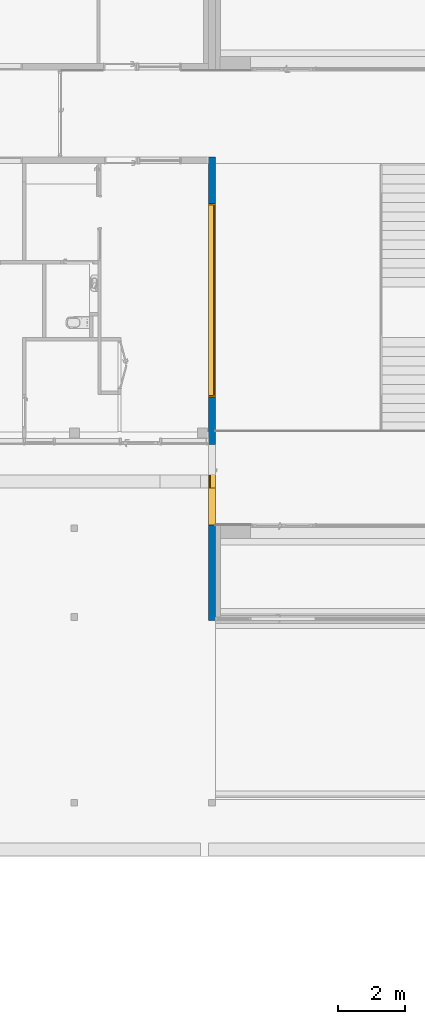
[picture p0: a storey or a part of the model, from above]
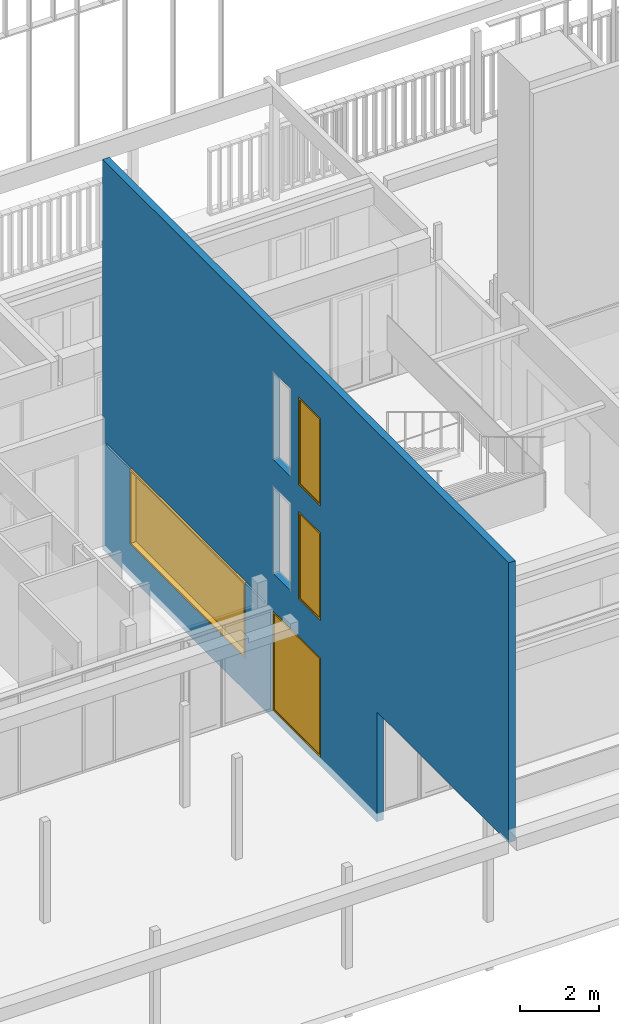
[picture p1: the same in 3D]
Properties of the parts of a building model (IFC2X3), part 1 of 7

# File
Description: ViewDefinition [CoordinationView_V2.0]
File name: Numéro du projet
Time: 2020-12-01T20:37:11
Written by: The EXPRESS Data Manager Version 5.02.0100.07 : 28 Aug 2013
Made in: 20200826_1250(x64) - Exporter 20.2.30.42 - Interface utilisateur alternative 20.2.30.42
Comment: STEP Physical File produced by: The EXPRESS Data Manager Version 5.02.0100.07 : 28 Aug 2013 * Module: EDMstepFileFactory/EDMstandAlone * Creation date: Tue Dec 01 20:37:11 2020 * Host: maison * Database: C:\Users\brice\AppData\Local\Temp\8cd85e15-69f3-489f-a026-4a7cd0e4a3fb\f1d647b6-ae90-4e52-87e3-ca53c4ba78e8\ifc * Database version: 5507 * Database creation date: Tue Dec 01 20:32:03 2020 * Schema: IFC2X3 * Model: DataRepository.ifc * Model creation date: Tue Dec 01 20:32:05 2020 * Header model: DataRepository.ifc_HeaderModel * Header model creation date: Tue Dec 01 20:32:05 2020 * EDMuser: sdai-user * EDMgroup: sdai-group * License ID and type: 5605 : Permanent license. Expiry date: * EDMstepFileFactory options: 020000

# IfcProject, Numéro du projet
LongName: Nom du projet; Phase: Etat du projet

# IfcSite, Default
RefLatitude: 48, 26, 3, 478088; RefLongitude: -4, -37, -16, -967468; RefElevation: 9400 cm

# IfcBuilding
Pset_BuildingCommon - NumberOfStoreys: 13

# IfcBuildingStorey: Niveau:Ligne du Niveau (10)
Name | LongName | Elevation (cm)
Vide Sanitaire | Vide Sanitaire | -234.674
Toiture - Infirmerie | Toiture - Infirmerie | 317.5
TR - TECHNIQUE RDC | TR - TECHNIQUE RDC | 349
TR - Cuisine/préau | TR - Cuisine/préau | 375
Toiture - Cuisine | Toiture - Cuisine | 422
Toiture - Maintenance | Toiture - Maintenance | 490
TR - TECHNIQUE R+1 | TR - TECHNIQUE R+1 | 618.22
SAM - Toiture | SAM - Toiture | 740
TR - N02 - ARCH | TR - N02 - ARCH | 774
TR - N03 - ARCH | TR - N03 - ARCH | 1230

# IfcBuildingStorey: Niveau:Ligne du Niveau 2, TR - N03
LongName: TR - N03; Elevation: 1177 cm

# IfcBuildingStorey: Niveau:Niveau 1, N00 - COO
LongName: N00 - COO; Elevation: 0 cm

# IfcSpace (202)
InteriorOrExteriorSpace: INTERNAL
Name | In | LongName | Reference | FloorCovering | WallCovering | CeilingCovering
E-10 | N00 - COO | Chaufferie | Chaufferie E-10 | Béton | Peinture lessivable
A-11 | TR - N02 - ARCH | Salle de musique | Salle de musique A-11 | Sol textile | Paroi béton lasuré+Peinture+bois acoustique | Dalle acoustique en laine de bois + retombée placo
A-14 | TR - N02 - ARCH | Dépôt Arts paratagé | Dépôt Arts paratagé A-14 | Sol linoleum | Peinture | Dalle acoustique en laine de bois
A-12 | TR - N02 - ARCH | Dépôt de musique | Dépôt de musique A-12 | Sol linoleum | Peinture | Dalle acoustique en laine de bois + retombée placo
A-13 | TR - N02 - ARCH | Salle d'arts partagés | Salle d'arts partagés A-13 | Sol linoleum | Paroi béton lasuré+Peinture+bois | Dalle acoustique en laine de bois + retombée placo
A-10 | TR - N02 - ARCH | Dépôt salle d'arts plastiques | Dépôt salle d'arts plastiques A-10 | Sol linoleum | Peinture | Dalle acoustique en laine de bois + retombée placo
A-9 | TR - N02 - ARCH | Salle d'arts plastique | Salle d'arts plastique A-9 | Sol linoleum | Paroi béton lasuré+Peinture+bois | Dalle acoustique en laine de bois + retombée placo
A-2 | TR - N02 - ARCH | Salle banalisée 1/2 groupe | Salle banalisée 1/2 groupe A-2 | Sol linoleum | Paroi béton lasuré+Peinture+bois | Dalle acoustique en laine de bois + retombée placo
E-10 | TR - N02 - ARCH | CTA 03 | CTA 03 E-10 | Béton surfacé | Peinture
A-1 | TR - N02 - ARCH | Salle banalisée 19 | Salle banalisée 19 A-1 | Sol linoleum | Paroi béton lasuré+Peinture+bois | Dalle acoustique en laine de bois + retombée placo
A-1 | TR - N02 - ARCH | Salle banalisée 18 | Salle banalisée 18 A-1 | Sol linoleum | Paroi béton lasuré+Peinture+bois | Dalle acoustique en laine de bois + retombée placo
E-10 | TR - N02 - ARCH | CTA 04 | CTA 04 E-10 | Béton surfacé | Peinture
E-10 | TR - N02 - ARCH | LT sous répartiteur 02 | LT sous répartiteur 02 E-10 | Béton | Peinture | Plafond Hygiène 60x120
E-8.6 | TR - N02 - ARCH | Local ménage 06 | Local ménage 06 E-8.6 | Carrelage | Peinture + crédence | Plafond Hygiène 60x120
B-21 | TR - N02 - ARCH | Sanitaire d'appoint 02 | Sanitaire d'appoint 02 B-21 | Carrelage | Faience toute hauteur | Plafond Hygiène 60x120
A-4 | TR - N02 - ARCH | Salle de sciences 01 | Salle de sciences 01 A-4 | Sol linoleum | Paroi béton lasuré+Peinture+bois | Dalle acoustique en laine de bois + retombée placo
A-5 | TR - N02 - ARCH | Salle de collection 01 | Salle de collection 01 A-5 | Sol linoleum | Peinture | Dalle acoustique en laine de bois + retombée placo
A-4 | TR - N02 - ARCH | Salle de sciences 02 | Salle de sciences 02 A-4 | Sol linoleum | Paroi béton lasuré+Peinture+bois | Dalle acoustique en laine de bois + retombée placo
A-4 | TR - N02 - ARCH | Salle de sciences 03 | Salle de sciences 03 A-4 | Sol linoleum | Paroi béton lasuré+Peinture+bois | Dalle acoustique en laine de bois + retombée placo
A-5 | TR - N02 - ARCH | Salle de collection 02 | Salle de collection 02 A-5 | Sol linoleum | Peinture | Dalle acoustique en laine de bois + retombée placo
A-4 | TR - N02 - ARCH | Salle de sciences 04 | Salle de sciences 04 A-4 | Sol linoleum | Paroi béton lasuré+Peinture+bois | Dalle acoustique en laine de bois + retombée placo
A-6 | TR - N02 - ARCH | Salle de technologie 02 | Salle de technologie 02 A-6 | Sol linoleum | Paroi béton lasuré+Peinture+bois | Dalle acoustique en laine de bois + retombée placo
A-6 | TR - N02 - ARCH | Salle de technologie 01 | Salle de technologie 01 A-6 | Sol linoleum | Paroi béton lasuré+Peinture+bois | Dalle acoustique en laine de bois + retombée placo
A-8 | TR - N02 - ARCH | Stockage | Stockage A-8 | Sol linoleum | Peinture | Plafond Hygiène 60x120
E-8.7 | TR - N02 - ARCH | Local ménage 07 | Local ménage 07 E-8.7 | Carrelage | Peinture + crédence | Plafond Hygiène 60x120
A-1 | Toiture - Cuisine | Salle banalisée 01 | Salle banalisée 01 A-1 | Sol linoleum | Paroi béton lasuré+Peinture+bois | Dalle acoustique en laine de bois + retombée placo
A-1 | Toiture - Cuisine | Salle banalisée 02 | Salle banalisée 02 A-1 | Sol linoleum | Paroi béton lasuré+Peinture+bois | Dalle acoustique en laine de bois + retombée placo
A-1 | Toiture - Cuisine | Salle banalisée 03 | Salle banalisée 03 A-1 | Sol linoleum | Paroi béton lasuré+Peinture+bois | Dalle acoustique en laine de bois + retombée placo
A-1 | Toiture - Cuisine | Salle banalisée 04 | Salle banalisée 04 A-1 | Sol linoleum | Paroi béton lasuré+Peinture+bois | Dalle acoustique en laine de bois + retombée placo
A-1 | Toiture - Cuisine | Salle banalisée 05 | Salle banalisée 05 A-1 | Sol linoleum | Paroi béton lasuré+Peinture+bois | Dalle acoustique en laine de bois + retombée placo
E-8.4 | Toiture - Cuisine | Local ménage 04 | Local ménage 04 E-8.4 | Carrelage | Peinture + crédence | Plafond Hygiène 60x120
B-21 | Toiture - Cuisine | Sanit. d'appoint 01 | Sanit. d'appoint 01 B-21 | Carrelage | Peinture | Plafond Hygiène 60x120
E-10 | Toiture - Cuisine | CTA 02 | CTA 02 E-10 | Béton surfacé | Peinture
A-1 | Toiture - Cuisine | Salle banalisée 07 | Salle banalisée 07 A-1 | Sol linoleum | Paroi béton lasuré+Peinture+bois | Dalle acoustique en laine de bois + retombée placo
A-1 | Toiture - Cuisine | Salle banalisée 06 | Salle banalisée 06 A-1 | Sol linoleum | Paroi béton lasuré+Peinture+bois | Dalle acoustique en laine de bois + retombée placo
E-6 | Toiture - Cuisine | Stockage général | Stockage général E-6 | Béton surfacé | Peinture
A-3 | Toiture - Cuisine | Dépôt 01 | Dépôt 01 A-3 | Sol linoleum | Peinture | Plafond Hygiène 60x120
A-1 | Toiture - Cuisine | Salle banalisée 08 | Salle banalisée 08 A-1 | Sol linoleum | Paroi béton lasuré+Peinture+bois | Dalle acoustique en laine de bois + retombée placo
A-1 | Toiture - Cuisine | Salle banalisée 09 | Salle banalisée 09 A-1 | Sol linoleum | Paroi béton lasuré+Peinture+bois | Dalle acoustique en laine de bois + retombée placo
A-1 | Toiture - Cuisine | Salle banalisée 10 | Salle banalisée 10 A-1 | Sol linoleum | Paroi béton lasuré+Peinture+bois | Dalle acoustique en laine de bois + retombée placo
A-1 | Toiture - Cuisine | Salle banalisée 11 | Salle banalisée 11 A-1 | Linoleum | Paroi béton lasuré+Peinture+bois | Dalle acoustique en laine de bois + retombée placo
A-1 | Toiture - Cuisine | Salle banalisée 12 | Salle banalisée 12 A-1 | Sol linoleum | Paroi béton lasuré+Peinture+bois | Dalle acoustique en laine de bois + retombée placo
A-1 | Toiture - Cuisine | Salle banalisée 13 | Salle banalisée 13 A-1 | Sol linoleum | Paroi béton lasuré+Peinture+bois | Dalle acoustique en laine de bois + retombée placo
A-1 | Toiture - Cuisine | Salle banalisée 17 | Salle banalisée 17 A-1 | Sol linoleum | Paroi béton lasuré+Peinture+bois | Dalle acoustique en laine de bois + retombée placo
A-1 | Toiture - Cuisine | Salle banalisée 16 | Salle banalisée 16 A-1 | Sol linoleum | Paroi béton lasuré+Peinture+bois | Dalle acoustique en laine de bois + retombée placo
A-1 | Toiture - Cuisine | Salle banalisée 15 | Salle banalisée 15 A-1 | Sol linoleum | Paroi béton lasuré+Peinture+bois | Dalle acoustique en laine de bois + retombée placo
A-1 | Toiture - Cuisine | Salle banalisée 14 | Salle banalisée 14 A-1 | Sol linoleum | Paroi béton lasuré+Peinture+bois | Dalle acoustique en laine de bois + retombée placo
A-3 | Toiture - Cuisine | Dépôt 02 | Dépôt 02 A-3 | Sol linoleum | Peinture | Plafond Hygiène 60x120
A-3 | Toiture - Cuisine | Dépôt 03 | Dépôt 03 A-3 | Sol linoleum | Peinture | Plafond Hygiène 60x120
E-8.5 | Toiture - Cuisine | Local ménage 05 | Local ménage 05 E-8.5 | Carrelage | Peinture + crédence | Plafond Hygiène 60x120
B-1 | N00 - COO | Salle de documentation | Salle de documentation B-1 | Sol textile | Paroi béton lasuré+peinture+bois | Rigitone
B-18 | N00 - COO | Foyer - Zone bruyante | Foyer - Zone bruyante B-18 | Sol béton quartz | Paroi béton lasuré+peinture+bois | Rigitone
B-3 | N00 - COO | Dépôt | Dépôt B-3 | Sol linoleum | Peinture | Dalle acoustique en laine de bois + BA13
C-4 | N00 - COO | Petite salle de réunion | Petite salle de réunion C-4 | Sol textile | Paroi béton lasuré+peinture+bois | Rigitone
C-14 | N00 - COO | Archives 01 | Archives 01 C-14 | Béton | Peinture blanche
B-6 | N00 - COO | Grande salle de permanence | Grande salle de permanence B-6 | Sol béton quartz | Paroi béton lasuré + Peinture | Dalle acoustique en laine de bois + BA13
B-7 | N00 - COO | Petite salle de permanence | Petite salle de permanence B-7 | Sol béton quartz | Paroi béton lasuré + Peinture | Dalle acoustique en laine de bois + BA13
2 x B-10 | N00 - COO | Accueil enfants malades | Accueil enfants malades B-10 | Sol textile | Peinture lessivable | Dalle acoustique en laine de bois + BA13
B-5 | N00 - COO | Bureau CPE | Bureau CPE B-5 | Sol textile | Peinture + bois pour affichage | Dalle acoustique en laine de bois + BA13
B-10 | N00 - COO | Sanitaires | Sanitaires B-10 | Carrelage | Faïence toute hauteur | Dalle acoustique en laine de bois + BA13
C-9 | N00 - COO | Secrétaire administrative | Secrétaire administrative C-9 | Sol textile | Peinture + bois pour affichage | Dalle acoustique en laine de bois + BA13
C-7 | N00 - COO | Principal adjoint | Principal adjoint C-7 | Sol textile | Peinture + bois pour affichage | Dalle acoustique en laine de bois + BA13
C-6 | N00 - COO | Principal | Principal C-6 | Sol textile | Peinture + bois pour affichage | Dalle acoustique en laine de bois + BA13
C-10 | N00 - COO | Secrétaire gestion & stagiaire | Secrétaire gestion & stagiaire C-10 | Sol textile | Peinture + bois pour affichage | Dalle acoustique en laine de bois + BA13
C-14 | N00 - COO | Archives 02 | Archives 02 C-14 | Sol linoleum | Paroi béton lasuré + Peinture | Dalle acoustique en laine de bois + BA13
E-11 | N00 - COO | Local serveur | Local serveur E-11 | Sol linoleum | Peinture | Dalle acoustique en laine de bois + BA13
C-11 | N00 - COO | Petite salle de réunion | Petite salle de réunion C-11 | Sol textile | Peinture + bois pour affichage | Dalle acoustique en laine de bois + BA13
C-12 | N00 - COO | Grande salle de réunion | Grande salle de réunion C-12 | Sol textile | Peinture + bois pour affichage | Rigitone
C-16 | N00 - COO | Local APE | Local APE C-16 | Sol textile | Peinture + bois pour affichage | Dalle acoustique en laine de bois + BA13
C-15 | N00 - COO | Rencontre parents / professeurs | Rencontre parents / professeurs C-15 | Sol textile | Peinture + bois pour affichage | Dalle acoustique en laine de bois + BA13
C-8 | N00 - COO | Gestionnaire | Gestionnaire C-8 | Sol textile | Peinture + bois pour affichage | Dalle acoustique en laine de bois + BA13
C-17 | N00 - COO | Sanit. 02 | Sanit. 02 C-17 | Carrelage | Faîence toute hauteur | Dalle acoustique en laine de bois + BA13
C-17 | N00 - COO | Sanit. 01 | Sanit. 01 C-17 | Carrelage | Faïence toute hauteur | Dalle acoustique en laine de bois + BA13
B-16 | N00 - COO | Attente | Attente B-16 | Sol textile | Peinture + bois pour affichage | Dalle acoustique en laine de bois + BA13
B-17 | N00 - COO | Sanitaires | Sanitaires B-17 | Carrelage | Faïence toute hauteur | Dalle acoustique en laine de bois + BA13
B-13 | N00 - COO | Salle de repos | Salle de repos B-13 | Sol linoleum | Peinture lessivable | Dalle acoustique en laine de bois + BA13
B-12 | N00 - COO | Bureau infirmier & espace de consultation | Bureau infirmier & espace de consultation B-12 | Sol linoleum | Peinture lessivable + crédence | Dalle acoustique en laine de bois + BA13
B-11 | N00 - COO | Bureau médecin | Bureau médecin B-11 | Sol linoleum | Peinture lessivable + crédence | Dalle acoustique en laine de bois + BA13
B-14 | N00 - COO | Bureau AS | Bureau AS B-14 | Sol textile | Peinture lessivable | Dalle acoustique en laine de bois + BA13
B-9 | N00 - COO | Dépôt grande salle de permanence | Dépôt grande salle de permanence B-9 | Béton quartz | Peinture | Dalle acoustique en laine de bois + BA13
E-10 | N00 - COO | LT / CTA 01 | LT / CTA 01 E-10 | Sol béton quartz | Peinture
F-1 | N00 - COO | SAS 05 | SAS 05 F-1 | Sol béton quartz | Paroie béton + Paroie BA 13 | Dalle en métal perforé
E-4 | N00 - COO | Stockage matériaux | Stockage matériaux E-4 | Béton quartz | Peinture lessivable | Dalle acoustique en laine de bois + BA13
E-10 | N00 - COO | TGBT | TGBT E-10 | Béton quartz | Peinture lessivable
E-1 | N00 - COO | Atelier agent de maintenance | Atelier agent de maintenance E-1 | Béton quartz | Peinture lessivable + crédence | Dalle acoustique en laine de bois + BA13
E-3 | N00 - COO | Vestiaire/Douche agent de maintenance | Vestiaire/Douche agent de maintenance E-3 | Carrelage | Faïence toute hauteur | Dalles Hygène 60x120
E-5 + E7 | N00 - COO | Garage / Stockage matériel espace verts | Garage / Stockage matériel espace verts E-5 + E7 | Béton quartz | Peinture lessivable
F-1 | N00 - COO | Circ. 04 - vestiaires élèves | Circ. 04 - vestiaires élèves F-1 | Sol béton quartz | Peinture lessivable
F-1 | N00 - COO | Circ. 05 - vestaires personnel | Circ. 05 - vestaires personnel F-1 | Béton quartz | Peinture lessivable | Dalles Couloir acoustiques
D-11 | N00 - COO | Salle de détente du personnel | Salle de détente du personnel D-11 | Béton quartz + sol textile | Peinture + crédence + bois
D-10 | N00 - COO | Local lingerie | Local lingerie D-10 | Carrelage | Faïence toute hauteur | Plafond Hygiène 60x120
A-17 | N00 - COO | Dépôt petit matériel | Dépôt petit matériel A-17 | Béton Quartz | Peinture lessivable | Plafond Hygiène 60x120
E-8.2 | N00 - COO | Local ménage / vidoire 02 | Local ménage / vidoire 02 E-8.2 | Carrelage | Peinture lessivable + crédence | Plafond Hygiène 60x120
E-9 | N00 - COO | Local produits d'entretien | Local produits d'entretien E-9 | Résine | Faïence toute hauteur
D-17 | N00 - COO | Réserve alimentaire sèche | Réserve alimentaire sèche D-17 | Résine | Faïence toute hauteur | Plafond Hygiène 60x120
D-13 | N00 - COO | Bureau magasinier | Bureau magasinier D-13 | Résine | Faïence toute hauteur | Plafond Hygiène 60x120
D-14 | N00 - COO | Local déchets | Local déchets D-14 | Résine | Faïence toute hauteur | Plafond Hygiène 60x120
D-16 | N00 - COO | Réserve petit matériel | Réserve petit matériel D-16 | Résine | Faïence toute hauteur | Plafond Hygiène 60x120
D-18 | N00 - COO | Réserve murisserie tubercules | Réserve murisserie tubercules D-18 | Résine | Faïence toute hauteur | Plafond Hygiène 60x120
D-23 / D-23 | N00 - COO | Déconditionnement / Légumerie | Déconditionnement / Légumerie D-23 / D-23 | Résine | Faïence toute hauteur | Plafond Hygiène 60x120
D-31 | N00 - COO | Stockage vaisselle propre | Stockage vaisselle propre D-31 | Résine | Faïence toute hauteur | Plafond Hygiène 60x120
D-6 | N00 - COO | Local ménage / entretien | Local ménage / entretien D-6 | Résine | Peinture lessivable | Plafond Hygiène 60x120
D-7 | N00 - COO | Salle à manger commensaux | Salle à manger commensaux D-7 | Sol textile | Peinture lessivable + bois | Rigitone
F-1 | N00 - COO | SAS 06 | SAS 06 F-1 | Tapis de sol | Peinture lessivable | Dalle béton brut
C-1 | N00 - COO | Salle des professeurs | Salle des professeurs C-1 | Sol textile + parquet | Paroi béton lasuré+peinture+bois | Rigitone
C-2 | N00 - COO | Box de travail individuel 04 | Box de travail individuel 04 C-2 | Sol textile | Peinture | Rigitone
F-1 | N00 - COO | SAS 01 | SAS 01 F-1 | Sol textile | Peinture + bois affichage | Rigitone
C-3 | N00 - COO | Reprographie | Reprographie C-3 | Sol textile | Paroi béton + Peinture+bois | Rigitone
F-1 | N00 - COO | Circ. 02 - salle des profs | Circ. 02 - salle des profs F-1 | Sol textile | Paroie BA 13 | Rigitone
C-2 | N00 - COO | Box de travail individuel 03 | Box de travail individuel 03 C-2 | Sol textile | Peinture | Rigitone
C-2 | N00 - COO | Box de travail individuel 02 | Box de travail individuel 02 C-2 | Sol textile | Peinture | Rigitone
C-2 | N00 - COO | Box de travail individuel 01 | Box de travail individuel 01 C-2 | Sol textile | Peinture | Rigitone
F-1 | N00 - COO | SAS 02 | SAS 02 F-1 | Sol textile | Peinture + bois affichage | Rigitone
F-1 | N00 - COO | Circ. 03 - administration | Circ. 03 - administration F-1 | Sol textile | Paroie béton + Paroie BA 13 | Dalle couloir acoustiques
C-13 | N00 - COO | Reprographie | Reprographie C-13 | Sol textile | Paroi béton lasuré + Peinture | Dalle acoustique en laine de bois + BA13
D-29 | N00 - COO | Laverie vaisselle | Laverie vaisselle D-29 | Résine | faience toute hauteur | Plafond Hygiène 60x120
D-1 | N00 - COO | Hall d'accueil | Hall d'accueil D-1 | Tapis de sol | Peinture lessivable + bois | Rigitone
D-28 | N00 - COO | Plonge batterie propre | Plonge batterie propre D-28 | Résine | Faïence toute hauteur | Plafond Hygiène 60x120
F-1 | N00 - COO | Circ. 08 - local ménage self | Circ. 08 - local ménage self F-1 | Résine | Peinture lessivable | Plafond Hygiène 60x120
D-3 | N00 - COO | Distribution | Distribution D-3 | Résine | faïence toute hauteur | Plafond Hygiène 60x120
D-4 | N00 - COO | Circulation devant ligne de self | Circulation devant ligne de self D-4 | Résine | Peinture lessivable / faïence | Rigitone
F-1 | N00 - COO | Circ. 06 - self | Circ. 06 - self F-1 | Résine | Faïence toute hauteur | Plafond Hygiène 60x120
D-12 | N00 - COO | Hall de réception | Hall de réception D-12 | Résine | Faïence toute hauteur | Plafond Hygiène 60x120
F-1 | N00 - COO | Circ. 07 - local poubelle self | Circ. 07 - local poubelle self F-1 | Résine | Faïence toute hauteur | Plafond Hygiène 60x120
D-8 | N00 - COO | Vestiaire sanitaires personnel hommes | Vestiaire sanitaires personnel hommes D-8 | Carrelage | Faïence toute hauteur | Plafond Hygiène 60x120
D-9 | N00 - COO | Vestaires sanitaires personnel femmes | Vestaires sanitaires personnel femmes D-9 | Carrelage | Faïence toute hauteur | Plafond Hygiène 60x120
A-15 | N00 - COO | Bureau vestiaire enseignants | Bureau vestiaire enseignants A-15 | Carrelage | Peinture lessivable + crédence | Dalle acoustique en laine de bois + BA13
E-8.3 | N00 - COO | Local ménage / vidoire 03 | Local ménage / vidoire 03 E-8.3 | Carrelage | Faïence toute hauteur | Plafond Hygiène 60x120
D-2 | N00 - COO | Sanitaires 02 | Sanitaires 02 D-2 | Carrelage | Faïence toute hauteur | Plafond Hygiène 60x120
D-2 | N00 - COO | Sanitaires 01 | Sanitaires 01 D-2 | Carrelage | Faïence toute hauteur | Plafond Hygiène 60x120
B-20 | N00 - COO | Bloc sanitaire principal 02 | Bloc sanitaire principal 02 B-20 | Carrelage | Faïence toute hauteur
B-20 | N00 - COO | Bloc sanitaire principal 01 | Bloc sanitaire principal 01 B-20 | Carrelage | Faïence toute hauteur | Plafond Hygiène 60x120
D-19 | N00 - COO | Chambre froide BOF -0/3°C | Chambre froide BOF -0/3°C D-19 | Panneaux isothermes | Panneaux isothermes
D-21 | N00 - COO | Chambre froide viandes -0/3°C | Chambre froide viandes -0/3°C D-21 | Panneaux isothermes | Panneaux isothermes
D-20 | N00 - COO | Chambre froide surgelés -18°C | Chambre froide surgelés -18°C D-20 | Panneaux isothermes | Panneaux isothermes
D-20 | N00 - COO | Chambre froide fruits & légumes 3/6°C | Chambre froide fruits & légumes 3/6°C D-20 | Panneaux isothermes | Panneaux isothermes
F-1 | Toiture - Cuisine | Circ. 09 - Couloir R+1 | Circ. 09 - Couloir R+1 F-1 | Sol linoleum | Parois béton lasuré | Mono acoustique
F-1 | TR - N02 - ARCH | Circ.10 - Couloir R+2 | Circ.10 - Couloir R+2 F-1 | Sol linoleum | Parois béton lasuré | Mono acoustique
A-7 | TR - N02 - ARCH | Espace de préparation 02 | Espace de préparation 02 A-7 | Sol linoleum | Peinture + Panneaux acoustiques | Dalle acoustique en laine de bois + retombée placo
A-7 | TR - N02 - ARCH | Espace de préparation 01 | Espace de préparation 01 A-7 | Sol linoleum | Peinture + Panneaux acoustiques | Dalle acoustique en laine de bois + retombée placo
C-5 | N00 - COO | Sanitaires H.02 | Sanitaires H.02 C-5 | Carrelage | Faïence toute hauteur | Dalle acoustique en laine de bois + BA13
C-5 | N00 - COO | Sanitaires F. 01 | Sanitaires F. 01 C-5 | Carrelage | Faïence toute hauteur | Dalle acoustique en laine de bois + BA13
F-1 | N00 - COO | Circulation RDC aile Ouest | Circulation RDC aile Ouest F-1 | Sol béton quartz | Paroi béton lasuré + bois affichage | Dalle en métal perforé
F-1 | N00 - COO | SAS 04 | SAS 04 F-1 | Tapis de sol | Paroi béton lasuré + bois affichage | Dalle en métal perforé
F-1 | N00 - COO | SAS 03 | SAS 03 F-1 | Tapis de sol | Paroi béton lasuré + bois affichage | Dalle acoustique en laine de bois
F-1 | TR - N02 - ARCH | Palier - R+2 - Centre | Palier - R+2 - Centre F-1 | Sol linoleum | Peinture
F-1 | TR - N02 - ARCH | Palier - R+2- Aile Ouest | Palier - R+2- Aile Ouest F-1 | Sol linoleum | Peinture | Rigitone
F-1 | Toiture - Cuisine | Palier - R+1 - Aile Est | Palier - R+1 - Aile Est F-1 | Sol linoleum | Peinture | Rigitone
F-1 | Toiture - Cuisine | Palier - R+1 - Centre | Palier - R+1 - Centre F-1 | Sol linoleum | Peinture
F-1 | Toiture - Cuisine | Palier - R+1 - Aile Ouest | Palier - R+1 - Aile Ouest F-1 | Sol linoleum | Peinture | Rigitone
F-1 | TR - N02 - ARCH | Palier - R+2 - Aile Est | Palier - R+2 - Aile Est F-1 | Sol linoleum | Peinture | Rigitone
B-18 | N00 - COO | Foyer- Zone calme | Foyer- Zone calme B-18 | Sol textile | Paroi béton lasuré+peinture+bois | Rigitone
F-1 | N00 - COO | Palier RDC -Aile Est | Palier RDC -Aile Est F-1 | Sol béton quartz | Peinture
E-8.1 | N00 - COO | Local ménage 01 | Local ménage 01 E-8.1 | Carrelage | peinture lessivable + crédence
A-16 | N00 - COO | Douche 01 | Douche 01 A-16 | Carrelage | Faïence toute hauteur | Plafond Hygiène 60x120
A-16 | N00 - COO | Vestiaires élèves 01 | Vestiaires élèves 01 A-16 | Carrelage | Peinture lessivable | Dalle acoustique en laine de bois + BA13
A-16 | N00 - COO | Vestiaires élèves 02 | Vestiaires élèves 02 A-16 | Carrelage | Peinture lessivable | Dalle acoustique en laine de bois + BA13
A-16 | N00 - COO | Douche 02 | Douche 02 A-16 | Carrelage | Faïence toute hauteur | Plafond Hygiène 60x120
A-15 | N00 - COO | Sanitaire bureau - vestaire enseignants | Sanitaire bureau - vestaire enseignants A-15 | Carrelage | Faïence toute hauteur | Plafond Hygiène 60x120
B-15 | N00 - COO | SESSAD / COSPY | SESSAD / COSPY B-15 | Sol textile | Peinture lessivable + crédence | Dalle acoustique en laine de bois + BA13
F-1 | N00 - COO | Circulation 11- Infirmerie | Circulation 11- Infirmerie F-1 | Linoleum | Peinture
B-2 | N00 - COO | Espace de travail petit groupe | Espace de travail petit groupe B-2 | sol textile | Peinture | Rigitone
E-2 | N00 - COO | Burau agent de maintenance | Burau agent de maintenance E-2 | Béton Quartz | Peinture lessivable | Dalle acoustique en laine de bois + BA13
D-30 | N00 - COO | Dépose plateaux | Dépose plateaux D-30 | Sol linoleum | Peinture lessivable + bois | Rigitone
G-3 | N00 - COO | Pièce | Pièce G-3
G-4 | N00 - COO | Pièce | Pièce G-4
G-5 | N00 - COO | Pièce | Pièce G-5
G-6 | N00 - COO | Pièce | Pièce G-6
G-7 | N00 - COO | Pièce | Pièce G-7
G-8 | N00 - COO | Pièce | Pièce G-8
Placard TGBT | N00 - COO | D-32 | D-32 Placard TGBT
D-15 | N00 - COO | PL- produits d'entretien | PL- produits d'entretien D-15
F-1 | N00 - COO | Palier - RDC - Aile Ouest | Palier - RDC - Aile Ouest F-1 | Sol béton quartz | Paroi béton lasuré + Peinture | BA 13
G-13 | N00 - COO | Pièce | Pièce G-13
F-1 | N00 - COO | Palier RDC- Centre | Palier RDC- Centre F-1 | Béton Quartz | Paroi béton lasuré + Peinture
G-16 | N00 - COO | Pièce | Pièce G-16
E-10 | N00 - COO | E-10 | E-10 E-10
G-21 | N00 - COO | Pièce | Pièce G-21
G-22 | N00 - COO | Pièce | Pièce G-22
G-26 | N00 - COO | Pièce | Pièce G-26
D-5 | N00 - COO | Salle à manger - 226 à 238 places | Salle à manger - 226 à 238 places D-5 | Sol textile | Parois béton lasuré | Rigitone
G-28 | N00 - COO | Pièce | Pièce G-28
G-35 | N00 - COO | Pièce | Pièce G-35
D-27 | N00 - COO | Stockage batterie propre | Stockage batterie propre D-27 | Résine | Faience toute hauteur
F-1 | TR - N02 - ARCH | Circulation Aile Ouest - Couloir R+2 | Circulation Aile Ouest - Couloir R+2 F-1 | Sol linoleum | Parois béton lasuré | Dalles couloir en métal perforé
F-1 | TR - N02 - ARCH | Circulation Aile Est - Couloir R+2 | Circulation Aile Est - Couloir R+2 F-1 | Sol linoleum | Parois béton lasuré | Dalles couloir en métal perforé
F-1 | Toiture - Cuisine | Circulation Aile Ouest - Couloir R+1 | Circulation Aile Ouest - Couloir R+1 F-1 | Sol linoleum | Parois béton lasuré | Dalles couloir en métal perforé
F-1 | Toiture - Cuisine | Circulation Aile Est - Couloir R+1 | Circulation Aile Est - Couloir R+1 F-1 | Sol linoleum | Parois béton lasuré | Dalles couloir en métal perforé
B-22 | N00 - COO | Hall d'accueil | Hall d'accueil B-22 | Sol béton quartz | Paroi béton + Peinture+bois | Mono acoustique
F-1 | N00 - COO | Circulation RDC - Aile Est | Circulation RDC - Aile Est F-1 | Sol béton quartz | Paroi béton lasuré+Peinture+bois acoustique | Dalle en métal perforé
H-1 | N00 - COO | Préau | Préau H-1 | Béton désactivé | - | Dalle acoustique en laine de bois + dalle béton brut
H-2 / H-4 | N00 - COO | Abri vélo + Parvis couvert | Abri vélo + Parvis couvert H-2 / H-4 | Béton désactivé | - | Béton brut
D-25 | N00 - COO | Cuisson | Cuisson D-25 | Résine | Faience toute hauteur | Plafond Hygiène 60x120
D-24 | N00 - COO | Préparation froides -8/12°C | Préparation froides -8/12°C D-24 | Résine | Faience toute hauteur | Plafond Hygiène 60x120
D-26 | N00 - COO | Armoire froide à chariot | Armoire froide à chariot D-26 | Résine | Panneaux isothermes | Plafond isotherme
E-10 | N00 - COO | Aire de présentation des déchets | Aire de présentation des déchets E-10 | Enrobé | Béton lasuré
F-1 | TR - N02 - ARCH | Palier intermediaire - R+2 - Centre | Palier intermediaire - R+2 - Centre F-1 | Sol linoleum | Peinture
E. 8.1 | N00 - COO | Local ménage 01 | Local ménage 01 E. 8.1 | Carrelage | Peinture lessivable + crédence
B-5.2 | N00 - COO | Salle d'attente CPE & bureau stagiaire | Salle d'attente CPE & bureau stagiaire B-5.2 | Sol béton quartz | Peinture lessivable | Dalle acoustique en laine de bois + BA13
B-4 | N00 - COO | Bureau ASEN | Bureau ASEN B-4 | béton quartz + Sol textile | Peinture + crédence + bois pour affichage | Dalle acoustique en laine de bois + BA13
E-5.2 | N00 - COO | Local produit dangereux (exterieur) | Local produit dangereux (exterieur) E-5.2 | Béton Quartz | Peinture lessivable

# IfcBeam: SR-10x24 (6)
In: N00 - COO
Type - PredefinedType: BEAM
Type - Pset_BeamCommon - IsExternal: no; Reference: SR-10x24
Type - Pset_QuantityTakeOff - Reference: SR-10x24
Type - Pset_ReinforcementBarPitchOfBeam - Reference: SR-10x24
Material: Bois - Bois de construction de dimensions courantes; Group: Groupe de modèles:structure self:1658767
Pset_BeamCommon - Slope: 0 deg
Pset_QuantityTakeOff - sets with these values: 2
Name (Poutre - Bois de construction de dimensions courantes:SR-10x24:...) | Span (cm)
1650626 | 3283.1
1650750 | 3283.1
1650790 | 3296.3
1650803 | 3301.6
1650816 | 2210
1650829 | 2240.5

# IfcBeam: SR-12x92 (7)
In: N00 - COO
Type - PredefinedType: BEAM
Type - Pset_BeamCommon - IsExternal: no; Reference: SR-12x92
Type - Pset_QuantityTakeOff - Reference: SR-12x92
Type - Pset_ReinforcementBarPitchOfBeam - Reference: SR-12x92
Material: Bois - Bois de construction de dimensions courantes; Group: Groupe de modèles:structure self:1658767
Pset_BeamCommon - Span: 1321 cm; Slope: 3 deg
Pset_QuantityTakeOff - sets with these values: 2
Name (Poutre - Bois de construction de dimensions courantes:SR-12x92:...)
1649632
1649638
1649678
1649719
1649764
1649812
1674546

# IfcBuildingElementProxy: Menneau extrémité façade (8)
Type - Material: Aluminium
Type - Pset_BuildingElementProxyCommon - Reference: Menneau extrémité façade
Type - Pset_QuantityTakeOff - Reference: Menneau extrémité façade
Pset_BuildingElementProxyCommon - sets with these values: 2
Name | In
Menneau extrémité façade:Menneau extrémité façade:908934 | N00 - COO
Menneau extrémité façade1:Menneau extrémité façade:909284 | H-2 / H-4
Menneau extrémité façade2:Menneau extrémité façade:909435 | Toiture - Infirmerie
Menneau extrémité façade3:Menneau extrémité façade:909519 | Toiture - Infirmerie
Menneau extrémité façade4:Menneau extrémité façade:910070 | TR - Cuisine/préau
Menneau extrémité façade5:Menneau extrémité façade:910796 | Toiture - Infirmerie
Menneau extrémité façade6:Menneau extrémité façade:910934 | Toiture - Infirmerie
Menneau extrémité façade7:Menneau extrémité façade:1426539 | Toiture - Infirmerie

# IfcBuildingElementProxy: Tube métal épine (4)
Type - Material: Alu
Type - Pset_BuildingElementProxyCommon - Reference: Tube métal épine
Type - Pset_QuantityTakeOff - Reference: Tube métal épine
Pset_BuildingElementProxyCommon - sets with these values: 2
Name (Tube support façade:Tube métal épine:...) | In
670521 | N00 - COO
674484 | Toiture - Cuisine
675312 | Toiture - Cuisine
675313 | Toiture - Cuisine

# IfcBuildingElementProxy: Tube métal épine - Façade Sud (29)
In: Toiture - Cuisine
Type - Material: Alu
Type - Pset_BuildingElementProxyCommon - Reference: Tube métal épine - Façade Sud
Type - Pset_QuantityTakeOff - Reference: Tube métal épine - Façade Sud
Pset_BuildingElementProxyCommon - sets with these values: 2
Name (Tube support façade:Tube métal épine - Façade Sud:...)
689900
689908
689909
924210
924230
924231
924232
924233
924270
924271
924272
924273
924290
924291
924292
924293
924294
924295
924296
924297
924308
924309
924310
924311
924312
924313
924314
924315
924333

# IfcColumn: 200mm x 200mm (94)
Type - PredefinedType: COLUMN
Type - Pset_ColumnCommon - IsExternal: no; LoadBearing: yes; Reference: 200mm x 200mm
Type - Pset_QuantityTakeOff - Reference: 200mm x 200mm
Type - Pset_ReinforcementBarPitchOfColumn - Reference: 200mm x 200mm
Material: Maçonnerie - Béton coulé sur place
Pset_ColumnCommon - Slope: 0 deg
Pset_QuantityTakeOff - sets with these values: 2
Name (Poteau béton - Carré:200mm x 200mm:...) | In
176126 | N00 - COO
176384 | N00 - COO
176525 | N00 - COO
176638 | N00 - COO
176711 | N00 - COO
176848 | N00 - COO
177143 | N00 - COO
177210 | N00 - COO
177317 | N00 - COO
177414 | N00 - COO
177830 | N00 - COO
177989 | N00 - COO
178090 | N00 - COO
178201 | N00 - COO
178330 | N00 - COO
178443 | N00 - COO
178546 | N00 - COO
178669 | N00 - COO
178920 | N00 - COO
179045 | N00 - COO
179152 | N00 - COO
179255 | N00 - COO
179432 | N00 - COO
179669 | N00 - COO
179744 | N00 - COO
179813 | N00 - COO
675511 | TR - N02 - ARCH
675513 | TR - N02 - ARCH
675515 | TR - N02 - ARCH
675517 | TR - N02 - ARCH
675519 | TR - N02 - ARCH
675521 | TR - N02 - ARCH
675523 | TR - N02 - ARCH
675525 | TR - N02 - ARCH
675527 | TR - N02 - ARCH
675529 | TR - N02 - ARCH
675531 | TR - N02 - ARCH
675593 | TR - N02 - ARCH
675599 | TR - N02 - ARCH
675653 | TR - N02 - ARCH
675657 | TR - N02 - ARCH
675661 | TR - N02 - ARCH
675665 | TR - N02 - ARCH
675669 | TR - N02 - ARCH
675673 | TR - N02 - ARCH
675677 | TR - N02 - ARCH
675681 | TR - N02 - ARCH
675685 | TR - N02 - ARCH
675689 | TR - N02 - ARCH
675693 | TR - N02 - ARCH
766957 | Vide Sanitaire
767107 | Vide Sanitaire
767201 | Vide Sanitaire
767310 | Vide Sanitaire
768150 | N00 - COO
768209 | N00 - COO
777375 | N00 - COO
881909 | TR - N02 - ARCH
898878 | N00 - COO
898919 | N00 - COO
917694 | N00 - COO
917696 | N00 - COO
917698 | N00 - COO
917700 | N00 - COO
917702 | N00 - COO
917704 | N00 - COO
917706 | N00 - COO
1071278 | N00 - COO
1085624 | N00 - COO
1099891 | N00 - COO
1620231 | Vide Sanitaire
1620259 | Vide Sanitaire
1620287 | Vide Sanitaire
1620897 | Vide Sanitaire
1620901 | Vide Sanitaire
1620905 | Vide Sanitaire
1620909 | Vide Sanitaire
1621068 | Vide Sanitaire
1621089 | Vide Sanitaire
1621110 | Vide Sanitaire
1621131 | Vide Sanitaire
1621293 | Vide Sanitaire
1621295 | Vide Sanitaire
1621297 | Vide Sanitaire
1621299 | Vide Sanitaire
1621345 | Vide Sanitaire
1621347 | Vide Sanitaire
1621427 | Vide Sanitaire
1621507 | Vide Sanitaire
1621622 | Vide Sanitaire
1621637 | Vide Sanitaire
1621804 | Vide Sanitaire
1621865 | Vide Sanitaire
1621918 | Vide Sanitaire

# IfcColumn: 250mm x 250mm (24)
In: Toiture - Cuisine
Type - PredefinedType: COLUMN
Type - Pset_ColumnCommon - IsExternal: no; LoadBearing: yes; Reference: 250mm x 250mm
Type - Pset_QuantityTakeOff - Reference: 250mm x 250mm
Type - Pset_ReinforcementBarPitchOfColumn - Reference: 250mm x 250mm
Material: Maçonnerie - Béton coulé sur place
Pset_ColumnCommon - Slope: 0 deg
Pset_QuantityTakeOff - sets with these values: 2
Name (Poteau béton - Carré:250mm x 250mm:...)
173751
174188
174449
174649
174771
175137
675463
675465
675467
675469
675471
675473
675475
675477
675479
675481
675581
675587
675611
675617
675623
675629
675635
881572

# IfcColumn: 300mm x 300mm (11)
In: N00 - COO
Type - PredefinedType: COLUMN
Type - Pset_ColumnCommon - IsExternal: no; Reference: 300mm x 300mm; LoadBearing: yes
Type - Pset_QuantityTakeOff - Reference: 300mm x 300mm
Type - Pset_ReinforcementBarPitchOfColumn - Reference: 300mm x 300mm
Material: Maçonnerie - Béton coulé sur place
Pset_ColumnCommon - Slope: 0 deg
Pset_QuantityTakeOff - sets with these values: 2
Name (Poteau béton - Carré:300mm x 300mm:...)
134282
134399
134514
134603
134718
135776
136065
136162
136231
136276
881834

# IfcCovering: Plafond composé:11-Plafond 1BA13 (148)
Type - PredefinedType: CEILING
Type - Pset_CoveringCommon - Reference: 11-Plafond 1BA13; TotalThickness: 7 cm
Type - Pset_QuantityTakeOff - Reference: 11-Plafond 1BA13
Material: 00 - VIDE D'AIR 5.7 cm, 01 - Enduit/Plâtre - faux plafonds 1.3 cm
Pset_CoveringCommon - Finish: 01 - Enduit/Plâtre - faux plafonds;
Name (Plafond composé:11-Plafond 1BA13:...) | In
465386 | N00 - COO
465394 | E-5.2
465402 | E-2
465474 | N00 - COO
465482 | E-4
465490 | N00 - COO
465917 | B-12
465925 | B-13
465941 | B-11
465968 | B-14
465976 | N00 - COO
465995 | C-12
466003 | C-11
466011 | E-11
466020 | C-15
466028 | C-16
466040 | C-8
466048 | C-10
466056 | C-6
466064 | C-9
466072 | C-7
466080 | C-14
466314 | N00 - COO
467387 | C-17
467395 | C-17
467410 | B-9
467418 | B-9
467440 | N00 - COO
467477 | N00 - COO
470079 | B-3
470105 | C-4
470113 | N00 - COO
470123 | N00 - COO
470131 | C-5
470148 | C-5
470156 | C-14
470180 | N00 - COO
470744 | N00 - COO
472986 | N00 - COO
474956 | D-17
474964 | N00 - COO
474980 | N00 - COO
474988 | E-9
474996 | A-17
475004 | E-8.2
475012 | B-20
475020 | B-20
475028 | B-20
475036 | B-20
475044 | B-20
475052 | B-20
475060 | B-20
475068 | E-8.3
475076 | B-20
475084 | B-20
475092 | B-20
475100 | B-20
475108 | B-20
475116 | D-2
475124 | D-2
475132 | D-23 / D-23
475142 | D-18
475150 | D-16
475158 | D-14
475166 | F-1
475174 | D-31
475182 | D-9
475190 | D-8
475198 | D-8
475206 | D-9
475214 | D-9
475222 | D-8
475230 | D-10
475238 | A-15
475248 | A-15
475258 | A-16
475266 | A-16
475454 | N00 - COO
476342 | N00 - COO
477326 | N00 - COO
477366 | D-11
478155 | B-20
478577 | N00 - COO
478647 | N00 - COO
479400 | N00 - COO
480663 | D-7
480675 | N00 - COO
481028 | D-29
481395 | N00 - COO
481964 | F-1
515849 | A-3
521063 | A-1
521071 | A-1
521081 | A-3
521091 | A-1
521101 | A-1
521109 | A-1
521125 | A-1
521133 | A-1
521141 | A-1
521151 | E-8.5
521159 | A-3
521167 | Toiture - Cuisine
521830 | A-1
522230 | A-1
675348 | A-1
675357 | A-1
675364 | A-1
675371 | A-1
675378 | E-6
675389 | A-1
675398 | A-1
675415 | E-8.4
675422 | B-21
675448 | A-1
681431 | A-4
681442 | A-5
681452 | A-4
681460 | A-4
681468 | A-5
681476 | A-6
681486 | A-6
681496 | A-8
681508 | E-8.7
681516 | A-9
681524 | A-10
681532 | A-13
681540 | A-14
681548 | A-12
681556 | A-11
681564 | A-1
681595 | B-21
681604 | TR - N02 - ARCH
681612 | E-10
681634 | TR - N02 - ARCH
681770 | A-1
682272 | TR - N02 - ARCH
682284 | F-1
712202 | N00 - COO
822637 | F-1
914543 | F-1
928737 | D-30
1011490 | B-17
1012844 | B-15
1067323 | H-1
1121867 | N00 - COO
1242480 | F-1
1726296 | H-2 / H-4

# IfcCurtainWall: Mur-rideau:07 - Mur rideau meneaux 180, Mur-rideau:07 - Mur rideau meneaux 180:791435
In: N00 - COO
Type - Pset_CurtainWallCommon - IsExternal: no; Reference: 07 - Mur rideau meneaux 180
Type - Pset_QuantityTakeOff - Reference: 07 - Mur rideau meneaux 180
Pset_CurtainWallCommon - IsExternal: yes

# IfcCurtainWall: Mur-rideau:07 - mur rideau trame 100cm (6)
In: N00 - COO
Type - Pset_CurtainWallCommon - IsExternal: no; Reference: 07 - mur rideau trame 100cm
Type - Pset_QuantityTakeOff - Reference: 07 - mur rideau trame 100cm
Name (Mur-rideau:07 - mur rideau trame 100cm:...)
787514
1159115
1159540
1159609
1159761
1160915

# IfcCurtainWall: Mur-rideau:07 - mur rideau trame 140 cm (6)
Type - Pset_CurtainWallCommon - IsExternal: no; Reference: 07 - mur rideau trame 140 cm
Type - Pset_QuantityTakeOff - Reference: 07 - mur rideau trame 140 cm
Name (Mur-rideau:07 - mur rideau trame 140 cm:...) | In
526611 | Toiture - Cuisine
528087 | Toiture - Cuisine
577784 | Toiture - Cuisine
578650 | N00 - COO
580555 | Toiture - Cuisine
1203322 | N00 - COO

# IfcCurtainWall: Mur-rideau:07 - mur rideau trame 160cm (3)
In: N00 - COO
Type - Pset_CurtainWallCommon - IsExternal: no; Reference: 07 - mur rideau trame 160cm
Type - Pset_QuantityTakeOff - Reference: 07 - mur rideau trame 160cm
Name (Mur-rideau:07 - mur rideau trame 160cm:...)
786513
787160
787264

# IfcCurtainWall: Mur-rideau:07 - mur rideau trame 280 cm (22)
In: N00 - COO
Type - Pset_CurtainWallCommon - IsExternal: no; Reference: 07 - mur rideau trame 280 cm
Type - Pset_QuantityTakeOff - Reference: 07 - mur rideau trame 280 cm
Name (Mur-rideau:07 - mur rideau trame 280 cm:...)
165615
166270
238892
581890
582467
582815
583635
583794
583942
584089
584617
667114
1006478
1037220
1045407
1138408
1145636
1148480
1148957
1150218
1196008
1199346

# IfcCurtainWall: Mur-rideau:07 - mur rideau trame 280 cm RDC maintenance (2)
In: N00 - COO
Type - Pset_CurtainWallCommon - IsExternal: no; Reference: 07 - mur rideau trame 280 cm RDC maintenance
Type - Pset_QuantityTakeOff - Reference: 07 - mur rideau trame 280 cm RDC maintenance
Name (Mur-rideau:07 - mur rideau trame 280 cm RDC maintenance:...)
585311
585505

# IfcCurtainWall: Mur-rideau:07 - mur rideau trame 70cm (4)
In: TR - N02 - ARCH
Type - Pset_CurtainWallCommon - IsExternal: no; Reference: 07 - mur rideau trame 70cm
Type - Pset_QuantityTakeOff - Reference: 07 - mur rideau trame 70cm
Name (Mur-rideau:07 - mur rideau trame 70cm:...)
524296
528762
576238
580070

# IfcCurtainWall: Mur-rideau:07 - mur rideau trame 90 cm (8)
In: N00 - COO
Type - Pset_CurtainWallCommon - IsExternal: no; Reference: 07 - mur rideau trame 90 cm
Type - Pset_QuantityTakeOff - Reference: 07 - mur rideau trame 90 cm
Name (Mur-rideau:07 - mur rideau trame 90 cm:...)
582618
584193
584299
584478
794864
1039314
1161946
1337334

# IfcCurtainWall: Mur-rideau:07 - mur rideau vitrage sans recoupement 10cm (8)
In: N00 - COO
Type - Pset_CurtainWallCommon - IsExternal: no; Reference: 07 - mur rideau vitrage sans recoupement 10cm
Type - Pset_QuantityTakeOff - Reference: 07 - mur rideau vitrage sans recoupement 10cm
Name (Mur-rideau:07 - mur rideau vitrage sans recoupement 10cm:...)
704947
705172
705374
705644
1008928
1010332
1010534
1058129

# IfcCurtainWall: Mur-rideau:08 - mur vitré toute hauteur RDC cloison 10 (5)
In: N00 - COO
Type - Pset_CurtainWallCommon - IsExternal: no; Reference: 08 - mur vitré toute hauteur RDC cloison 10
Type - Pset_QuantityTakeOff - Reference: 08 - mur vitré toute hauteur RDC cloison 10
Name (Mur-rideau:08 - mur vitré toute hauteur RDC cloison 10:...)
839274
919930
1124246
1199436
1220075

# IfcCurtainWall: Mur-rideau:08 - mur vitré toute hauteur RDC mur 20 (3)
In: N00 - COO
Type - Pset_CurtainWallCommon - IsExternal: no; Reference: 08 - mur vitré toute hauteur RDC mur 20
Type - Pset_QuantityTakeOff - Reference: 08 - mur vitré toute hauteur RDC mur 20
Name (Mur-rideau:08 - mur vitré toute hauteur RDC mur 20:...)
894791
942823
1124364

# IfcCurtainWall: Mur-rideau:Epines - 200x30mm, Mur-rideau:Epines - 200x30mm:872307
In: N00 - COO
Type - Pset_CurtainWallCommon - IsExternal: no; Reference: Epines - 200x30mm
Type - Pset_QuantityTakeOff - Reference: Epines - 200x30mm
Pset_CurtainWallCommon - IsExternal: yes

# IfcCurtainWall: Mur-rideau:Epines - 200x50mm (5)
Type - Pset_CurtainWallCommon - IsExternal: no; Reference: Epines - 200x50mm
Type - Pset_QuantityTakeOff - Reference: Epines - 200x50mm
Pset_CurtainWallCommon - IsExternal: yes
Name (Mur-rideau:Epines - 200x50mm:...) | In
596346 | N00 - COO
650337 | Toiture - Cuisine
653086 | N00 - COO
769414 | N00 - COO
1152442 | N00 - COO

# IfcCurtainWall: Mur-rideau:Epines - 400x30mm (2)
In: Toiture - Cuisine
Type - Pset_CurtainWallCommon - IsExternal: no; Reference: Epines - 400x30mm
Type - Pset_QuantityTakeOff - Reference: Epines - 400x30mm
Pset_CurtainWallCommon - IsExternal: yes
Name (Mur-rideau:Epines - 400x30mm:...)
638618
2098392

# IfcCurtainWall: Mur-rideau:SR-Clôture (9)
In: N00 - COO
Type - Pset_CurtainWallCommon - IsExternal: no; Reference: SR-Clôture
Type - Pset_QuantityTakeOff - Reference: SR-Clôture
Pset_CurtainWallCommon - IsExternal: yes
Name (Mur-rideau:SR-Clôture:...)
668033
899485
907061
907806
1058885
1060631
1735584
1735825
2138056

# IfcCurtainWall: Mur-rideau:SR-Portail coulissant (3)
In: N00 - COO
Type - Pset_CurtainWallCommon - IsExternal: no; Reference: SR-Portail coulissant
Type - Pset_QuantityTakeOff - Reference: SR-Portail coulissant
Pset_CurtainWallCommon - IsExternal: yes
Name (Mur-rideau:SR-Portail coulissant:...)
1059826
1064680
1368681

# IfcDistributionPort (20)
Description: Flow
Name | FlowDirection
Port_456217 | SOURCE
Port_456217 | SINK
Port_515108 | SINK
Port_515108 | SOURCE
Port_520340 | SINK
Port_520340 | SOURCE
Port_534282 | SINK
Port_534282 | SOURCE
Port_534341 | SINK
Port_534341 | SOURCE
Port_566323 | SINK
Port_566323 | SOURCE
Port_920768 | SINK
Port_920768 | SOURCE
Port_1546474 | SINK
Port_1546474 | SOURCE
Port_1546550 | SOURCE
Port_1546550 | SINK
Port_1892185 | SINK
Port_1892185 | SOURCE

# IfcDoor: 2.4m x 2.5m, Garage basculante:2.4m x 2.5m:1040135
In: N00 - COO
Type - ParameterTakesPrecedence: no; Sizeable: no; Material: Plastique - Noir, Aluminium bardage, Aluminium
OverallHeight: 243 cm; OverallWidth: 251.5 cm
Pset_DoorCommon - IsExternal: yes; Reference: 2.4m x 2.5m; ThermalTransmittance: 3.7021 kg/K/s3
Pset_QuantityTakeOff - Reference: 2.4m x 2.5m

# IfcDoor: Outward-opening, flush-fitted (9)
In: N00 - COO
Type - ConstructionType: USERDEFINED; ParameterTakesPrecedence: no; Sizeable: no; Material: Verre, Aluminium
Pset_DoorCommon - Reference: Outward-opening, flush-fitted
Pset_ManufacturerTypeInformation - Manufacturer: Schueco International KG
Pset_QuantityTakeOff - Reference: Outward-opening, flush-fitted
Name | OverallHeight (cm) | OverallWidth (cm) | IsExternal
Schueco_ADS-90-SimplySmart_Family-01-out:Outward-opening, flush-fitted:775097 | 275 | 93 | yes
Schueco_ADS-90-SimplySmart_Family-01-out:Outward-opening, flush-fitted:775123 | 275 | 93 | yes
Schueco_ADS-90-SimplySmart_Family-01-out:Outward-opening, flush-fitted:936510 | 328 | 120 | yes
Schueco_ADS-90-SimplySmart_Family-01-out:Outward-opening, flush-fitted:1006061 | 321 | 115 | yes
Schueco_ADS-90-SimplySmart_Family-02-out.0001:Outward-opening, flush-fitted:1040412 | 326 | 180 | yes
Schueco_ADS-90-SimplySmart_Family-01-out:Outward-opening, flush-fitted:1195911 | 321 | 115 | yes
Schueco_ADS-90-SimplySmart_Family-01-out:Outward-opening, flush-fitted:1196043 | 321 | 115 | yes
Schueco_ADS-90-SimplySmart_Family-01-out:Outward-opening, flush-fitted:1214109 | 321 | 136.384 | yes
Schueco_ADS-90-SimplySmart_Family-01-out:Outward-opening, flush-fitted:1995053 | 315.627 | 156.551 | no

# IfcDoor: PM 0.80m x 2.04m 2 (3)
In: N00 - COO
Type - ParameterTakesPrecedence: no; Sizeable: no; Material: Bois - Panneau de porte, Bois - Cadre de porte
OverallHeight: 204 cm; OverallWidth: 100 cm
Pset_DoorCommon - IsExternal: no; Reference: PM 0.80m x 2.04m 2; ThermalTransmittance: 3.7021 kg/K/s3
Pset_QuantityTakeOff - Reference: PM 0.80m x 2.04m 2
Name (Coulissante - Apparente:PM 0.80m x 2.04m 2:...)
1117941
1117960
1117987

# IfcDoor: PP (0.83m x 2.04m) (2)
In: N00 - COO
Type - OperationType: SINGLE_SWING_LEFT; ParameterTakesPrecedence: no; Sizeable: no; Material: Finition Peinture - Blanc satiné, Bois - Panneau de porte, Bois - Cadre de porte
Type - Int. Simple:PP (0.83m x 2.04m):457187 - PanelOperation: SWINGING
OverallHeight: 207.5 cm; OverallWidth: 90 cm
Pset_DoorCommon - IsExternal: no; Reference: PP (0.83m x 2.04m)
Pset_QuantityTakeOff - Reference: PP (0.83m x 2.04m)
Name (Int. Simple:PP (0.83m x 2.04m):...)
457187
457216

# IfcDoor: PP (0.83m x 2.04m), Int. Simple:PP (0.83m x 2.04m):456985
In: N00 - COO
Type - OperationType: SINGLE_SWING_RIGHT; ParameterTakesPrecedence: no; Sizeable: no; Material: Finition Peinture - Blanc satiné, Bois - Panneau de porte, Bois - Cadre de porte
Type - Int. Simple:PP (0.83m x 2.04m):456985 - PanelOperation: SWINGING
OverallHeight: 207.5 cm; OverallWidth: 90 cm
Pset_DoorCommon - IsExternal: no; Reference: PP (0.83m x 2.04m)
Pset_QuantityTakeOff - Reference: PP (0.83m x 2.04m)

# IfcDoor: PP (0.93m x 2.50m) (3)
In: N00 - COO
Type - OperationType: SINGLE_SWING_LEFT; ParameterTakesPrecedence: no; Sizeable: no; Material: Finition Peinture - Blanc satiné, Bois - Panneau de porte, Bois - Cadre de porte
Type - Int. Simple:PP (0.93m x 2.50m):461258 - PanelOperation: SWINGING
OverallHeight: 248.5 cm; OverallWidth: 100 cm
Pset_DoorCommon - IsExternal: no; Reference: PP (0.93m x 2.50m)
Pset_QuantityTakeOff - Reference: PP (0.93m x 2.50m)
Name (Int. Simple:PP (0.93m x 2.50m):...)
461258
461295
463010

# IfcDoor: PP (0.93m x 2.50m), Int. Simple:PP (0.93m x 2.50m):461457
In: N00 - COO
Type - OperationType: SINGLE_SWING_LEFT; ParameterTakesPrecedence: no; Sizeable: no; Material: Finition Peinture - Blanc satiné, Bois - Panneau de porte, Bois - Cadre de porte
Type - Int. Simple:PP (0.93m x 2.50m):461457 - PanelOperation: SWINGING
OverallHeight: 248.5 cm; OverallWidth: 100 cm
Pset_DoorCommon - IsExternal: no; Reference: PP (0.93m x 2.50m)
Pset_QuantityTakeOff - Reference: PP (0.93m x 2.50m)

# IfcDoor: PP (0.93m x 2.50m), Int. Simple:PP (0.93m x 2.50m):463188
In: N00 - COO
Type - OperationType: SINGLE_SWING_LEFT; ParameterTakesPrecedence: no; Sizeable: no; Material: Finition Peinture - Blanc satiné, Bois - Panneau de porte, Bois - Cadre de porte
Type - Int. Simple:PP (0.93m x 2.50m):463188 - PanelOperation: SWINGING
OverallHeight: 248.5 cm; OverallWidth: 100 cm
Pset_DoorCommon - IsExternal: no; Reference: PP (0.93m x 2.50m)
Pset_QuantityTakeOff - Reference: PP (0.93m x 2.50m)

# IfcDoor: PP (0.93m x 2.50m) (2)
In: N00 - COO
Type - OperationType: SINGLE_SWING_RIGHT; ParameterTakesPrecedence: no; Sizeable: no; Material: Finition Peinture - Blanc satiné, Bois - Panneau de porte, Bois - Cadre de porte
Type - Int. Simple:PP (0.93m x 2.50m):461330 - PanelOperation: SWINGING
OverallHeight: 248.5 cm; OverallWidth: 100 cm
Pset_DoorCommon - IsExternal: no; Reference: PP (0.93m x 2.50m)
Pset_QuantityTakeOff - Reference: PP (0.93m x 2.50m)
Name (Int. Simple:PP (0.93m x 2.50m):...)
461330
1339257

# IfcDoor: PP (0.93m x 2.50m), Int. Simple:PP (0.93m x 2.50m):463043
In: N00 - COO
Type - OperationType: SINGLE_SWING_RIGHT; ParameterTakesPrecedence: no; Sizeable: no; Material: Finition Peinture - Blanc satiné, Bois - Panneau de porte, Bois - Cadre de porte
Type - Int. Simple:PP (0.93m x 2.50m):463043 - PanelOperation: SWINGING
OverallHeight: 248.5 cm; OverallWidth: 100 cm
Pset_DoorCommon - IsExternal: no; Reference: PP (0.93m x 2.50m)
Pset_QuantityTakeOff - Reference: PP (0.93m x 2.50m)

# IfcDoor: PP (0.93m x 3.06m) (5)
In: N00 - COO
Type - OperationType: SINGLE_SWING_LEFT; ParameterTakesPrecedence: no; Sizeable: no; Material: Finition Peinture - Blanc satiné, Bois - Panneau de porte, Bois - Cadre de porte
Type - Int. Simple:PP (0.93m x 3.06m):397281 - PanelOperation: SWINGING
OverallHeight: 309.5 cm; OverallWidth: 100 cm
Pset_DoorCommon - IsExternal: no; Reference: PP (0.93m x 3.06m)
Pset_QuantityTakeOff - Reference: PP (0.93m x 3.06m)
Name (Int. Simple:PP (0.93m x 3.06m):...)
397281
397319
397358
485836
485846

# IfcDoor: PP (0.93m x 3.06m), Int. Simple:PP (0.93m x 3.06m):363961
In: N00 - COO
Type - OperationType: SINGLE_SWING_RIGHT; ParameterTakesPrecedence: no; Sizeable: no; Material: Finition Peinture - Blanc satiné, Bois - Panneau de porte, Bois - Cadre de porte
Type - Int. Simple:PP (0.93m x 3.06m):363961 - PanelOperation: SWINGING
OverallHeight: 309.5 cm; OverallWidth: 100 cm
Pset_DoorCommon - IsExternal: no; Reference: PP (0.93m x 3.06m)
Pset_QuantityTakeOff - Reference: PP (0.93m x 3.06m)

# IfcDoor: PP (0.93m x 3.06m) (6)
In: N00 - COO
Type - OperationType: SINGLE_SWING_RIGHT; ParameterTakesPrecedence: no; Sizeable: no; Material: Finition Peinture - Blanc satiné, Bois - Panneau de porte, Bois - Cadre de porte
Type - Int. Simple:PP (0.93m x 3.06m):397297 - PanelOperation: SWINGING
OverallHeight: 309.5 cm; OverallWidth: 100 cm
Pset_DoorCommon - IsExternal: no; Reference: PP (0.93m x 3.06m)
Pset_QuantityTakeOff - Reference: PP (0.93m x 3.06m)
Name (Int. Simple:PP (0.93m x 3.06m):...)
397297
430366
485845
486740
486741
1903935

# IfcDoor: PP (1.40m x 2.04m), Int. Double:PP (1.40m x 2.04m):1880202
In: Toiture - Cuisine
Type - OperationType: DOUBLE_DOOR_SINGLE_SWING; ParameterTakesPrecedence: no; Sizeable: no; Material: Bois - Panneau de porte, Finition Peinture - Blanc satiné, Bois - Cadre de porte
Type - Int. Double:PP (1.40m x 2.04m):1880202 - PanelOperation: SWINGING
OverallHeight: 207.5 cm; OverallWidth: 147 cm
Pset_DoorCommon - IsExternal: no; Reference: PP (1.40m x 2.04m); ThermalTransmittance: 3.6886 kg/K/s3
Pset_QuantityTakeOff - Reference: PP (1.40m x 2.04m)

# IfcDoor: PP (1.40m x 2.04m), Int. Double:PP (1.40m x 2.04m):1887895
In: Toiture - Cuisine
Type - OperationType: DOUBLE_DOOR_SINGLE_SWING; ParameterTakesPrecedence: no; Sizeable: no; Material: Bois - Panneau de porte, Finition Peinture - Blanc satiné, Bois - Cadre de porte
Type - Int. Double:PP (1.40m x 2.04m):1887895 - PanelOperation: SWINGING
OverallHeight: 207.5 cm; OverallWidth: 147 cm
Pset_DoorCommon - IsExternal: no; Reference: PP (1.40m x 2.04m); ThermalTransmittance: 3.6886 kg/K/s3
Pset_QuantityTakeOff - Reference: PP (1.40m x 2.04m)

# IfcDoor: PP (1.40m x 2.04m), Int. Double:PP (1.40m x 2.04m):795685
In: N00 - COO
Type - OperationType: DOUBLE_DOOR_SINGLE_SWING; ParameterTakesPrecedence: no; Sizeable: no; Material: Bois - Panneau de porte, Finition Peinture - Blanc satiné, Bois - Cadre de porte
Type - Int. Double:PP (1.40m x 2.04m):795685 - PanelOperation: SWINGING
OverallHeight: 207.5 cm; OverallWidth: 147 cm
Pset_DoorCommon - IsExternal: no; Reference: PP (1.40m x 2.04m); ThermalTransmittance: 3.6886 kg/K/s3
Pset_QuantityTakeOff - Reference: PP (1.40m x 2.04m)

# IfcDoor: PP (1.40m x 2.04m), Int. Double:PP (1.40m x 2.04m):795850
In: N00 - COO
Type - OperationType: DOUBLE_DOOR_SINGLE_SWING; ParameterTakesPrecedence: no; Sizeable: no; Material: Bois - Panneau de porte, Finition Peinture - Blanc satiné, Bois - Cadre de porte
Type - Int. Double:PP (1.40m x 2.04m):795850 - PanelOperation: SWINGING
OverallHeight: 207.5 cm; OverallWidth: 147 cm
Pset_DoorCommon - IsExternal: no; Reference: PP (1.40m x 2.04m); ThermalTransmittance: 3.6886 kg/K/s3
Pset_QuantityTakeOff - Reference: PP (1.40m x 2.04m)

# IfcDoor: PP (1.44m x 2.04m), Int. Tierce:PP (1.44m x 2.04m):452237
In: N00 - COO
Type - OperationType: DOUBLE_DOOR_SINGLE_SWING; ParameterTakesPrecedence: no; Sizeable: no; Material: Finition Peinture - Blanc satiné, Bois - Panneau de porte, Bois - Cadre de porte
Type - Int. Tierce:PP (1.44m x 2.04m):452237 - PanelOperation: SWINGING
OverallHeight: 207.5 cm; OverallWidth: 151 cm
Pset_DoorCommon - IsExternal: no; Reference: PP (1.44m x 2.04m); ThermalTransmittance: 5.5617 kg/K/s3
Pset_QuantityTakeOff - Reference: PP (1.44m x 2.04m)

# IfcDoor: PP (1.44m x 2.04m), Int. Tierce:PP (1.44m x 2.04m):452891
In: N00 - COO
Type - OperationType: DOUBLE_DOOR_SINGLE_SWING; ParameterTakesPrecedence: no; Sizeable: no; Material: Finition Peinture - Blanc satiné, Bois - Panneau de porte, Bois - Cadre de porte
Type - Int. Tierce:PP (1.44m x 2.04m):452891 - PanelOperation: SWINGING
OverallHeight: 207.5 cm; OverallWidth: 151 cm
Pset_DoorCommon - IsExternal: no; Reference: PP (1.44m x 2.04m); ThermalTransmittance: 5.5617 kg/K/s3
Pset_QuantityTakeOff - Reference: PP (1.44m x 2.04m)

# IfcDoor: PP (1.80m x 3.11m), Int. Tierce:PP (1.80m x 3.11m):1039841
In: N00 - COO
Type - OperationType: DOUBLE_DOOR_SINGLE_SWING; ParameterTakesPrecedence: no; Sizeable: no; Material: Finition Peinture - Blanc satiné, Bois - Panneau de porte, Bois - Cadre de porte
Type - Int. Tierce:PP (1.80m x 3.11m):1039841 - PanelOperation: SWINGING
OverallHeight: 311 cm; OverallWidth: 151 cm
Pset_DoorCommon - IsExternal: no; Reference: PP (1.80m x 3.11m); ThermalTransmittance: 5.5617 kg/K/s3
Pset_QuantityTakeOff - Reference: PP (1.80m x 3.11m)

# IfcDoor: PP (1.80m x 3.11m), Int. Tierce:PP (1.80m x 3.11m):1860215
In: N00 - COO
Type - OperationType: DOUBLE_DOOR_SINGLE_SWING; ParameterTakesPrecedence: no; Sizeable: no; Material: Finition Peinture - Blanc satiné, Bois - Panneau de porte, Bois - Cadre de porte
Type - Int. Tierce:PP (1.80m x 3.11m):1860215 - PanelOperation: SWINGING
OverallHeight: 311 cm; OverallWidth: 151 cm
Pset_DoorCommon - IsExternal: no; Reference: PP (1.80m x 3.11m); ThermalTransmittance: 5.5617 kg/K/s3
Pset_QuantityTakeOff - Reference: PP (1.80m x 3.11m)

# IfcDoor: PP (1.83m x 2.04m), Int. Double:PP (1.83m x 2.04m):1874807
In: TR - N02 - ARCH
Type - OperationType: DOUBLE_DOOR_SINGLE_SWING; ParameterTakesPrecedence: no; Sizeable: no; Material: Bois - Panneau de porte, Finition Peinture - Blanc satiné, Bois - Cadre de porte
Type - Int. Double:PP (1.83m x 2.04m):1874807 - PanelOperation: SWINGING
OverallHeight: 248.5 cm; OverallWidth: 190 cm
Pset_DoorCommon - IsExternal: no; Reference: PP (1.83m x 2.04m); ThermalTransmittance: 3.6886 kg/K/s3
Pset_QuantityTakeOff - Reference: PP (1.83m x 2.04m)

# IfcDoor: PP (1.83m x 2.04m), Int. Double:PP (1.83m x 2.04m):551275
In: TR - N02 - ARCH
Type - OperationType: DOUBLE_DOOR_SINGLE_SWING; ParameterTakesPrecedence: no; Sizeable: no; Material: Bois - Panneau de porte, Finition Peinture - Blanc satiné, Bois - Cadre de porte
Type - Int. Double:PP (1.83m x 2.04m):551275 - PanelOperation: SWINGING
OverallHeight: 248.5 cm; OverallWidth: 190 cm
Pset_DoorCommon - IsExternal: no; Reference: PP (1.83m x 2.04m); ThermalTransmittance: 3.6886 kg/K/s3
Pset_QuantityTakeOff - Reference: PP (1.83m x 2.04m)

# IfcDoor: PP (1.90m x 2.50m), Int. Double:PP (1.90m x 2.50m):551198
In: Toiture - Cuisine
Type - OperationType: DOUBLE_DOOR_SINGLE_SWING; ParameterTakesPrecedence: no; Sizeable: no; Material: Bois - Panneau de porte, Finition Peinture - Blanc satiné, Bois - Cadre de porte
Type - Int. Double:PP (1.90m x 2.50m):551198 - PanelOperation: SWINGING
OverallHeight: 253.5 cm; OverallWidth: 197 cm
Pset_DoorCommon - IsExternal: no; Reference: PP (1.90m x 2.50m); ThermalTransmittance: 3.6886 kg/K/s3
Pset_QuantityTakeOff - Reference: PP (1.90m x 2.50m)

# IfcDoor: PP (1.90m x 2.50m), Int. Double:PP (1.90m x 2.50m):551199
In: Toiture - Cuisine
Type - OperationType: DOUBLE_DOOR_SINGLE_SWING; ParameterTakesPrecedence: no; Sizeable: no; Material: Bois - Panneau de porte, Finition Peinture - Blanc satiné, Bois - Cadre de porte
Type - Int. Double:PP (1.90m x 2.50m):551199 - PanelOperation: SWINGING
OverallHeight: 253.5 cm; OverallWidth: 197 cm
Pset_DoorCommon - IsExternal: no; Reference: PP (1.90m x 2.50m); ThermalTransmittance: 3.6886 kg/K/s3
Pset_QuantityTakeOff - Reference: PP (1.90m x 2.50m)

# IfcDoor: PP (1.90m x 2.50m) (2)
Type - OperationType: DOUBLE_DOOR_SINGLE_SWING; ParameterTakesPrecedence: no; Sizeable: no; Material: Bois - Panneau de porte, Finition Peinture - Blanc satiné, Bois - Cadre de porte
Type - Int. Double:PP (1.90m x 2.50m):551274 - PanelOperation: SWINGING
OverallHeight: 253.5 cm; OverallWidth: 197 cm
Pset_DoorCommon - IsExternal: no; Reference: PP (1.90m x 2.50m); ThermalTransmittance: 3.6886 kg/K/s3
Pset_QuantityTakeOff - Reference: PP (1.90m x 2.50m)
Name (Int. Double:PP (1.90m x 2.50m):...) | In
551274 | TR - N02 - ARCH
2176532 | Toiture - Cuisine

# IfcDoor: PP (1.90m x 2.60m), Int. Tierce:PP (1.90m x 2.60m):2061533
In: N00 - COO
Type - OperationType: DOUBLE_DOOR_SINGLE_SWING; ParameterTakesPrecedence: no; Sizeable: no; Material: Finition Peinture - Blanc satiné, Bois - Panneau de porte, Bois - Cadre de porte
Type - Int. Tierce:PP (1.90m x 2.60m):2061533 - PanelOperation: SWINGING
OverallHeight: 263.5 cm; OverallWidth: 197 cm
Pset_DoorCommon - IsExternal: no; Reference: PP (1.90m x 2.60m); ThermalTransmittance: 5.5617 kg/K/s3
Pset_QuantityTakeOff - Reference: PP (1.90m x 2.60m)

# IfcDoor: PP (1.90m x 3.00m) (2)
In: N00 - COO
Type - OperationType: DOUBLE_DOOR_SINGLE_SWING; ParameterTakesPrecedence: no; Sizeable: no; Material: Bois - Panneau de porte, Finition Peinture - Blanc satiné, Bois - Cadre de porte
Type - Int. Double:PP (1.90m x 3.00m):164671 - PanelOperation: SWINGING
OverallHeight: 304.5 cm; OverallWidth: 197 cm
Pset_DoorCommon - IsExternal: no; Reference: PP (1.90m x 3.00m); ThermalTransmittance: 3.6886 kg/K/s3
Pset_QuantityTakeOff - Reference: PP (1.90m x 3.00m)
Name (Int. Double:PP (1.90m x 3.00m):...)
164671
164788

# IfcDoor: PP EXT - Local poubelle (0.93m x 2.50m), Int. Simple:PP EXT - Local poubelle (0.93m x 2.50m):1012698
In: N00 - COO
Type - OperationType: SINGLE_SWING_LEFT; ParameterTakesPrecedence: no; Sizeable: no; Material: Finition Peinture - Blanc satiné, Aluminium
Type - Int. Simple:PP EXT - Local poubelle (0.93m x 2.50m):1012698 - PanelOperation: SWINGING
OverallHeight: 250 cm; OverallWidth: 100 cm
Pset_DoorCommon - IsExternal: no; Reference: PP EXT - Local poubelle (0.93m x 2.50m)
Pset_QuantityTakeOff - Reference: PP EXT - Local poubelle (0.93m x 2.50m)

# IfcDoor: PP EXT - Local poubelle (0.93m x 2.50m), Int. Simple:PP EXT - Local poubelle (0.93m x 2.50m):850345
In: Toiture - Cuisine
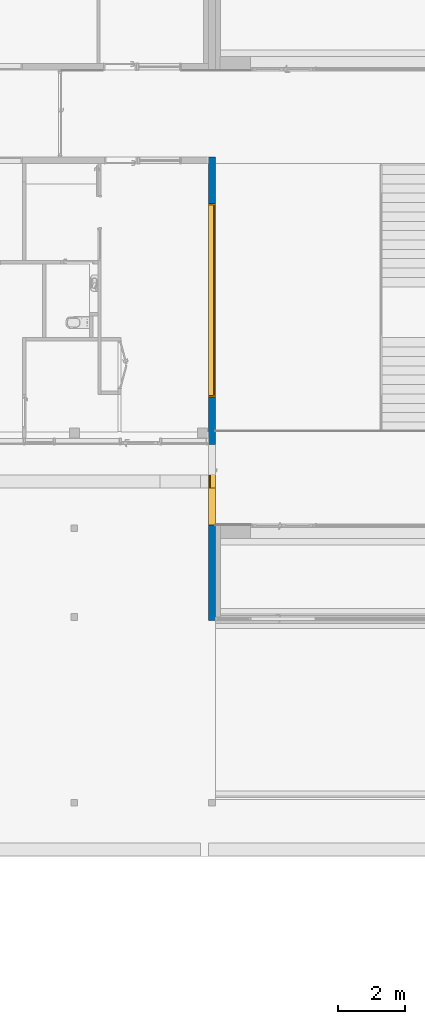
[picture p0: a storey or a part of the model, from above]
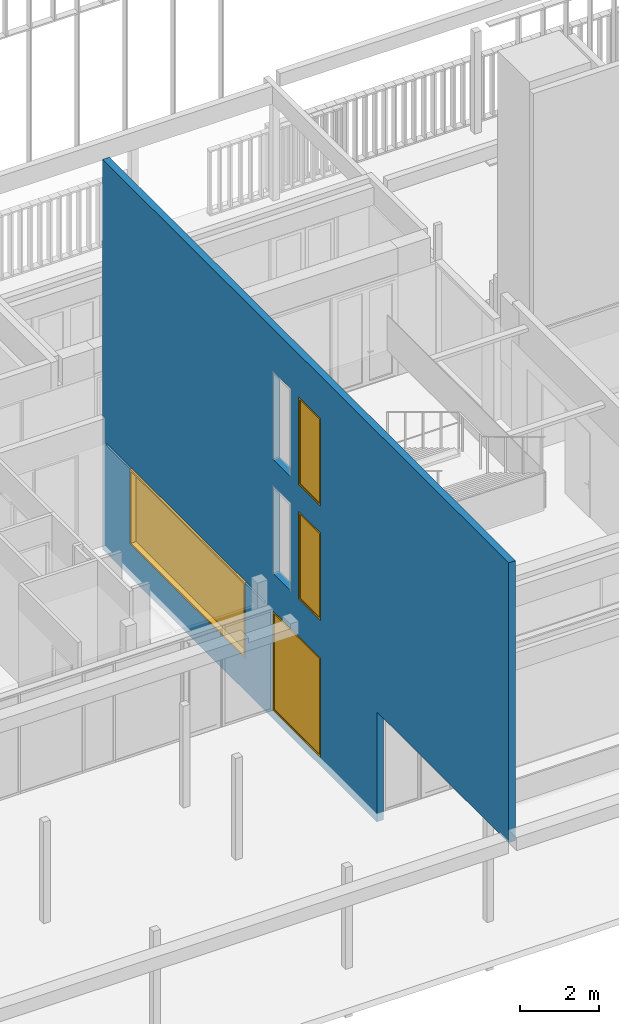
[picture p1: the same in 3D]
Properties of the parts of a building model (IFC2X3), part 2 of 7

# IfcDoor: PP EXT - Local poubelle (0.93m x 2.50m), Int. Simple:PP EXT - Local poubelle (0.93m x 2.50m):850345
Type - OperationType: SINGLE_SWING_LEFT; ParameterTakesPrecedence: no; Sizeable: no; Material: Finition Peinture - Blanc satiné, Aluminium
Type - Int. Simple:PP EXT - Local poubelle (0.93m x 2.50m):850345 - PanelOperation: SWINGING
OverallHeight: 250 cm; OverallWidth: 100 cm
Pset_DoorCommon - IsExternal: no; Reference: PP EXT - Local poubelle (0.93m x 2.50m)
Pset_QuantityTakeOff - Reference: PP EXT - Local poubelle (0.93m x 2.50m)

# IfcDoor: PP EXT - Local poubelle (0.93m x 2.50m), Int. Simple:PP EXT - Local poubelle (0.93m x 2.50m):1012701
In: N00 - COO
Type - OperationType: SINGLE_SWING_RIGHT; ParameterTakesPrecedence: no; Sizeable: no; Material: Finition Peinture - Blanc satiné, Aluminium
Type - Int. Simple:PP EXT - Local poubelle (0.93m x 2.50m):1012701 - PanelOperation: SWINGING
OverallHeight: 250 cm; OverallWidth: 100 cm
Pset_DoorCommon - IsExternal: no; Reference: PP EXT - Local poubelle (0.93m x 2.50m)
Pset_QuantityTakeOff - Reference: PP EXT - Local poubelle (0.93m x 2.50m)

# IfcDoor: PP EXT - Vide sanitaire (0.93m x 1.80m), Int. Simple:PP EXT - Vide sanitaire (0.93m x 1.80m):852628
In: Vide Sanitaire
Type - OperationType: SINGLE_SWING_LEFT; ParameterTakesPrecedence: no; Sizeable: no; Material: Finition Peinture - Blanc satiné, Bois - Panneau de porte, Bois - Cadre de porte
Type - Int. Simple:PP EXT - Vide sanitaire (0.93m x 1.80m):852628 - PanelOperation: SWINGING
OverallHeight: 158.5 cm; OverallWidth: 100 cm
Pset_DoorCommon - IsExternal: no; Reference: PP EXT - Vide sanitaire (0.93m x 1.80m)
Pset_QuantityTakeOff - Reference: PP EXT - Vide sanitaire (0.93m x 1.80m)

# IfcDoor: PP ISOTHERME (0.93m x 2.04m), Int. Simple:PP ISOTHERME (0.93m x 2.04m):1772648
In: N00 - COO
Type - OperationType: SINGLE_SWING_RIGHT; ParameterTakesPrecedence: no; Sizeable: no; Material: Finition Peinture - Blanc satiné, Bois - Panneau de porte, Bois - Cadre de porte
Type - Int. Simple:PP ISOTHERME (0.93m x 2.04m):1772648 - PanelOperation: SWINGING
OverallHeight: 207.5 cm; OverallWidth: 100 cm
Pset_DoorCommon - IsExternal: no; Reference: PP ISOTHERME (0.93m x 2.04m)
Pset_QuantityTakeOff - Reference: PP ISOTHERME (0.93m x 2.04m)

# IfcDoor: PP PORTAIL (1.83m x 2.04m), Int. Double:PP PORTAIL (1.83m x 2.04m):1970831
In: N00 - COO
Type - OperationType: DOUBLE_DOOR_SINGLE_SWING; ParameterTakesPrecedence: no; Sizeable: no; Material: Bois - Panneau de porte, Finition Peinture - Blanc satiné, Bois - Cadre de porte
Type - Int. Double:PP PORTAIL (1.83m x 2.04m):1970831 - PanelOperation: SWINGING
OverallHeight: 201.5 cm; OverallWidth: 193 cm
Pset_DoorCommon - IsExternal: no; Reference: PP PORTAIL (1.83m x 2.04m); ThermalTransmittance: 3.6886 kg/K/s3
Pset_QuantityTakeOff - Reference: PP PORTAIL (1.83m x 2.04m)

# IfcDoor: PP Placard (0.55m x 2.50m), Int. Simple:PP Placard (0.55m x 2.50m):533705
In: TR - N02 - ARCH
Type - OperationType: SINGLE_SWING_LEFT; ParameterTakesPrecedence: no; Sizeable: no; Material: Finition Peinture - Blanc satiné, Bois - Panneau de porte, Bois - Cadre de porte
Type - Int. Simple:PP Placard (0.55m x 2.50m):533705 - PanelOperation: SWINGING
OverallHeight: 248.5 cm; OverallWidth: 62 cm
Pset_DoorCommon - IsExternal: no; Reference: PP Placard (0.55m x 2.50m)
Pset_QuantityTakeOff - Reference: PP Placard (0.55m x 2.50m)

# IfcDoor: PP Placard (0.55m x 2.50m) (2)
Type - OperationType: SINGLE_SWING_RIGHT; ParameterTakesPrecedence: no; Sizeable: no; Material: Finition Peinture - Blanc satiné, Bois - Panneau de porte, Bois - Cadre de porte
Type - Int. Simple:PP Placard (0.55m x 2.50m):517257 - PanelOperation: SWINGING
OverallHeight: 248.5 cm; OverallWidth: 62 cm
Pset_DoorCommon - IsExternal: no; Reference: PP Placard (0.55m x 2.50m)
Pset_QuantityTakeOff - Reference: PP Placard (0.55m x 2.50m)
Name (Int. Simple:PP Placard (0.55m x 2.50m):...) | In
517257 | Toiture - Cuisine
533480 | TR - N02 - ARCH

# IfcDoor: PP Placard (0.55m x 3.00m), Int. Simple:PP Placard (0.55m x 3.00m):404236
In: N00 - COO
Type - OperationType: SINGLE_SWING_RIGHT; ParameterTakesPrecedence: no; Sizeable: no; Material: Finition Peinture - Blanc satiné, Bois - Panneau de porte, Bois - Cadre de porte
Type - Int. Simple:PP Placard (0.55m x 3.00m):404236 - PanelOperation: SWINGING
OverallHeight: 304.5 cm; OverallWidth: 62 cm
Pset_DoorCommon - IsExternal: no; Reference: PP Placard (0.55m x 3.00m)
Pset_QuantityTakeOff - Reference: PP Placard (0.55m x 3.00m)

# IfcDoor: PP Placard (0.80m x 2.50m) (2)
Type - OperationType: SINGLE_SWING_RIGHT; ParameterTakesPrecedence: no; Sizeable: no; Material: Finition Peinture - Blanc satiné, Bois - Panneau de porte, Bois - Cadre de porte
Type - Int. Simple:PP Placard (0.80m x 2.50m):404410 - PanelOperation: SWINGING
OverallHeight: 248.5 cm; OverallWidth: 87 cm
Pset_DoorCommon - IsExternal: no; Reference: PP Placard (0.80m x 2.50m)
Pset_QuantityTakeOff - Reference: PP Placard (0.80m x 2.50m)
Name (Int. Simple:PP Placard (0.80m x 2.50m):...) | In
404410 | N00 - COO
510559 | Toiture - Cuisine

# IfcDoor: PP Placard (1.05m x 2.09m), Int. Double:PP Placard (1.05m x 2.09m):533521
In: TR - N02 - ARCH
Type - OperationType: DOUBLE_DOOR_SINGLE_SWING; ParameterTakesPrecedence: no; Sizeable: no; Material: Bois - Panneau de porte, Finition Peinture - Blanc satiné, Bois - Cadre de porte
Type - Int. Double:PP Placard (1.05m x 2.09m):533521 - PanelOperation: SWINGING
OverallHeight: 248.5 cm; OverallWidth: 112 cm
Pset_DoorCommon - IsExternal: no; Reference: PP Placard (1.05m x 2.09m); ThermalTransmittance: 3.6886 kg/K/s3
Pset_QuantityTakeOff - Reference: PP Placard (1.05m x 2.09m)

# IfcDoor: PP Placard (1.05m x 2.50m), Int. Double:PP Placard (1.05m x 2.50m):517256
In: Toiture - Cuisine
Type - OperationType: DOUBLE_DOOR_SINGLE_SWING; ParameterTakesPrecedence: no; Sizeable: no; Material: Bois - Panneau de porte, Finition Peinture - Blanc satiné, Bois - Cadre de porte
Type - Int. Double:PP Placard (1.05m x 2.50m):517256 - PanelOperation: SWINGING
OverallHeight: 248.5 cm; OverallWidth: 112 cm
Pset_DoorCommon - IsExternal: no; Reference: PP Placard (1.05m x 2.50m); ThermalTransmittance: 3.6886 kg/K/s3
Pset_QuantityTakeOff - Reference: PP Placard (1.05m x 2.50m)

# IfcDoor: PP Placard (1.05m x 2.50m), Int. Double:PP Placard (1.05m x 2.50m):533634
In: TR - N02 - ARCH
Type - OperationType: DOUBLE_DOOR_SINGLE_SWING; ParameterTakesPrecedence: no; Sizeable: no; Material: Bois - Panneau de porte, Finition Peinture - Blanc satiné, Bois - Cadre de porte
Type - Int. Double:PP Placard (1.05m x 2.50m):533634 - PanelOperation: SWINGING
OverallHeight: 248.5 cm; OverallWidth: 112 cm
Pset_DoorCommon - IsExternal: no; Reference: PP Placard (1.05m x 2.50m); ThermalTransmittance: 3.6886 kg/K/s3
Pset_QuantityTakeOff - Reference: PP Placard (1.05m x 2.50m)

# IfcDoor: PP Placard (1.05m x 3.00m), Int. Double:PP Placard (1.05m x 3.00m):404158
In: N00 - COO
Type - OperationType: DOUBLE_DOOR_SINGLE_SWING; ParameterTakesPrecedence: no; Sizeable: no; Material: Bois - Panneau de porte, Finition Peinture - Blanc satiné, Bois - Cadre de porte
Type - Int. Double:PP Placard (1.05m x 3.00m):404158 - PanelOperation: SWINGING
OverallHeight: 304.5 cm; OverallWidth: 112 cm
Pset_DoorCommon - IsExternal: no; Reference: PP Placard (1.05m x 3.00m); ThermalTransmittance: 3.6886 kg/K/s3
Pset_QuantityTakeOff - Reference: PP Placard (1.05m x 3.00m)

# IfcDoor: PP Placard (1.10m x 2.50m) (2)
Type - OperationType: DOUBLE_DOOR_SINGLE_SWING; ParameterTakesPrecedence: no; Sizeable: no; Material: Bois - Panneau de porte, Finition Peinture - Blanc satiné, Bois - Cadre de porte
Type - Int. Double:PP Placard (1.10m x 2.50m):404341 - PanelOperation: SWINGING
OverallHeight: 248.5 cm; OverallWidth: 117 cm
Pset_DoorCommon - IsExternal: no; Reference: PP Placard (1.10m x 2.50m); ThermalTransmittance: 3.6886 kg/K/s3
Pset_QuantityTakeOff - Reference: PP Placard (1.10m x 2.50m)
Name (Int. Double:PP Placard (1.10m x 2.50m):...) | In
404341 | N00 - COO
510558 | Toiture - Cuisine

# IfcDoor: PP Placard (1.10m x 2.50m), Int. Double:PP Placard (1.10m x 2.50m):446941
In: N00 - COO
Type - OperationType: DOUBLE_DOOR_SINGLE_SWING; ParameterTakesPrecedence: no; Sizeable: no; Material: Bois - Panneau de porte, Finition Peinture - Blanc satiné, Bois - Cadre de porte
Type - Int. Double:PP Placard (1.10m x 2.50m):446941 - PanelOperation: SWINGING
OverallHeight: 248.5 cm; OverallWidth: 117 cm
Pset_DoorCommon - IsExternal: no; Reference: PP Placard (1.10m x 2.50m); ThermalTransmittance: 3.6886 kg/K/s3
Pset_QuantityTakeOff - Reference: PP Placard (1.10m x 2.50m)

# IfcDoor: PP Placard (1.10m x 2.50m), Int. Double:PP Placard (1.10m x 2.50m):447251
In: N00 - COO
Type - OperationType: DOUBLE_DOOR_SINGLE_SWING; ParameterTakesPrecedence: no; Sizeable: no; Material: Bois - Panneau de porte, Finition Peinture - Blanc satiné, Bois - Cadre de porte
Type - Int. Double:PP Placard (1.10m x 2.50m):447251 - PanelOperation: SWINGING
OverallHeight: 248.5 cm; OverallWidth: 117 cm
Pset_DoorCommon - IsExternal: no; Reference: PP Placard (1.10m x 2.50m); ThermalTransmittance: 3.6886 kg/K/s3
Pset_QuantityTakeOff - Reference: PP Placard (1.10m x 2.50m)

# IfcDoor: PP Placard (1.10m x 2.50m), Int. Double:PP Placard (1.10m x 2.50m):447274
In: N00 - COO
Type - OperationType: DOUBLE_DOOR_SINGLE_SWING; ParameterTakesPrecedence: no; Sizeable: no; Material: Bois - Panneau de porte, Finition Peinture - Blanc satiné, Bois - Cadre de porte
Type - Int. Double:PP Placard (1.10m x 2.50m):447274 - PanelOperation: SWINGING
OverallHeight: 248.5 cm; OverallWidth: 117 cm
Pset_DoorCommon - IsExternal: no; Reference: PP Placard (1.10m x 2.50m); ThermalTransmittance: 3.6886 kg/K/s3
Pset_QuantityTakeOff - Reference: PP Placard (1.10m x 2.50m)

# IfcDoor: PP Placard (1.26m x 2.04m), Int. Double:PP Placard (1.26m x 2.04m):403946
In: N00 - COO
Type - OperationType: DOUBLE_DOOR_SINGLE_SWING; ParameterTakesPrecedence: no; Sizeable: no; Material: Bois - Panneau de porte, Finition Peinture - Blanc satiné, Bois - Cadre de porte
Type - Int. Double:PP Placard (1.26m x 2.04m):403946 - PanelOperation: SWINGING
OverallHeight: 304.5 cm; OverallWidth: 137 cm
Pset_DoorCommon - IsExternal: no; Reference: PP Placard (1.26m x 2.04m); ThermalTransmittance: 3.6886 kg/K/s3
Pset_QuantityTakeOff - Reference: PP Placard (1.26m x 2.04m)

# IfcDoor: PP Placard (1.26m x 2.04m), Int. Double:PP Placard (1.26m x 2.04m):446544
In: N00 - COO
Type - OperationType: DOUBLE_DOOR_SINGLE_SWING; ParameterTakesPrecedence: no; Sizeable: no; Material: Bois - Panneau de porte, Finition Peinture - Blanc satiné, Bois - Cadre de porte
Type - Int. Double:PP Placard (1.26m x 2.04m):446544 - PanelOperation: SWINGING
OverallHeight: 304.5 cm; OverallWidth: 137 cm
Pset_DoorCommon - IsExternal: no; Reference: PP Placard (1.26m x 2.04m); ThermalTransmittance: 3.6886 kg/K/s3
Pset_QuantityTakeOff - Reference: PP Placard (1.26m x 2.04m)

# IfcDoor: PP Placard (1.35m x 2.04m), Int. Double:PP Placard (1.35m x 2.04m):1905426
In: N00 - COO
Type - OperationType: DOUBLE_DOOR_SINGLE_SWING; ParameterTakesPrecedence: no; Sizeable: no; Material: Bois - Panneau de porte, Finition Peinture - Blanc satiné, Bois - Cadre de porte
Type - Int. Double:PP Placard (1.35m x 2.04m):1905426 - PanelOperation: SWINGING
OverallHeight: 207.5 cm; OverallWidth: 142 cm
Pset_DoorCommon - IsExternal: no; Reference: PP Placard (1.35m x 2.04m); ThermalTransmittance: 3.6886 kg/K/s3
Pset_QuantityTakeOff - Reference: PP Placard (1.35m x 2.04m)

# IfcDoor: PP Placard (1.88m x 2.04m), Int. Double:PP Placard (1.88m x 2.04m):790799
In: N00 - COO
Type - OperationType: DOUBLE_DOOR_SINGLE_SWING; ParameterTakesPrecedence: no; Sizeable: no; Material: Bois - Panneau de porte, Finition Peinture - Blanc satiné, Bois - Cadre de porte
Type - Int. Double:PP Placard (1.88m x 2.04m):790799 - PanelOperation: SWINGING
OverallHeight: 207.5 cm; OverallWidth: 195 cm
Pset_DoorCommon - IsExternal: no; Reference: PP Placard (1.88m x 2.04m); ThermalTransmittance: 3.6886 kg/K/s3
Pset_QuantityTakeOff - Reference: PP Placard (1.88m x 2.04m)

# IfcDoor: PP airel poubelle(1.66m x 2.04m), Int. Double:PP airel poubelle(1.66m x 2.04m):1428170
In: N00 - COO
Type - OperationType: DOUBLE_DOOR_SINGLE_SWING; ParameterTakesPrecedence: no; Sizeable: no; Material: Bois - Panneau de porte, Finition Peinture - Blanc satiné, Bois - Cadre de porte
Type - Int. Double:PP airel poubelle(1.66m x 2.04m):1428170 - PanelOperation: SWINGING
OverallHeight: 200 cm; OverallWidth: 173 cm
Pset_DoorCommon - IsExternal: no; Reference: PP airel poubelle(1.66m x 2.04m); ThermalTransmittance: 3.6886 kg/K/s3
Pset_QuantityTakeOff - Reference: PP airel poubelle(1.66m x 2.04m)

# IfcDoor: PP chaufferie (1.80m x 2.50m), Int. Tierce:PP chaufferie (1.80m x 2.50m):1786058
In: N00 - COO
Type - OperationType: DOUBLE_DOOR_SINGLE_SWING; ParameterTakesPrecedence: no; Sizeable: no; Material: Finition Peinture - Blanc satiné, Aluminium bardage, Aluminium
Type - Int. Tierce:PP chaufferie (1.80m x 2.50m):1786058 - PanelOperation: SWINGING
OverallHeight: 253.5 cm; OverallWidth: 151 cm
Pset_DoorCommon - IsExternal: no; Reference: PP chaufferie (1.80m x 2.50m); ThermalTransmittance: 5.5617 kg/K/s3
Pset_QuantityTakeOff - Reference: PP chaufferie (1.80m x 2.50m)

# IfcDoor: PP simple (0.93m x 2.50m), Int. Simple:PP simple (0.93m x 2.50m):1976105
In: N00 - COO
Type - OperationType: SINGLE_SWING_LEFT; ParameterTakesPrecedence: no; Sizeable: no; Material: Finition Peinture - Blanc satiné, Bois - Panneau de porte, Bois - Cadre de porte
Type - Int. Simple:PP simple (0.93m x 2.50m):1976105 - PanelOperation: SWINGING
OverallHeight: 248.5 cm; OverallWidth: 100 cm
Pset_DoorCommon - IsExternal: no; Reference: PP simple (0.93m x 2.50m)
Pset_QuantityTakeOff - Reference: PP simple (0.93m x 2.50m)

# IfcDoor: PP simple (0.93m x 2.50m) (15)
Type - OperationType: SINGLE_SWING_LEFT; ParameterTakesPrecedence: no; Sizeable: no; Material: Finition Peinture - Blanc satiné, Bois - Panneau de porte, Bois - Cadre de porte
Type - Int. Simple:PP simple (0.93m x 2.50m):397206 - PanelOperation: SWINGING
OverallHeight: 248.5 cm; OverallWidth: 100 cm
Pset_DoorCommon - IsExternal: no; Reference: PP simple (0.93m x 2.50m)
Pset_QuantityTakeOff - Reference: PP simple (0.93m x 2.50m)
Name (Int. Simple:PP simple (0.93m x 2.50m):...) | In
397206 | N00 - COO
433346 | N00 - COO
433381 | N00 - COO
433599 | N00 - COO
442117 | N00 - COO
442141 | N00 - COO
442279 | N00 - COO
442423 | N00 - COO
527187 | TR - N02 - ARCH
531789 | TR - N02 - ARCH
531815 | TR - N02 - ARCH
531836 | TR - N02 - ARCH
919789 | N00 - COO
936931 | N00 - COO
1351422 | TR - N02 - ARCH

# IfcDoor: PP simple (0.93m x 2.50m) (4)
In: N00 - COO
Type - OperationType: SINGLE_SWING_LEFT; ParameterTakesPrecedence: no; Sizeable: no; Material: Finition Peinture - Blanc satiné, Bois - Panneau de porte, Bois - Cadre de porte
Type - Int. Simple:PP simple (0.93m x 2.50m):442329 - PanelOperation: SWINGING
OverallHeight: 248.5 cm; OverallWidth: 100 cm
Pset_DoorCommon - IsExternal: no; Reference: PP simple (0.93m x 2.50m)
Pset_QuantityTakeOff - Reference: PP simple (0.93m x 2.50m)
Name (Int. Simple:PP simple (0.93m x 2.50m):...)
442329
456862
456893
456944

# IfcDoor: PP simple (0.93m x 2.50m) (2)
In: N00 - COO
Type - OperationType: SINGLE_SWING_LEFT; ParameterTakesPrecedence: no; Sizeable: no; Material: Finition Peinture - Blanc satiné, Bois - Panneau de porte, Bois - Cadre de porte
Type - Int. Simple:PP simple (0.93m x 2.50m):446710 - PanelOperation: SWINGING
OverallHeight: 248.5 cm; OverallWidth: 100 cm
Pset_DoorCommon - IsExternal: no; Reference: PP simple (0.93m x 2.50m)
Pset_QuantityTakeOff - Reference: PP simple (0.93m x 2.50m)
Name (Int. Simple:PP simple (0.93m x 2.50m):...)
446710
793670

# IfcDoor: PP simple (0.93m x 2.50m) (15)
Type - OperationType: SINGLE_SWING_LEFT; ParameterTakesPrecedence: no; Sizeable: no; Material: Finition Peinture - Blanc satiné, Bois - Panneau de porte, Bois - Cadre de porte
Type - Int. Simple:PP simple (0.93m x 2.50m):446761 - PanelOperation: SWINGING
OverallHeight: 248.5 cm; OverallWidth: 100 cm
Pset_DoorCommon - IsExternal: no; Reference: PP simple (0.93m x 2.50m)
Pset_QuantityTakeOff - Reference: PP simple (0.93m x 2.50m)
Name (Int. Simple:PP simple (0.93m x 2.50m):...) | In
446761 | N00 - COO
452957 | N00 - COO
461230 | N00 - COO
461384 | N00 - COO
461411 | N00 - COO
461433 | N00 - COO
509531 | Toiture - Cuisine
514002 | Toiture - Cuisine
517500 | Toiture - Cuisine
527142 | TR - N02 - ARCH
531584 | TR - N02 - ARCH
531776 | TR - N02 - ARCH
532800 | TR - N02 - ARCH
1350075 | Toiture - Cuisine
1891646 | N00 - COO

# IfcDoor: PP simple (0.93m x 2.50m) (7)
In: N00 - COO
Type - OperationType: SINGLE_SWING_LEFT; ParameterTakesPrecedence: no; Sizeable: no; Material: Finition Peinture - Blanc satiné, Bois - Panneau de porte, Bois - Cadre de porte
Type - Int. Simple:PP simple (0.93m x 2.50m):457031 - PanelOperation: SWINGING
OverallHeight: 248.5 cm; OverallWidth: 100 cm
Pset_DoorCommon - IsExternal: no; Reference: PP simple (0.93m x 2.50m)
Pset_QuantityTakeOff - Reference: PP simple (0.93m x 2.50m)
Name (Int. Simple:PP simple (0.93m x 2.50m):...)
457031
457072
457102
457120
457144
457164
457278

# IfcDoor: PP simple (0.93m x 2.50m), Int. Simple:PP simple (0.93m x 2.50m):1015872
In: N00 - COO
Type - OperationType: SINGLE_SWING_RIGHT; ParameterTakesPrecedence: no; Sizeable: no; Material: Finition Peinture - Blanc satiné, Bois - Panneau de porte, Bois - Cadre de porte
Type - Int. Simple:PP simple (0.93m x 2.50m):1015872 - PanelOperation: SWINGING
OverallHeight: 248.5 cm; OverallWidth: 100 cm
Pset_DoorCommon - IsExternal: no; Reference: PP simple (0.93m x 2.50m)
Pset_QuantityTakeOff - Reference: PP simple (0.93m x 2.50m)

# IfcDoor: PP simple (0.93m x 2.50m) (14)
Type - OperationType: SINGLE_SWING_RIGHT; ParameterTakesPrecedence: no; Sizeable: no; Material: Finition Peinture - Blanc satiné, Bois - Panneau de porte, Bois - Cadre de porte
Type - Int. Simple:PP simple (0.93m x 2.50m):433863 - PanelOperation: SWINGING
OverallHeight: 248.5 cm; OverallWidth: 100 cm
Pset_DoorCommon - IsExternal: no; Reference: PP simple (0.93m x 2.50m)
Pset_QuantityTakeOff - Reference: PP simple (0.93m x 2.50m)
Name (Int. Simple:PP simple (0.93m x 2.50m):...) | In
433863 | N00 - COO
437793 | N00 - COO
442055 | N00 - COO
442087 | N00 - COO
442154 | N00 - COO
442176 | N00 - COO
442251 | N00 - COO
442395 | N00 - COO
527182 | TR - N02 - ARCH
527183 | TR - N02 - ARCH
527188 | TR - N02 - ARCH
531803 | TR - N02 - ARCH
919761 | N00 - COO
1351445 | TR - N02 - ARCH

# IfcDoor: PP simple (0.93m x 2.50m) (2)
In: N00 - COO
Type - OperationType: SINGLE_SWING_RIGHT; ParameterTakesPrecedence: no; Sizeable: no; Material: Finition Peinture - Blanc satiné, Bois - Panneau de porte, Bois - Cadre de porte
Type - Int. Simple:PP simple (0.93m x 2.50m):438480 - PanelOperation: SWINGING
OverallHeight: 248.5 cm; OverallWidth: 100 cm
Pset_DoorCommon - IsExternal: no; Reference: PP simple (0.93m x 2.50m)
Pset_QuantityTakeOff - Reference: PP simple (0.93m x 2.50m)
Name (Int. Simple:PP simple (0.93m x 2.50m):...)
438480
936949

# IfcDoor: PP simple (0.93m x 2.50m) (3)
In: N00 - COO
Type - OperationType: SINGLE_SWING_RIGHT; ParameterTakesPrecedence: no; Sizeable: no; Material: Finition Peinture - Blanc satiné, Bois - Panneau de porte, Bois - Cadre de porte
Type - Int. Simple:PP simple (0.93m x 2.50m):442315 - PanelOperation: SWINGING
OverallHeight: 248.5 cm; OverallWidth: 100 cm
Pset_DoorCommon - IsExternal: no; Reference: PP simple (0.93m x 2.50m)
Pset_QuantityTakeOff - Reference: PP simple (0.93m x 2.50m)
Name (Int. Simple:PP simple (0.93m x 2.50m):...)
442315
442353
1013929

# IfcDoor: PP simple (0.93m x 2.50m) (5)
In: N00 - COO
Type - OperationType: SINGLE_SWING_RIGHT; ParameterTakesPrecedence: no; Sizeable: no; Material: Finition Peinture - Blanc satiné, Bois - Panneau de porte, Bois - Cadre de porte
Type - Int. Simple:PP simple (0.93m x 2.50m):446624 - PanelOperation: SWINGING
OverallHeight: 248.5 cm; OverallWidth: 100 cm
Pset_DoorCommon - IsExternal: no; Reference: PP simple (0.93m x 2.50m)
Pset_QuantityTakeOff - Reference: PP simple (0.93m x 2.50m)
Name (Int. Simple:PP simple (0.93m x 2.50m):...)
446624
446647
446682
1015142
1338255

# IfcDoor: PP simple (0.93m x 2.50m) (16)
Type - OperationType: SINGLE_SWING_RIGHT; ParameterTakesPrecedence: no; Sizeable: no; Material: Finition Peinture - Blanc satiné, Bois - Panneau de porte, Bois - Cadre de porte
Type - Int. Simple:PP simple (0.93m x 2.50m):452936 - PanelOperation: SWINGING
OverallHeight: 248.5 cm; OverallWidth: 100 cm
Pset_DoorCommon - IsExternal: no; Reference: PP simple (0.93m x 2.50m)
Pset_QuantityTakeOff - Reference: PP simple (0.93m x 2.50m)
Name (Int. Simple:PP simple (0.93m x 2.50m):...) | In
452936 | N00 - COO
452981 | N00 - COO
461367 | N00 - COO
461498 | N00 - COO
509611 | Toiture - Cuisine
509737 | Toiture - Cuisine
519188 | Toiture - Cuisine
519215 | Toiture - Cuisine
527143 | TR - N02 - ARCH
527146 | TR - N02 - ARCH
527149 | TR - N02 - ARCH
527150 | TR - N02 - ARCH
527181 | TR - N02 - ARCH
527186 | TR - N02 - ARCH
532825 | TR - N02 - ARCH
532891 | TR - N02 - ARCH

# IfcDoor: PP simple (0.93m x 2.50m) (2)
In: N00 - COO
Type - OperationType: SINGLE_SWING_RIGHT; ParameterTakesPrecedence: no; Sizeable: no; Material: Finition Peinture - Blanc satiné, Bois - Panneau de porte, Bois - Cadre de porte
Type - Int. Simple:PP simple (0.93m x 2.50m):457051 - PanelOperation: SWINGING
OverallHeight: 248.5 cm; OverallWidth: 100 cm
Pset_DoorCommon - IsExternal: no; Reference: PP simple (0.93m x 2.50m)
Pset_QuantityTakeOff - Reference: PP simple (0.93m x 2.50m)
Name (Int. Simple:PP simple (0.93m x 2.50m):...)
457051
457250

# IfcDoor: PP simple (0.93m x 2.50m), Int. Simple:PP simple (0.93m x 2.50m):461283
In: N00 - COO
Type - OperationType: SINGLE_SWING_RIGHT; ParameterTakesPrecedence: no; Sizeable: no; Material: Finition Peinture - Blanc satiné, Bois - Panneau de porte, Bois - Cadre de porte
Type - Int. Simple:PP simple (0.93m x 2.50m):461283 - PanelOperation: SWINGING
OverallHeight: 248.5 cm; OverallWidth: 100 cm
Pset_DoorCommon - IsExternal: no; Reference: PP simple (0.93m x 2.50m)
Pset_QuantityTakeOff - Reference: PP simple (0.93m x 2.50m)

# IfcDoor: PP simple accès technique coursive ext (0.93m x 2.50m) 2 (2)
Type - OperationType: SINGLE_SWING_LEFT; ParameterTakesPrecedence: no; Sizeable: no; Material: Finition Peinture - Blanc satiné, Bois - Panneau de porte, Bois - Cadre de porte
Type - Int. Simple:PP simple accès technique coursive ext (0.93m x 2.50m) 2:923996 - PanelOperation: SWINGING
OverallHeight: 270 cm; OverallWidth: 90 cm
Pset_DoorCommon - IsExternal: no; Reference: PP simple accès technique coursive ext (0.93m x 2.50m) 2
Pset_QuantityTakeOff - Reference: PP simple accès technique coursive ext (0.93m x 2.50m) 2
Name (Int. Simple:PP simple accès technique coursive ext (0.93m x 2.50m) 2:...) | In
923996 | TR - N02 - ARCH
1726946 | Toiture - Cuisine

# IfcDoor: PV (0.93m x 2.50m), Int. Simple:PV (0.93m x 2.50m):1800699
In: TR - N02 - ARCH
Type - OperationType: SINGLE_SWING_LEFT; ParameterTakesPrecedence: no; Sizeable: no; Material: Finition Peinture - Blanc satiné, Bois - Panneau de porte, Bois - Cadre de porte
Type - Int. Simple:PV (0.93m x 2.50m):1800699 - PanelOperation: SWINGING
OverallHeight: 248.5 cm; OverallWidth: 100 cm
Pset_DoorCommon - IsExternal: no; Reference: PV (0.93m x 2.50m)
Pset_QuantityTakeOff - Reference: PV (0.93m x 2.50m)

# IfcDoor: PV (0.93m x 2.50m) (28)
Type - OperationType: SINGLE_SWING_LEFT; ParameterTakesPrecedence: no; Sizeable: no; Material: Finition Peinture - Blanc satiné, Bois - Panneau de porte, Bois - Cadre de porte
Type - Int. Simple:PV (0.93m x 2.50m):509586 - PanelOperation: SWINGING
OverallHeight: 248.5 cm; OverallWidth: 100 cm
Pset_DoorCommon - IsExternal: no; Reference: PV (0.93m x 2.50m)
Pset_QuantityTakeOff - Reference: PV (0.93m x 2.50m)
Name (Int. Simple:PV (0.93m x 2.50m):...) | In
509586 | Toiture - Cuisine
509708 | Toiture - Cuisine
513782 | Toiture - Cuisine
513844 | Toiture - Cuisine
513885 | Toiture - Cuisine
513934 | Toiture - Cuisine
514052 | Toiture - Cuisine
517298 | Toiture - Cuisine
517404 | Toiture - Cuisine
517522 | Toiture - Cuisine
517577 | Toiture - Cuisine
517643 | Toiture - Cuisine
517725 | Toiture - Cuisine
519157 | Toiture - Cuisine
519270 | Toiture - Cuisine
519648 | Toiture - Cuisine
527145 | TR - N02 - ARCH
527148 | TR - N02 - ARCH
527179 | TR - N02 - ARCH
527184 | TR - N02 - ARCH
527190 | TR - N02 - ARCH
527192 | TR - N02 - ARCH
531527 | TR - N02 - ARCH
531598 | TR - N02 - ARCH
531662 | TR - N02 - ARCH
531713 | TR - N02 - ARCH
532781 | TR - N02 - ARCH
532944 | TR - N02 - ARCH

# IfcDoor: PV (0.93m x 2.50m), Int. Simple:PV (0.93m x 2.50m):519325
In: Toiture - Cuisine
Type - OperationType: SINGLE_SWING_LEFT; ParameterTakesPrecedence: no; Sizeable: no; Material: Finition Peinture - Blanc satiné, Bois - Panneau de porte, Bois - Cadre de porte
Type - Int. Simple:PV (0.93m x 2.50m):519325 - PanelOperation: SWINGING
OverallHeight: 248.5 cm; OverallWidth: 100 cm
Pset_DoorCommon - IsExternal: no; Reference: PV (0.93m x 2.50m)
Pset_QuantityTakeOff - Reference: PV (0.93m x 2.50m)

# IfcDoor: PV (0.93m x 2.50m) (28)
Type - OperationType: SINGLE_SWING_RIGHT; ParameterTakesPrecedence: no; Sizeable: no; Material: Finition Peinture - Blanc satiné, Bois - Panneau de porte, Bois - Cadre de porte
Type - Int. Simple:PV (0.93m x 2.50m):509556 - PanelOperation: SWINGING
OverallHeight: 248.5 cm; OverallWidth: 100 cm
Pset_DoorCommon - IsExternal: no; Reference: PV (0.93m x 2.50m)
Pset_QuantityTakeOff - Reference: PV (0.93m x 2.50m)
Name (Int. Simple:PV (0.93m x 2.50m):...) | In
509556 | Toiture - Cuisine
509660 | Toiture - Cuisine
513814 | Toiture - Cuisine
513867 | Toiture - Cuisine
513905 | Toiture - Cuisine
513962 | Toiture - Cuisine
514069 | Toiture - Cuisine
517360 | Toiture - Cuisine
517450 | Toiture - Cuisine
517555 | Toiture - Cuisine
517614 | Toiture - Cuisine
517669 | Toiture - Cuisine
517770 | Toiture - Cuisine
519131 | Toiture - Cuisine
519236 | Toiture - Cuisine
519299 | Toiture - Cuisine
527144 | TR - N02 - ARCH
527147 | TR - N02 - ARCH
527180 | TR - N02 - ARCH
527185 | TR - N02 - ARCH
527189 | TR - N02 - ARCH
527191 | TR - N02 - ARCH
531559 | TR - N02 - ARCH
531632 | TR - N02 - ARCH
531694 | TR - N02 - ARCH
531748 | TR - N02 - ARCH
532743 | TR - N02 - ARCH
532906 | TR - N02 - ARCH

# IfcDoor: PV (0.93m x 2.50m), Int. Simple:PV (0.93m x 2.50m):519361
In: Toiture - Cuisine
Type - OperationType: SINGLE_SWING_RIGHT; ParameterTakesPrecedence: no; Sizeable: no; Material: Finition Peinture - Blanc satiné, Bois - Panneau de porte, Bois - Cadre de porte
Type - Int. Simple:PV (0.93m x 2.50m):519361 - PanelOperation: SWINGING
OverallHeight: 248.5 cm; OverallWidth: 100 cm
Pset_DoorCommon - IsExternal: no; Reference: PV (0.93m x 2.50m)
Pset_QuantityTakeOff - Reference: PV (0.93m x 2.50m)

# IfcDoor: PV (0.93m x 3.00m) (5)
In: N00 - COO
Type - OperationType: SINGLE_SWING_LEFT; ParameterTakesPrecedence: no; Sizeable: no; Material: Finition Peinture - Blanc satiné, Bois - Panneau de porte, Bois - Cadre de porte
Type - Int. Simple:PV (0.93m x 3.00m):397053 - PanelOperation: SWINGING
OverallHeight: 304.5 cm; OverallWidth: 100 cm
Pset_DoorCommon - IsExternal: no; Reference: PV (0.93m x 3.00m)
Pset_QuantityTakeOff - Reference: PV (0.93m x 3.00m)
Name (Int. Simple:PV (0.93m x 3.00m):...)
397053
397113
397191
407186
1219787

# IfcDoor: PV (0.93m x 3.00m) (7)
In: N00 - COO
Type - OperationType: SINGLE_SWING_LEFT; ParameterTakesPrecedence: no; Sizeable: no; Material: Finition Peinture - Blanc satiné, Bois - Panneau de porte, Bois - Cadre de porte
Type - Int. Simple:PV (0.93m x 3.00m):398060 - PanelOperation: SWINGING
OverallHeight: 304.5 cm; OverallWidth: 100 cm
Pset_DoorCommon - IsExternal: no; Reference: PV (0.93m x 3.00m)
Pset_QuantityTakeOff - Reference: PV (0.93m x 3.00m)
Name (Int. Simple:PV (0.93m x 3.00m):...)
398060
398174
398215
398262
430310
436159
1903567

# IfcDoor: PV (0.93m x 3.00m), Int. Simple:PV (0.93m x 3.00m):484281
In: N00 - COO
Type - OperationType: SINGLE_SWING_LEFT; ParameterTakesPrecedence: no; Sizeable: no; Material: Finition Peinture - Blanc satiné, Bois - Panneau de porte, Bois - Cadre de porte
Type - Int. Simple:PV (0.93m x 3.00m):484281 - PanelOperation: SWINGING
OverallHeight: 304.5 cm; OverallWidth: 100 cm
Pset_DoorCommon - IsExternal: no; Reference: PV (0.93m x 3.00m)
Pset_QuantityTakeOff - Reference: PV (0.93m x 3.00m)

# IfcDoor: PV (0.93m x 3.00m), Int. Simple:PV (0.93m x 3.00m):1904770
In: N00 - COO
Type - OperationType: SINGLE_SWING_RIGHT; ParameterTakesPrecedence: no; Sizeable: no; Material: Finition Peinture - Blanc satiné, Bois - Panneau de porte, Bois - Cadre de porte
Type - Int. Simple:PV (0.93m x 3.00m):1904770 - PanelOperation: SWINGING
OverallHeight: 304.5 cm; OverallWidth: 100 cm
Pset_DoorCommon - IsExternal: no; Reference: PV (0.93m x 3.00m)
Pset_QuantityTakeOff - Reference: PV (0.93m x 3.00m)

# IfcDoor: PV (0.93m x 3.00m) (3)
In: N00 - COO
Type - OperationType: SINGLE_SWING_RIGHT; ParameterTakesPrecedence: no; Sizeable: no; Material: Finition Peinture - Blanc satiné, Bois - Panneau de porte, Bois - Cadre de porte
Type - Int. Simple:PV (0.93m x 3.00m):338585 - PanelOperation: SWINGING
OverallHeight: 304.5 cm; OverallWidth: 100 cm
Pset_DoorCommon - IsExternal: no; Reference: PV (0.93m x 3.00m)
Pset_QuantityTakeOff - Reference: PV (0.93m x 3.00m)
Name (Int. Simple:PV (0.93m x 3.00m):...)
338585
338610
394326

# IfcDoor: PV (0.93m x 3.00m) (10)
In: N00 - COO
Type - OperationType: SINGLE_SWING_RIGHT; ParameterTakesPrecedence: no; Sizeable: no; Material: Finition Peinture - Blanc satiné, Bois - Panneau de porte, Bois - Cadre de porte
Type - Int. Simple:PV (0.93m x 3.00m):361198 - PanelOperation: SWINGING
OverallHeight: 304.5 cm; OverallWidth: 100 cm
Pset_DoorCommon - IsExternal: no; Reference: PV (0.93m x 3.00m)
Pset_QuantityTakeOff - Reference: PV (0.93m x 3.00m)
Name (Int. Simple:PV (0.93m x 3.00m):...)
361198
397008
397154
397228
397371
398046
430402
920153
1219942
1904518

# IfcDoor: PV (0.93m x 3.00m) (2)
In: N00 - COO
Type - OperationType: SINGLE_SWING_RIGHT; ParameterTakesPrecedence: no; Sizeable: no; Material: Finition Peinture - Blanc satiné, Bois - Panneau de porte, Bois - Cadre de porte
Type - Int. Simple:PV (0.93m x 3.00m):407236 - PanelOperation: SWINGING
OverallHeight: 304.5 cm; OverallWidth: 100 cm
Pset_DoorCommon - IsExternal: no; Reference: PV (0.93m x 3.00m)
Pset_QuantityTakeOff - Reference: PV (0.93m x 3.00m)
Name (Int. Simple:PV (0.93m x 3.00m):...)
407236
430236

# IfcDoor: PV (1.90m x 3.00m), Int. Double:PV (1.90m x 3.00m):1996927
In: N00 - COO
Type - OperationType: DOUBLE_DOOR_SINGLE_SWING; ParameterTakesPrecedence: no; Sizeable: no; Material: Bois - Panneau de porte, Finition Peinture - Blanc satiné, Bois - Cadre de porte
Type - Int. Double:PV (1.90m x 3.00m):1996927 - PanelOperation: SWINGING
OverallHeight: 304.5 cm; OverallWidth: 197 cm
Pset_DoorCommon - IsExternal: no; Reference: PV (1.90m x 3.00m); ThermalTransmittance: 3.6886 kg/K/s3
Pset_QuantityTakeOff - Reference: PV (1.90m x 3.00m)

# IfcDoor: PV (1.90m x 3.00m), Int. Double:PV (1.90m x 3.00m):393510
In: N00 - COO
Type - OperationType: DOUBLE_DOOR_SINGLE_SWING; ParameterTakesPrecedence: no; Sizeable: no; Material: Bois - Panneau de porte, Finition Peinture - Blanc satiné, Bois - Cadre de porte
Type - Int. Double:PV (1.90m x 3.00m):393510 - PanelOperation: SWINGING
OverallHeight: 304.5 cm; OverallWidth: 197 cm
Pset_DoorCommon - IsExternal: no; Reference: PV (1.90m x 3.00m); ThermalTransmittance: 3.6886 kg/K/s3
Pset_QuantityTakeOff - Reference: PV (1.90m x 3.00m)

# IfcDoor: PV (1.90m x 3.00m), Int. Double:PV (1.90m x 3.00m):394304
In: N00 - COO
Type - OperationType: DOUBLE_DOOR_SINGLE_SWING; ParameterTakesPrecedence: no; Sizeable: no; Material: Bois - Panneau de porte, Finition Peinture - Blanc satiné, Bois - Cadre de porte
Type - Int. Double:PV (1.90m x 3.00m):394304 - PanelOperation: SWINGING
OverallHeight: 304.5 cm; OverallWidth: 197 cm
Pset_DoorCommon - IsExternal: no; Reference: PV (1.90m x 3.00m); ThermalTransmittance: 3.6886 kg/K/s3
Pset_QuantityTakeOff - Reference: PV (1.90m x 3.00m)

# IfcDoor: PV (2.50m x 2.04m) (3)
Type - OperationType: DOUBLE_DOOR_SINGLE_SWING; ParameterTakesPrecedence: no; Sizeable: no; Material: Bois - Panneau de porte, Finition Peinture - Blanc satiné, Bois - Cadre de porte
Type - Int. Double:PV (2.50m x 2.04m):552841 - PanelOperation: SWINGING
OverallHeight: 248.5 cm; OverallWidth: 250 cm
Pset_DoorCommon - IsExternal: no; Reference: PV (2.50m x 2.04m); ThermalTransmittance: 3.6886 kg/K/s3
Pset_QuantityTakeOff - Reference: PV (2.50m x 2.04m)
Name (Int. Double:PV (2.50m x 2.04m):...) | In
552841 | TR - N02 - ARCH
552862 | TR - N02 - ARCH
552911 | Toiture - Cuisine

# IfcDoor: PV (2.50m x 2.04m), Int. Double:PV (2.50m x 2.04m):552938
In: Toiture - Cuisine
Type - OperationType: DOUBLE_DOOR_SINGLE_SWING; ParameterTakesPrecedence: no; Sizeable: no; Material: Bois - Panneau de porte, Finition Peinture - Blanc satiné, Bois - Cadre de porte
Type - Int. Double:PV (2.50m x 2.04m):552938 - PanelOperation: SWINGING
OverallHeight: 248.5 cm; OverallWidth: 250 cm
Pset_DoorCommon - IsExternal: no; Reference: PV (2.50m x 2.04m); ThermalTransmittance: 3.6886 kg/K/s3
Pset_QuantityTakeOff - Reference: PV (2.50m x 2.04m)

# IfcDoor: PV (2.50m x 3.06m), Int. Double:PV (2.50m x 3.06m):551622
In: N00 - COO
Type - OperationType: DOUBLE_DOOR_SINGLE_SWING; ParameterTakesPrecedence: no; Sizeable: no; Material: Bois - Panneau de porte, Finition Peinture - Blanc satiné, Bois - Cadre de porte
Type - Int. Double:PV (2.50m x 3.06m):551622 - PanelOperation: SWINGING
OverallHeight: 304.5 cm; OverallWidth: 250 cm
Pset_DoorCommon - IsExternal: no; Reference: PV (2.50m x 3.06m); ThermalTransmittance: 3.6886 kg/K/s3
Pset_QuantityTakeOff - Reference: PV (2.50m x 3.06m)

# IfcDoor: PV (2.50m x 3.06m), Int. Double:PV (2.50m x 3.06m):551646
In: N00 - COO
Type - OperationType: DOUBLE_DOOR_SINGLE_SWING; ParameterTakesPrecedence: no; Sizeable: no; Material: Bois - Panneau de porte, Finition Peinture - Blanc satiné, Bois - Cadre de porte
Type - Int. Double:PV (2.50m x 3.06m):551646 - PanelOperation: SWINGING
OverallHeight: 304.5 cm; OverallWidth: 250 cm
Pset_DoorCommon - IsExternal: no; Reference: PV (2.50m x 3.06m); ThermalTransmittance: 3.6886 kg/K/s3
Pset_QuantityTakeOff - Reference: PV (2.50m x 3.06m)

# IfcDoor: Porte vitrée bois - SAS ENTREE RDC 2x90 (4)
In: N00 - COO
Type - ConstructionType: USERDEFINED; ParameterTakesPrecedence: no; Sizeable: no; Material: Verre, Aluminium
OverallHeight: 192.757 cm; OverallWidth: 321 cm
Pset_DoorCommon - IsExternal: no; Reference: Porte vitrée bois - SAS ENTREE RDC 2x90
Pset_ManufacturerTypeInformation - Manufacturer: Schueco International KG
Pset_QuantityTakeOff - Reference: Porte vitrée bois - SAS ENTREE RDC 2x90
Name (Schueco_ADS-90-SimplySmart_Family-02-out:Porte vitrée bois - SAS ENTREE RDC 2x90:...)
946113
946238
1191068
1191332

# IfcDoor: RDC 100, Schueco_ADS-90-SimplySmart_Family-01-out:RDC 100:1045140
In: N00 - COO
Type - ConstructionType: USERDEFINED; ParameterTakesPrecedence: no; Sizeable: no; Material: Verre, Aluminium
OverallHeight: 328 cm; OverallWidth: 118.699 cm
Pset_DoorCommon - IsExternal: yes; Reference: RDC 100
Pset_ManufacturerTypeInformation - Manufacturer: Schueco International KG
Pset_QuantityTakeOff - Reference: RDC 100

# IfcDoor: RDC Tierce (5)
In: N00 - COO
Type - ConstructionType: USERDEFINED; ParameterTakesPrecedence: no; Sizeable: no; Material: Verre, Aluminium
Pset_DoorCommon - Reference: RDC Tierce
Pset_ManufacturerTypeInformation - Manufacturer: Schueco International KG
Pset_QuantityTakeOff - Reference: RDC Tierce
Name (Schueco_ADS-90-SimplySmart_Family-02-out:RDC Tierce:...) | OverallHeight (cm) | OverallWidth (cm) | IsExternal
1012695 | 150 | 265 | yes
1040030 | 180 | 326 | yes
1135266 | 328 | 155 | yes
1218589 | 155 | 328 | no
1300377 | 160.306 | 328 | no

# IfcDoor: SAS ENTREE RDC 2x90 (9)
In: N00 - COO
Type - ConstructionType: USERDEFINED; ParameterTakesPrecedence: no; Sizeable: no; Material: Verre, Aluminium
Pset_DoorCommon - Reference: SAS ENTREE RDC 2x90
Pset_ManufacturerTypeInformation - Manufacturer: Schueco International KG
Pset_QuantityTakeOff - Reference: SAS ENTREE RDC 2x90
Name (Schueco_ADS-90-SimplySmart_Family-02-out:SAS ENTREE RDC 2x90:...) | OverallHeight (cm) | OverallWidth (cm) | IsExternal
704495 | 192.757 | 321 | no
795978 | 200 | 321 | yes
840875 | 200 | 321 | yes
945922 | 192.757 | 321 | no
1076504 | 328 | 155 | yes
1441118 | 265 | 223.227 | yes
1786054 | 321 | 192.757 | no
1786055 | 321 | 192.757 | no
1968656 | 192.757 | 321 | no

# IfcFlowTerminal: 070650:Typ 1 (9)
Classification: D2010400 Sinks (Uniformat); Material: Stahl, verchromt, Duravit Keramik
Pset_DistributionFlowElementCommon - Reference: Typ 1; sets with these values: 2
Pset_ManufacturerTypeInformation - Manufacturer: Duravit
Name (070650:Typ 1:...) | In
1166246 | A-16
1167864 | A-16
1168007 | D-2
1168029 | D-2
1168105 | C-17
1168188 | C-17
1168235 | B-10
1366781 | B-21
1809909 | TR - N02 - ARCH

# IfcFlowTerminal: Bac à douche rectangulaire:90 x 75 cm (11)
Material: Métal - Chrome, Acrylique - Blanc
Pset_DistributionFlowElementCommon - Reference: 90 x 75 cm; sets with these values: 2
Name (Bac à douche rectangulaire:90 x 75 cm:...) | In
443465 | N00 - COO
443596 | N00 - COO
443773 | N00 - COO
443852 | N00 - COO
444460 | A-16
444507 | A-16
444985 | A-15
487969 | D-8
488266 | D-8
488459 | D-9
488622 | D-9

# IfcFlowTerminal: Bac à douche rectangulaire:90 x 80 cm, Bac à douche rectangulaire:90 x 80 cm:920888
In: B-17
Material: Métal - Chrome, Acrylique - Blanc
Pset_DistributionFlowElementCommon - Reference: 90 x 80 cm; sets with these values: 2

# IfcFlowTerminal: Lavabo type 02:Typ 1 (16)
Classification: D2010400 Sinks (Uniformat); Material: Stahl, verchromt, Duravit Keramik
Pset_DistributionFlowElementCommon - Reference: Typ 1; sets with these values: 2
Pset_ManufacturerTypeInformation - Manufacturer: Duravit
Name (Lavabo type 02:Typ 1:...) | In
442780 | D-9
442806 | N00 - COO
442826 | A-15
456636 | B-20
456662 | B-20
456692 | B-20
456706 | B-20
456740 | B-20
456773 | B-20
456795 | B-20
456819 | B-20
485973 | C-5
487010 | C-5
529394 | B-21
921321 | B-11
921357 | B-12

# IfcFlowTerminal: Urinoir:Urinoir (6)
Material: Métal - Chrome poli, Porcelaine - Blanche
Pset_DistributionFlowElementCommon - Reference: Urinoir; sets with these values: 2
Name (Urinoir:Urinoir:...) | In
457897 | B-20
457920 | B-20
457955 | B-20
486744 | C-5
1439615 | B-20
1439616 | B-20

# IfcFlowTerminal: Vidoir:000 White (8)
Pset_DistributionFlowElementCommon - Reference: 000 White; sets with these values: 2
Name (Vidoir:000 White:...) | In
456217 | E-8.3
515108 | E-8.4
520340 | E-8.5
534282 | E-8.6
534341 | E-8.7
566323 | E-8.2
920768 | B-17
1892185 | E. 8.1

# IfcFlowTerminal: Vidoir:400 White with LCC (2)
In: A-5
Pset_DistributionFlowElementCommon - Reference: 400 White with LCC; sets with these values: 2
Name (Vidoir:400 White with LCC:...)
1546474
1546550

# IfcFlowTerminal: WC PMR:Typ 1 (15)
Classification: D2010110 Water Closets - Single (Uniformat)
Pset_DistributionFlowElementCommon - Reference: Typ 1; sets with these values: 2
Pset_ManufacturerTypeInformation - Manufacturer: Duravit
Name (WC PMR:Typ 1:...) | In
398735 | C-17
398760 | C-17
442863 | D-9
442916 | D-8
442930 | A-15
455374 | B-20
455569 | D-2
455592 | D-2
456148 | B-20
485839 | C-5
486743 | C-5
529395 | TR - N02 - ARCH
920746 | B-17
1366667 | B-21
1904397 | B-10

# IfcFlowTerminal: WC suspendu - 01:550 x 360mm (10)
Material: Porcelaine - Blanche, Métal - Alu brossé
Pset_DistributionFlowElementCommon - Reference: 550 x 360mm; sets with these values: 2
Name (WC suspendu - 01:550 x 360mm:...) | In
455671 | B-20
455704 | B-20
455735 | B-20
455774 | B-20
455809 | B-20
455851 | B-20
455879 | B-20
455906 | B-20
456095 | B-20
486494 | C-5

# IfcMember: 100 x 50mm (247)
Type - PredefinedType: MEMBER
Type - Pset_MemberCommon - IsExternal: no; Reference: 100 x 50mm
Type - Pset_QuantityTakeOff - Reference: 100 x 50mm
Material: Plastique, blanc opaque
Name (Meneau rectangulaire:100 x 50mm:...) | In | IsExternal | Span (cm)
221277 | TR - N03 - ARCH | yes | 34.5353
221278 | TR - N03 - ARCH | yes | 95
221279 | TR - N03 - ARCH | yes | 286.45
221280 | TR - N03 - ARCH | yes | 286.45
221302 | TR - N03 - ARCH | yes | 92.5
221303 | TR - N03 - ARCH | yes | 95
221304 | TR - N03 - ARCH | yes | 95
221305 | TR - N03 - ARCH | yes | 95
221306 | TR - N03 - ARCH | yes | 95
221307 | TR - N03 - ARCH | yes | 95
221308 | TR - N03 - ARCH | yes | 95
221309 | TR - N03 - ARCH | yes | 100
221310 | TR - N03 - ARCH | yes | 100
221311 | TR - N03 - ARCH | yes | 100
221312 | TR - N03 - ARCH | yes | 100
221313 | TR - N03 - ARCH | yes | 100
221314 | TR - N03 - ARCH | yes | 100
221315 | TR - N03 - ARCH | yes | 37.0353
221316 | TR - N03 - ARCH | yes | 281.45
221317 | TR - N03 - ARCH | yes | 281.45
221318 | TR - N03 - ARCH | yes | 281.45
221319 | TR - N03 - ARCH | yes | 281.45
221320 | TR - N03 - ARCH | yes | 281.45
221321 | TR - N03 - ARCH | yes | 281.45
221322 | TR - N03 - ARCH | yes | 281.45
894182 | TR - N03 - ARCH | yes | 286.45
894183 | TR - N03 - ARCH | yes | 286.45
894184 | TR - N03 - ARCH | yes | 92.5
894185 | TR - N03 - ARCH | yes | 95
894186 | TR - N03 - ARCH | yes | 95
894187 | TR - N03 - ARCH | yes | 95
894188 | TR - N03 - ARCH | yes | 95
894189 | TR - N03 - ARCH | yes | 95
894190 | TR - N03 - ARCH | yes | 95
894191 | TR - N03 - ARCH | yes | 34.5353
894192 | TR - N03 - ARCH | yes | 286.45
894193 | TR - N03 - ARCH | yes | 286.45
894194 | TR - N03 - ARCH | yes | 286.45
894195 | TR - N03 - ARCH | yes | 286.45
894196 | TR - N03 - ARCH | yes | 286.45
894197 | TR - N03 - ARCH | yes | 286.45
894198 | TR - N03 - ARCH | yes | 286.45
894241 | TR - N03 - ARCH | yes | 286.45
894242 | TR - N03 - ARCH | yes | 286.45
894243 | TR - N03 - ARCH | yes | 92.5
894244 | TR - N03 - ARCH | yes | 95
894245 | TR - N03 - ARCH | yes | 95
894246 | TR - N03 - ARCH | yes | 95
894247 | TR - N03 - ARCH | yes | 95
894248 | TR - N03 - ARCH | yes | 95
894249 | TR - N03 - ARCH | yes | 95
894250 | TR - N03 - ARCH | yes | 34.5353
894251 | TR - N03 - ARCH | yes | 286.45
894252 | TR - N03 - ARCH | yes | 286.45
894253 | TR - N03 - ARCH | yes | 286.45
894254 | TR - N03 - ARCH | yes | 286.45
894255 | TR - N03 - ARCH | yes | 286.45
894256 | TR - N03 - ARCH | yes | 286.45
894257 | TR - N03 - ARCH | yes | 286.45
254101 | Toiture - Cuisine | yes | 95
254104 | Toiture - Cuisine | yes | 135
254112 | Toiture - Cuisine | yes | 90.1235
255250 | Toiture - Cuisine | yes | 100
255251 | Toiture - Cuisine | yes | 100
255252 | Toiture - Cuisine | yes | 100
255253 | Toiture - Cuisine | yes | 20
255254 | Toiture - Cuisine | yes | 140
255255 | Toiture - Cuisine | yes | 140
255256 | Toiture - Cuisine | yes | 140
255257 | Toiture - Cuisine | yes | 140
255258 | Toiture - Cuisine | yes | 140
255259 | Toiture - Cuisine | yes | 20.0002
255260 | Toiture - Cuisine | yes | 120
255261 | Toiture - Cuisine | yes | 140
255262 | Toiture - Cuisine | yes | 140
255263 | Toiture - Cuisine | yes | 140
255264 | Toiture - Cuisine | yes | 140
255265 | Toiture - Cuisine | yes | 140
255266 | Toiture - Cuisine | yes | 120
255267 | Toiture - Cuisine | yes | 20
255268 | Toiture - Cuisine | yes | 140
255269 | Toiture - Cuisine | yes | 140
255271 | Toiture - Cuisine | yes | 140
255272 | Toiture - Cuisine | yes | 140
255273 | Toiture - Cuisine | yes | 20.0002
255274 | Toiture - Cuisine | yes | 120
255275 | Toiture - Cuisine | yes | 140
255276 | Toiture - Cuisine | yes | 140
255278 | Toiture - Cuisine | yes | 140
255279 | Toiture - Cuisine | yes | 140
255280 | Toiture - Cuisine | yes | 120
255281 | Toiture - Cuisine | yes | 20
255282 | Toiture - Cuisine | yes | 140
255283 | Toiture - Cuisine | yes | 135
255286 | Toiture - Cuisine | yes | 95
255287 | Toiture - Cuisine | yes | 100
255288 | Toiture - Cuisine | yes | 100
255289 | Toiture - Cuisine | yes | 100
255290 | Toiture - Cuisine | yes | 20
255291 | Toiture - Cuisine | yes | 140
255293 | Toiture - Cuisine | yes | 100
255294 | Toiture - Cuisine | yes | 140
255295 | Toiture - Cuisine | yes | 140
255296 | Toiture - Cuisine | yes | 20.0002
255297 | Toiture - Cuisine | yes | 120
255298 | Toiture - Cuisine | yes | 140
255300 | Toiture - Cuisine | yes | 100
255301 | Toiture - Cuisine | yes | 140
255302 | Toiture - Cuisine | yes | 140
255303 | Toiture - Cuisine | yes | 120
255304 | Toiture - Cuisine | yes | 20
255305 | Toiture - Cuisine | yes | 140
255307 | Toiture - Cuisine | yes | 140
255308 | Toiture - Cuisine | yes | 140
255309 | Toiture - Cuisine | yes | 140
255310 | Toiture - Cuisine | yes | 20.0002
255311 | Toiture - Cuisine | yes | 120
255312 | Toiture - Cuisine | yes | 140
255314 | Toiture - Cuisine | yes | 140
255315 | Toiture - Cuisine | yes | 140
255316 | Toiture - Cuisine | yes | 140
255317 | Toiture - Cuisine | yes | 120
255318 | Toiture - Cuisine | yes | 20
255319 | Toiture - Cuisine | yes | 140
255322 | Toiture - Cuisine | yes | 80.1235
255323 | Toiture - Cuisine | yes | 80.1235
255324 | Toiture - Cuisine | yes | 80.1235
255325 | Toiture - Cuisine | yes | 80.1235
255326 | Toiture - Cuisine | yes | 80.1235
255327 | Toiture - Cuisine | yes | 80.1235
255328 | Toiture - Cuisine | yes | 80.1235
255329 | Toiture - Cuisine | yes | 80.1235
255330 | Toiture - Cuisine | yes | 80.1235
255332 | Toiture - Cuisine | yes | 80.1235
255333 | Toiture - Cuisine | yes | 80.1235
255334 | Toiture - Cuisine | yes | 80.1235
255335 | Toiture - Cuisine | yes | 80.1235
255336 | Toiture - Cuisine | yes | 80.1235
255337 | Toiture - Cuisine | yes | 80.1235
255338 | Toiture - Cuisine | yes | 80.1235
255340 | Toiture - Cuisine | yes | 80.1235
255341 | Toiture - Cuisine | yes | 80.1235
255343 | Toiture - Cuisine | yes | 80.1235
255344 | Toiture - Cuisine | yes | 80.1235
255346 | Toiture - Cuisine | yes | 80.1235
255347 | Toiture - Cuisine | yes | 80.1235
255348 | Toiture - Cuisine | yes | 80.1235
255350 | Toiture - Cuisine | yes | 80.1235
255351 | Toiture - Cuisine | yes | 80.1235
255352 | Toiture - Cuisine | yes | 80.1235
255354 | Toiture - Cuisine | yes | 80.1235
255355 | Toiture - Cuisine | yes | 80.1235
764788 | Toiture - Cuisine | yes | 90.1235
924947 | Toiture - Cuisine | yes | 140
925077 | Toiture - Cuisine | yes | 140
704950 | N00 - COO |  | 95.243
704951 | N00 - COO |  | 95.243
704952 | N00 - COO |  | 306
704953 | N00 - COO |  | 306
705183 | N00 - COO |  | 490
705184 | N00 - COO |  | 490
705185 | N00 - COO |  | 313
705186 | N00 - COO |  | 313
705378 | N00 - COO |  | 99.243
705379 | N00 - COO |  | 99.243
705380 | N00 - COO |  | 306
705381 | N00 - COO |  | 306
705655 | N00 - COO |  | 490
705656 | N00 - COO |  | 490
705657 | N00 - COO |  | 306
705658 | N00 - COO |  | 306
839290 | N00 - COO |  | 490
839291 | N00 - COO |  | 490
839292 | N00 - COO |  | 318
839293 | N00 - COO |  | 318
919967 | N00 - COO |  | 69.7
919968 | N00 - COO |  | 69.7
919969 | N00 - COO |  | 396
919970 | N00 - COO |  | 396
1665856 | Toiture - Cuisine | yes | 72.3
1665857 | Toiture - Cuisine | yes | 95
1665858 | Toiture - Cuisine | yes | 134.497
1665859 | Toiture - Cuisine | yes | 134.497
1665866 | Toiture - Cuisine | yes | 95
1665867 | Toiture - Cuisine | yes | 100
1665868 | Toiture - Cuisine | yes | 100
1665869 | Toiture - Cuisine | yes | 100
1665870 | Toiture - Cuisine | yes | 100
1665871 | Toiture - Cuisine | yes | 72.3
1665872 | Toiture - Cuisine | yes | 124.497
1665873 | Toiture - Cuisine | yes | 124.497
1665874 | Toiture - Cuisine | yes | 124.497
1665654 | Toiture - Cuisine | yes | 72.3
1665655 | Toiture - Cuisine | yes | 95
1665656 | Toiture - Cuisine | yes | 134.497
1665657 | Toiture - Cuisine | yes | 134.497
1665664 | Toiture - Cuisine | yes | 95
1665665 | Toiture - Cuisine | yes | 100
1665666 | Toiture - Cuisine | yes | 100
1665667 | Toiture - Cuisine | yes | 100
1665668 | Toiture - Cuisine | yes | 100
1665669 | Toiture - Cuisine | yes | 72.3
1665670 | Toiture - Cuisine | yes | 124.497
1665671 | Toiture - Cuisine | yes | 124.497
1665672 | Toiture - Cuisine | yes | 124.497
1008930 | N00 - COO |  | 490
1008931 | N00 - COO |  | 490
1008932 | N00 - COO |  | 306
1008933 | N00 - COO |  | 306
1010337 | N00 - COO |  | 95.263
1010338 | N00 - COO |  | 95.263
1010339 | N00 - COO |  | 313
1010340 | N00 - COO |  | 313
1010539 | N00 - COO |  | 117.763
1010540 | N00 - COO |  | 117.763
1010541 | N00 - COO |  | 396
1010542 | N00 - COO |  | 396
1058132 | N00 - COO |  | 72
1058133 | N00 - COO |  | 72
1058134 | N00 - COO |  | 313
1058135 | N00 - COO |  | 313
1124249 | N00 - COO |  | 143.5
1124250 | N00 - COO |  | 143.5
1124251 | N00 - COO |  | 313
1124252 | N00 - COO |  | 313
1199438 | N00 - COO |  | 148.945
1199439 | N00 - COO |  | 148.945
1199440 | N00 - COO |  | 313
1199441 | N00 - COO |  | 313
1220079 | N00 - COO |  | 403.657
1220081 | N00 - COO |  | 306
1220101 | N00 - COO |  | 3.5
1220102 | N00 - COO |  | 395.157
1220104 | N00 - COO |  | 309.5
1671653 | Toiture - Cuisine | yes | 72.3 | Group: Groupe de modèles:Retours BA 13 SELF / VERRIERE 2:1671562
1671654 | Toiture - Cuisine | yes | 95 | Group: Groupe de modèles:Retours BA 13 SELF / VERRIERE 2:1671562
1671655 | Toiture - Cuisine | yes | 134.497 | Group: Groupe de modèles:Retours BA 13 SELF / VERRIERE 2:1671562
1671656 | Toiture - Cuisine | yes | 134.497 | Group: Groupe de modèles:Retours BA 13 SELF / VERRIERE 2:1671562
1671663 | Toiture - Cuisine | yes | 95 | Group: Groupe de modèles:Retours BA 13 SELF / VERRIERE 2:1671562
1671664 | Toiture - Cuisine | yes | 100 | Group: Groupe de modèles:Retours BA 13 SELF / VERRIERE 2:1671562
1671665 | Toiture - Cuisine | yes | 100 | Group: Groupe de modèles:Retours BA 13 SELF / VERRIERE 2:1671562
1671666 | Toiture - Cuisine | yes | 100 | Group: Groupe de modèles:Retours BA 13 SELF / VERRIERE 2:1671562
1671667 | Toiture - Cuisine | yes | 100 | Group: Groupe de modèles:Retours BA 13 SELF / VERRIERE 2:1671562
1671668 | Toiture - Cuisine | yes | 72.3 | Group: Groupe de modèles:Retours BA 13 SELF / VERRIERE 2:1671562
1671669 | Toiture - Cuisine | yes | 124.497 | Group: Groupe de modèles:Retours BA 13 SELF / VERRIERE 2:1671562
1671670 | Toiture - Cuisine | yes | 124.497 | Group: Groupe de modèles:Retours BA 13 SELF / VERRIERE 2:1671562
1671671 | Toiture - Cuisine | yes | 124.497 | Group: Groupe de modèles:Retours BA 13 SELF / VERRIERE 2:1671562

# IfcMember: 150 x 25mm Détails (1525)
Type - PredefinedType: MEMBER
Type - Pset_MemberCommon - IsExternal: no; Reference: 150 x 25mm Détails
Type - Pset_QuantityTakeOff - Reference: 150 x 25mm Détails
Material: Aluminium
Name (Meneau rectangulaire:150 x 25mm Détails:...) | In | Span (cm)
165624 | N00 - COO | 280
165626 | N00 - COO | 312.5
165627 | N00 - COO | 299.5
1185141 | N00 - COO | 96.5
1185142 | N00 - COO | 299.5
1185143 | N00 - COO | 299.5
1367049 | N00 - COO | 280
1367050 | N00 - COO | 96.5
166276 | N00 - COO | 312.5
166277 | N00 - COO | 299.5
1185149 | N00 - COO | 299.5
1185150 | N00 - COO | 299.5
1367033 | N00 - COO | 280
1367034 | N00 - COO | 96.5
1367123 | N00 - COO | 280
1367124 | N00 - COO | 96.5
1147418 | N00 - COO | 13.5
1147420 | N00 - COO | 306.509
1148473 | N00 - COO | 13.5
1148627 | N00 - COO | 319.509
524435 | TR - N02 - ARCH | 70
524436 | TR - N02 - ARCH | 70
524437 | TR - N02 - ARCH | 70
524438 | TR - N02 - ARCH | 70
524439 | TR - N02 - ARCH | 70
524440 | TR - N02 - ARCH | 70
524441 | TR - N02 - ARCH | 70
524442 | TR - N02 - ARCH | 70
524443 | TR - N02 - ARCH | 70
524444 | TR - N02 - ARCH | 70
524445 | TR - N02 - ARCH | 70
524446 | TR - N02 - ARCH | 70
524447 | TR - N02 - ARCH | 70
524448 | TR - N02 - ARCH | 70
524449 | TR - N02 - ARCH | 70
524450 | TR - N02 - ARCH | 70
524451 | TR - N02 - ARCH | 70
524452 | TR - N02 - ARCH | 70
524453 | TR - N02 - ARCH | 70
524454 | TR - N02 - ARCH | 70
524455 | TR - N02 - ARCH | 70
524456 | TR - N02 - ARCH | 70
524457 | TR - N02 - ARCH | 70
524458 | TR - N02 - ARCH | 70
524459 | TR - N02 - ARCH | 70
524460 | TR - N02 - ARCH | 70
524461 | TR - N02 - ARCH | 70
524462 | TR - N02 - ARCH | 70
524463 | TR - N02 - ARCH | 70
524464 | TR - N02 - ARCH | 70
524465 | TR - N02 - ARCH | 70
524466 | TR - N02 - ARCH | 70
524467 | TR - N02 - ARCH | 70
524468 | TR - N02 - ARCH | 70
524469 | TR - N02 - ARCH | 70
524470 | TR - N02 - ARCH | 70
524471 | TR - N02 - ARCH | 70
524472 | TR - N02 - ARCH | 70
524473 | TR - N02 - ARCH | 70
524474 | TR - N02 - ARCH | 70
524475 | TR - N02 - ARCH | 70
524476 | TR - N02 - ARCH | 70
524477 | TR - N02 - ARCH | 70
524478 | TR - N02 - ARCH | 70
524479 | TR - N02 - ARCH | 70
524480 | TR - N02 - ARCH | 70
524481 | TR - N02 - ARCH | 70
524482 | TR - N02 - ARCH | 70
524483 | TR - N02 - ARCH | 70
524484 | TR - N02 - ARCH | 70
524485 | TR - N02 - ARCH | 70
524486 | TR - N02 - ARCH | 70
524487 | TR - N02 - ARCH | 70
524488 | TR - N02 - ARCH | 70
524489 | TR - N02 - ARCH | 70
524490 | TR - N02 - ARCH | 70
524491 | TR - N02 - ARCH | 70
524492 | TR - N02 - ARCH | 70
524493 | TR - N02 - ARCH | 70
524494 | TR - N02 - ARCH | 70
524495 | TR - N02 - ARCH | 70
524496 | TR - N02 - ARCH | 70
524497 | TR - N02 - ARCH | 70
524498 | TR - N02 - ARCH | 70
524499 | TR - N02 - ARCH | 70
524500 | TR - N02 - ARCH | 70
524501 | TR - N02 - ARCH | 70
524502 | TR - N02 - ARCH | 70
524503 | TR - N02 - ARCH | 70
524504 | TR - N02 - ARCH | 70
524505 | TR - N02 - ARCH | 70
524506 | TR - N02 - ARCH | 70
524507 | TR - N02 - ARCH | 70
524508 | TR - N02 - ARCH | 70
524509 | TR - N02 - ARCH | 70
524510 | TR - N02 - ARCH | 70
524511 | TR - N02 - ARCH | 70
524512 | TR - N02 - ARCH | 70
524513 | TR - N02 - ARCH | 70
524514 | TR - N02 - ARCH | 70
524515 | TR - N02 - ARCH | 70
524516 | TR - N02 - ARCH | 70
524517 | TR - N02 - ARCH | 70
524518 | TR - N02 - ARCH | 70
524519 | TR - N02 - ARCH | 70
524520 | TR - N02 - ARCH | 70
524521 | TR - N02 - ARCH | 70
524522 | TR - N02 - ARCH | 70
524523 | TR - N02 - ARCH | 70
524524 | TR - N02 - ARCH | 70
524525 | TR - N02 - ARCH | 70
524526 | TR - N02 - ARCH | 70
524527 | TR - N02 - ARCH | 70
524528 | TR - N02 - ARCH | 70
524529 | TR - N02 - ARCH | 70
524530 | TR - N02 - ARCH | 70
524531 | TR - N02 - ARCH | 70
524532 | TR - N02 - ARCH | 70
524533 | TR - N02 - ARCH | 70
524534 | TR - N02 - ARCH | 70
524535 | TR - N02 - ARCH | 70
524536 | TR - N02 - ARCH | 70
524537 | TR - N02 - ARCH | 70
524538 | TR - N02 - ARCH | 70
524539 | TR - N02 - ARCH | 70
524540 | TR - N02 - ARCH | 70
524541 | TR - N02 - ARCH | 70
524542 | TR - N02 - ARCH | 70
524543 | TR - N02 - ARCH | 70
524544 | TR - N02 - ARCH | 70
524545 | TR - N02 - ARCH | 70
524546 | TR - N02 - ARCH | 70
524547 | TR - N02 - ARCH | 70
524548 | TR - N02 - ARCH | 70
524549 | TR - N02 - ARCH | 70
524550 | TR - N02 - ARCH | 70
524551 | TR - N02 - ARCH | 70
524552 | TR - N02 - ARCH | 70
524553 | TR - N02 - ARCH | 70
524554 | TR - N02 - ARCH | 70
524555 | TR - N02 - ARCH | 70
524556 | TR - N02 - ARCH | 70
524557 | TR - N02 - ARCH | 70
524558 | TR - N02 - ARCH | 70
524559 | TR - N02 - ARCH | 70
524560 | TR - N02 - ARCH | 70
524561 | TR - N02 - ARCH | 70
524562 | TR - N02 - ARCH | 70
524563 | TR - N02 - ARCH | 70
524564 | TR - N02 - ARCH | 70
524565 | TR - N02 - ARCH | 70
524566 | TR - N02 - ARCH | 70
524567 | TR - N02 - ARCH | 70
524568 | TR - N02 - ARCH | 70
524569 | TR - N02 - ARCH | 70
524570 | TR - N02 - ARCH | 70
524571 | TR - N02 - ARCH | 236
524572 | TR - N02 - ARCH | 236
524573 | TR - N02 - ARCH | 236
524574 | TR - N02 - ARCH | 236
524575 | TR - N02 - ARCH | 236
524576 | TR - N02 - ARCH | 236
524577 | TR - N02 - ARCH | 236
524578 | TR - N02 - ARCH | 236
524579 | TR - N02 - ARCH | 236
524580 | TR - N02 - ARCH | 236
524581 | TR - N02 - ARCH | 236
524582 | TR - N02 - ARCH | 236
524583 | TR - N02 - ARCH | 236
524584 | TR - N02 - ARCH | 236
524585 | TR - N02 - ARCH | 236
524586 | TR - N02 - ARCH | 236
524587 | TR - N02 - ARCH | 236
524588 | TR - N02 - ARCH | 236
524591 | TR - N02 - ARCH | 236
524592 | TR - N02 - ARCH | 236
524593 | TR - N02 - ARCH | 236
524594 | TR - N02 - ARCH | 236
524595 | TR - N02 - ARCH | 236
524597 | TR - N02 - ARCH | 236
524598 | TR - N02 - ARCH | 236
524599 | TR - N02 - ARCH | 236
524600 | TR - N02 - ARCH | 236
524601 | TR - N02 - ARCH | 236
524602 | TR - N02 - ARCH | 236
524603 | TR - N02 - ARCH | 236
524604 | TR - N02 - ARCH | 236
524605 | TR - N02 - ARCH | 236
524606 | TR - N02 - ARCH | 236
524607 | TR - N02 - ARCH | 236
524608 | TR - N02 - ARCH | 236
524609 | TR - N02 - ARCH | 236
524610 | TR - N02 - ARCH | 236
524611 | TR - N02 - ARCH | 236
524612 | TR - N02 - ARCH | 236
524613 | TR - N02 - ARCH | 236
524614 | TR - N02 - ARCH | 236
524615 | TR - N02 - ARCH | 236
524616 | TR - N02 - ARCH | 236
524617 | TR - N02 - ARCH | 236
524618 | TR - N02 - ARCH | 236
524619 | TR - N02 - ARCH | 236
524620 | TR - N02 - ARCH | 236
524621 | TR - N02 - ARCH | 236
524622 | TR - N02 - ARCH | 236
524625 | TR - N02 - ARCH | 236
524626 | TR - N02 - ARCH | 236
524627 | TR - N02 - ARCH | 236
524628 | TR - N02 - ARCH | 236
524629 | TR - N02 - ARCH | 236
524630 | TR - N02 - ARCH | 236
524631 | TR - N02 - ARCH | 236
524632 | TR - N02 - ARCH | 236
524633 | TR - N02 - ARCH | 236
524634 | TR - N02 - ARCH | 236
524635 | TR - N02 - ARCH | 236
524636 | TR - N02 - ARCH | 236
524637 | TR - N02 - ARCH | 236
524638 | TR - N02 - ARCH | 236
524639 | TR - N02 - ARCH | 236
1130590 | TR - N02 - ARCH | 68
1130591 | TR - N02 - ARCH | 66.75
1130592 | TR - N02 - ARCH | 68
1130593 | TR - N02 - ARCH | 68
1130594 | TR - N02 - ARCH | 66.75
1130595 | TR - N02 - ARCH | 68
1130698 | TR - N02 - ARCH | 68
1130699 | TR - N02 - ARCH | 68
1130700 | TR - N02 - ARCH | 68
1130701 | TR - N02 - ARCH | 68
1130702 | TR - N02 - ARCH | 68
1130703 | TR - N02 - ARCH | 68
1130813 | TR - N02 - ARCH | 68
1130814 | TR - N02 - ARCH | 68
1130881 | TR - N02 - ARCH | 66.75
1130882 | TR - N02 - ARCH | 66.75
1130937 | TR - N02 - ARCH | 68
1130938 | TR - N02 - ARCH | 68
1131009 | TR - N02 - ARCH | 68
1131010 | TR - N02 - ARCH | 68
1131070 | TR - N02 - ARCH | 68
1131071 | TR - N02 - ARCH | 68
1131343 | TR - N02 - ARCH | 68
1131344 | TR - N02 - ARCH | 68
1131345 | TR - N02 - ARCH | 68
1131346 | TR - N02 - ARCH | 68
1131432 | TR - N02 - ARCH | 68
1131433 | TR - N02 - ARCH | 68
1131497 | TR - N02 - ARCH | 68
1131498 | TR - N02 - ARCH | 68
1190433 | TR - N02 - ARCH | 236
1190447 | TR - N02 - ARCH | 66.75
1190449 | TR - N02 - ARCH | 66.75
1190483 | TR - N02 - ARCH | 236
1985042 | TR - N02 - ARCH | 66.75
1985044 | TR - N02 - ARCH | 66.75
1985218 | TR - N02 - ARCH | 236
526684 | Toiture - Cuisine | 140
526685 | Toiture - Cuisine | 140
526686 | Toiture - Cuisine | 140
526687 | Toiture - Cuisine | 140
526688 | Toiture - Cuisine | 140
526689 | Toiture - Cuisine | 140
526690 | Toiture - Cuisine | 140
526691 | Toiture - Cuisine | 140
526692 | Toiture - Cuisine | 140
526693 | Toiture - Cuisine | 140
526694 | Toiture - Cuisine | 140
526695 | Toiture - Cuisine | 140
526696 | Toiture - Cuisine | 140
526697 | Toiture - Cuisine | 140
526698 | Toiture - Cuisine | 140
526699 | Toiture - Cuisine | 140
526700 | Toiture - Cuisine | 140
526701 | Toiture - Cuisine | 140
526702 | Toiture - Cuisine | 140
526703 | Toiture - Cuisine | 140
526704 | Toiture - Cuisine | 140
526705 | Toiture - Cuisine | 140
526706 | Toiture - Cuisine | 140
526707 | Toiture - Cuisine | 140
526708 | Toiture - Cuisine | 140
526709 | Toiture - Cuisine | 140
526710 | Toiture - Cuisine | 140
526711 | Toiture - Cuisine | 140
526712 | Toiture - Cuisine | 140
526713 | Toiture - Cuisine | 140
526714 | Toiture - Cuisine | 140
526715 | Toiture - Cuisine | 140
526716 | Toiture - Cuisine | 140
526718 | Toiture - Cuisine | 140
526719 | Toiture - Cuisine | 140
526720 | Toiture - Cuisine | 140
526721 | Toiture - Cuisine | 140
526722 | Toiture - Cuisine | 140
526723 | Toiture - Cuisine | 140
526724 | Toiture - Cuisine | 140
526725 | Toiture - Cuisine | 140
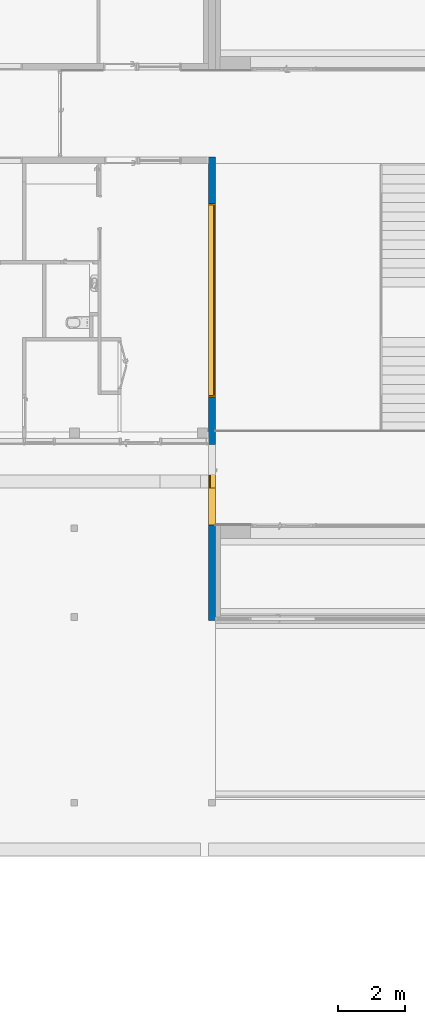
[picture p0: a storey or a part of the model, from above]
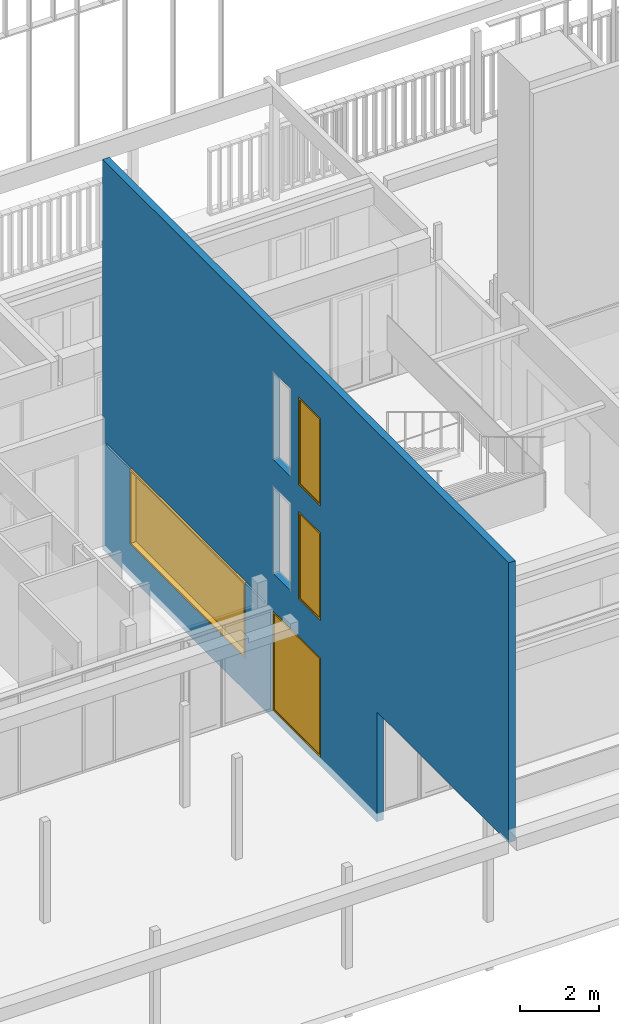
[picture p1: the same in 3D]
Properties of the parts of a building model (IFC2X3), part 3 of 7

# IfcMember: 150 x 25mm Détails (1525)
Name (Meneau rectangulaire:150 x 25mm Détails:...) | In | Span (cm)
526726 | Toiture - Cuisine | 140
526727 | Toiture - Cuisine | 140
526728 | Toiture - Cuisine | 140
526729 | Toiture - Cuisine | 140
526730 | Toiture - Cuisine | 140
526731 | Toiture - Cuisine | 140
526732 | Toiture - Cuisine | 140
526733 | Toiture - Cuisine | 140
526734 | Toiture - Cuisine | 140
526735 | Toiture - Cuisine | 140
526736 | Toiture - Cuisine | 140
526737 | Toiture - Cuisine | 140
526738 | Toiture - Cuisine | 140
526739 | Toiture - Cuisine | 140
526740 | Toiture - Cuisine | 140
526741 | Toiture - Cuisine | 140
526742 | Toiture - Cuisine | 140
526743 | Toiture - Cuisine | 140
526744 | Toiture - Cuisine | 140
526745 | Toiture - Cuisine | 140
526746 | Toiture - Cuisine | 140
526747 | Toiture - Cuisine | 140
526748 | Toiture - Cuisine | 140
526749 | Toiture - Cuisine | 140
526750 | Toiture - Cuisine | 224.5
526751 | Toiture - Cuisine | 224.5
526753 | Toiture - Cuisine | 224.5
526754 | Toiture - Cuisine | 224.5
526755 | Toiture - Cuisine | 224.5
526756 | Toiture - Cuisine | 224.5
526757 | Toiture - Cuisine | 224.5
526758 | Toiture - Cuisine | 224.5
526759 | Toiture - Cuisine | 224.5
526760 | Toiture - Cuisine | 224.5
526761 | Toiture - Cuisine | 224.5
526762 | Toiture - Cuisine | 224.5
526763 | Toiture - Cuisine | 224.5
526764 | Toiture - Cuisine | 224.5
526765 | Toiture - Cuisine | 224.5
526766 | Toiture - Cuisine | 224.5
526767 | Toiture - Cuisine | 224.5
526768 | Toiture - Cuisine | 224.5
526769 | Toiture - Cuisine | 224.5
526770 | Toiture - Cuisine | 224.5
526771 | Toiture - Cuisine | 224.5
526772 | Toiture - Cuisine | 224.5
526773 | Toiture - Cuisine | 224.5
526774 | Toiture - Cuisine | 224.5
526775 | Toiture - Cuisine | 224.5
526776 | Toiture - Cuisine | 224.5
526777 | Toiture - Cuisine | 224.5
526778 | Toiture - Cuisine | 224.5
526779 | Toiture - Cuisine | 224.5
526780 | Toiture - Cuisine | 224.5
526781 | Toiture - Cuisine | 224.5
526782 | Toiture - Cuisine | 224.5
526783 | Toiture - Cuisine | 224.5
526784 | Toiture - Cuisine | 224.5
922859 | Toiture - Cuisine | 140
1558125 | Toiture - Cuisine | 140
1558131 | Toiture - Cuisine | 140
1987170 | Toiture - Cuisine | 224.5
528144 | Toiture - Cuisine | 140
528145 | Toiture - Cuisine | 140
528146 | Toiture - Cuisine | 140
528147 | Toiture - Cuisine | 140
528148 | Toiture - Cuisine | 140
528149 | Toiture - Cuisine | 140
528150 | Toiture - Cuisine | 140
528151 | Toiture - Cuisine | 140
528152 | Toiture - Cuisine | 140
528153 | Toiture - Cuisine | 140
528154 | Toiture - Cuisine | 140
528155 | Toiture - Cuisine | 140
528156 | Toiture - Cuisine | 140
528157 | Toiture - Cuisine | 140
528158 | Toiture - Cuisine | 140
528159 | Toiture - Cuisine | 140
528160 | Toiture - Cuisine | 140
528161 | Toiture - Cuisine | 140
528162 | Toiture - Cuisine | 140
528163 | Toiture - Cuisine | 140
528164 | Toiture - Cuisine | 140
528165 | Toiture - Cuisine | 140
528166 | Toiture - Cuisine | 140
528167 | Toiture - Cuisine | 140
528168 | Toiture - Cuisine | 140
528170 | Toiture - Cuisine | 140
528171 | Toiture - Cuisine | 140
528172 | Toiture - Cuisine | 140
528173 | Toiture - Cuisine | 140
528174 | Toiture - Cuisine | 140
528175 | Toiture - Cuisine | 140
528176 | Toiture - Cuisine | 140
528177 | Toiture - Cuisine | 140
528178 | Toiture - Cuisine | 140
528179 | Toiture - Cuisine | 140
528180 | Toiture - Cuisine | 140
528181 | Toiture - Cuisine | 140
528182 | Toiture - Cuisine | 140
528183 | Toiture - Cuisine | 140
528184 | Toiture - Cuisine | 140
528185 | Toiture - Cuisine | 140
528186 | Toiture - Cuisine | 140
528187 | Toiture - Cuisine | 140
528188 | Toiture - Cuisine | 140
528189 | Toiture - Cuisine | 140
528190 | Toiture - Cuisine | 140
528191 | Toiture - Cuisine | 140
528192 | Toiture - Cuisine | 140
528193 | Toiture - Cuisine | 140
528194 | Toiture - Cuisine | 140
528195 | Toiture - Cuisine | 121.5
528196 | Toiture - Cuisine | 224.5
528197 | Toiture - Cuisine | 224.5
528198 | Toiture - Cuisine | 224.5
528199 | Toiture - Cuisine | 224.5
528200 | Toiture - Cuisine | 224.5
528201 | Toiture - Cuisine | 224.5
528202 | Toiture - Cuisine | 224.5
528203 | Toiture - Cuisine | 224.5
528204 | Toiture - Cuisine | 224.5
528205 | Toiture - Cuisine | 224.5
528206 | Toiture - Cuisine | 224.5
528207 | Toiture - Cuisine | 224.5
528208 | Toiture - Cuisine | 224.5
528209 | Toiture - Cuisine | 224.5
528210 | Toiture - Cuisine | 224.5
528211 | Toiture - Cuisine | 224.5
528212 | Toiture - Cuisine | 224.5
528213 | Toiture - Cuisine | 224.5
528214 | Toiture - Cuisine | 224.5
528215 | Toiture - Cuisine | 224.5
528216 | Toiture - Cuisine | 224.5
528217 | Toiture - Cuisine | 224.5
528218 | Toiture - Cuisine | 224.5
528219 | Toiture - Cuisine | 224.5
528220 | Toiture - Cuisine | 224.5
528221 | Toiture - Cuisine | 224.5
528222 | Toiture - Cuisine | 224.5
682465 | Toiture - Cuisine | 121.5
528868 | TR - N02 - ARCH | 51.5
528869 | TR - N02 - ARCH | 70
528870 | TR - N02 - ARCH | 70
528871 | TR - N02 - ARCH | 70
528872 | TR - N02 - ARCH | 70
528873 | TR - N02 - ARCH | 70
528874 | TR - N02 - ARCH | 70
528875 | TR - N02 - ARCH | 70
528876 | TR - N02 - ARCH | 70
528877 | TR - N02 - ARCH | 70
528878 | TR - N02 - ARCH | 70
528879 | TR - N02 - ARCH | 70
528880 | TR - N02 - ARCH | 70
528881 | TR - N02 - ARCH | 70
528882 | TR - N02 - ARCH | 70
528883 | TR - N02 - ARCH | 70
528884 | TR - N02 - ARCH | 70
528885 | TR - N02 - ARCH | 70
528886 | TR - N02 - ARCH | 70
528887 | TR - N02 - ARCH | 70
528888 | TR - N02 - ARCH | 70
528889 | TR - N02 - ARCH | 70
528890 | TR - N02 - ARCH | 70
528891 | TR - N02 - ARCH | 70
528892 | TR - N02 - ARCH | 70
528893 | TR - N02 - ARCH | 70
528894 | TR - N02 - ARCH | 70
528895 | TR - N02 - ARCH | 70
528896 | TR - N02 - ARCH | 70
528897 | TR - N02 - ARCH | 70
528898 | TR - N02 - ARCH | 70
528899 | TR - N02 - ARCH | 70
528900 | TR - N02 - ARCH | 70
528901 | TR - N02 - ARCH | 70
528902 | TR - N02 - ARCH | 70
528903 | TR - N02 - ARCH | 70
528904 | TR - N02 - ARCH | 70
528905 | TR - N02 - ARCH | 70
528906 | TR - N02 - ARCH | 70
528907 | TR - N02 - ARCH | 70
528908 | TR - N02 - ARCH | 70
528909 | TR - N02 - ARCH | 70
528910 | TR - N02 - ARCH | 70
528911 | TR - N02 - ARCH | 70
528912 | TR - N02 - ARCH | 70
528913 | TR - N02 - ARCH | 70
528914 | TR - N02 - ARCH | 70
528915 | TR - N02 - ARCH | 70
528916 | TR - N02 - ARCH | 70
528917 | TR - N02 - ARCH | 70
528918 | TR - N02 - ARCH | 70
528919 | TR - N02 - ARCH | 70
528920 | TR - N02 - ARCH | 70
528921 | TR - N02 - ARCH | 70
528922 | TR - N02 - ARCH | 70
528923 | TR - N02 - ARCH | 70
528924 | TR - N02 - ARCH | 70
528925 | TR - N02 - ARCH | 70
528926 | TR - N02 - ARCH | 70
528927 | TR - N02 - ARCH | 70
528928 | TR - N02 - ARCH | 70
528929 | TR - N02 - ARCH | 70
528930 | TR - N02 - ARCH | 70
528931 | TR - N02 - ARCH | 70
528932 | TR - N02 - ARCH | 70
528933 | TR - N02 - ARCH | 70
528934 | TR - N02 - ARCH | 70
528935 | TR - N02 - ARCH | 70
528936 | TR - N02 - ARCH | 70
528937 | TR - N02 - ARCH | 70
528938 | TR - N02 - ARCH | 70
528939 | TR - N02 - ARCH | 70
528940 | TR - N02 - ARCH | 70
528941 | TR - N02 - ARCH | 70
528942 | TR - N02 - ARCH | 70
528943 | TR - N02 - ARCH | 70
528944 | TR - N02 - ARCH | 70
528945 | TR - N02 - ARCH | 70
528946 | TR - N02 - ARCH | 70
528947 | TR - N02 - ARCH | 70
528948 | TR - N02 - ARCH | 70
528949 | TR - N02 - ARCH | 70
528950 | TR - N02 - ARCH | 70
528951 | TR - N02 - ARCH | 70
528952 | TR - N02 - ARCH | 70
528953 | TR - N02 - ARCH | 70
528954 | TR - N02 - ARCH | 70
528955 | TR - N02 - ARCH | 70
528956 | TR - N02 - ARCH | 70
528957 | TR - N02 - ARCH | 70
528958 | TR - N02 - ARCH | 70
528959 | TR - N02 - ARCH | 70
528960 | TR - N02 - ARCH | 70
528961 | TR - N02 - ARCH | 70
528962 | TR - N02 - ARCH | 70
528963 | TR - N02 - ARCH | 70
528964 | TR - N02 - ARCH | 70
528965 | TR - N02 - ARCH | 70
528966 | TR - N02 - ARCH | 70
528967 | TR - N02 - ARCH | 70
528968 | TR - N02 - ARCH | 70
528969 | TR - N02 - ARCH | 70
528970 | TR - N02 - ARCH | 70
528971 | TR - N02 - ARCH | 51.5
528972 | TR - N02 - ARCH | 236
528973 | TR - N02 - ARCH | 236
528974 | TR - N02 - ARCH | 236
528975 | TR - N02 - ARCH | 236
528976 | TR - N02 - ARCH | 236
528977 | TR - N02 - ARCH | 236
528978 | TR - N02 - ARCH | 236
528979 | TR - N02 - ARCH | 236
528980 | TR - N02 - ARCH | 236
528981 | TR - N02 - ARCH | 236
528982 | TR - N02 - ARCH | 236
528983 | TR - N02 - ARCH | 236
528984 | TR - N02 - ARCH | 236
528985 | TR - N02 - ARCH | 236
528986 | TR - N02 - ARCH | 236
528987 | TR - N02 - ARCH | 236
528988 | TR - N02 - ARCH | 236
528989 | TR - N02 - ARCH | 236
528990 | TR - N02 - ARCH | 236
528991 | TR - N02 - ARCH | 236
528992 | TR - N02 - ARCH | 236
528993 | TR - N02 - ARCH | 236
528994 | TR - N02 - ARCH | 236
528995 | TR - N02 - ARCH | 236
528996 | TR - N02 - ARCH | 236
528997 | TR - N02 - ARCH | 236
528998 | TR - N02 - ARCH | 236
528999 | TR - N02 - ARCH | 236
529000 | TR - N02 - ARCH | 236
529001 | TR - N02 - ARCH | 236
529002 | TR - N02 - ARCH | 236
529003 | TR - N02 - ARCH | 236
529004 | TR - N02 - ARCH | 236
529005 | TR - N02 - ARCH | 236
529006 | TR - N02 - ARCH | 236
529007 | TR - N02 - ARCH | 236
529008 | TR - N02 - ARCH | 236
529009 | TR - N02 - ARCH | 236
529010 | TR - N02 - ARCH | 236
529011 | TR - N02 - ARCH | 236
529012 | TR - N02 - ARCH | 236
529013 | TR - N02 - ARCH | 236
529014 | TR - N02 - ARCH | 236
529015 | TR - N02 - ARCH | 236
529016 | TR - N02 - ARCH | 236
529017 | TR - N02 - ARCH | 236
529018 | TR - N02 - ARCH | 236
529019 | TR - N02 - ARCH | 236
529020 | TR - N02 - ARCH | 236
529021 | TR - N02 - ARCH | 236
529022 | TR - N02 - ARCH | 236
529023 | TR - N02 - ARCH | 236
529024 | TR - N02 - ARCH | 236
1133893 | TR - N02 - ARCH | 68
1133894 | TR - N02 - ARCH | 68
1134052 | TR - N02 - ARCH | 68
1134053 | TR - N02 - ARCH | 68
1134114 | TR - N02 - ARCH | 68
1134115 | TR - N02 - ARCH | 68
1134170 | TR - N02 - ARCH | 68
1134171 | TR - N02 - ARCH | 68
1134223 | TR - N02 - ARCH | 68
1134224 | TR - N02 - ARCH | 68
1134293 | TR - N02 - ARCH | 68
1134294 | TR - N02 - ARCH | 68
1134295 | TR - N02 - ARCH | 68
1134296 | TR - N02 - ARCH | 68
1134297 | TR - N02 - ARCH | 68
1134298 | TR - N02 - ARCH | 68
1134299 | TR - N02 - ARCH | 68
1134300 | TR - N02 - ARCH | 68
1134301 | TR - N02 - ARCH | 68
1134302 | TR - N02 - ARCH | 68
1134438 | TR - N02 - ARCH | 68
1134439 | TR - N02 - ARCH | 68
576369 | TR - N02 - ARCH | 70
576370 | TR - N02 - ARCH | 70
576371 | TR - N02 - ARCH | 70
576372 | TR - N02 - ARCH | 70
576373 | TR - N02 - ARCH | 70
576374 | TR - N02 - ARCH | 70
576375 | TR - N02 - ARCH | 70
576376 | TR - N02 - ARCH | 70
576377 | TR - N02 - ARCH | 70
576378 | TR - N02 - ARCH | 70
576379 | TR - N02 - ARCH | 70
576380 | TR - N02 - ARCH | 70
576381 | TR - N02 - ARCH | 70
576382 | TR - N02 - ARCH | 70
576383 | TR - N02 - ARCH | 70
576384 | TR - N02 - ARCH | 70
576385 | TR - N02 - ARCH | 70
576386 | TR - N02 - ARCH | 70
576387 | TR - N02 - ARCH | 70
576388 | TR - N02 - ARCH | 70
576389 | TR - N02 - ARCH | 70
576390 | TR - N02 - ARCH | 70
576391 | TR - N02 - ARCH | 70
576392 | TR - N02 - ARCH | 70
576393 | TR - N02 - ARCH | 70
576394 | TR - N02 - ARCH | 70
576395 | TR - N02 - ARCH | 70
576396 | TR - N02 - ARCH | 70
576397 | TR - N02 - ARCH | 70
576398 | TR - N02 - ARCH | 70
576399 | TR - N02 - ARCH | 70
576400 | TR - N02 - ARCH | 70
576401 | TR - N02 - ARCH | 70
576402 | TR - N02 - ARCH | 70
576403 | TR - N02 - ARCH | 70
576404 | TR - N02 - ARCH | 70
576405 | TR - N02 - ARCH | 70
576406 | TR - N02 - ARCH | 70
576407 | TR - N02 - ARCH | 70
576408 | TR - N02 - ARCH | 70
576409 | TR - N02 - ARCH | 70
576410 | TR - N02 - ARCH | 70
576411 | TR - N02 - ARCH | 70
576412 | TR - N02 - ARCH | 70
576413 | TR - N02 - ARCH | 70
576414 | TR - N02 - ARCH | 70
576415 | TR - N02 - ARCH | 70
576416 | TR - N02 - ARCH | 70
576417 | TR - N02 - ARCH | 70
576418 | TR - N02 - ARCH | 70
576419 | TR - N02 - ARCH | 70
576420 | TR - N02 - ARCH | 70
576431 | TR - N02 - ARCH | 70
576432 | TR - N02 - ARCH | 70
576433 | TR - N02 - ARCH | 70
576434 | TR - N02 - ARCH | 70
576435 | TR - N02 - ARCH | 70
576436 | TR - N02 - ARCH | 70
576437 | TR - N02 - ARCH | 70
576438 | TR - N02 - ARCH | 70
576439 | TR - N02 - ARCH | 70
576440 | TR - N02 - ARCH | 70
576441 | TR - N02 - ARCH | 70
576442 | TR - N02 - ARCH | 70
576443 | TR - N02 - ARCH | 70
576444 | TR - N02 - ARCH | 70
576445 | TR - N02 - ARCH | 70
576446 | TR - N02 - ARCH | 70
576447 | TR - N02 - ARCH | 70
576448 | TR - N02 - ARCH | 70
576449 | TR - N02 - ARCH | 70
576450 | TR - N02 - ARCH | 70
576451 | TR - N02 - ARCH | 70
576452 | TR - N02 - ARCH | 70
576453 | TR - N02 - ARCH | 70
576454 | TR - N02 - ARCH | 70
576455 | TR - N02 - ARCH | 70
576456 | TR - N02 - ARCH | 70
576457 | TR - N02 - ARCH | 70
576458 | TR - N02 - ARCH | 70
576459 | TR - N02 - ARCH | 70
576460 | TR - N02 - ARCH | 70
576461 | TR - N02 - ARCH | 70
576462 | TR - N02 - ARCH | 70
576463 | TR - N02 - ARCH | 70
576464 | TR - N02 - ARCH | 70
576465 | TR - N02 - ARCH | 70
576466 | TR - N02 - ARCH | 70
576467 | TR - N02 - ARCH | 70
576468 | TR - N02 - ARCH | 70
576469 | TR - N02 - ARCH | 70
576470 | TR - N02 - ARCH | 70
576471 | TR - N02 - ARCH | 70
576472 | TR - N02 - ARCH | 70
576473 | TR - N02 - ARCH | 70
576474 | TR - N02 - ARCH | 70
576475 | TR - N02 - ARCH | 70
576476 | TR - N02 - ARCH | 70
576477 | TR - N02 - ARCH | 70
576478 | TR - N02 - ARCH | 70
576479 | TR - N02 - ARCH | 70
576480 | TR - N02 - ARCH | 70
576481 | TR - N02 - ARCH | 70
576482 | TR - N02 - ARCH | 70
576483 | TR - N02 - ARCH | 70
576494 | TR - N02 - ARCH | 249
576495 | TR - N02 - ARCH | 236
576498 | TR - N02 - ARCH | 236
576499 | TR - N02 - ARCH | 236
576500 | TR - N02 - ARCH | 236
576501 | TR - N02 - ARCH | 236
576502 | TR - N02 - ARCH | 236
576503 | TR - N02 - ARCH | 236
576504 | TR - N02 - ARCH | 236
576505 | TR - N02 - ARCH | 236
576506 | TR - N02 - ARCH | 236
576507 | TR - N02 - ARCH | 236
576508 | TR - N02 - ARCH | 236
576509 | TR - N02 - ARCH | 236
576510 | TR - N02 - ARCH | 236
576511 | TR - N02 - ARCH | 236
576512 | TR - N02 - ARCH | 236
576513 | TR - N02 - ARCH | 236
576514 | TR - N02 - ARCH | 236
576515 | TR - N02 - ARCH | 236
576516 | TR - N02 - ARCH | 236
576517 | TR - N02 - ARCH | 236
576518 | TR - N02 - ARCH | 236
576519 | TR - N02 - ARCH | 236
576520 | TR - N02 - ARCH | 236
576521 | TR - N02 - ARCH | 236
576522 | TR - N02 - ARCH | 236
576523 | TR - N02 - ARCH | 236
576524 | TR - N02 - ARCH | 236
576525 | TR - N02 - ARCH | 236
576526 | TR - N02 - ARCH | 236
576527 | TR - N02 - ARCH | 236
576528 | TR - N02 - ARCH | 236
576529 | TR - N02 - ARCH | 236
576530 | TR - N02 - ARCH | 236
576531 | TR - N02 - ARCH | 236
576532 | TR - N02 - ARCH | 236
576533 | TR - N02 - ARCH | 236
576534 | TR - N02 - ARCH | 236
576535 | TR - N02 - ARCH | 236
576536 | TR - N02 - ARCH | 236
576537 | TR - N02 - ARCH | 236
576538 | TR - N02 - ARCH | 236
576539 | TR - N02 - ARCH | 236
576540 | TR - N02 - ARCH | 236
576541 | TR - N02 - ARCH | 236
576542 | TR - N02 - ARCH | 236
576543 | TR - N02 - ARCH | 236
576544 | TR - N02 - ARCH | 236
576545 | TR - N02 - ARCH | 236
576546 | TR - N02 - ARCH | 236
576547 | TR - N02 - ARCH | 236
868516 | TR - N02 - ARCH | 70
868517 | TR - N02 - ARCH | 70
868518 | TR - N02 - ARCH | 70
868519 | TR - N02 - ARCH | 70
868520 | TR - N02 - ARCH | 70
868521 | TR - N02 - ARCH | 70
868522 | TR - N02 - ARCH | 70
868523 | TR - N02 - ARCH | 70
868525 | TR - N02 - ARCH | 70
868526 | TR - N02 - ARCH | 70
868527 | TR - N02 - ARCH | 70
868528 | TR - N02 - ARCH | 70
868529 | TR - N02 - ARCH | 70
868530 | TR - N02 - ARCH | 70
868531 | TR - N02 - ARCH | 70
868532 | TR - N02 - ARCH | 70
868534 | TR - N02 - ARCH | 236
868535 | TR - N02 - ARCH | 236
868536 | TR - N02 - ARCH | 236
868537 | TR - N02 - ARCH | 236
868538 | TR - N02 - ARCH | 236
868539 | TR - N02 - ARCH | 236
868540 | TR - N02 - ARCH | 236
868541 | TR - N02 - ARCH | 236
871490 | TR - N02 - ARCH | 70
871491 | TR - N02 - ARCH | 70
871492 | TR - N02 - ARCH | 236
871524 | TR - N02 - ARCH | 70
1132245 | TR - N02 - ARCH | 66.75
1132246 | TR - N02 - ARCH | 66.75
1132441 | TR - N02 - ARCH | 68
1132442 | TR - N02 - ARCH | 68
1132526 | TR - N02 - ARCH | 68
1132527 | TR - N02 - ARCH | 68
1132674 | TR - N02 - ARCH | 68
1132675 | TR - N02 - ARCH | 68
1132803 | TR - N02 - ARCH | 68
1132804 | TR - N02 - ARCH | 68
1133019 | TR - N02 - ARCH | 68
1133020 | TR - N02 - ARCH | 68
1133117 | TR - N02 - ARCH | 68
1133118 | TR - N02 - ARCH | 68
1133176 | TR - N02 - ARCH | 68
1133177 | TR - N02 - ARCH | 68
1133256 | TR - N02 - ARCH | 68
1133257 | TR - N02 - ARCH | 68
1133485 | TR - N02 - ARCH | 68
1133486 | TR - N02 - ARCH | 68
1133621 | TR - N02 - ARCH | 68
1133622 | TR - N02 - ARCH | 68
1133747 | TR - N02 - ARCH | 68
1133748 | TR - N02 - ARCH | 68
1133830 | TR - N02 - ARCH | 68
1133831 | TR - N02 - ARCH | 68
1984826 | TR - N02 - ARCH | 66.75
1984828 | TR - N02 - ARCH | 66.75
1984884 | TR - N02 - ARCH | 236
577852 | Toiture - Cuisine | 140
577853 | Toiture - Cuisine | 140
577854 | Toiture - Cuisine | 140
577855 | Toiture - Cuisine | 140
577856 | Toiture - Cuisine | 140
577857 | Toiture - Cuisine | 140
577858 | Toiture - Cuisine | 140
577859 | Toiture - Cuisine | 140
577860 | Toiture - Cuisine | 140
577861 | Toiture - Cuisine | 140
577862 | Toiture - Cuisine | 140
577863 | Toiture - Cuisine | 140
577864 | Toiture - Cuisine | 140
577865 | Toiture - Cuisine | 140
577866 | Toiture - Cuisine | 140
577867 | Toiture - Cuisine | 140
577868 | Toiture - Cuisine | 140
577869 | Toiture - Cuisine | 140
577870 | Toiture - Cuisine | 140
577871 | Toiture - Cuisine | 140
577872 | Toiture - Cuisine | 140
577873 | Toiture - Cuisine | 140
577874 | Toiture - Cuisine | 140
577875 | Toiture - Cuisine | 140
577876 | Toiture - Cuisine | 140
577877 | Toiture - Cuisine | 140
577878 | Toiture - Cuisine | 140
577879 | Toiture - Cuisine | 140
577880 | Toiture - Cuisine | 140
577881 | Toiture - Cuisine | 140
577883 | Toiture - Cuisine | 140
577884 | Toiture - Cuisine | 140
577885 | Toiture - Cuisine | 140
577886 | Toiture - Cuisine | 140
577887 | Toiture - Cuisine | 140
577888 | Toiture - Cuisine | 140
577889 | Toiture - Cuisine | 140
577890 | Toiture - Cuisine | 140
577891 | Toiture - Cuisine | 140
577892 | Toiture - Cuisine | 140
577893 | Toiture - Cuisine | 140
577894 | Toiture - Cuisine | 140
577895 | Toiture - Cuisine | 140
577896 | Toiture - Cuisine | 140
577897 | Toiture - Cuisine | 140
577898 | Toiture - Cuisine | 140
577899 | Toiture - Cuisine | 140
577900 | Toiture - Cuisine | 140
577901 | Toiture - Cuisine | 140
577902 | Toiture - Cuisine | 140
577903 | Toiture - Cuisine | 140
577904 | Toiture - Cuisine | 140
577905 | Toiture - Cuisine | 140
577906 | Toiture - Cuisine | 140
577907 | Toiture - Cuisine | 140
577908 | Toiture - Cuisine | 140
577909 | Toiture - Cuisine | 140
577910 | Toiture - Cuisine | 140
577911 | Toiture - Cuisine | 140
577912 | Toiture - Cuisine | 140
577913 | Toiture - Cuisine | 140
577915 | Toiture - Cuisine | 237.5
577916 | Toiture - Cuisine | 224.5
577917 | Toiture - Cuisine | 224.5
577918 | Toiture - Cuisine | 224.5
577919 | Toiture - Cuisine | 224.5
577920 | Toiture - Cuisine | 224.5
577921 | Toiture - Cuisine | 224.5
577922 | Toiture - Cuisine | 224.5
577923 | Toiture - Cuisine | 224.5
577924 | Toiture - Cuisine | 224.5
577925 | Toiture - Cuisine | 224.5
577926 | Toiture - Cuisine | 224.5
577927 | Toiture - Cuisine | 224.5
577928 | Toiture - Cuisine | 224.5
577929 | Toiture - Cuisine | 224.5
577930 | Toiture - Cuisine | 224.5
577931 | Toiture - Cuisine | 224.5
577932 | Toiture - Cuisine | 224.5
577933 | Toiture - Cuisine | 224.5
577934 | Toiture - Cuisine | 224.5
577935 | Toiture - Cuisine | 224.5
577936 | Toiture - Cuisine | 224.5
577937 | Toiture - Cuisine | 224.5
577938 | Toiture - Cuisine | 224.5
577939 | Toiture - Cuisine | 224.5
577940 | Toiture - Cuisine | 224.5
577941 | Toiture - Cuisine | 224.5
577942 | Toiture - Cuisine | 224.5
577943 | Toiture - Cuisine | 224.5
577944 | Toiture - Cuisine | 224.5
577945 | Toiture - Cuisine | 224.5
577946 | Toiture - Cuisine | 224.5
871528 | Toiture - Cuisine | 140
578692 | N00 - COO | 143.25
578706 | N00 - COO | 299.5
1204643 | N00 - COO | 143.25
1204644 | N00 - COO | 299.5
580144 | TR - N02 - ARCH | 70
580145 | TR - N02 - ARCH | 70
580146 | TR - N02 - ARCH | 70
580147 | TR - N02 - ARCH | 70
580148 | TR - N02 - ARCH | 70
580149 | TR - N02 - ARCH | 70
580150 | TR - N02 - ARCH | 70
580151 | TR - N02 - ARCH | 70
580152 | TR - N02 - ARCH | 70
580153 | TR - N02 - ARCH | 70
580154 | TR - N02 - ARCH | 70
580155 | TR - N02 - ARCH | 70
580156 | TR - N02 - ARCH | 70
580157 | TR - N02 - ARCH | 70
580158 | TR - N02 - ARCH | 70
580159 | TR - N02 - ARCH | 70
580160 | TR - N02 - ARCH | 70
580161 | TR - N02 - ARCH | 70
580162 | TR - N02 - ARCH | 70
580163 | TR - N02 - ARCH | 70
580164 | TR - N02 - ARCH | 70
580165 | TR - N02 - ARCH | 70
580166 | TR - N02 - ARCH | 70
580167 | TR - N02 - ARCH | 70
580168 | TR - N02 - ARCH | 70
580169 | TR - N02 - ARCH | 70
580170 | TR - N02 - ARCH | 70
580171 | TR - N02 - ARCH | 70
580172 | TR - N02 - ARCH | 70
580173 | TR - N02 - ARCH | 70
580174 | TR - N02 - ARCH | 70
580175 | TR - N02 - ARCH | 70
580176 | TR - N02 - ARCH | 70
580178 | TR - N02 - ARCH | 70
580179 | TR - N02 - ARCH | 70
580180 | TR - N02 - ARCH | 70
580181 | TR - N02 - ARCH | 70
580182 | TR - N02 - ARCH | 70
580183 | TR - N02 - ARCH | 70
580184 | TR - N02 - ARCH | 70
580185 | TR - N02 - ARCH | 70
580186 | TR - N02 - ARCH | 70
580187 | TR - N02 - ARCH | 70
580188 | TR - N02 - ARCH | 70
580189 | TR - N02 - ARCH | 70
580190 | TR - N02 - ARCH | 70
580191 | TR - N02 - ARCH | 70
580192 | TR - N02 - ARCH | 70
580193 | TR - N02 - ARCH | 70
580194 | TR - N02 - ARCH | 70
580195 | TR - N02 - ARCH | 70
580196 | TR - N02 - ARCH | 70
580197 | TR - N02 - ARCH | 70
580198 | TR - N02 - ARCH | 70
580199 | TR - N02 - ARCH | 70
580200 | TR - N02 - ARCH | 70
580201 | TR - N02 - ARCH | 70
580202 | TR - N02 - ARCH | 70
580203 | TR - N02 - ARCH | 70
580204 | TR - N02 - ARCH | 70
580205 | TR - N02 - ARCH | 70
580206 | TR - N02 - ARCH | 70
580207 | TR - N02 - ARCH | 70
580208 | TR - N02 - ARCH | 70
580209 | TR - N02 - ARCH | 70
580210 | TR - N02 - ARCH | 70
580211 | TR - N02 - ARCH | 50.375
580213 | TR - N02 - ARCH | 236
580214 | TR - N02 - ARCH | 236
580215 | TR - N02 - ARCH | 236
580217 | TR - N02 - ARCH | 236
580218 | TR - N02 - ARCH | 236
580219 | TR - N02 - ARCH | 236
580220 | TR - N02 - ARCH | 236
580221 | TR - N02 - ARCH | 236
580222 | TR - N02 - ARCH | 236
580223 | TR - N02 - ARCH | 236
580224 | TR - N02 - ARCH | 236
580225 | TR - N02 - ARCH | 236
580226 | TR - N02 - ARCH | 236
580227 | TR - N02 - ARCH | 236
580228 | TR - N02 - ARCH | 236
580229 | TR - N02 - ARCH | 236
580230 | TR - N02 - ARCH | 236
580231 | TR - N02 - ARCH | 236
580232 | TR - N02 - ARCH | 236
580233 | TR - N02 - ARCH | 236
580234 | TR - N02 - ARCH | 236
580235 | TR - N02 - ARCH | 236
580236 | TR - N02 - ARCH | 236
580237 | TR - N02 - ARCH | 236
580238 | TR - N02 - ARCH | 236
580240 | TR - N02 - ARCH | 236
580241 | TR - N02 - ARCH | 236
580242 | TR - N02 - ARCH | 236
580243 | TR - N02 - ARCH | 236
580244 | TR - N02 - ARCH | 236
580245 | TR - N02 - ARCH | 236
580246 | TR - N02 - ARCH | 236
580247 | TR - N02 - ARCH | 236
734235 | TR - N02 - ARCH | 50.375
1129850 | TR - N02 - ARCH | 68
1129887 | TR - N02 - ARCH | 68
1129978 | TR - N02 - ARCH | 68
1129979 | TR - N02 - ARCH | 68
1130031 | TR - N02 - ARCH | 68
1130032 | TR - N02 - ARCH | 68
1130312 | TR - N02 - ARCH | 68
1130313 | TR - N02 - ARCH | 68
1130315 | TR - N02 - ARCH | 68
1130316 | TR - N02 - ARCH | 68
1130317 | TR - N02 - ARCH | 66.75
1130397 | TR - N02 - ARCH | 66.75
1130398 | TR - N02 - ARCH | 66.75
1190191 | TR - N02 - ARCH | 66.75
1190229 | TR - N02 - ARCH | 66.75
1190231 | TR - N02 - ARCH | 66.75
1190294 | TR - N02 - ARCH | 66.75
1190296 | TR - N02 - ARCH | 66.75
580629 | Toiture - Cuisine | 140
580630 | Toiture - Cuisine | 140
580631 | Toiture - Cuisine | 140
580632 | Toiture - Cuisine | 140
580633 | Toiture - Cuisine | 140
580634 | Toiture - Cuisine | 140
580635 | Toiture - Cuisine | 140
580636 | Toiture - Cuisine | 140
580637 | Toiture - Cuisine | 140
580638 | Toiture - Cuisine | 140
580639 | Toiture - Cuisine | 140
580640 | Toiture - Cuisine | 140
580641 | Toiture - Cuisine | 140
580642 | Toiture - Cuisine | 140
580643 | Toiture - Cuisine | 140
580644 | Toiture - Cuisine | 140
580663 | Toiture - Cuisine | 140
580664 | Toiture - Cuisine | 140
580665 | Toiture - Cuisine | 140
580666 | Toiture - Cuisine | 140
580667 | Toiture - Cuisine | 140
580668 | Toiture - Cuisine | 140
580669 | Toiture - Cuisine | 140
580670 | Toiture - Cuisine | 140
580671 | Toiture - Cuisine | 140
580672 | Toiture - Cuisine | 140
580673 | Toiture - Cuisine | 140
580674 | Toiture - Cuisine | 140
580675 | Toiture - Cuisine | 140
580676 | Toiture - Cuisine | 140
580677 | Toiture - Cuisine | 140
580678 | Toiture - Cuisine | 140
580679 | Toiture - Cuisine | 140
580698 | Toiture - Cuisine | 224.5
580699 | Toiture - Cuisine | 224.5
580700 | Toiture - Cuisine | 224.5
580701 | Toiture - Cuisine | 224.5
580702 | Toiture - Cuisine | 224.5
580703 | Toiture - Cuisine | 224.5
580704 | Toiture - Cuisine | 224.5
580705 | Toiture - Cuisine | 224.5
580706 | Toiture - Cuisine | 224.5
580707 | Toiture - Cuisine | 224.5
580708 | Toiture - Cuisine | 224.5
580709 | Toiture - Cuisine | 224.5
580710 | Toiture - Cuisine | 224.5
580711 | Toiture - Cuisine | 224.5
580712 | Toiture - Cuisine | 224.5
580713 | Toiture - Cuisine | 224.5
580714 | Toiture - Cuisine | 224.5
580715 | Toiture - Cuisine | 224.5
675648 | Toiture - Cuisine | 140
1188047 | Toiture - Cuisine | 14.3
1188048 | Toiture - Cuisine | 14.3
581915 | N00 - COO | 124.25
581916 | N00 - COO | 312.5
581917 | N00 - COO | 312.5
581954 | N00 - COO | 124.25
582482 | N00 - COO | 144.25
582486 | N00 - COO | 312.5
582487 | N00 - COO | 299.5
661198 | N00 - COO | 135.75
661199 | N00 - COO | 299.5
1185165 | N00 - COO | 96.5
1185166 | N00 - COO | 299.5
1185167 | N00 - COO | 299.5
1367054 | N00 - COO | 144.25
1367055 | N00 - COO | 135.75
1367056 | N00 - COO | 96.5
582718 | N00 - COO | 83.5
582719 | N00 - COO | 83.5
582720 | N00 - COO | 312.5
582834 | N00 - COO | 312.5
582835 | N00 - COO | 299.5
1185155 | N00 - COO | 299.5
1185156 | N00 - COO | 299.5
1367037 | N00 - COO | 280
1367038 | N00 - COO | 96.5
1367077 | N00 - COO | 280
1367078 | N00 - COO | 96.5
583639 | N00 - COO | 181.75
583640 | N00 - COO | 313
583641 | N00 - COO | 313
1171764 | N00 - COO | 83.5
1171765 | N00 - COO | 312.5
1171766 | N00 - COO | 312.5
1298283 | N00 - COO | 181.75
1298284 | N00 - COO | 83.5
586596 | N00 - COO | 313
586597 | N00 - COO | 306.5
1185091 | N00 - COO | 299.5
1185092 | N00 - COO | 299.5
1298267 | N00 - COO | 96.5
1298276 | N00 - COO | 280
1298277 | N00 - COO | 96.5
586599 | N00 - COO | 280
586600 | N00 - COO | 313
586601 | N00 - COO | 300
1185101 | N00 - COO | 96.5
1185102 | N00 - COO | 299.5
1185103 | N00 - COO | 299.5
1298279 | N00 - COO | 280
1298280 | N00 - COO | 96.5
586603 | N00 - COO | 280
586604 | N00 - COO | 313
586605 | N00 - COO | 300
1185108 | N00 - COO | 96.5
1185109 | N00 - COO | 299.5
1185110 | N00 - COO | 299.5
1298288 | N00 - COO | 280
1298289 | N00 - COO | 96.5
584243 | N00 - COO | 83.5
584245 | N00 - COO | 313
1050463 | N00 - COO | 83.5
1185263 | N00 - COO | 83.5
1185264 | N00 - COO | 83.5
1185265 | N00 - COO | 312.5
584329 | N00 - COO | 93.25
584330 | N00 - COO | 313
584331 | N00 - COO | 300
1050759 | N00 - COO | 93.25
1050761 | N00 - COO | 300
936586 | N00 - COO | 93.25
936587 | N00 - COO | 313
936588 | N00 - COO | 300
1051285 | N00 - COO | 93.25
1051287 | N00 - COO | 300
584620 | N00 - COO | 280
584621 | N00 - COO | 313
584622 | N00 - COO | 300
1051334 | N00 - COO | 280
585408 | N00 - COO | 280
585409 | N00 - COO | 316.5
1185134 | N00 - COO | 299.5
1298211 | N00 - COO | 299.5
1298299 | N00 - COO | 96.5
1330111 | N00 - COO | 283.25
1330114 | N00 - COO | 303.5
1330116 | N00 - COO | 96.5
585549 | N00 - COO | 280
585550 | N00 - COO | 319.615
585551 | N00 - COO | 306.615
1185250 | N00 - COO | 96.5
1185251 | N00 - COO | 299.5
1298214 | N00 - COO | 299.5
1298303 | N00 - COO | 283.25
1298304 | N00 - COO | 96.5
1298305 | N00 - COO | 0.614557
667147 | N00 - COO | 280
667148 | N00 - COO | 280
667149 | N00 - COO | 280
667150 | N00 - COO | 280
667151 | N00 - COO | 280
667152 | N00 - COO | 165
667158 | N00 - COO | 298
667159 | N00 - COO | 298
667160 | N00 - COO | 298
667161 | N00 - COO | 298
667162 | N00 - COO | 298
667163 | N00 - COO | 298
1185220 | N00 - COO | 96.5
1185221 | N00 - COO | 299.5
1185222 | N00 - COO | 299.5
1185232 | N00 - COO | 96.5
1185233 | N00 - COO | 299.5
1185234 | N00 - COO | 299.5
1185239 | N00 - COO | 299.5
1185240 | N00 - COO | 299.5
1195926 | N00 - COO | 96.5
1195985 | N00 - COO | 96.5
1195986 | N00 - COO | 299.5
1195987 | N00 - COO | 299.5
1195994 | N00 - COO | 96.5
1195995 | N00 - COO | 299.5
1195996 | N00 - COO | 299.5
1196001 | N00 - COO | 96.5
1196002 | N00 - COO | 299.5
1196003 | N00 - COO | 299.5
1196032 | N00 - COO | 298
1298321 | N00 - COO | 96.5
1298332 | N00 - COO | 96.5
1298337 | N00 - COO | 96.5
1298344 | N00 - COO | 96.5
1298350 | N00 - COO | 96.5
1298358 | N00 - COO | 165
1298359 | N00 - COO | 280
1298360 | N00 - COO | 280
1298361 | N00 - COO | 280
1298362 | N00 - COO | 280
1298363 | N00 - COO | 280
1298364 | N00 - COO | 96.5
786561 | N00 - COO | 298
1330129 | N00 - COO | 160
1330231 | N00 - COO | 25.1188
1330232 | N00 - COO | 74.8812
1330233 | N00 - COO | 299.5
1330234 | N00 - COO | 299.5
1330264 | N00 - COO | 160
1330265 | N00 - COO | 75
1330266 | N00 - COO | 74.8812
1330267 | N00 - COO | 25.1188
787166 | N00 - COO | 147
787168 | N00 - COO | 147
787170 | N00 - COO | 312.5
787171 | N00 - COO | 312.5
787270 | N00 - COO | 147
787272 | N00 - COO | 147
787274 | N00 - COO | 312.5
787275 | N00 - COO | 312.5
787532 | N00 - COO | 299.5
787533 | N00 - COO | 299.5
1330136 | N00 - COO | 100
1330137 | N00 - COO | 100
1330171 | N00 - COO | 93.5
1330173 | N00 - COO | 299.5
1330191 | N00 - COO | 100
1330192 | N00 - COO | 100
1330193 | N00 - COO | 93.5
794911 | N00 - COO | 61.2698
794912 | N00 - COO | 90
794913 | N00 - COO | 237
794914 | N00 - COO | 237
1770989 | N00 - COO | 90
1770990 | N00 - COO | 61.2698
1006483 | N00 - COO | 133.52
1006484 | N00 - COO | 133.52
1006485 | N00 - COO | 311
1006486 | N00 - COO | 311
1037346 | N00 - COO | 87
1037347 | N00 - COO | 312.5
1037348 | N00 - COO | 312.5
1330146 | N00 - COO | 87
1039316 | N00 - COO | 13.25
1039317 | N00 - COO | 90
1039318 | N00 - COO | 298
1039319 | N00 - COO | 304.5
1161874 | N00 - COO | 10
1162078 | N00 - COO | 89.3033
1162080 | N00 - COO | 224
1045423 | N00 - COO | 283.25
1045428 | N00 - COO | 300
1136592 | N00 - COO | 313
1185114 | N00 - COO | 96.5
1185115 | N00 - COO | 299.5
1185116 | N00 - COO | 299.5
1185124 | N00 - COO | 300
1298292 | N00 - COO | 96.5
1298293 | N00 - COO | 283.25
1138437 | N00 - COO | 280
1138438 | N00 - COO | 280
1138439 | N00 - COO | 280
1138440 | N00 - COO | 260
1138441 | N00 - COO | 300
1138442 | N00 - COO | 280
1138443 | N00 - COO | 280
1138444 | N00 - COO | 220.129
1138446 | N00 - COO | 306.509
1141375 | N00 - COO | 299.5
1141376 | N00 - COO | 299.5
1141406 | N00 - COO | 299.5
1141407 | N00 - COO | 299.5
1141480 | N00 - COO | 299.5
1141481 | N00 - COO | 299.5
1169696 | N00 - COO | 13.25
1169697 | N00 - COO | 299.5
1169698 | N00 - COO | 299.5
1169890 | N00 - COO | 13.25
1169891 | N00 - COO | 299.5
1169892 | N00 - COO | 299.5
1169973 | N00 - COO | 13.25
1169974 | N00 - COO | 299.5
1169975 | N00 - COO | 299.5
1298449 | N00 - COO | 83.25
1298493 | N00 - COO | 83.25
1298494 | N00 - COO | 13.25
1298495 | N00 - COO | 0.508601
1298553 | N00 - COO | 83.25
1298588 | N00 - COO | 63.25
1298608 | N00 - COO | 83.25
1298623 | N00 - COO | 83.25
1298637 | N00 - COO | 83.25
1298665 | N00 - COO | 83.25
1298668 | N00 - COO | 13.25
1298669 | N00 - COO | 0.508601
1298712 | N00 - COO | 83.25
1298716 | N00 - COO | 13.25
1298717 | N00 - COO | 0.508601
1298761 | N00 - COO | 16.5
1298762 | N00 - COO | 0.508601
1298811 | N00 - COO | 36.5
1298812 | N00 - COO | 0.508601
1298856 | N00 - COO | 220.129
1298857 | N00 - COO | 280
1298858 | N00 - COO | 280
1298859 | N00 - COO | 280
1298860 | N00 - COO | 260
1298861 | N00 - COO | 300
1298862 | N00 - COO | 280
1298863 | N00 - COO | 280
1298864 | N00 - COO | 16.5
1298865 | N00 - COO | 0.508601
1145654 | N00 - COO | 207.171
1145655 | N00 - COO | 280
1145656 | N00 - COO | 280
1145657 | N00 - COO | 280
1145658 | N00 - COO | 280
1145659 | N00 - COO | 222.551
1145668 | N00 - COO | 300
1145669 | N00 - COO | 300
1145670 | N00 - COO | 300
1145671 | N00 - COO | 300
1145672 | N00 - COO | 300
1145789 | N00 - COO | 280
1145790 | N00 - COO | 280
1145791 | N00 - COO | 280
1145792 | N00 - COO | 280
1145793 | N00 - COO | 222.551
1145794 | N00 - COO | 207.171
1145795 | N00 - COO | 300
1147419 | N00 - COO | 300
1147433 | N00 - COO | 280
1147434 | N00 - COO | 140
1147435 | N00 - COO | 300
1147436 | N00 - COO | 300
1148472 | N00 - COO | 280
1200154 | N00 - COO | 13.4785
1200354 | N00 - COO | 13.4785
1200355 | N00 - COO | 280
1200356 | N00 - COO | 280
1200357 | N00 - COO | 140
1341736 | N00 - COO | 140
1341737 | N00 - COO | 140
1341738 | N00 - COO | 300
1148967 | N00 - COO | 214
1148970 | N00 - COO | 224.359
1148973 | N00 - COO | 300
1148974 | N00 - COO | 300
1199369 | N00 - COO | 224.359
1199370 | N00 - COO | 55.6406
1199371 | N00 - COO | 300
1492851 | N00 - COO | 55.6406
1492852 | N00 - COO | 214
1150234 | N00 - COO | 66
1150235 | N00 - COO | 280
1150236 | N00 - COO | 280
1150237 | N00 - COO | 280
1150238 | N00 - COO | 280
1150239 | N00 - COO | 280
1150240 | N00 - COO | 280
1150241 | N00 - COO | 280
1150242 | N00 - COO | 280
1150243 | N00 - COO | 66
1150244 | N00 - COO | 300
1150245 | N00 - COO | 300
1150246 | N00 - COO | 300
1150247 | N00 - COO | 300
1150248 | N00 - COO | 300
1159118 | N00 - COO | 312.5
1159119 | N00 - COO | 312.5
1323311 | N00 - COO | 87
1330156 | N00 - COO | 87
1159542 | N00 - COO | 87
1159543 | N00 - COO | 312.5
1159544 | N00 - COO | 312.5
1330212 | N00 - COO | 87
1159611 | N00 - COO | 87
1159612 | N00 - COO | 312.5
1159613 | N00 - COO | 312.5
1330220 | N00 - COO | 87
1159763 | N00 - COO | 87
1159764 | N00 - COO | 312.5
1159765 | N00 - COO | 312.5
1330224 | N00 - COO | 87
1160917 | N00 - COO | 87
1160918 | N00 - COO | 316.5
1160919 | N00 - COO | 316.5
1161948 | N00 - COO | 13.25
1161949 | N00 - COO | 90
1161950 | N00 - COO | 298
1161951 | N00 - COO | 304.5
1161955 | N00 - COO | 10
1162020 | N00 - COO | 89.3033
667154 | N00 - COO | 290
667165 | N00 - COO | 298
667166 | N00 - COO | 298
1185214 | N00 - COO | 96.5
1185215 | N00 - COO | 299.5
1185216 | N00 - COO | 299.5
1185227 | N00 - COO | 299.5
1185228 | N00 - COO | 299.5
1196007 | N00 - COO | 280
1196017 | N00 - COO | 298
1196054 | N00 - COO | 96.5
1298310 | N00 - COO | 96.5
1298317 | N00 - COO | 96.5
1298318 | N00 - COO | 280
1298319 | N00 - COO | 290
1199349 | N00 - COO | 160.693
1199350 | N00 - COO | 313
1199351 | N00 - COO | 300
1199355 | N00 - COO | 300
1199359 | N00 - COO | 160.693
578695 | N00 - COO | 140
578696 | N00 - COO | 140
578698 | N00 - COO | 140
578700 | N00 - COO | 140
578701 | N00 - COO | 140
578702 | N00 - COO | 140
578709 | N00 - COO | 299.5
578710 | N00 - COO | 299.5
578711 | N00 - COO | 299.5
578712 | N00 - COO | 299.5
578713 | N00 - COO | 299.5
578714 | N00 - COO | 299.5
578715 | N00 - COO | 299.5
578716 | N00 - COO | 299.5
1203308 | N00 - COO | 140
1203309 | N00 - COO | 140
1203311 | N00 - COO | 140
1203313 | N00 - COO | 140
1203314 | N00 - COO | 140
1203315 | N00 - COO | 140
1203316 | N00 - COO | 140
1203320 | N00 - COO | 140
1203330 | N00 - COO | 299.5
1203366 | N00 - COO | 140
1203367 | N00 - COO | 140
1203368 | N00 - COO | 299.5
1204018 | N00 - COO | 140
1204020 | N00 - COO | 299.5
1204183 | N00 - COO | 142.95
1204184 | N00 - COO | 299.5
1204474 | N00 - COO | 140
1204475 | N00 - COO | 140
1204476 | N00 - COO | 140
1204477 | N00 - COO | 140
1204478 | N00 - COO | 299.5
1204494 | N00 - COO | 140
1204495 | N00 - COO | 140
1204496 | N00 - COO | 140
1204497 | N00 - COO | 143.25
1204499 | N00 - COO | 140
1204500 | N00 - COO | 140
1204501 | N00 - COO | 140
1204502 | N00 - COO | 142.95
1204503 | N00 - COO | 140
1204504 | N00 - COO | 140
1204505 | N00 - COO | 140
1204506 | N00 - COO | 140
1204507 | N00 - COO | 140
1204508 | N00 - COO | 140
1204509 | N00 - COO | 140
1204510 | N00 - COO | 143.25
1204511 | N00 - COO | 140
1204512 | N00 - COO | 299.5
1204513 | N00 - COO | 299.5
1204514 | N00 - COO | 299.5
1204515 | N00 - COO | 299.5
1204516 | N00 - COO | 299.5
1204517 | N00 - COO | 299.5
1204518 | N00 - COO | 299.5
1204519 | N00 - COO | 299.5
1204520 | N00 - COO | 299.5
1204571 | N00 - COO | 299.5
1209580 | N00 - COO | 140.05
1209583 | N00 - COO | 140
1209584 | N00 - COO | 140
1209585 | N00 - COO | 299.5
1209622 | N00 - COO | 140
1214146 | N00 - COO | 19.8
1214147 | N00 - COO | 19.8
1337336 | N00 - COO | 93.25
1337337 | N00 - COO | 313
1337338 | N00 - COO | 300
1337341 | N00 - COO | 93.25
1337342 | N00 - COO | 300

# IfcMember: 180 x 50mm (4)
In: N00 - COO
Type - PredefinedType: MEMBER
Type - Pset_MemberCommon - IsExternal: no; Reference: 180 x 50mm
Type - Pset_QuantityTakeOff - Reference: 180 x 50mm
Material: Plastique, blanc opaque
Pset_MemberCommon - IsExternal: yes
Name (Meneau rectangulaire:180 x 50mm:...) | Span (cm)
791439 | 134
791440 | 175
791441 | 175
1718577 | 134

# IfcMember: 200x50 mm (969)
Type - PredefinedType: MEMBER
Type - Pset_MemberCommon - IsExternal: no; Reference: 200x50 mm
Type - Pset_QuantityTakeOff - Reference: 200x50 mm
Material: Aluminium
Pset_MemberCommon - IsExternal: yes
Name (Meneau rectangulaire:200x50 mm:...) | In | Span (cm)
596471 | N00 - COO | 7.5
596472 | N00 - COO | 141.831
598180 | N00 - COO | 136.831
599340 | N00 - COO | 66.5
599342 | N00 - COO | 73.4999
605013 | N00 - COO | 70
605014 | N00 - COO | 70
605015 | N00 - COO | 70
605016 | N00 - COO | 70
605100 | N00 - COO | 70
605101 | N00 - COO | 70
605102 | N00 - COO | 70
605103 | N00 - COO | 70
605193 | N00 - COO | 70
605194 | N00 - COO | 70
605195 | N00 - COO | 70
605196 | N00 - COO | 70
605270 | N00 - COO | 70
605271 | N00 - COO | 70
605272 | N00 - COO | 70
605273 | N00 - COO | 70
605335 | N00 - COO | 70
605336 | N00 - COO | 70
605337 | N00 - COO | 70
605338 | N00 - COO | 70
605409 | N00 - COO | 70
605410 | N00 - COO | 70
605411 | N00 - COO | 70
605412 | N00 - COO | 70
605458 | N00 - COO | 70
605459 | N00 - COO | 70
605460 | N00 - COO | 70
605461 | N00 - COO | 70
605544 | N00 - COO | 70
605545 | N00 - COO | 70
605546 | N00 - COO | 70
605547 | N00 - COO | 70
605586 | N00 - COO | 70
605587 | N00 - COO | 70
605588 | N00 - COO | 70
605589 | N00 - COO | 70
605631 | N00 - COO | 70
605632 | N00 - COO | 70
605633 | N00 - COO | 70
605634 | N00 - COO | 70
605680 | N00 - COO | 70
605681 | N00 - COO | 70
605682 | N00 - COO | 70
605683 | N00 - COO | 70
605735 | N00 - COO | 70
605736 | N00 - COO | 70
605737 | N00 - COO | 70
605738 | N00 - COO | 70
605893 | N00 - COO | 423
605894 | N00 - COO | 425.5
605895 | N00 - COO | 307.5
605908 | N00 - COO | 423
605909 | N00 - COO | 425.5
605910 | N00 - COO | 307.5
605919 | N00 - COO | 423
605920 | N00 - COO | 425.5
605921 | N00 - COO | 307.5
605931 | N00 - COO | 423
605932 | N00 - COO | 425.5
605933 | N00 - COO | 307.5
605942 | N00 - COO | 423
605943 | N00 - COO | 425.5
605944 | N00 - COO | 307.5
605950 | N00 - COO | 423
605951 | N00 - COO | 425.5
605952 | N00 - COO | 307.5
605961 | N00 - COO | 423
605962 | N00 - COO | 425.5
605963 | N00 - COO | 307.5
605972 | N00 - COO | 423
605973 | N00 - COO | 425.5
605974 | N00 - COO | 307.5
605980 | N00 - COO | 423
605981 | N00 - COO | 425.5
605982 | N00 - COO | 307.5
605989 | N00 - COO | 423
605990 | N00 - COO | 425.5
605991 | N00 - COO | 307.5
606001 | N00 - COO | 423
606002 | N00 - COO | 425.5
606003 | N00 - COO | 307.5
606013 | N00 - COO | 423
606014 | N00 - COO | 425.5
606015 | N00 - COO | 307.5
606290 | N00 - COO | 70
606291 | N00 - COO | 70
606372 | N00 - COO | 70
606373 | N00 - COO | 70
606374 | N00 - COO | 70
606419 | N00 - COO | 70
606420 | N00 - COO | 70
606421 | N00 - COO | 70
606458 | N00 - COO | 70
606459 | N00 - COO | 70
606460 | N00 - COO | 70
606578 | N00 - COO | 423
606587 | N00 - COO | 423
606598 | N00 - COO | 423
606609 | N00 - COO | 423
606729 | N00 - COO | 313.5
607515 | N00 - COO | 70
607516 | N00 - COO | 70
607517 | N00 - COO | 70
607518 | N00 - COO | 70
607633 | N00 - COO | 70
607634 | N00 - COO | 70
607635 | N00 - COO | 70
607636 | N00 - COO | 70
608344 | N00 - COO | 423
608346 | N00 - COO | 423
608950 | N00 - COO | 70
608951 | N00 - COO | 70
608952 | N00 - COO | 70
608953 | N00 - COO | 70
609107 | N00 - COO | 70
609108 | N00 - COO | 70
609109 | N00 - COO | 70
609110 | N00 - COO | 70
609248 | N00 - COO | 70
609249 | N00 - COO | 70
609250 | N00 - COO | 70
609251 | N00 - COO | 70
609305 | N00 - COO | 70
609306 | N00 - COO | 70
609307 | N00 - COO | 70
609308 | N00 - COO | 70
609360 | N00 - COO | 70
609361 | N00 - COO | 70
609362 | N00 - COO | 70
609363 | N00 - COO | 70
609401 | N00 - COO | 423
609402 | N00 - COO | 425.5
609404 | N00 - COO | 423
609406 | N00 - COO | 425.5
609407 | N00 - COO | 423
609408 | N00 - COO | 425.5
609409 | N00 - COO | 423
609410 | N00 - COO | 425.5
609411 | N00 - COO | 423
609412 | N00 - COO | 425.5
609500 | N00 - COO | 70
609501 | N00 - COO | 70
609502 | N00 - COO | 70
609503 | N00 - COO | 70
609565 | N00 - COO | 70
609566 | N00 - COO | 70
609567 | N00 - COO | 70
609568 | N00 - COO | 70
609607 | N00 - COO | 70
609608 | N00 - COO | 70
609609 | N00 - COO | 70
609610 | N00 - COO | 70
609655 | N00 - COO | 70
609656 | N00 - COO | 70
609657 | N00 - COO | 70
609658 | N00 - COO | 70
609693 | N00 - COO | 70
609694 | N00 - COO | 70
609695 | N00 - COO | 70
609696 | N00 - COO | 70
609733 | N00 - COO | 70
609734 | N00 - COO | 70
609735 | N00 - COO | 70
609736 | N00 - COO | 70
609777 | N00 - COO | 70
609778 | N00 - COO | 70
609779 | N00 - COO | 70
609780 | N00 - COO | 70
609809 | N00 - COO | 70
609810 | N00 - COO | 70
609811 | N00 - COO | 70
609812 | N00 - COO | 70
609836 | N00 - COO | 423
609837 | N00 - COO | 423
609838 | N00 - COO | 423
609839 | N00 - COO | 423
609840 | N00 - COO | 423
609841 | N00 - COO | 423
609842 | N00 - COO | 423
609843 | N00 - COO | 423
609924 | N00 - COO | 70
609925 | N00 - COO | 70
609926 | N00 - COO | 70
609927 | N00 - COO | 70
609976 | N00 - COO | 70
609977 | N00 - COO | 70
609978 | N00 - COO | 70
609979 | N00 - COO | 70
610011 | N00 - COO | 70
610012 | N00 - COO | 70
610013 | N00 - COO | 70
610014 | N00 - COO | 70
610080 | N00 - COO | 70
610081 | N00 - COO | 70
610082 | N00 - COO | 70
610083 | N00 - COO | 70
610131 | N00 - COO | 70
610132 | N00 - COO | 70
610133 | N00 - COO | 70
610134 | N00 - COO | 70
610182 | N00 - COO | 70
610183 | N00 - COO | 70
610184 | N00 - COO | 70
610185 | N00 - COO | 70
610239 | N00 - COO | 70
610240 | N00 - COO | 70
610241 | N00 - COO | 70
610242 | N00 - COO | 70
610288 | N00 - COO | 70
610289 | N00 - COO | 70
610290 | N00 - COO | 70
610291 | N00 - COO | 70
610400 | N00 - COO | 425.5
610402 | N00 - COO | 423
610403 | N00 - COO | 423
610404 | N00 - COO | 425.5
610405 | N00 - COO | 425.5
610406 | N00 - COO | 423
610407 | N00 - COO | 423
610408 | N00 - COO | 425.5
610409 | N00 - COO | 425.5
610410 | N00 - COO | 423
610411 | N00 - COO | 425.5
610412 | N00 - COO | 423
610413 | N00 - COO | 425.5
610414 | N00 - COO | 423
610415 | N00 - COO | 425.5
610419 | N00 - COO | 423
610492 | N00 - COO | 70
610493 | N00 - COO | 70
610494 | N00 - COO | 70
610495 | N00 - COO | 70
610534 | N00 - COO | 70
610535 | N00 - COO | 70
610536 | N00 - COO | 70
610537 | N00 - COO | 70
610724 | N00 - COO | 423
610725 | N00 - COO | 423
610819 | N00 - COO | 70
610820 | N00 - COO | 70
610821 | N00 - COO | 70
610822 | N00 - COO | 70
610911 | N00 - COO | 70
610912 | N00 - COO | 70
610913 | N00 - COO | 70
610914 | N00 - COO | 70
610987 | N00 - COO | 70
610988 | N00 - COO | 70
610989 | N00 - COO | 70
610990 | N00 - COO | 70
611027 | N00 - COO | 70
611028 | N00 - COO | 70
611029 | N00 - COO | 70
611030 | N00 - COO | 70
611081 | N00 - COO | 70
611082 | N00 - COO | 70
611083 | N00 - COO | 70
611084 | N00 - COO | 70
611139 | N00 - COO | 70
611140 | N00 - COO | 70
611141 | N00 - COO | 70
611142 | N00 - COO | 70
611175 | N00 - COO | 70
611176 | N00 - COO | 70
611177 | N00 - COO | 70
611178 | N00 - COO | 70
611213 | N00 - COO | 70
611214 | N00 - COO | 70
611215 | N00 - COO | 70
611216 | N00 - COO | 70
611247 | N00 - COO | 70
611248 | N00 - COO | 70
611249 | N00 - COO | 70
611250 | N00 - COO | 70
611297 | N00 - COO | 70
611298 | N00 - COO | 70
611299 | N00 - COO | 70
611300 | N00 - COO | 70
611355 | N00 - COO | 70
611356 | N00 - COO | 70
611357 | N00 - COO | 70
611358 | N00 - COO | 70
611395 | N00 - COO | 70
611396 | N00 - COO | 70
611397 | N00 - COO | 70
611398 | N00 - COO | 70
611589 | N00 - COO | 70
611590 | N00 - COO | 70
611591 | N00 - COO | 70
611592 | N00 - COO | 70
611666 | N00 - COO | 423
611667 | N00 - COO | 423
611668 | N00 - COO | 423
611669 | N00 - COO | 423
611670 | N00 - COO | 423
611671 | N00 - COO | 423
611672 | N00 - COO | 423
611673 | N00 - COO | 423
611674 | N00 - COO | 423
611675 | N00 - COO | 423
611676 | N00 - COO | 423
611677 | N00 - COO | 423
611678 | N00 - COO | 423
612979 | N00 - COO | 425.5
613198 | N00 - COO | 70
613199 | N00 - COO | 70
613200 | N00 - COO | 70
613326 | N00 - COO | 70
613327 | N00 - COO | 70
613328 | N00 - COO | 70
613363 | N00 - COO | 70
613364 | N00 - COO | 70
613365 | N00 - COO | 70
613434 | N00 - COO | 70
613435 | N00 - COO | 70
613436 | N00 - COO | 70
613506 | N00 - COO | 70
613507 | N00 - COO | 66.5
613508 | N00 - COO | 66.5
613546 | N00 - COO | 70
613547 | N00 - COO | 70
613548 | N00 - COO | 70
613579 | N00 - COO | 70
613580 | N00 - COO | 70
613581 | N00 - COO | 70
614129 | N00 - COO | 423
614139 | N00 - COO | 423
614143 | N00 - COO | 423
614148 | N00 - COO | 423
614152 | N00 - COO | 423
614156 | N00 - COO | 423
614157 | N00 - COO | 423
614205 | N00 - COO | 70
614206 | N00 - COO | 70
614207 | N00 - COO | 70
614245 | N00 - COO | 70
614246 | N00 - COO | 70
614247 | N00 - COO | 70
614276 | N00 - COO | 70
614277 | N00 - COO | 70
614278 | N00 - COO | 70
614426 | N00 - COO | 423
614428 | N00 - COO | 423
614429 | N00 - COO | 423
614508 | N00 - COO | 70
614509 | N00 - COO | 70
614510 | N00 - COO | 70
614573 | N00 - COO | 70
614574 | N00 - COO | 70
614575 | N00 - COO | 70
614589 | N00 - COO | 423
614591 | N00 - COO | 423
614985 | N00 - COO | 80
614986 | N00 - COO | 70
614987 | N00 - COO | 70
614988 | N00 - COO | 70
615026 | N00 - COO | 423
615448 | N00 - COO | 87.5
615449 | N00 - COO | 87.5
615450 | N00 - COO | 80
618600 | N00 - COO | 307.5
618680 | N00 - COO | 140
618681 | N00 - COO | 140
618753 | N00 - COO | 140
618754 | N00 - COO | 140
618755 | N00 - COO | 140
618821 | N00 - COO | 140
618822 | N00 - COO | 140
618823 | N00 - COO | 140
618976 | N00 - COO | 140
618977 | N00 - COO | 140
618978 | N00 - COO | 140
619045 | N00 - COO | 140
619046 | N00 - COO | 140
619047 | N00 - COO | 141.831
619191 | N00 - COO | 157.5
619192 | N00 - COO | 157.5
619259 | N00 - COO | 122.5
619260 | N00 - COO | 280
619261 | N00 - COO | 280
619399 | N00 - COO | 280
619400 | N00 - COO | 157.5
619401 | N00 - COO | 157.5
619476 | N00 - COO | 122.5
619477 | N00 - COO | 157.5
619478 | N00 - COO | 160
619907 | N00 - COO | 307.5
619962 | N00 - COO | 307.5
619969 | N00 - COO | 307.5
619983 | N00 - COO | 307.5
619997 | N00 - COO | 307.5
620004 | N00 - COO | 307.5
620011 | N00 - COO | 307.5
620025 | N00 - COO | 307.5
620032 | N00 - COO | 307.5
622585 | N00 - COO | 157.5
622586 | N00 - COO | 122.5
622587 | N00 - COO | 122.5
622588 | N00 - COO | 167.5
622589 | N00 - COO | 167.5
622591 | N00 - COO | 167.5
622592 | N00 - COO | 167.5
622593 | N00 - COO | 167.5
622732 | N00 - COO | 157.5
622733 | N00 - COO | 122.5
622819 | N00 - COO | 10
622820 | N00 - COO | 122.5
622821 | N00 - COO | 122.5
622907 | N00 - COO | 140
622908 | N00 - COO | 140
622959 | N00 - COO | 140
622960 | N00 - COO | 140
622961 | N00 - COO | 140
623015 | N00 - COO | 140
623016 | N00 - COO | 140
623017 | N00 - COO | 140
623074 | N00 - COO | 140
623075 | N00 - COO | 140
623076 | N00 - COO | 140
623139 | N00 - COO | 140
623140 | N00 - COO | 140
623141 | N00 - COO | 140
623182 | N00 - COO | 141.831
623183 | N00 - COO | 141.831
623184 | N00 - COO | 141.831
623195 | N00 - COO | 167.5
623197 | N00 - COO | 167.5
623198 | N00 - COO | 167.5
623199 | N00 - COO | 167.5
623200 | N00 - COO | 167.5
623290 | N00 - COO | 140
691972 | N00 - COO | 70
691973 | N00 - COO | 70
691974 | N00 - COO | 70
691975 | N00 - COO | 70
691976 | N00 - COO | 70
691977 | N00 - COO | 70
691978 | N00 - COO | 70
691979 | N00 - COO | 70
691980 | N00 - COO | 70
691981 | N00 - COO | 70
691982 | N00 - COO | 70
691983 | N00 - COO | 70
691984 | N00 - COO | 70
691985 | N00 - COO | 70
691986 | N00 - COO | 70
691987 | N00 - COO | 66.5
692023 | N00 - COO | 425.5
692035 | N00 - COO | 425.5
692039 | N00 - COO | 425.5
692043 | N00 - COO | 425.5
692046 | N00 - COO | 425.5
692048 | N00 - COO | 425.5
692051 | N00 - COO | 425.5
804435 | N00 - COO | 147.5
804436 | N00 - COO | 140
804437 | N00 - COO | 140
855217 | N00 - COO | 170
855218 | N00 - COO | 310
855245 | N00 - COO | 167.5
855253 | N00 - COO | 167.5
1042689 | N00 - COO | 122.5
650342 | Toiture - Cuisine | 93.8632
650343 | Toiture - Cuisine | 121.5
650767 | Toiture - Cuisine | 121.5
650768 | Toiture - Cuisine | 140
650844 | Toiture - Cuisine | 140
650845 | Toiture - Cuisine | 140
650894 | Toiture - Cuisine | 140
650895 | Toiture - Cuisine | 140
650933 | Toiture - Cuisine | 140
650934 | Toiture - Cuisine | 140
651011 | Toiture - Cuisine | 140
651012 | Toiture - Cuisine | 140
651078 | Toiture - Cuisine | 140
651079 | Toiture - Cuisine | 140
651126 | Toiture - Cuisine | 140
651127 | Toiture - Cuisine | 140
651199 | Toiture - Cuisine | 140
651200 | Toiture - Cuisine | 140
651288 | Toiture - Cuisine | 140
651289 | Toiture - Cuisine | 140
651378 | Toiture - Cuisine | 140
651379 | Toiture - Cuisine | 140
651434 | Toiture - Cuisine | 140
651435 | Toiture - Cuisine | 140
651473 | Toiture - Cuisine | 140
651474 | Toiture - Cuisine | 140
651526 | Toiture - Cuisine | 140
651527 | Toiture - Cuisine | 140
651598 | Toiture - Cuisine | 140
651599 | Toiture - Cuisine | 140
651645 | Toiture - Cuisine | 140
651646 | Toiture - Cuisine | 140
651686 | Toiture - Cuisine | 140
651687 | Toiture - Cuisine | 140
651757 | Toiture - Cuisine | 140
651758 | Toiture - Cuisine | 140
651787 | Toiture - Cuisine | 140
651788 | Toiture - Cuisine | 140
651834 | Toiture - Cuisine | 140
651835 | Toiture - Cuisine | 140
651868 | Toiture - Cuisine | 417
651875 | Toiture - Cuisine | 417
651879 | Toiture - Cuisine | 417
651883 | Toiture - Cuisine | 417
651890 | Toiture - Cuisine | 417
651894 | Toiture - Cuisine | 417
651898 | Toiture - Cuisine | 417
651902 | Toiture - Cuisine | 417
651906 | Toiture - Cuisine | 417
651913 | Toiture - Cuisine | 417
651917 | Toiture - Cuisine | 417
651924 | Toiture - Cuisine | 417
651931 | Toiture - Cuisine | 417
651932 | Toiture - Cuisine | 417
651936 | Toiture - Cuisine | 417
651937 | Toiture - Cuisine | 417
651941 | Toiture - Cuisine | 417
651942 | Toiture - Cuisine | 417
652101 | Toiture - Cuisine | 417
652106 | Toiture - Cuisine | 417
652218 | Toiture - Cuisine | 417
652337 | Toiture - Cuisine | 140
652338 | Toiture - Cuisine | 140
652375 | Toiture - Cuisine | 140
652376 | Toiture - Cuisine | 140
652390 | Toiture - Cuisine | 417
652394 | Toiture - Cuisine | 417
652506 | Toiture - Cuisine | 140
652507 | Toiture - Cuisine | 140
652549 | Toiture - Cuisine | 140
652550 | Toiture - Cuisine | 93.8632
652575 | Toiture - Cuisine | 417
652578 | Toiture - Cuisine | 417
653090 | N00 - COO | 25
653091 | N00 - COO | 44.5338
653276 | N00 - COO | 30
653277 | N00 - COO | 30
653314 | N00 - COO | 30
653315 | N00 - COO | 30
653358 | N00 - COO | 30
653359 | N00 - COO | 30
653403 | N00 - COO | 30
653404 | N00 - COO | 30
653437 | N00 - COO | 30
653438 | N00 - COO | 30
653476 | N00 - COO | 30
653477 | N00 - COO | 30
653512 | N00 - COO | 30
653513 | N00 - COO | 30
653550 | N00 - COO | 30
653551 | N00 - COO | 30
653590 | N00 - COO | 30
653591 | N00 - COO | 30
653627 | N00 - COO | 30
653628 | N00 - COO | 30
653667 | N00 - COO | 30
653668 | N00 - COO | 30
653714 | N00 - COO | 30
653715 | N00 - COO | 30
653747 | N00 - COO | 30
653748 | N00 - COO | 30
653778 | N00 - COO | 30
653779 | N00 - COO | 30
653830 | N00 - COO | 30
653831 | N00 - COO | 30
653878 | N00 - COO | 30
653879 | N00 - COO | 30
653914 | N00 - COO | 30
653915 | N00 - COO | 30
653959 | N00 - COO | 30
653960 | N00 - COO | 30
653994 | N00 - COO | 30
653995 | N00 - COO | 30
654056 | N00 - COO | 30
654057 | N00 - COO | 30
654087 | N00 - COO | 30
654088 | N00 - COO | 30
654147 | N00 - COO | 30
654148 | N00 - COO | 30
654203 | N00 - COO | 30
654204 | N00 - COO | 30
654228 | N00 - COO | 30
654229 | N00 - COO | 30
654266 | N00 - COO | 30
654267 | N00 - COO | 30
654572 | N00 - COO | 303
654580 | N00 - COO | 303
654586 | N00 - COO | 303
654591 | N00 - COO | 303
654598 | N00 - COO | 303
654605 | N00 - COO | 303
654609 | N00 - COO | 303
654616 | N00 - COO | 303
654623 | N00 - COO | 303
654630 | N00 - COO | 303
654634 | N00 - COO | 303
654641 | N00 - COO | 303
654645 | N00 - COO | 303
654646 | N00 - COO | 303
654653 | N00 - COO | 303
654657 | N00 - COO | 303
654664 | N00 - COO | 303
654671 | N00 - COO | 303
654675 | N00 - COO | 303
654679 | N00 - COO | 303
654686 | N00 - COO | 303
654690 | N00 - COO | 303
654697 | N00 - COO | 303
654701 | N00 - COO | 303
654705 | N00 - COO | 303
654709 | N00 - COO | 303
1011498 | N00 - COO | 30
1011499 | N00 - COO | 30
1011500 | N00 - COO | 303
1011503 | N00 - COO | 30
1011504 | N00 - COO | 30
1011505 | N00 - COO | 303
1011508 | N00 - COO | 30
1011509 | N00 - COO | 30
1011510 | N00 - COO | 303
1011513 | N00 - COO | 30
1011514 | N00 - COO | 30
1011515 | N00 - COO | 303
1011518 | N00 - COO | 30
1011519 | N00 - COO | 30
1011520 | N00 - COO | 303
1011523 | N00 - COO | 30
1011524 | N00 - COO | 30
1011525 | N00 - COO | 303
1094928 | N00 - COO | 30
1094929 | N00 - COO | 30
1094930 | N00 - COO | 303
1095044 | N00 - COO | 30
1095045 | N00 - COO | 30
1095046 | N00 - COO | 303
1095186 | N00 - COO | 30
1095187 | N00 - COO | 25
1095188 | N00 - COO | 303
1228379 | N00 - COO | 30
1228380 | N00 - COO | 30
1228381 | N00 - COO | 303
1228388 | N00 - COO | 30
1228389 | N00 - COO | 30
1228390 | N00 - COO | 303
1228397 | N00 - COO | 44.5338
1228398 | N00 - COO | 30
1228399 | N00 - COO | 303
769416 | N00 - COO | 225.829
769417 | N00 - COO | 280
769484 | N00 - COO | 280
769485 | N00 - COO | 280
769488 | N00 - COO | 280
769489 | N00 - COO | 280
769492 | N00 - COO | 280
769493 | N00 - COO | 280
769496 | N00 - COO | 280
769497 | N00 - COO | 280
769504 | N00 - COO | 280
769505 | N00 - COO | 280
769508 | N00 - COO | 280
769509 | N00 - COO | 280
769512 | N00 - COO | 280
769513 | N00 - COO | 225.829
769520 | N00 - COO | 303
769534 | N00 - COO | 303
769535 | N00 - COO | 303
769537 | N00 - COO | 303
769538 | N00 - COO | 303
769540 | N00 - COO | 303
769541 | N00 - COO | 303
769542 | N00 - COO | 303
769544 | N00 - COO | 303
872309 | N00 - COO | 89.3
872310 | N00 - COO | 89.7
872327 | N00 - COO | 89.7
872330 | N00 - COO | 89.7
872335 | N00 - COO | 70
872336 | N00 - COO | 70
872337 | N00 - COO | 70
872338 | N00 - COO | 70
872343 | N00 - COO | 70
872344 | N00 - COO | 70
872345 | N00 - COO | 70
872346 | N00 - COO | 70
872351 | N00 - COO | 70
872352 | N00 - COO | 70
872353 | N00 - COO | 70
872354 | N00 - COO | 70
872359 | N00 - COO | 70
872360 | N00 - COO | 70
872361 | N00 - COO | 70
872362 | N00 - COO | 70
872367 | N00 - COO | 35
872368 | N00 - COO | 70
872369 | N00 - COO | 70
872370 | N00 - COO | 70
872375 | N00 - COO | 70
872376 | N00 - COO | 70
872377 | N00 - COO | 70
872378 | N00 - COO | 70
872383 | N00 - COO | 70
872384 | N00 - COO | 35
872385 | N00 - COO | 35
872386 | N00 - COO | 35
872391 | N00 - COO | 35
872392 | N00 - COO | 70
872393 | N00 - COO | 70
872394 | N00 - COO | 70
872399 | N00 - COO | 35
872400 | N00 - COO | 70
872401 | N00 - COO | 70
872402 | N00 - COO | 70
872407 | N00 - COO | 70
872408 | N00 - COO | 70
872409 | N00 - COO | 70
872410 | N00 - COO | 70
872448 | N00 - COO | 72
872449 | N00 - COO | 67
872450 | N00 - COO | 67
872451 | N00 - COO | 67
872459 | N00 - COO | 70
872460 | N00 - COO | 70
872461 | N00 - COO | 70
872462 | N00 - COO | 70
872467 | N00 - COO | 70
872468 | N00 - COO | 70
872469 | N00 - COO | 70
872470 | N00 - COO | 70
872475 | N00 - COO | 70
872476 | N00 - COO | 70
872477 | N00 - COO | 70
872478 | N00 - COO | 70
872483 | N00 - COO | 70
872484 | N00 - COO | 70
872485 | N00 - COO | 70
872486 | N00 - COO | 70
872491 | N00 - COO | 70
872492 | N00 - COO | 70
872493 | N00 - COO | 70
872494 | N00 - COO | 70
872499 | N00 - COO | 70
872500 | N00 - COO | 70
872501 | N00 - COO | 70
872502 | N00 - COO | 70
872507 | N00 - COO | 70
872508 | N00 - COO | 70
872509 | N00 - COO | 70
872510 | N00 - COO | 70
872515 | N00 - COO | 70
872516 | N00 - COO | 70
872517 | N00 - COO | 70
872518 | N00 - COO | 70
872523 | N00 - COO | 70
872524 | N00 - COO | 70
872525 | N00 - COO | 70
872526 | N00 - COO | 70
872531 | N00 - COO | 70
872532 | N00 - COO | 70
872533 | N00 - COO | 70
872534 | N00 - COO | 70
872539 | N00 - COO | 70
872540 | N00 - COO | 70
872541 | N00 - COO | 70
872542 | N00 - COO | 70
872569 | N00 - COO | 70
872570 | N00 - COO | 89.3
872571 | N00 - COO | 84.3
872572 | N00 - COO | 84.3
872577 | N00 - COO | 70
872578 | N00 - COO | 70
872579 | N00 - COO | 70
872580 | N00 - COO | 70
872585 | N00 - COO | 70
872586 | N00 - COO | 70
872587 | N00 - COO | 70
872588 | N00 - COO | 70
872593 | N00 - COO | 70
872594 | N00 - COO | 70
872595 | N00 - COO | 70
872596 | N00 - COO | 70
872601 | N00 - COO | 70
872602 | N00 - COO | 70
872603 | N00 - COO | 70
872604 | N00 - COO | 70
872609 | N00 - COO | 70
872610 | N00 - COO | 70
872611 | N00 - COO | 70
872612 | N00 - COO | 70
872617 | N00 - COO | 70
872618 | N00 - COO | 70
872619 | N00 - COO | 70
872620 | N00 - COO | 70
872625 | N00 - COO | 70
872626 | N00 - COO | 70
872627 | N00 - COO | 70
872628 | N00 - COO | 70
872633 | N00 - COO | 70
872634 | N00 - COO | 70
872635 | N00 - COO | 70
872636 | N00 - COO | 70
872650 | N00 - COO | 70
872651 | N00 - COO | 70
872652 | N00 - COO | 70
872653 | N00 - COO | 70
872658 | N00 - COO | 70
872659 | N00 - COO | 35
872660 | N00 - COO | 35
872661 | N00 - COO | 35
872666 | N00 - COO | 70
872667 | N00 - COO | 70
872668 | N00 - COO | 70
872669 | N00 - COO | 70
872674 | N00 - COO | 70
872675 | N00 - COO | 70
872676 | N00 - COO | 70
872677 | N00 - COO | 70
872682 | N00 - COO | 35
872683 | N00 - COO | 70
872684 | N00 - COO | 70
872685 | N00 - COO | 70
872690 | N00 - COO | 70
872691 | N00 - COO | 70
872692 | N00 - COO | 70
872693 | N00 - COO | 70
872698 | N00 - COO | 70
872699 | N00 - COO | 70
872700 | N00 - COO | 70
872701 | N00 - COO | 70
872706 | N00 - COO | 70
872707 | N00 - COO | 35
872708 | N00 - COO | 35
872709 | N00 - COO | 35
872714 | N00 - COO | 70
872715 | N00 - COO | 70
872716 | N00 - COO | 70
872717 | N00 - COO | 70
872722 | N00 - COO | 70
872723 | N00 - COO | 35
872724 | N00 - COO | 35
872725 | N00 - COO | 35
872730 | N00 - COO | 70
872731 | N00 - COO | 70
872732 | N00 - COO | 70
872733 | N00 - COO | 70
872738 | N00 - COO | 70
872739 | N00 - COO | 70
872740 | N00 - COO | 70
872741 | N00 - COO | 70
872746 | N00 - COO | 67
872747 | N00 - COO | 70
872748 | N00 - COO | 70
872749 | N00 - COO | 70
872754 | N00 - COO | 89.7
872755 | N00 - COO | 72
872756 | N00 - COO | 72
872757 | N00 - COO | 72
872893 | N00 - COO | 35
872894 | N00 - COO | 35
872895 | N00 - COO | 35
872897 | N00 - COO | 35
872903 | N00 - COO | 35
872904 | N00 - COO | 35
872905 | N00 - COO | 35
872907 | N00 - COO | 35
872913 | N00 - COO | 35
872914 | N00 - COO | 35
872915 | N00 - COO | 35
872917 | N00 - COO | 35
872923 | N00 - COO | 35
872924 | N00 - COO | 35
872925 | N00 - COO | 35
872927 | N00 - COO | 35
1152448 | N00 - COO | 83.4785
1152449 | N00 - COO | 67.5
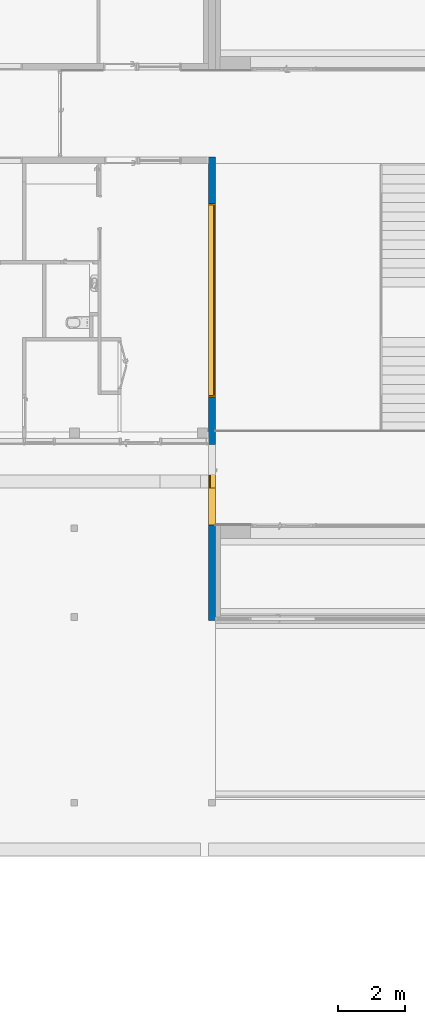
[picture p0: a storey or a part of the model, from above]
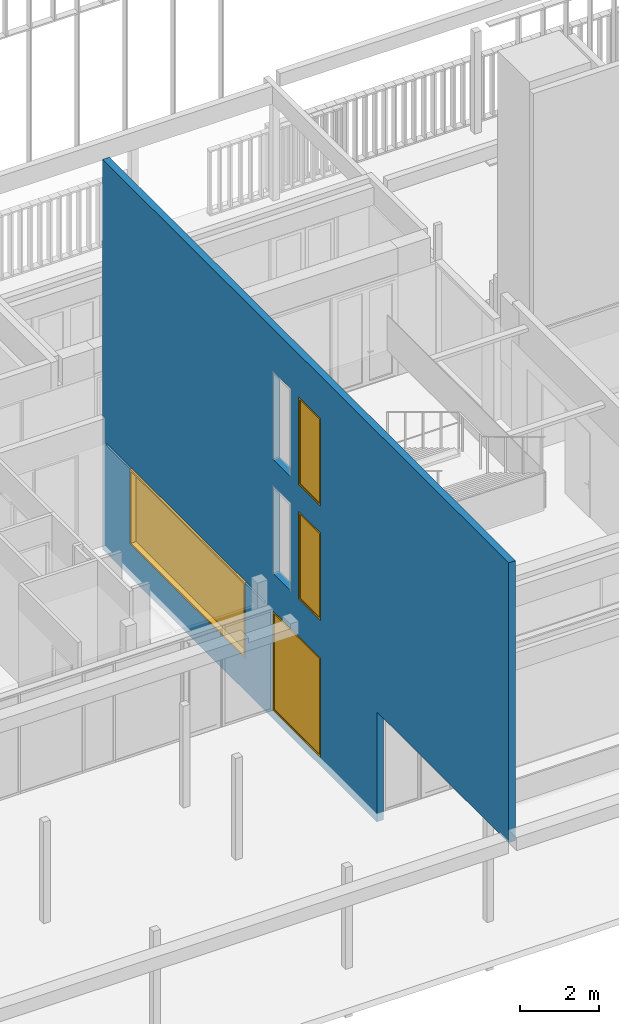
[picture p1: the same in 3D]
Properties of the parts of a building model (IFC2X3), part 4 of 7

# IfcMember: 200x50 mm (969)
Name (Meneau rectangulaire:200x50 mm:...) | In | Span (cm)
1152450 | N00 - COO | 303
1152451 | N00 - COO | 303
1152693 | N00 - COO | 67.5
1152694 | N00 - COO | 70
1152695 | N00 - COO | 303
1152803 | N00 - COO | 70
1152804 | N00 - COO | 72.5
1152805 | N00 - COO | 303
1152916 | N00 - COO | 72.5
1152917 | N00 - COO | 70
1152918 | N00 - COO | 303
1152983 | N00 - COO | 70
1152984 | N00 - COO | 70
1152985 | N00 - COO | 303
1153231 | N00 - COO | 70
1153232 | N00 - COO | 70
1153233 | N00 - COO | 303
1153318 | N00 - COO | 70
1153319 | N00 - COO | 70
1153320 | N00 - COO | 303
1153421 | N00 - COO | 70
1153422 | N00 - COO | 70
1153423 | N00 - COO | 303
1153480 | N00 - COO | 70
1153481 | N00 - COO | 70
1153482 | N00 - COO | 303
1153547 | N00 - COO | 70
1153548 | N00 - COO | 70
1153549 | N00 - COO | 303
1153680 | N00 - COO | 70
1153681 | N00 - COO | 70
1153682 | N00 - COO | 303
1153741 | N00 - COO | 70
1153742 | N00 - COO | 70
1153743 | N00 - COO | 303
1153903 | N00 - COO | 70
1153904 | N00 - COO | 70
1153905 | N00 - COO | 303
1154036 | N00 - COO | 70
1154037 | N00 - COO | 70
1154038 | N00 - COO | 303
1154151 | N00 - COO | 70
1154152 | N00 - COO | 70
1154153 | N00 - COO | 303
1154226 | N00 - COO | 70
1154227 | N00 - COO | 68
1154228 | N00 - COO | 303
1154365 | N00 - COO | 68
1154366 | N00 - COO | 64.75
1154367 | N00 - COO | 303
1154420 | N00 - COO | 64.75
1154421 | N00 - COO | 161.501
1154422 | N00 - COO | 303
1154508 | N00 - COO | 55.2485
1154509 | N00 - COO | 83.5015
1154510 | N00 - COO | 303
1154600 | N00 - COO | 83.5015
1154601 | N00 - COO | 67.5
1154602 | N00 - COO | 303
1154672 | N00 - COO | 70
1154673 | N00 - COO | 68
1154674 | N00 - COO | 303
1154864 | N00 - COO | 70
1154865 | N00 - COO | 70
1154866 | N00 - COO | 303
1154917 | N00 - COO | 67.5
1154918 | N00 - COO | 70
1154919 | N00 - COO | 303
1155170 | N00 - COO | 68
1155171 | N00 - COO | 70
1155172 | N00 - COO | 303
1155270 | N00 - COO | 70
1155271 | N00 - COO | 72
1155272 | N00 - COO | 303
1155349 | N00 - COO | 72
1155350 | N00 - COO | 70
1155351 | N00 - COO | 303
1155448 | N00 - COO | 70
1155449 | N00 - COO | 70
1155450 | N00 - COO | 303
1155545 | N00 - COO | 70
1155546 | N00 - COO | 70
1155547 | N00 - COO | 303
1155587 | N00 - COO | 70
1155588 | N00 - COO | 83.4785
1156878 | N00 - COO | 161.501
1156879 | N00 - COO | 55.2485
1156880 | N00 - COO | 303

# IfcMember: 200x50 mm nord (80)
In: N00 - COO
Type - PredefinedType: MEMBER
Type - Pset_MemberCommon - IsExternal: no; Reference: 200x50 mm nord
Type - Pset_QuantityTakeOff - Reference: 200x50 mm nord
Material: Aluminium
Pset_MemberCommon - IsExternal: yes
Name (Meneau rectangulaire:200x50 mm nord:...) | Span (cm)
872411 | 423
872412 | 425
872413 | 308
872414 | 423
872415 | 425
872416 | 308
872417 | 423
872418 | 425
872419 | 308
872420 | 423
872421 | 425
872422 | 308
872423 | 423
872424 | 425
872425 | 308
872426 | 423
872427 | 425
872428 | 308
872429 | 423
872430 | 425
872431 | 308
872432 | 423
872433 | 425
872434 | 308
872435 | 423
872436 | 425
872437 | 308
872438 | 423
872439 | 425
872440 | 308
872442 | 432.5
872443 | 310.5
872452 | 423
872453 | 425
872454 | 308
872543 | 425
872544 | 425
872545 | 425
872546 | 423
872547 | 423
872548 | 423
872549 | 423
872550 | 425
872551 | 425
872552 | 423
872553 | 423
872554 | 425
872555 | 425
872556 | 423
872557 | 423
872558 | 425
872559 | 425
872560 | 423
872561 | 423
872562 | 425
872563 | 423
872564 | 425
872637 | 423
872638 | 423
872639 | 423
872640 | 423
872641 | 423
872642 | 423
872643 | 423
872644 | 423
872645 | 423
872758 | 423
872759 | 423
872760 | 423
872761 | 423
872762 | 423
872763 | 423
872764 | 423
872765 | 423
872766 | 423
872767 | 423
872768 | 423
872769 | 423
872770 | 423
872771 | 423

# IfcMember: Epine nord (160x50 mm) (117)
In: N00 - COO
Type - PredefinedType: MEMBER
Type - Pset_MemberCommon - IsExternal: no; Reference: Epine nord (160x50 mm)
Type - Pset_QuantityTakeOff - Reference: Epine nord (160x50 mm)
Material: Aluminium
Pset_MemberCommon - IsExternal: yes
Name (Meneau rectangulaire:Epine nord (160x50 mm):...) | Span (cm)
1059834 | 32.5
1059835 | 30
1059836 | 30
1059837 | 32.5
1059838 | 30
1059839 | 30
1059840 | 30
1059841 | 190
1059842 | 190
1059843 | 190
1059844 | 190
1059845 | 190
1059846 | 23.5
1059897 | 30
1059898 | 30
1059899 | 30
1059900 | 30
1059901 | 30
1059902 | 30
1059903 | 30
1059904 | 30
1059905 | 23.5
1059906 | 30
1059907 | 30
1059908 | 30
1059909 | 30
1059910 | 30
1059911 | 30
1059912 | 30
1059913 | 30
1059914 | 30
1059915 | 190
1059916 | 190
1059917 | 190
1059918 | 190
1059919 | 190
1059920 | 190
1059921 | 190
1059922 | 190
1059923 | 190
1064696 | 32.5
1064697 | 30
1064698 | 30
1064699 | 30
1064700 | 30
1064701 | 30
1064703 | 32.5
1064704 | 30
1064705 | 30
1064706 | 30
1064707 | 30
1064708 | 30
1064709 | 30
1064710 | 190
1064711 | 190
1064712 | 190
1064713 | 190
1064714 | 190
1064715 | 190
1064716 | 190
1064717 | 190
1065095 | 30
1065096 | 30
1065098 | 30
1065099 | 30
1065101 | 190
1065102 | 190
1065474 | 30
1065475 | 30
1065476 | 190
1065530 | 30
1065532 | 29
1065534 | 190
1065600 | 29
1368689 | 32.5
1368690 | 30
1368691 | 30
1368692 | 32.5
1368693 | 30
1368694 | 30
1368695 | 30
1368696 | 190
1368697 | 190
1368698 | 190
1368699 | 190
1368700 | 190
1368701 | 27.5
1368720 | 30
1368721 | 30
1368722 | 30
1368723 | 30
1368724 | 30
1368725 | 30
1368726 | 30
1368727 | 30
1368728 | 30
1368729 | 30
1368730 | 30
1368731 | 30
1368732 | 30
1368733 | 30
1368734 | 30
1368735 | 30
1368736 | 30
1368737 | 30
1368738 | 190
1368739 | 190
1368740 | 190
1368741 | 190
1368742 | 190
1368743 | 190
1368744 | 190
1368745 | 190
1368746 | 190
1368908 | 30
1368909 | 27.5
1368910 | 190

# IfcMember: Epine nord (200x50 mm) (570)
In: N00 - COO
Type - PredefinedType: MEMBER
Type - Pset_MemberCommon - IsExternal: no; Reference: Epine nord (200x50 mm)
Type - Pset_QuantityTakeOff - Reference: Epine nord (200x50 mm)
Material: Aluminium
Name (Meneau rectangulaire:Epine nord (200x50 mm):...) | IsExternal | Span (cm)
668060 | yes | 31
668061 | yes | 28.5
668062 | yes | 28.5
668063 | yes | 28.5
668064 | yes | 28.5
668065 | yes | 28.5
668066 | yes | 28.5
668067 | yes | 28.5
668068 | yes | 28.5
668069 | yes | 28.5
668072 | yes | 31
668073 | yes | 28.5
668074 | yes | 28.5
668075 | yes | 28.5
668076 | yes | 28.5
668077 | yes | 28.5
668078 | yes | 28.5
668079 | yes | 28.5
668080 | yes | 28.5
668081 | yes | 28.5
668082 | yes | 22.5133
668087 | yes | 190
668088 | yes | 190
668089 | yes | 190
668090 | yes | 190
668091 | yes | 190
668092 | yes | 190
668093 | yes | 190
668094 | yes | 190
668095 | yes | 190
668096 | yes | 190
1012634 | yes | 190
1414216 | yes | 22.5133
1414264 | yes | 190
894808 |  | 120
894810 |  | 306
894811 |  | 306
942807 |  | 120
899807 | yes | 31
899808 | yes | 28.5
899809 | yes | 28.5
899810 | yes | 28.5
899811 | yes | 28.5
899812 | yes | 28.5
899813 | yes | 28.5
899814 | yes | 28.5
899815 | yes | 28.5
899816 | yes | 28.5
899817 | yes | 28.5
899818 | yes | 28.5
899819 | yes | 28.5
899820 | yes | 28.5
899821 | yes | 28.5
899822 | yes | 28.5
899823 | yes | 28.5
899824 | yes | 28.5
899825 | yes | 28.5
899826 | yes | 28.5
899827 | yes | 28.5
899828 | yes | 28.5
899829 | yes | 28.5
899830 | yes | 28.5
899831 | yes | 28.5
899832 | yes | 28.5
899833 | yes | 28.5
899834 | yes | 28.5
899835 | yes | 28.5
899836 | yes | 28.5
899837 | yes | 28.5
899838 | yes | 28.5
899839 | yes | 28.5
899840 | yes | 28.5
899841 | yes | 28.5
899842 | yes | 28.5
899843 | yes | 28.5
899844 | yes | 28.5
899845 | yes | 28.5
899846 | yes | 28.5
899847 | yes | 28.5
899848 | yes | 28.5
899849 | yes | 28.5
899850 | yes | 28.5
899851 | yes | 28.5
899852 | yes | 28.5
899853 | yes | 28.5
899854 | yes | 28.5
899855 | yes | 28.5
899856 | yes | 28.5
899857 | yes | 28.5
899858 | yes | 28.5
899859 | yes | 28.5
899860 | yes | 28.5
899861 | yes | 28.5
899862 | yes | 28.5
899863 | yes | 28.5
899864 | yes | 28.5
899865 | yes | 28.5
899866 | yes | 28.5
899867 | yes | 28.5
899868 | yes | 28.5
899869 | yes | 28.5
899870 | yes | 28.5
899871 | yes | 28.5
899872 | yes | 28.5
899873 | yes | 28.5
899874 | yes | 28.5
899875 | yes | 28.5
899876 | yes | 28.5
899877 | yes | 28.5
899878 | yes | 28.5
899879 | yes | 28.5
899880 | yes | 28.5
899881 | yes | 28.5
899882 | yes | 28.5
899883 | yes | 28.5
899884 | yes | 28.5
899885 | yes | 28.5
899886 | yes | 28.5
899887 | yes | 28.5
899888 | yes | 28.5
899889 | yes | 28.5
899890 | yes | 28.5
899891 | yes | 28.5
899892 | yes | 28.5
899893 | yes | 28.5
899894 | yes | 28.5
899895 | yes | 28.5
899896 | yes | 28.5
899897 | yes | 28.5
899898 | yes | 28.5
899899 | yes | 28.5
899900 | yes | 28.5
899901 | yes | 28.5
899902 | yes | 28.5
899903 | yes | 28.5
899904 | yes | 28.5
899905 | yes | 28.5
899906 | yes | 28.5
899907 | yes | 28.5
899908 | yes | 28.5
899909 | yes | 28.5
899910 | yes | 28.5
899911 | yes | 28.5
899912 | yes | 28.5
899965 | yes | 31
899966 | yes | 28.5
899967 | yes | 28.5
899968 | yes | 28.5
899969 | yes | 28.5
899970 | yes | 28.5
899971 | yes | 28.5
899972 | yes | 28.5
899973 | yes | 28.5
899974 | yes | 28.5
899975 | yes | 28.5
899976 | yes | 28.5
899977 | yes | 28.5
899978 | yes | 28.5
899979 | yes | 28.5
899980 | yes | 28.5
899981 | yes | 28.5
899982 | yes | 28.5
899983 | yes | 28.5
899984 | yes | 28.5
899985 | yes | 28.5
899986 | yes | 28.5
899987 | yes | 28.5
899988 | yes | 28.5
899989 | yes | 28.5
899990 | yes | 28.5
899991 | yes | 28.5
899992 | yes | 28.5
899993 | yes | 28.5
899994 | yes | 28.5
899995 | yes | 28.5
899996 | yes | 28.5
899997 | yes | 28.5
899998 | yes | 28.5
899999 | yes | 28.5
900000 | yes | 28.5
900001 | yes | 28.5
900002 | yes | 28.5
900003 | yes | 28.5
900004 | yes | 28.5
900005 | yes | 28.5
900006 | yes | 28.5
900007 | yes | 28.5
900008 | yes | 28.5
900009 | yes | 28.5
900010 | yes | 28.5
900011 | yes | 28.5
900012 | yes | 28.5
900013 | yes | 28.5
900014 | yes | 28.5
900015 | yes | 28.5
900016 | yes | 28.5
900017 | yes | 28.5
900018 | yes | 28.5
900019 | yes | 28.5
900020 | yes | 28.5
900021 | yes | 28.5
900022 | yes | 28.5
900023 | yes | 28.5
900024 | yes | 28.5
900025 | yes | 28.5
900026 | yes | 28.5
900027 | yes | 28.5
900028 | yes | 28.5
900029 | yes | 28.5
900030 | yes | 28.5
900031 | yes | 28.5
900032 | yes | 28.5
900033 | yes | 28.5
900034 | yes | 28.5
900035 | yes | 28.5
900036 | yes | 28.5
900037 | yes | 28.5
900038 | yes | 28.5
900039 | yes | 28.5
900040 | yes | 28.5
900041 | yes | 28.5
900042 | yes | 28.5
900043 | yes | 28.5
900044 | yes | 28.5
900045 | yes | 28.5
900046 | yes | 28.5
900047 | yes | 28.5
900048 | yes | 28.5
900049 | yes | 28.5
900050 | yes | 28.5
900051 | yes | 28.5
900052 | yes | 28.5
900053 | yes | 28.5
900054 | yes | 28.5
900055 | yes | 28.5
900056 | yes | 28.5
900057 | yes | 28.5
900058 | yes | 28.5
900059 | yes | 28.5
900060 | yes | 28.5
900061 | yes | 28.5
900062 | yes | 28.5
900063 | yes | 28.5
900064 | yes | 28.5
900065 | yes | 28.5
900066 | yes | 28.5
900067 | yes | 28.5
900068 | yes | 28.5
900069 | yes | 28.5
900070 | yes | 28.5
900071 | yes | 28.5
900126 | yes | 190
900127 | yes | 190
900128 | yes | 190
900129 | yes | 190
900130 | yes | 190
900131 | yes | 190
900132 | yes | 190
900133 | yes | 190
900134 | yes | 190
900135 | yes | 190
900136 | yes | 190
900137 | yes | 190
900138 | yes | 190
900139 | yes | 190
900140 | yes | 190
900141 | yes | 190
900142 | yes | 190
900143 | yes | 190
900144 | yes | 190
900145 | yes | 190
900146 | yes | 190
900147 | yes | 190
900148 | yes | 190
900149 | yes | 190
900150 | yes | 190
900151 | yes | 190
900152 | yes | 190
900153 | yes | 190
900154 | yes | 190
900155 | yes | 190
900156 | yes | 190
900157 | yes | 190
900158 | yes | 190
900159 | yes | 190
900160 | yes | 190
900161 | yes | 190
900162 | yes | 190
900163 | yes | 190
900164 | yes | 190
900165 | yes | 190
900166 | yes | 190
900167 | yes | 190
900168 | yes | 190
900169 | yes | 190
900170 | yes | 190
900171 | yes | 190
900172 | yes | 190
900173 | yes | 190
900174 | yes | 190
900175 | yes | 190
900176 | yes | 190
900177 | yes | 190
900178 | yes | 190
900179 | yes | 190
900180 | yes | 190
900181 | yes | 190
900182 | yes | 190
900183 | yes | 190
900184 | yes | 190
900185 | yes | 190
900186 | yes | 190
900187 | yes | 190
900188 | yes | 190
900189 | yes | 190
900190 | yes | 190
900191 | yes | 190
900192 | yes | 190
900193 | yes | 190
900194 | yes | 190
900195 | yes | 190
900196 | yes | 190
900197 | yes | 190
900198 | yes | 190
900199 | yes | 190
900200 | yes | 190
900201 | yes | 190
900202 | yes | 190
900203 | yes | 190
900204 | yes | 190
900205 | yes | 190
900206 | yes | 190
900207 | yes | 190
900208 | yes | 190
900209 | yes | 190
900210 | yes | 190
900211 | yes | 190
900212 | yes | 190
900213 | yes | 190
900214 | yes | 190
900215 | yes | 190
900216 | yes | 190
900217 | yes | 190
900218 | yes | 190
900219 | yes | 190
900220 | yes | 190
900221 | yes | 190
900222 | yes | 190
900223 | yes | 190
900224 | yes | 190
900225 | yes | 190
900226 | yes | 190
900227 | yes | 190
900228 | yes | 190
900229 | yes | 190
900230 | yes | 190
900231 | yes | 190
1012637 | yes | 190
1012638 | yes | 190
1063616 | yes | 25
1063730 | yes | 28.5
1063731 | yes | 28.5
1063732 | yes | 190
1144319 | yes | 28.5
1144320 | yes | 28.5
1144321 | yes | 28.5
1144322 | yes | 28.5
1144327 | yes | 28.5
1144328 | yes | 28.5
1144329 | yes | 28.5
1144330 | yes | 28.5
1144335 | yes | 190
1144336 | yes | 190
1144337 | yes | 190
1144338 | yes | 190
1144638 | yes | 28.5
1144639 | yes | 28.5
1144640 | yes | 28.5
1144641 | yes | 25
1144642 | yes | 190
1144643 | yes | 190
907113 | yes | 31
907114 | yes | 28.5
907115 | yes | 28.5
907116 | yes | 28.5
907117 | yes | 28.5
907118 | yes | 28.5
907119 | yes | 28.5
907120 | yes | 28.5
907121 | yes | 28.5
907122 | yes | 28.5
907123 | yes | 28.5
907124 | yes | 28.5
907125 | yes | 28.5
907136 | yes | 31
907137 | yes | 28.5
907138 | yes | 28.5
907139 | yes | 28.5
907140 | yes | 28.5
907141 | yes | 28.5
907142 | yes | 28.5
907143 | yes | 28.5
907144 | yes | 28.5
907145 | yes | 28.5
907146 | yes | 28.5
907147 | yes | 28.5
907148 | yes | 28.5
907162 | yes | 190
907163 | yes | 190
907164 | yes | 190
907165 | yes | 190
907166 | yes | 190
907167 | yes | 190
907168 | yes | 190
907169 | yes | 190
907170 | yes | 190
907171 | yes | 190
907172 | yes | 190
907173 | yes | 190
907174 | yes | 190
1012639 | yes | 190
1012640 | yes | 190
1059683 | yes | 28.5
1059745 | yes | 20
1144343 | yes | 20
1144344 | yes | 28.5
1144345 | yes | 190
907818 | yes | 31
907819 | yes | 28.5
907820 | yes | 28.5
907821 | yes | 31
907822 | yes | 28.5
907823 | yes | 28.5
907824 | yes | 28.5
907827 | yes | 190
907828 | yes | 190
907829 | yes | 190
1012641 | yes | 190
1012642 | yes | 190
1058719 | yes | 28.5
1058721 | yes | 190
1058789 | yes | 28.5
1058795 | yes | 28.5
1058796 | yes | 28.5
1058797 | yes | 190
1058855 | yes | 8.5
1144280 | yes | 8.5
1144281 | yes | 28.5
1144282 | yes | 190
942825 |  | 123
942826 |  | 306
942827 |  | 306
942828 |  | 123
1058893 | yes | 31
1058894 | yes | 28.5
1058895 | yes | 28.5
1058896 | yes | 31
1058897 | yes | 28.5
1058898 | yes | 28.5
1058899 | yes | 26
1058900 | yes | 190
1058901 | yes | 190
1058902 | yes | 190
1058903 | yes | 190
1058904 | yes | 190
1058915 | yes | 26
1060709 | yes | 31
1060710 | yes | 28.5
1060711 | yes | 28.5
1060712 | yes | 28.5
1060713 | yes | 28.5
1060714 | yes | 28.5
1060715 | yes | 28.5
1060744 | yes | 31
1060745 | yes | 28.5
1060746 | yes | 28.5
1060747 | yes | 28.5
1060748 | yes | 28.5
1060749 | yes | 28.5
1060750 | yes | 28.5
1060780 | yes | 190
1060781 | yes | 190
1060782 | yes | 190
1060783 | yes | 190
1060784 | yes | 190
1060785 | yes | 190
1060786 | yes | 190
1060787 | yes | 190
1060788 | yes | 190
1144251 | yes | 13
1144252 | yes | 13
1124369 |  | 180.221
1124370 |  | 180.221
1124371 |  | 313
1124372 |  | 313
1735606 | yes | 31
1735607 | yes | 28.5
1735608 | yes | 28.5
1735609 | yes | 28.5
1735610 | yes | 28.5
1735611 | yes | 28.5
1735616 | yes | 31
1735617 | yes | 28.5
1735618 | yes | 28.5
1735619 | yes | 28.5
1735620 | yes | 28.5
1735621 | yes | 28.5
1735622 | yes | 28.5
1735627 | yes | 190
1735628 | yes | 190
1735629 | yes | 190
1735630 | yes | 190
1735631 | yes | 190
1735632 | yes | 190
1735637 | yes | 190
1735818 | yes | 13.5
1735876 | yes | 190
1959306 | yes | 13.5
1959307 | yes | 28.5
1959308 | yes | 190
1735639 | yes | 190
1735717 | yes | 28.5
1735718 | yes | 28.5
1735719 | yes | 28.5
1735720 | yes | 28.5
1735721 | yes | 28.5
1735722 | yes | 28.5
1735723 | yes | 28.5
1735724 | yes | 28.5
1735725 | yes | 16.0899
1735730 | yes | 31
1735731 | yes | 28.5
1735732 | yes | 28.5
1735733 | yes | 28.5
1735734 | yes | 28.5
1735735 | yes | 28.5
1735736 | yes | 28.5
1735737 | yes | 28.5
1735738 | yes | 28.5
1735743 | yes | 190
1735744 | yes | 190
1735745 | yes | 190
1735746 | yes | 190
1735747 | yes | 190
1735748 | yes | 190
1735749 | yes | 190
1735750 | yes | 190
1735751 | yes | 190
1735817 | yes | 31
1735843 | yes | 190
1735851 | yes | 16.0899
2138070 | yes | 31
2138071 | yes | 28.5
2138072 | yes | 28.5
2138073 | yes | 28.5
2138074 | yes | 28.5
2138076 | yes | 31
2138077 | yes | 28.5
2138078 | yes | 28.5
2138079 | yes | 28.5
2138080 | yes | 28.5
2138081 | yes | 28
2138083 | yes | 190
2138084 | yes | 190
2138085 | yes | 190
2138086 | yes | 190
2138087 | yes | 190
2138089 | yes | 190
2138090 | yes | 28
2138091 | yes | 190

# IfcMember: Epine sud (400x50 mm) (519)
In: Toiture - Cuisine
Type - PredefinedType: MEMBER
Type - Pset_MemberCommon - IsExternal: no; Reference: Epine sud (400x50 mm)
Type - Pset_QuantityTakeOff - Reference: Epine sud (400x50 mm)
Material: Aluminium
Pset_MemberCommon - IsExternal: yes
Name (Meneau rectangulaire:Epine sud (400x50 mm):...) | Span (cm)
638623 | 73.25
638624 | 85
639268 | 65
639269 | 67.5
639362 | 65
639363 | 67.5
639412 | 65
639413 | 67.5
639464 | 65
639465 | 67.5
639520 | 65
639521 | 67.5
639572 | 65
639573 | 67.5
639805 | 65
639806 | 67.5
639943 | 65
639944 | 67.5
640149 | 82.5
640150 | 67.5
640275 | 392.5
640287 | 392.5
640297 | 392.5
640309 | 392.5
640321 | 392.5
640333 | 392.5
640345 | 392.5
640357 | 392.5
640369 | 392.5
640880 | 82.5
640881 | 65
640882 | 65
640883 | 65
640884 | 65
640885 | 65
640886 | 65
640887 | 65
640888 | 65
640889 | 65
640911 | 430.5
640912 | 430.5
640913 | 430.5
640914 | 430.5
640915 | 430.5
640916 | 430.5
640917 | 430.5
640918 | 430.5
640919 | 430.5
641629 | 65
641630 | 67.5
641631 | 65
641718 | 65
641719 | 67.5
641720 | 65
641769 | 65
641770 | 67.5
641771 | 65
641816 | 65
641817 | 67.5
641818 | 65
641901 | 65
641902 | 67.5
641903 | 65
641946 | 65
641947 | 67.5
641948 | 65
641987 | 65
641988 | 67.5
641989 | 65
642028 | 65
642029 | 67.5
642030 | 65
642062 | 65
642063 | 67.5
642064 | 65
642084 | 430.5
642086 | 392.5
642099 | 430.5
642101 | 392.5
642114 | 430.5
642116 | 392.5
642123 | 430.5
642125 | 392.5
642132 | 430.5
642134 | 392.5
642147 | 430.5
642149 | 392.5
642162 | 430.5
642164 | 392.5
642171 | 430.5
642173 | 392.5
642180 | 430.5
642182 | 392.5
643497 | 65
643498 | 67.5
643499 | 65
643593 | 65
643594 | 67.5
643595 | 65
643677 | 65
643678 | 67.5
643679 | 65
643729 | 65
643730 | 67.5
643731 | 65
643823 | 65
643824 | 67.5
643825 | 65
643873 | 65
643874 | 67.5
643875 | 65
643911 | 65
643912 | 67.5
643913 | 65
643945 | 430.5
643947 | 392.5
643961 | 430.5
643963 | 392.5
643976 | 430.5
643978 | 392.5
643990 | 430.5
643992 | 392.5
644000 | 430.5
644002 | 392.5
644009 | 430.5
644011 | 392.5
644015 | 430.5
644017 | 392.5
644285 | 65
644286 | 67.5
644287 | 65
644332 | 65
644333 | 67.5
644334 | 65
644379 | 65
644380 | 67.5
644381 | 65
644424 | 65
644425 | 67.5
644426 | 65
644471 | 65
644472 | 67.25
644473 | 64.75
644529 | 430.5
644531 | 392.5
644544 | 430.5
644546 | 392.5
644559 | 430.5
644561 | 392.5
644574 | 430.5
644576 | 392.5
644583 | 430.5
644585 | 392.5
644934 | 82.5
644935 | 85
644936 | 82.5
644998 | 65
644999 | 67.5
645000 | 65
645075 | 65
645076 | 67.5
645077 | 65
645127 | 65
645128 | 67.5
645129 | 65
645171 | 65
645172 | 67.5
645173 | 65
645199 | 65
645200 | 67.5
645201 | 65
645231 | 65
645232 | 67.5
645233 | 65
645291 | 65
645292 | 67.5
645293 | 65
645319 | 65
645320 | 67.5
645321 | 65
645347 | 65
645348 | 67.5
645349 | 65
645381 | 65
645382 | 67.5
645383 | 65
645429 | 65
645430 | 67.5
645431 | 65
645457 | 65
645458 | 67.5
645459 | 65
645507 | 65
645508 | 67.5
645509 | 65
645541 | 65
645542 | 67.5
645543 | 65
645575 | 65
645576 | 67.5
645577 | 65
645607 | 65
645608 | 67.5
645609 | 65
645645 | 65
645646 | 67.5
645647 | 65
645685 | 65
645686 | 67.5
645687 | 65
645729 | 65
645730 | 67.5
645731 | 65
645767 | 65
645768 | 67.5
645769 | 65
645831 | 65
645832 | 67.5
645833 | 65
645867 | 65
645868 | 67.5
645869 | 65
645899 | 65
645900 | 67.5
645901 | 65
645933 | 65
645934 | 67.5
645935 | 65
645969 | 65
645970 | 67.5
645971 | 65
645999 | 65
646000 | 67.5
646001 | 65
646045 | 65
646046 | 67.5
646047 | 65
646081 | 65
646082 | 67.5
646083 | 65
646117 | 65
646118 | 67.5
646119 | 65
646180 | 64.75
646181 | 75.75
646182 | 73.25
646208 | 430.5
646220 | 4388
646292 | 392.5
646294 | 430.5
646296 | 392.5
646298 | 433
646300 | 433
646302 | 433
646304 | 433
646306 | 433
646308 | 433
646310 | 433
646312 | 433
646314 | 433
646316 | 433
646318 | 433
646320 | 433
646322 | 433
646324 | 433
646326 | 433
646328 | 433
646330 | 433
646332 | 433
646334 | 433
646336 | 433
646338 | 433
646340 | 433
646342 | 433
646344 | 433
646346 | 433
646348 | 433
646350 | 433
646352 | 433
646354 | 433
646356 | 433
646358 | 433
2098394 | 44.25
2098395 | 80
2098398 | 65
2098399 | 67.5
2098402 | 65
2098403 | 67.5
2098406 | 65
2098407 | 67.5
2098410 | 65
2098411 | 67.5
2098414 | 377.951
2098415 | 377.951
2098416 | 377.951
2098417 | 377.951
2098425 | 77.5
2098426 | 65
2098427 | 65
2098428 | 65
2098429 | 65
2098430 | 430.6
2098431 | 430.6
2098432 | 430.6
2098433 | 430.6
2098437 | 65
2098438 | 67.5
2098439 | 65
2098443 | 65
2098444 | 67.5
2098445 | 65
2098449 | 65
2098450 | 67.5
2098451 | 65
2098455 | 65
2098456 | 67.5
2098457 | 65
2098461 | 65
2098462 | 67.5
2098463 | 65
2098467 | 65
2098468 | 67.5
2098469 | 65
2098473 | 65
2098474 | 67.5
2098475 | 65
2098479 | 65
2098480 | 67.5
2098481 | 65
2098485 | 65
2098486 | 67.5
2098487 | 65
2098488 | 430.6
2098489 | 377.951
2098490 | 430.6
2098491 | 377.951
2098492 | 430.6
2098493 | 377.951
2098494 | 430.6
2098495 | 377.951
2098496 | 430.6
2098497 | 377.951
2098498 | 430.6
2098499 | 377.951
2098500 | 430.6
2098501 | 377.951
2098502 | 430.6
2098503 | 377.951
2098504 | 430.6
2098505 | 377.951
2098509 | 65
2098510 | 67.5
2098511 | 65
2098515 | 65
2098516 | 67.5
2098517 | 65
2098521 | 65
2098522 | 67.5
2098523 | 65
2098527 | 65
2098528 | 67.5
2098529 | 65
2098533 | 65
2098534 | 67.5
2098535 | 65
2098539 | 65
2098540 | 67.5
2098541 | 65
2098545 | 65
2098546 | 67.5
2098547 | 65
2098548 | 430.6
2098549 | 377.951
2098550 | 430.6
2098551 | 377.951
2098552 | 430.6
2098553 | 377.951
2098554 | 430.6
2098555 | 377.951
2098556 | 430.6
2098557 | 377.951
2098558 | 430.6
2098559 | 377.951
2098560 | 430.6
2098561 | 377.951
2098565 | 65
2098566 | 67.5
2098567 | 65
2098571 | 65
2098572 | 67.5
2098573 | 65
2098577 | 65
2098578 | 67.5
2098579 | 65
2098583 | 65
2098584 | 67.5
2098585 | 65
2098589 | 65
2098590 | 67.25
2098591 | 64.75
2098592 | 430.6
2098593 | 377.951
2098594 | 430.6
2098595 | 377.951
2098596 | 430.6
2098597 | 377.951
2098598 | 430.6
2098599 | 377.951
2098600 | 430.6
2098601 | 377.951
2098605 | 77.5
2098606 | 67.5
2098607 | 65
2098611 | 65
2098612 | 67.5
2098613 | 65
2098617 | 65
2098618 | 67.5
2098619 | 65
2098623 | 65
2098624 | 67.5
2098625 | 65
2098629 | 65
2098630 | 67.5
2098631 | 65
2098635 | 65
2098636 | 67.5
2098637 | 65
2098641 | 65
2098642 | 67.5
2098643 | 65
2098647 | 65
2098648 | 67.5
2098649 | 65
2098653 | 65
2098654 | 67.5
2098655 | 65
2098659 | 65
2098660 | 67.5
2098661 | 65
2098665 | 65
2098666 | 67.5
2098667 | 65
2098671 | 65
2098672 | 67.5
2098673 | 65
2098677 | 65
2098678 | 67.5
2098679 | 65
2098683 | 65
2098684 | 67.5
2098685 | 65
2098689 | 65
2098690 | 67.5
2098691 | 65
2098695 | 65
2098696 | 67.5
2098697 | 65
2098701 | 65
2098702 | 67.5
2098703 | 65
2098707 | 65
2098708 | 67.5
2098709 | 65
2098713 | 65
2098714 | 67.5
2098715 | 65
2098719 | 65
2098720 | 67.5
2098721 | 65
2098725 | 65
2098726 | 67.5
2098727 | 65
2098731 | 65
2098732 | 67.5
2098733 | 65
2098737 | 65
2098738 | 67.5
2098739 | 65
2098743 | 65
2098744 | 67.5
2098745 | 65
2098749 | 65
2098750 | 67.5
2098751 | 65
2098755 | 64.75
2098756 | 46.75
2098757 | 44.25
2098758 | 3636.5
2098759 | 377.951
2098760 | 430.6
2098761 | 433.1
2098762 | 433.1
2098763 | 433.1
2098764 | 433.1
2098765 | 433.1
2098766 | 433.1
2098767 | 433.1
2098768 | 433.1
2098769 | 433.1
2098770 | 433.1
2098771 | 433.1
2098772 | 433.1
2098773 | 433.1
2098774 | 433.1
2098775 | 433.1
2098776 | 433.1
2098777 | 433.1
2098778 | 433.1
2098779 | 433.1
2098780 | 433.1
2098781 | 433.1
2098782 | 433.1
2098783 | 433.1
2098784 | 433.1
2098785 | 433.1
2098786 | 433.1
2098799 | 5
2098800 | 5

# IfcMember: Limon à la française:Limon à la française - 50 mm (12)
Type - PredefinedType: STRINGER
Pset_MemberCommon - IsExternal: no; Slope: 0 deg; Reference: Escalier assemblé
Pset_QuantityTakeOff - Reference: Escalier assemblé
Name (Escalier assemblé:Escalier:...) | In | Span (cm)
1886925 Stringer 1 | TR - TECHNIQUE RDC | 5
1886925 Stringer 2 | TR - TECHNIQUE RDC | 5
1886925 Stringer 3 | TR - TECHNIQUE RDC | 5
1886925 Stringer 4 | TR - TECHNIQUE RDC | 5
1886925 Stringer 5 | TR - TECHNIQUE RDC | 5
1886925 Stringer 6 | TR - TECHNIQUE RDC | 40
1886925 Stringer 7 | TR - TECHNIQUE RDC | 5
1886925 Stringer 8 | TR - TECHNIQUE RDC | 40
1955995 Stringer 1 | TR - TECHNIQUE R+1 | 5
1955995 Stringer 2 | TR - TECHNIQUE R+1 | 5
1955995 Stringer 3 | TR - TECHNIQUE R+1 | 40
1955995 Stringer 4 | TR - TECHNIQUE R+1 | 40

# IfcOpeningElement: Opening (655)
Name | In
Sol:02 - dalle béton 30cm + finition 1cm:42359:2 | Toiture - Cuisine | Pset_OpeningElementCommon - Reference: 02 - dalle béton 30cm + finition 1cm; sets with these values: 2
Sol:02 - dalle béton 30cm + finition 1cm:42359:3 | Toiture - Cuisine | Pset_OpeningElementCommon - Reference: 02 - dalle béton 30cm + finition 1cm; sets with these values: 2
2 x Mur de base:04 - Parement - ITE 18cm + vide 2cm:47509 | Toiture - Cuisine | Pset_QuantityTakeOff - Reference: 04 - Parement - ITE 18cm + vide 2cm; sets with these values: 2
2 x Mur de base:04 - Parement - ITE 18cm + vide 2cm:121995 | Toiture - Cuisine | Pset_QuantityTakeOff - Reference: 04 - Parement - ITE 18cm + vide 2cm; sets with these values: 2
Mur de base:04 - Structure - béton - 20cm:137000 | N00 - COO | Pset_QuantityTakeOff - Reference: 04 - Structure - béton - 20cm; sets with these values: 2
Mur de base:04 - Structure - béton - 20cm:160354:1 | N00 - COO | Pset_QuantityTakeOff - Reference: 04 - Structure - béton - 20cm; sets with these values: 2
Mur de base:04 - Structure - béton - 20cm:160354 | N00 - COO | Pset_QuantityTakeOff - Reference: 04 - Structure - béton - 20cm; sets with these values: 2
2 x Mur de base:04 - Structure - béton - 20cm:4570 | N00 - COO | Pset_QuantityTakeOff - Reference: 04 - Structure - béton - 20cm; sets with these values: 2
3 x Mur de base:04 - Structure - Béton - 40:180710 | N00 - COO | Pset_QuantityTakeOff - Reference: 04 - Structure - Béton - 40; sets with these values: 2
Mur de base:04 - Structure - Béton - 40:181295 | N00 - COO | Pset_QuantityTakeOff - Reference: 04 - Structure - Béton - 40; sets with these values: 2
2 x Mur de base:04 - Structure - béton - 20cm:182010 | N00 - COO | Pset_QuantityTakeOff - Reference: 04 - Structure - béton - 20cm; sets with these values: 2
2 x Mur de base:04 - Structure - béton - 20cm:182462 | N00 - COO | Pset_QuantityTakeOff - Reference: 04 - Structure - béton - 20cm; sets with these values: 2
2 x Mur de base:04 - Structure - béton - 20cm:183570 | N00 - COO | Pset_QuantityTakeOff - Reference: 04 - Structure - béton - 20cm; sets with these values: 2
Mur de base:04 - Structure - béton - 20cm:183694 | N00 - COO | Pset_QuantityTakeOff - Reference: 04 - Structure - béton - 20cm; sets with these values: 2
Mur de base:04 - Structure - béton - 20cm:193135:1 | Vide Sanitaire | Pset_QuantityTakeOff - Reference: 04 - Structure - béton - 20cm; sets with these values: 2
Mur de base:04 - Parement - ITE 18 - isolation enterrée:195049 | Vide Sanitaire | Pset_QuantityTakeOff - Reference: 04 - Parement - ITE 18 - isolation enterrée; sets with these values: 2
3 x Mur de base:04 - Parement - ITE 18 - isolation enterrée:195860 | Vide Sanitaire | Pset_QuantityTakeOff - Reference: 04 - Parement - ITE 18 - isolation enterrée; sets with these values: 2
Mur de base:04 - Parement - ITE 18 - isolation enterrée:196580:1 | Vide Sanitaire | Pset_QuantityTakeOff - Reference: 04 - Parement - ITE 18 - isolation enterrée; sets with these values: 2
Mur de base:04 - Structure - béton - 20cm:204960 | TR - N02 - ARCH | Pset_QuantityTakeOff - Reference: 04 - Structure - béton - 20cm; sets with these values: 2
Mur de base:04 - Structure - béton - 20cm:206313 | Toiture - Cuisine | Pset_QuantityTakeOff - Reference: 04 - Structure - béton - 20cm; sets with these values: 2
Toit de base:03 - Dalle 30 cm + isolant:206667:1 | TR - N03 - ARCH | Pset_OpeningElementCommon - Reference: 03 - Dalle 30 cm + isolant; sets with these values: 2
Toit de base:03 - Dalle 30 cm + isolant:206667:2 | TR - N03 - ARCH | Pset_OpeningElementCommon - Reference: 03 - Dalle 30 cm + isolant; sets with these values: 2
Toit de base:03 - Dalle 30 cm + isolant:206667:3 | TR - N03 - ARCH | Pset_OpeningElementCommon - Reference: 03 - Dalle 30 cm + isolant; sets with these values: 2
8 x Mur de base:04 - Parement - ITE 18cm + vide 2cm:237608 | N00 - COO | Pset_QuantityTakeOff - Reference: 04 - Parement - ITE 18cm + vide 2cm; sets with these values: 2
Toit de base:03 - Dalle isolant:242657:1 | N00 - COO | Pset_OpeningElementCommon - Reference: 03 - Dalle isolant; sets with these values: 2
Toit de base:03 - Dalle isolant:242657:2 | N00 - COO | Pset_OpeningElementCommon - Reference: 03 - Dalle isolant; sets with these values: 2
Toit de base:03 - Dalle isolant:242657:3 | N00 - COO | Pset_OpeningElementCommon - Reference: 03 - Dalle isolant; sets with these values: 2
Toit de base:03 - gravillons:249391:1 | Toiture - Cuisine | Pset_OpeningElementCommon - Reference: 03 - gravillons; sets with these values: 2
Mur de base:06 - cloisons - Ba13 10cm:365388 | N00 - COO | Pset_QuantityTakeOff - Reference: 06 - cloisons - Ba13 10cm; sets with these values: 2
Mur de base:06 - cloisons - Ba13 10cm:405438 | N00 - COO | Pset_QuantityTakeOff - Reference: 06 - cloisons - Ba13 10cm; sets with these values: 2
Mur de base:06 - cloisons - Ba13 10cm:406469 | N00 - COO | Pset_QuantityTakeOff - Reference: 06 - cloisons - Ba13 10cm; sets with these values: 2
Mur de base:06 - cloisons - Ba13 10cm:4571 | N00 - COO | Pset_QuantityTakeOff - Reference: 06 - cloisons - Ba13 10cm; sets with these values: 2
Mur de base:06 - cloisons - agglos10 + enduit:436488 | N00 - COO | Pset_QuantityTakeOff - Reference: 06 - cloisons - agglos10 + enduit; sets with these values: 2
Mur de base:06 - cloisons - Carreau de terre cuite (10cm):454366 | N00 - COO | Pset_QuantityTakeOff - Reference: 06 - cloisons - Carreau de terre cuite (10cm); sets with these values: 2
Mur de base:06 - cloisons - agglos10 + faïence 12cm:460224:1 | N00 - COO | Pset_QuantityTakeOff - Reference: 06 - cloisons - agglos10 + faïence 12cm; sets with these values: 2
Mur de base:06 - cloisons - agglos10 + faïence 12cm:460690 | N00 - COO | Pset_QuantityTakeOff - Reference: 06 - cloisons - agglos10 + faïence 12cm; sets with these values: 2
Mur de base:04 - Structure - béton - 20cm:462613 | N00 - COO | Pset_QuantityTakeOff - Reference: 04 - Structure - béton - 20cm; sets with these values: 2
Mur de base:04 - Structure - béton - 20cm:462616 | N00 - COO | Pset_QuantityTakeOff - Reference: 04 - Structure - béton - 20cm; sets with these values: 2
Mur de base:04 - Parement - isolant 14 cm + BA13:555544 | Toiture - Cuisine | Pset_QuantityTakeOff - Reference: 04 - Parement - isolant 14 cm + BA13; sets with these values: 2
Mur de base:04 - Parement - ITE 18cm + vide 2cm:576914 | TR - N02 - ARCH | Pset_QuantityTakeOff - Reference: 04 - Parement - ITE 18cm + vide 2cm; sets with these values: 2
8 x Mur de base:04 - Parement - ITE 18cm + vide 2cm:577104 | N00 - COO | Pset_QuantityTakeOff - Reference: 04 - Parement - ITE 18cm + vide 2cm; sets with these values: 2
Mur de base:04 - Parement - ITE 18cm + vide 2cm:577486 | Toiture - Cuisine | Pset_QuantityTakeOff - Reference: 04 - Parement - ITE 18cm + vide 2cm; sets with these values: 2
3 x Mur de base:04 - Parement - ITE 18cm + vide 2cm:578381 | N00 - COO | Pset_QuantityTakeOff - Reference: 04 - Parement - ITE 18cm + vide 2cm; sets with these values: 2
Mur de base:04 - Parement - ITE 18cm + vide 2cm:579143 | TR - N02 - ARCH | Pset_QuantityTakeOff - Reference: 04 - Parement - ITE 18cm + vide 2cm; sets with these values: 2
Mur de base:04 - Parement - ITE 18cm + vide 2cm:579291 | Toiture - Cuisine | Pset_QuantityTakeOff - Reference: 04 - Parement - ITE 18cm + vide 2cm; sets with these values: 2
6 x Mur de base:04 - Parement - ITE 18cm + vide 2cm:581239 | N00 - COO | Pset_QuantityTakeOff - Reference: 04 - Parement - ITE 18cm + vide 2cm; sets with these values: 2
4 x Mur de base:04 - Parement - ITE 18cm + vide 2cm:584873 | N00 - COO | Pset_QuantityTakeOff - Reference: 04 - Parement - ITE 18cm + vide 2cm; sets with these values: 2
Mur de base:04 - Structure - béton - 20cm:659688:1 | N00 - COO | Pset_QuantityTakeOff - Reference: 04 - Structure - béton - 20cm; sets with these values: 2
10 x Mur de base:04 - Structure - béton - 20cm:659688 | N00 - COO | Pset_QuantityTakeOff - Reference: 04 - Structure - béton - 20cm; sets with these values: 2
3 x Mur de base:04 - Parement - ITE 18cm + vide 2cm:666686 | N00 - COO | Pset_QuantityTakeOff - Reference: 04 - Parement - ITE 18cm + vide 2cm; sets with these values: 2
2 x Mur de base:04 - Structure - béton - 20cm:677143 | Toiture - Cuisine | Pset_QuantityTakeOff - Reference: 04 - Structure - béton - 20cm; sets with these values: 2
2 x Mur de base:04 - Structure - béton - 20cm:677363 | Toiture - Cuisine | Pset_QuantityTakeOff - Reference: 04 - Structure - béton - 20cm; sets with these values: 2
4 x Mur de base:04 - Structure - béton - 20cm:4570 | Toiture - Cuisine | Pset_QuantityTakeOff - Reference: 04 - Structure - béton - 20cm; sets with these values: 2
Mur de base:04 - Structure - béton - 20cm:685971 | Toiture - Cuisine | Pset_QuantityTakeOff - Reference: 04 - Structure - béton - 20cm; sets with these values: 2
Toit de base:03 - gravillons:689882:1 | Toiture - Cuisine | Pset_OpeningElementCommon - Reference: 03 - gravillons; sets with these values: 2
Mur de base:04 - Structure - béton - 20cm:694218 | N00 - COO | Pset_QuantityTakeOff - Reference: 04 - Structure - béton - 20cm; sets with these values: 2
3 x Mur de base:06 - cloisons - Ba13 10cm:704262 | N00 - COO | Pset_QuantityTakeOff - Reference: 06 - cloisons - Ba13 10cm; sets with these values: 2
Mur de base:06 - cloisons - Ba13 10cm:704619 | N00 - COO | Pset_QuantityTakeOff - Reference: 06 - cloisons - Ba13 10cm; sets with these values: 2
Mur de base:04 - Structure - béton - 20cm:758030 | N00 - COO | Pset_QuantityTakeOff - Reference: 04 - Structure - béton - 20cm; sets with these values: 2
Mur de base:04 - Structure - béton - 20cm:766102:1 | Toiture - Cuisine | Pset_QuantityTakeOff - Reference: 04 - Structure - béton - 20cm; sets with these values: 2
Mur de base:04 - Parement - ITE 18cm + vide 2cm:767628 | Toiture - Cuisine | Pset_QuantityTakeOff - Reference: 04 - Parement - ITE 18cm + vide 2cm; sets with these values: 2
Mur de base:04 - Parement - isolant 20 cm + BA13 2:770760:1 | Toiture - Cuisine | Pset_QuantityTakeOff - Reference: 04 - Parement - isolant 20 cm + BA13 2; sets with these values: 2
Mur de base:06 - cloisons - Ba13 10cm:777906 | N00 - COO | Pset_QuantityTakeOff - Reference: 06 - cloisons - Ba13 10cm; sets with these values: 2
Mur de base:04 - Structure - béton - 20cm:781099:1 | Toiture - Cuisine | Pset_QuantityTakeOff - Reference: 04 - Structure - béton - 20cm; sets with these values: 2
Mur de base:04 - Structure - béton - 20cm:782258 | Toiture - Cuisine | Pset_QuantityTakeOff - Reference: 04 - Structure - béton - 20cm; sets with these values: 2
9 x Mur de base:04 - Parement - ITE 18cm + vide 2cm:786185 | N00 - COO | Pset_QuantityTakeOff - Reference: 04 - Parement - ITE 18cm + vide 2cm; sets with these values: 2
Mur de base:04 - Structure - béton - 20cm:788238 | N00 - COO | Pset_QuantityTakeOff - Reference: 04 - Structure - béton - 20cm; sets with these values: 2
2 x Mur de base:04 - Structure - béton - 20cm:791228 | Toiture - Cuisine | Pset_QuantityTakeOff - Reference: 04 - Structure - béton - 20cm; sets with these values: 2
3 x Mur de base:04 - Structure - béton - 20cm:791982 | N00 - COO | Pset_QuantityTakeOff - Reference: 04 - Structure - béton - 20cm; sets with these values: 2
2 x Mur de base:04 - Parement - isolant 14 cm + BA13:792276 | N00 - COO | Pset_QuantityTakeOff - Reference: 04 - Parement - isolant 14 cm + BA13; sets with these values: 2
Mur de base:04 - Structure - béton - 20cm:794560 | N00 - COO | Pset_QuantityTakeOff - Reference: 04 - Structure - béton - 20cm; sets with these values: 2
10 x Mur de base:04 - Structure - béton - 20cm:797762 | N00 - COO | Pset_QuantityTakeOff - Reference: 04 - Structure - béton - 20cm; sets with these values: 2
6 x Mur de base:04 - Parement - ITE 18cm + vide 2cm:798291 | N00 - COO | Pset_QuantityTakeOff - Reference: 04 - Parement - ITE 18cm + vide 2cm; sets with these values: 2
9 x Mur de base:04 - Structure - béton - 20cm:800234 | N00 - COO | Pset_QuantityTakeOff - Reference: 04 - Structure - béton - 20cm; sets with these values: 2
Mur de base:04 - Parement - ITE 18cm + vide 2cm:803412 | Toiture - Cuisine | Pset_QuantityTakeOff - Reference: 04 - Parement - ITE 18cm + vide 2cm; sets with these values: 2
Mur de base:04 - Parement - ITE 18cm + vide 2cm:806668 | Toiture - Cuisine | Pset_QuantityTakeOff - Reference: 04 - Parement - ITE 18cm + vide 2cm; sets with these values: 2
Mur de base:04 - Structure - béton - 25cm:826648:1 | Toiture - Cuisine | Pset_QuantityTakeOff - Reference: 04 - Structure - béton - 25cm; sets with these values: 2
Mur de base:04 - Structure - béton - 25cm:826648 | Toiture - Cuisine | Pset_QuantityTakeOff - Reference: 04 - Structure - béton - 25cm; sets with these values: 2
Mur de base:06 - cloisons - Ba13 10cm:839212 | N00 - COO | Pset_QuantityTakeOff - Reference: 06 - cloisons - Ba13 10cm; sets with these values: 2
Mur de base:04 - Parement - ITI 14cm:850878 | N00 - COO | Pset_QuantityTakeOff - Reference: 04 - Parement - ITI 14cm; sets with these values: 2
Mur de base:04 - Structure - béton - 20cm:852375 | Vide Sanitaire | Pset_QuantityTakeOff - Reference: 04 - Structure - béton - 20cm; sets with these values: 2
Mur de base:04 - Structure - Béton - 40:944175 | N00 - COO | Pset_QuantityTakeOff - Reference: 04 - Structure - Béton - 40; sets with these values: 2
2 x Mur de base:04 - Parement - isolant 14 cm + BA13:1012688 | N00 - COO | Pset_QuantityTakeOff - Reference: 04 - Parement - isolant 14 cm + BA13; sets with these values: 2
4 x Mur de base:04 - Parement - isolant 14 cm + BA13:1012694 | N00 - COO | Pset_QuantityTakeOff - Reference: 04 - Parement - isolant 14 cm + BA13; sets with these values: 2
4 x Mur de base:04 - Parement - isolant 14 cm + BA13:1012699 | N00 - COO | Pset_QuantityTakeOff - Reference: 04 - Parement - isolant 14 cm + BA13; sets with these values: 2
5 x Mur de base:04 - Parement - ITE 18cm + vide 2cm:1012875 | N00 - COO | Pset_QuantityTakeOff - Reference: 04 - Parement - ITE 18cm + vide 2cm; sets with these values: 2
Mur de base:06 - habillage Ba13 collée 2cm:1035618:1 | N00 - COO | Pset_QuantityTakeOff - Reference: 06 - habillage Ba13 collée 2cm; sets with these values: 2
Mur de base:06 - habillage Ba13 collée 2cm:1035618:2 | N00 - COO | Pset_QuantityTakeOff - Reference: 06 - habillage Ba13 collée 2cm; sets with these values: 2
Mur de base:06 - habillage Ba13 collée 2cm:1035618:3 | N00 - COO | Pset_QuantityTakeOff - Reference: 06 - habillage Ba13 collée 2cm; sets with these values: 2
Mur de base:06 - habillage Ba13 collée 2cm:1035618:4 | N00 - COO | Pset_QuantityTakeOff - Reference: 06 - habillage Ba13 collée 2cm; sets with these values: 2
Mur de base:04 - Structure - béton - 20cm:1063217:1 | N00 - COO | Pset_QuantityTakeOff - Reference: 04 - Structure - béton - 20cm; sets with these values: 2
Mur de base:06 - habillage bois collée 2cm perforé:1120562 | N00 - COO | Pset_QuantityTakeOff - Reference: 06 - habillage bois collée 2cm perforé; sets with these values: 2
Mur de base:06 - habillage bois collée 2cm perforé:1120744 | N00 - COO | Pset_QuantityTakeOff - Reference: 06 - habillage bois collée 2cm perforé; sets with these values: 2
Mur de base:06 - habillage bois collée 2cm perforé:1121184 | N00 - COO | Pset_QuantityTakeOff - Reference: 06 - habillage bois collée 2cm perforé; sets with these values: 2
Mur de base:06 - cloisons - Ba13 10cm:1218587 | N00 - COO | Pset_QuantityTakeOff - Reference: 06 - cloisons - Ba13 10cm; sets with these values: 2
Mur de base:04 - Structure - béton - 20cm:1237182 | N00 - COO | Pset_QuantityTakeOff - Reference: 04 - Structure - béton - 20cm; sets with these values: 2
2 x Mur de base:04 - Structure - béton - 20cm:1240811 | N00 - COO | Pset_QuantityTakeOff - Reference: 04 - Structure - béton - 20cm; sets with these values: 2
Mur de base:04 - Parement - isolant 14 cm + BA13:1339487:1 | N00 - COO | Pset_QuantityTakeOff - Reference: 04 - Parement - isolant 14 cm + BA13; sets with these values: 2
Mur de base:04 - Parement - CP acoustique 6cm:1351180 | TR - N02 - ARCH | Pset_QuantityTakeOff - Reference: 04 - Parement - CP acoustique 6cm; sets with these values: 2
Mur de base:06 - habillage bois collée 2cm:1491663 | TR - N02 - ARCH | Pset_QuantityTakeOff - Reference: 06 - habillage bois collée 2cm; sets with these values: 2
Mur de base:06 - habillage bois collée 2cm:1491673 | N00 - COO | Pset_QuantityTakeOff - Reference: 06 - habillage bois collée 2cm; sets with these values: 2
Mur de base:06 - cimaise R+2:1494006:1 | TR - N02 - ARCH | Pset_QuantityTakeOff - Reference: 06 - cimaise R+2; sets with these values: 2
Mur de base:06 - cimaise R+2:1494006:2 | TR - N02 - ARCH | Pset_QuantityTakeOff - Reference: 06 - cimaise R+2; sets with these values: 2
Mur de base:06 - cimaise R+2:1494534:1 | TR - N02 - ARCH | Pset_QuantityTakeOff - Reference: 06 - cimaise R+2; sets with these values: 2
Mur de base:06 - cimaise R+2:1494949:1 | Toiture - Cuisine | Pset_QuantityTakeOff - Reference: 06 - cimaise R+2; sets with these values: 2
Mur de base:06 - cimaise R+2:1495448:1 | Toiture - Cuisine | Pset_QuantityTakeOff - Reference: 06 - cimaise R+2; sets with these values: 2
Mur de base:06 - cimaise R+2:1495448:2 | Toiture - Cuisine | Pset_QuantityTakeOff - Reference: 06 - cimaise R+2; sets with these values: 2
Mur de base:06 - cimaise R+2:1495448:3 | Toiture - Cuisine | Pset_QuantityTakeOff - Reference: 06 - cimaise R+2; sets with these values: 2
Mur de base:06 - cimaise R+2:1495681:1 | Toiture - Cuisine | Pset_QuantityTakeOff - Reference: 06 - cimaise R+2; sets with these values: 2
Mur de base:06 - cimaise R+2:1495681:2 | Toiture - Cuisine | Pset_QuantityTakeOff - Reference: 06 - cimaise R+2; sets with these values: 2
Mur de base:06 - cimaise R+2:1495681:3 | Toiture - Cuisine | Pset_QuantityTakeOff - Reference: 06 - cimaise R+2; sets with these values: 2
Mur de base:06 - cimaise R+2:1495681:4 | Toiture - Cuisine | Pset_QuantityTakeOff - Reference: 06 - cimaise R+2; sets with these values: 2
Mur de base:06 - cimaise R+2:1495681:5 | Toiture - Cuisine | Pset_QuantityTakeOff - Reference: 06 - cimaise R+2; sets with these values: 2
Toit de base:03 - Dalle bac acier:1606061:1 | N00 - COO | Pset_OpeningElementCommon - Reference: 03 - Dalle bac acier; sets with these values: 2
Toit de base:03 - Dalle bac acier:1606061:2 | N00 - COO | Pset_OpeningElementCommon - Reference: 03 - Dalle bac acier; sets with these values: 2
Toit de base:03 - Dalle bac acier:1606061:3 | N00 - COO | Pset_OpeningElementCommon - Reference: 03 - Dalle bac acier; sets with these values: 2
Mur de base:04 - Structure - Poutre bois -:1671641:1 | Toiture - Cuisine | Pset_QuantityTakeOff - Reference: 04 - Structure - Poutre bois -; sets with these values: 2; Group: Groupe de modèles:Retours BA 13 SELF / VERRIERE 2:1671562
5 x Mur de base:04 - Parement - faïence 1cm:1757002 | N00 - COO | Pset_QuantityTakeOff - Reference: 04 - Parement - faïence 1cm; sets with these values: 2
2 x Mur de base:04 - Parement - faïence 1cm:1757131 | N00 - COO | Pset_QuantityTakeOff - Reference: 04 - Parement - faïence 1cm; sets with these values: 2
Mur de base:04 - Parement - faïence 1cm:1757331 | N00 - COO | Pset_QuantityTakeOff - Reference: 04 - Parement - faïence 1cm; sets with these values: 2
Mur de base:04 - Parement - faïence 1cm:1757392 | N00 - COO | Pset_QuantityTakeOff - Reference: 04 - Parement - faïence 1cm; sets with these values: 2
Mur de base:04 - Parement - faïence 1cm:1757508 | N00 - COO | Pset_QuantityTakeOff - Reference: 04 - Parement - faïence 1cm; sets with these values: 2
2 x Mur de base:04 - Parement - faïence 1cm:1757708 | N00 - COO | Pset_QuantityTakeOff - Reference: 04 - Parement - faïence 1cm; sets with these values: 2
Mur de base:06 - habillage bois collée 2cm:1786937 | N00 - COO | Pset_QuantityTakeOff - Reference: 06 - habillage bois collée 2cm; sets with these values: 2
Mur de base:04 - Structure - béton - 20cm:1856901 | N00 - COO | Pset_QuantityTakeOff - Reference: 04 - Structure - béton - 20cm; sets with these values: 2
Mur de base:04 - Structure - béton - 20cm:1997004 | N00 - COO | Pset_QuantityTakeOff - Reference: 04 - Structure - béton - 20cm; sets with these values: 2
2 x Mur de base:04 - retour isolation acrotère - ITE 16cm:4805 | N00 - COO | Pset_QuantityTakeOff - Reference: 04 - retour isolation acrotère - ITE 16cm; sets with these values: 2
Ouvrant vitré:Ouvrant vitré (70cm):1130586:1 | Toiture - Cuisine
Ouvrant vitré:Ouvrant POMPIERS Facade nord (140cm):1130587:1 | Toiture - Cuisine
Ouvrant vitré:Ouvrant vitré (70cm):1130588:1 | Toiture - Cuisine
Ouvrant vitré:Ouvrant vitré (70cm):1130694:1 | Toiture - Cuisine
Ouvrant vitré:Ouvrant vitré (70cm):1130695:1 | Toiture - Cuisine
Ouvrant vitré:Ouvrant vitré (70cm):1130696:1 | Toiture - Cuisine
Ouvrant vitré:Ouvrant vitré (70cm):1130811:1 | Toiture - Cuisine
Ouvrant vitré:Ouvrant POMPIERS Facade nord (140cm):1130879:1 | Toiture - Cuisine
Ouvrant vitré:Ouvrant vitré (70cm):1130935:1 | Toiture - Cuisine
Ouvrant vitré:Ouvrant vitré (70cm):1131007:1 | Toiture - Cuisine
Ouvrant vitré:Ouvrant vitré (70cm):1131068:1 | Toiture - Cuisine
Ouvrant vitré:Ouvrant vitré (70cm):1131340:1 | Toiture - Cuisine
Ouvrant vitré:Ouvrant vitré (70cm):1131341:1 | Toiture - Cuisine
Ouvrant vitré:Ouvrant vitré (70cm):1131430:1 | Toiture - Cuisine
Ouvrant vitré:Ouvrant vitré (70cm):1131495:1 | Toiture - Cuisine
Ouvrant vitré:Ouvrant vitré (70cm):1133891:1 | Toiture - Cuisine
Ouvrant vitré:Ouvrant vitré (70cm):1134050:1 | Toiture - Cuisine
Ouvrant vitré:Ouvrant vitré (70cm):1134112:1 | Toiture - Cuisine
Ouvrant vitré:Ouvrant vitré (70cm):1134168:1 | Toiture - Cuisine
Ouvrant vitré:Ouvrant vitré (70cm):1134221:1 | Toiture - Cuisine
Ouvrant vitré:Ouvrant vitré (70cm):1134287:1 | Toiture - Cuisine
Ouvrant vitré:Ouvrant vitré (70cm):1134288:1 | Toiture - Cuisine
Ouvrant vitré:Ouvrant vitré (70cm):1134289:1 | Toiture - Cuisine
Ouvrant vitré:Ouvrant vitré (70cm):1134290:1 | Toiture - Cuisine
Ouvrant vitré:Ouvrant vitré (70cm):1134291:1 | Toiture - Cuisine
Ouvrant vitré:Ouvrant vitré (70cm):1134436:1 | Toiture - Cuisine
Int. Simple:PV (0.93m x 3.00m):398060:1 | N00 - COO
Int. Simple:PV (0.93m x 3.00m):398174:1 | N00 - COO
Int. Simple:PV (0.93m x 3.00m):398215:1 | N00 - COO
Int. Simple:PV (0.93m x 3.00m):398262:1 | N00 - COO
Int. Double:PP Placard (1.26m x 2.04m):403946:1 | N00 - COO
Int. Double:PP Placard (1.05m x 3.00m):404158:1 | N00 - COO
Int. Simple:PP Placard (0.55m x 3.00m):404236:1 | N00 - COO
châssis intérieur vitré:châssis intérieur vitré (h=306):398419:1 | N00 - COO
Int. Simple:PV (0.93m x 3.00m):436159:1 | N00 - COO
châssis intérieur vitré:châssis intérieur vitré (h=306):1997249:1 | N00 - COO
Int. Double:PP (1.90m x 3.00m):164788:1 | N00 - COO
Int. Double:PP (1.90m x 3.00m):164671:1 | N00 - COO
Int. Simple:PV (0.93m x 3.00m):338585:1 | N00 - COO
Int. Simple:PV (0.93m x 3.00m):338610:1 | N00 - COO
Int. Simple:PP (0.93m x 3.06m):363961:1 | N00 - COO
Int. Double:PP Placard (1.10m x 2.50m):404341:1 | N00 - COO
Int. Simple:PP Placard (0.80m x 2.50m):404410:1 | N00 - COO
Int. Simple:PV (0.93m x 3.00m):484281:1 | N00 - COO
Int. Simple:PP simple (0.93m x 2.50m):1891646:1 | N00 - COO
châssis intérieur vitré:châssis intérieur vitré (h=306):366086:1 | N00 - COO
Int. Double:PV (1.90m x 3.00m):393510:1 | N00 - COO
châssis intérieur vitré:châssis intérieur vitré (h=306):393830:1 | N00 - COO
Int. Double:PV (1.90m x 3.00m):394304:1 | N00 - COO
Int. Simple:PV (0.93m x 3.00m):394326:1 | N00 - COO
châssis intérieur vitré:châssis intérieur vitré (h=306):375079:1 | N00 - COO
Mur de base:04 - Structure - béton - 20cm:182462 | N00 - COO
Int. Tierce:PP (1.44m x 2.04m):452891:1 | N00 - COO
Int. Simple:PP simple (0.93m x 2.50m):452936:1 | N00 - COO
Int. Simple:PP simple (0.93m x 2.50m):452957:1 | N00 - COO
Int. Simple:PP simple (0.93m x 2.50m):452981:1 | N00 - COO
Int. Double:PP Placard (1.88m x 2.04m):790799:1 | N00 - COO
Int. Simple:PP (0.93m x 2.50m):461258:1 | N00 - COO
Int. Simple:PP simple (0.93m x 2.50m):461230:1 | N00 - COO
Int. Simple:PP (0.93m x 2.50m):461457:1 | N00 - COO
Int. Simple:PP (0.93m x 2.50m):1339257:1 | N00 - COO
châssis intérieur vitré:châssis intérieur vitré self (h=2.22) 2:2074709:1 | N00 - COO
Int. Simple:PP simple (0.93m x 2.50m):461367:1 | N00 - COO
Int. Simple:PP simple (0.93m x 2.50m):461384:1 | N00 - COO
Int. Simple:PP simple (0.93m x 2.50m):461498:1 | N00 - COO
Int. Simple:PP simple (0.93m x 2.50m):446761:1 | N00 - COO
Int. Simple:PP simple (0.93m x 2.50m):461411:1 | N00 - COO
Int. Simple:PP simple (0.93m x 2.50m):461433:1 | N00 - COO
Int. Simple:PP simple (0.93m x 2.50m):527142:1 | TR - N02 - ARCH
Int. Simple:PP simple (0.93m x 2.50m):527143:1 | TR - N02 - ARCH
Int. Simple:PV (0.93m x 2.50m):527144:1 | TR - N02 - ARCH
Int. Simple:PV (0.93m x 2.50m):527145:1 | TR - N02 - ARCH
Int. Simple:PP simple (0.93m x 2.50m):527146:1 | TR - N02 - ARCH
Int. Simple:PV (0.93m x 2.50m):527147:1 | TR - N02 - ARCH
Int. Simple:PV (0.93m x 2.50m):527148:1 | TR - N02 - ARCH
Int. Simple:PP simple (0.93m x 2.50m):527149:1 | TR - N02 - ARCH
Int. Simple:PP simple (0.93m x 2.50m):527150:1 | TR - N02 - ARCH
châssis intérieur vitré:châssis intérieur vitré (h=270) R+1:527151:1 | TR - N02 - ARCH
châssis intérieur vitré:châssis intérieur vitré (h=270) R+1:527152:1 | TR - N02 - ARCH
Int. Double:PP Placard (1.05m x 2.50m):533634:1 | TR - N02 - ARCH
Int. Simple:PP Placard (0.55m x 2.50m):533705:1 | TR - N02 - ARCH
Int. Double:PP (1.90m x 2.50m):551274:1 | TR - N02 - ARCH
Int. Simple:PV (0.93m x 2.50m):527179:1 | TR - N02 - ARCH
Int. Simple:PV (0.93m x 2.50m):527180:1 | TR - N02 - ARCH
Int. Simple:PP simple (0.93m x 2.50m):527181:1 | TR - N02 - ARCH
Int. Simple:PV (0.93m x 2.50m):527184:1 | TR - N02 - ARCH
Int. Simple:PV (0.93m x 2.50m):527185:1 | TR - N02 - ARCH
Int. Simple:PP simple (0.93m x 2.50m):527186:1 | TR - N02 - ARCH
Int. Simple:PV (0.93m x 2.50m):527189:1 | TR - N02 - ARCH
Int. Simple:PV (0.93m x 2.50m):527190:1 | TR - N02 - ARCH
Int. Simple:PV (0.93m x 2.50m):527191:1 | TR - N02 - ARCH
Int. Simple:PV (0.93m x 2.50m):527192:1 | TR - N02 - ARCH
châssis intérieur vitré:châssis intérieur vitré (h=270) R+1:527195:1 | TR - N02 - ARCH
châssis intérieur vitré:châssis intérieur vitré (h=270) R+1:527196:1 | TR - N02 - ARCH
châssis intérieur vitré:châssis intérieur vitré (h=270) R+1:527197:1 | TR - N02 - ARCH
châssis intérieur vitré:châssis intérieur vitré (h=270) R+1:527198:1 | TR - N02 - ARCH
châssis intérieur vitré:châssis intérieur vitré (h=270) R+1:527199:1 | TR - N02 - ARCH
châssis intérieur vitré:châssis intérieur vitré (h=270) R+1:527200:1 | TR - N02 - ARCH
châssis intérieur vitré:châssis intérieur vitré (h=270) R+1:527201:1 | TR - N02 - ARCH
Int. Simple:PP Placard (0.55m x 2.50m):517257:1 | Toiture - Cuisine
Int. Double:PP Placard (1.05m x 2.50m):517256:1 | Toiture - Cuisine
Int. Simple:PV (0.93m x 2.50m):517298:1 | Toiture - Cuisine
Int. Simple:PV (0.93m x 2.50m):517360:1 | Toiture - Cuisine
Int. Simple:PV (0.93m x 2.50m):517404:1 | Toiture - Cuisine
Int. Simple:PV (0.93m x 2.50m):517450:1 | Toiture - Cuisine
Int. Simple:PP simple (0.93m x 2.50m):517500:1 | Toiture - Cuisine
Int. Simple:PV (0.93m x 2.50m):517522:1 | Toiture - Cuisine
Int. Simple:PV (0.93m x 2.50m):517555:1 | Toiture - Cuisine
Int. Simple:PV (0.93m x 2.50m):517577:1 | Toiture - Cuisine
Int. Simple:PV (0.93m x 2.50m):517614:1 | Toiture - Cuisine
Int. Simple:PV (0.93m x 2.50m):517643:1 | Toiture - Cuisine
Int. Simple:PV (0.93m x 2.50m):517669:1 | Toiture - Cuisine
Int. Simple:PV (0.93m x 2.50m):517725:1 | Toiture - Cuisine
Int. Simple:PV (0.93m x 2.50m):517770:1 | Toiture - Cuisine
châssis intérieur vitré:châssis intérieur vitré (h=270) R+1:518503:1 | Toiture - Cuisine
châssis intérieur vitré:châssis intérieur vitré (h=270) R+1:518532:1 | Toiture - Cuisine
châssis intérieur vitré:châssis intérieur vitré (h=270) R+1:518551:1 | Toiture - Cuisine
châssis intérieur vitré:châssis intérieur vitré (h=270) R+1:518585:1 | Toiture - Cuisine
châssis intérieur vitré:châssis intérieur vitré (h=270) R+1:518625:1 | Toiture - Cuisine
châssis intérieur vitré:châssis intérieur vitré (h=270) R+1:938681:1 | Toiture - Cuisine
Int. Simple:PV (0.93m x 2.50m):519131:1 | Toiture - Cuisine
Int. Simple:PV (0.93m x 2.50m):519270:1 | Toiture - Cuisine
Int. Simple:PV (0.93m x 2.50m):519325:1 | Toiture - Cuisine
Int. Simple:PV (0.93m x 2.50m):519361:1 | Toiture - Cuisine
châssis intérieur vitré:châssis intérieur vitré (h=270) R+1:519963:1 | Toiture - Cuisine
châssis intérieur vitré:châssis intérieur vitré (h=270) R+1:519994:1 | Toiture - Cuisine
châssis intérieur vitré:châssis intérieur vitré (h=270) R+1:520030:1 | Toiture - Cuisine
châssis intérieur vitré:châssis intérieur vitré (h=270) R+1:520066:1 | Toiture - Cuisine
Int. Simple:PV (0.93m x 2.50m):519157:1 | Toiture - Cuisine
Int. Simple:PP simple (0.93m x 2.50m):519188:1 | Toiture - Cuisine
Int. Simple:PP simple (0.93m x 2.50m):519215:1 | Toiture - Cuisine
Int. Simple:PV (0.93m x 2.50m):519236:1 | Toiture - Cuisine
Int. Simple:PV (0.93m x 2.50m):519299:1 | Toiture - Cuisine
Int. Simple:PV (0.93m x 2.50m):519648:1 | Toiture - Cuisine
Int. Double:PP (1.90m x 2.50m):551199:1 | Toiture - Cuisine
Int. Simple:PV (0.93m x 2.50m):513782:1 | Toiture - Cuisine
Int. Simple:PV (0.93m x 2.50m):513814:1 | Toiture - Cuisine
Int. Simple:PV (0.93m x 2.50m):513844:1 | Toiture - Cuisine
Int. Simple:PV (0.93m x 2.50m):513867:1 | Toiture - Cuisine
Int. Simple:PV (0.93m x 2.50m):513885:1 | Toiture - Cuisine
Int. Simple:PV (0.93m x 2.50m):513905:1 | Toiture - Cuisine
Int. Simple:PV (0.93m x 2.50m):513934:1 | Toiture - Cuisine
Int. Simple:PV (0.93m x 2.50m):513962:1 | Toiture - Cuisine
Int. Simple:PP simple (0.93m x 2.50m):514002:1 | Toiture - Cuisine
Int. Simple:PV (0.93m x 2.50m):514052:1 | Toiture - Cuisine
Int. Simple:PV (0.93m x 2.50m):514069:1 | Toiture - Cuisine
châssis intérieur vitré:châssis intérieur vitré (h=270) R+1:514636:1 | Toiture - Cuisine
châssis intérieur vitré:châssis intérieur vitré (h=270) R+1:514675:1 | Toiture - Cuisine
châssis intérieur vitré:châssis intérieur vitré (h=270) R+1:514703:1 | Toiture - Cuisine
châssis intérieur vitré:châssis intérieur vitré (h=270) R+1:514742:1 | Toiture - Cuisine
châssis intérieur vitré:châssis intérieur vitré (h=270) R+1:514770:1 | Toiture - Cuisine
Int. Simple:PP simple (0.93m x 2.50m):1350075:1 | Toiture - Cuisine
Int. Simple:PP simple (0.93m x 2.50m):509531:1 | Toiture - Cuisine
Int. Simple:PV (0.93m x 2.50m):509556:1 | Toiture - Cuisine
Int. Simple:PV (0.93m x 2.50m):509586:1 | Toiture - Cuisine
Int. Simple:PP simple (0.93m x 2.50m):509611:1 | Toiture - Cuisine
Int. Simple:PV (0.93m x 2.50m):509660:1 | Toiture - Cuisine
Int. Simple:PV (0.93m x 2.50m):509708:1 | Toiture - Cuisine
Int. Simple:PP simple (0.93m x 2.50m):509737:1 | Toiture - Cuisine
châssis intérieur vitré:châssis intérieur vitré (h=270) R+1:510271:1 | Toiture - Cuisine
châssis intérieur vitré:châssis intérieur vitré (h=270) R+1:510228:1 | Toiture - Cuisine
Int. Simple:PP Placard (0.80m x 2.50m):510559:1 | Toiture - Cuisine
Int. Double:PP Placard (1.10m x 2.50m):510558:1 | Toiture - Cuisine
Int. Double:PP (1.90m x 2.50m):551198:1 | Toiture - Cuisine
Int. Double:PP (1.90m x 2.50m):2176532:1 | Toiture - Cuisine
Int. Simple:PP EXT - Local poubelle (0.93m x 2.50m):850345:1 | Toiture - Cuisine
Int. Double:PP (1.40m x 2.04m):1880202:1 | Toiture - Cuisine
Int. Simple:PP (0.93m x 3.06m):486740:1 | N00 - COO
Int. Simple:PP (0.93m x 3.06m):486741:1 | N00 - COO
Int. Simple:PP (0.93m x 3.06m):485836:1 | N00 - COO
Int. Simple:PV (0.93m x 3.00m):361198:1 | N00 - COO
châssis intérieur vitré:RDC - Pignon - châssis intérieur vitré (3.11m):938319:1 | N00 - COO
Int. Simple:PV (0.93m x 3.00m):1219787:1 | N00 - COO
Int. Simple:PV (0.93m x 3.00m):1219942:1 | N00 - COO
Int. Simple:PP simple (0.93m x 2.50m):397206:1 | N00 - COO
Int. Simple:PV (0.93m x 3.00m):397008:1 | N00 - COO
Int. Simple:PV (0.93m x 3.00m):397053:1 | N00 - COO
Int. Simple:PV (0.93m x 3.00m):397113:1 | N00 - COO
Int. Simple:PV (0.93m x 3.00m):397154:1 | N00 - COO
Int. Simple:PV (0.93m x 3.00m):397191:1 | N00 - COO
châssis intérieur vitré:châssis intérieur vitré (h=170):1997416:1 | N00 - COO
Int. Simple:PV (0.93m x 3.00m):397228:1 | N00 - COO
châssis intérieur vitré:châssis intérieur vitré (h=170):1997358:1 | N00 - COO
Int. Simple:PV (0.93m x 3.00m):398046:1 | N00 - COO
Int. Simple:PP (0.93m x 3.06m):397281:1 | N00 - COO
Int. Simple:PP (0.93m x 3.06m):397297:1 | N00 - COO
Int. Simple:PP (0.93m x 3.06m):397319:1 | N00 - COO
Int. Simple:PP (0.93m x 3.06m):397358:1 | N00 - COO
Int. Simple:PV (0.93m x 3.00m):397371:1 | N00 - COO
châssis intérieur vitré:châssis intérieur vitré (h=306):1998674:1 | N00 - COO
Int. Simple:PV (0.93m x 3.00m):1904770:1 | N00 - COO
châssis intérieur vitré:châssis intérieur vitré (h=170):1904895:1 | N00 - COO
Int. Simple:PV (0.93m x 3.00m):407186:1 | N00 - COO
Int. Simple:PP (0.93m x 3.06m):1903935:1 | N00 - COO
Int. Simple:PV (0.93m x 3.00m):1904518:1 | N00 - COO
Int. Simple:PV (0.93m x 3.00m):407236:1 | N00 - COO
Int. Simple:PV (0.93m x 3.00m):430402:1 | N00 - COO
Int. Simple:PP (0.93m x 3.06m):430366:1 | N00 - COO
Int. Simple:PV (0.93m x 3.00m):430236:1 | N00 - COO
Int. Simple:PV (0.93m x 3.00m):430310:1 | N00 - COO
châssis intérieur vitré:châssis intérieur vitré (h=306):430494:1 | N00 - COO
châssis intérieur vitré:châssis intérieur vitré (h=306):430523:1 | N00 - COO
Int. Simple:PP simple (0.93m x 2.50m):437793:1 | N00 - COO
Int. Simple:PP simple (0.93m x 2.50m):433599:1 | N00 - COO
Int. Simple:PP simple (0.93m x 2.50m):433863:1 | N00 - COO
Int. Simple:PP simple (0.93m x 2.50m):433381:1 | N00 - COO
Int. Simple:PP simple (0.93m x 2.50m):433346:1 | N00 - COO
Int. Simple:PP simple (0.93m x 2.50m):919789:1 | N00 - COO
Int. Simple:PP simple (0.93m x 2.50m):438480:1 | N00 - COO
Int. Simple:PP simple (0.93m x 2.50m):936949:1 | N00 - COO
Int. Simple:PP simple (0.93m x 2.50m):442055:1 | N00 - COO
Int. Simple:PP simple (0.93m x 2.50m):442141:1 | N00 - COO
Int. Simple:PP simple (0.93m x 2.50m):442154:1 | N00 - COO
Int. Simple:PP simple (0.93m x 2.50m):442176:1 | N00 - COO
Int. Simple:PP simple (0.93m x 2.50m):442251:1 | N00 - COO
Int. Simple:PP simple (0.93m x 2.50m):442279:1 | N00 - COO
Int. Simple:PP simple (0.93m x 2.50m):442395:1 | N00 - COO
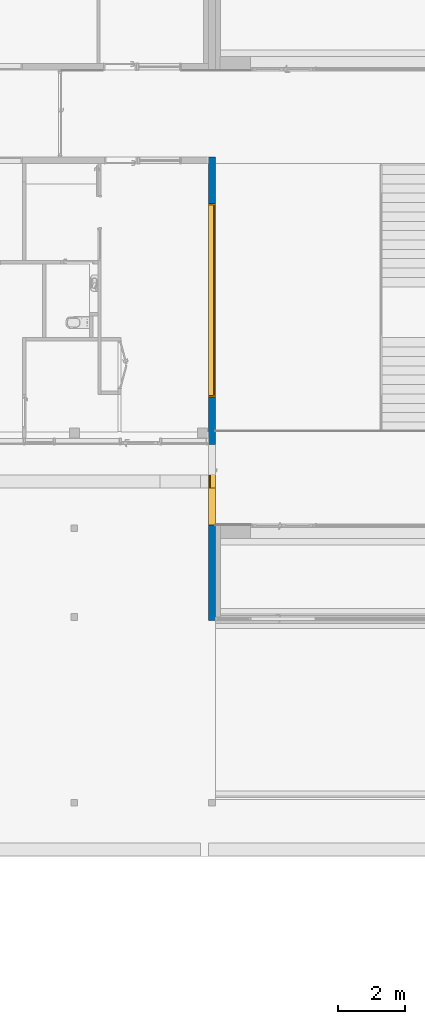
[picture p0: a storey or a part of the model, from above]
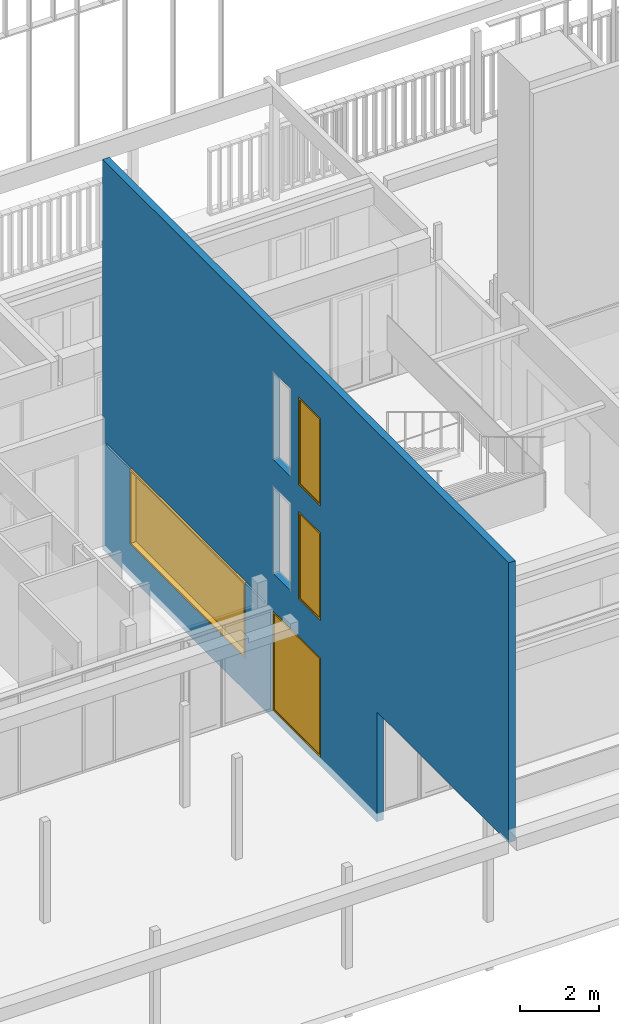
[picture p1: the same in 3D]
Properties of the parts of a building model (IFC2X3), part 5 of 7

# IfcOpeningElement: Opening (655)
Name | In
Int. Simple:PP simple (0.93m x 2.50m):442423:1 | N00 - COO
Int. Simple:PP simple (0.93m x 2.50m):442087:1 | N00 - COO
Int. Simple:PP simple (0.93m x 2.50m):442353:1 | N00 - COO
Int. Simple:PP simple (0.93m x 2.50m):1013929:1 | N00 - COO
Int. Simple:PP simple (0.93m x 2.50m):442117:1 | N00 - COO
Int. Simple:PP simple (0.93m x 2.50m):442315:1 | N00 - COO
Int. Simple:PP simple (0.93m x 2.50m):442329:1 | N00 - COO
Int. Tierce:PP (1.44m x 2.04m):452237:1 | N00 - COO
Int. Simple:PP simple (0.93m x 2.50m):1338255:1 | N00 - COO
Int. Simple:PP simple (0.93m x 2.50m):446710:1 | N00 - COO
Int. Double:PP Placard (1.10m x 2.50m):447251:1 | N00 - COO
Int. Double:PP Placard (1.10m x 2.50m):447274:1 | N00 - COO
Int. Simple:PP simple (0.93m x 2.50m):446647:1 | N00 - COO
Int. Simple:PP simple (0.93m x 2.50m):446682:1 | N00 - COO
Int. Simple:PP simple (0.93m x 2.50m):446624:1 | N00 - COO
Int. Double:PP Placard (1.26m x 2.04m):446544:1 | N00 - COO
Int. Double:PP Placard (1.10m x 2.50m):446941:1 | N00 - COO
Coulissante - Apparente:PM 0.80m x 2.04m 2:1117941:1 | N00 - COO
Coulissante - Apparente:PM 0.80m x 2.04m 2:1117960:1 | N00 - COO
Coulissante - Apparente:PM 0.80m x 2.04m 2:1117987:1 | N00 - COO
Int. Simple:PP simple (0.93m x 2.50m):1015142:1 | N00 - COO
Int. Simple:PP simple (0.93m x 2.50m):457051:1 | N00 - COO
Int. Simple:PP simple (0.93m x 2.50m):457072:1 | N00 - COO
Int. Simple:PP simple (0.93m x 2.50m):457102:1 | N00 - COO
Int. Simple:PP simple (0.93m x 2.50m):457144:1 | N00 - COO
Int. Simple:PP simple (0.93m x 2.50m):457164:1 | N00 - COO
Int. Simple:PP simple (0.93m x 2.50m):457120:1 | N00 - COO
Int. Simple:PP simple (0.93m x 2.50m):457031:1 | N00 - COO
Int. Simple:PP (0.83m x 2.04m):456985:1 | N00 - COO
Int. Simple:PP (0.83m x 2.04m):457187:1 | N00 - COO
Int. Simple:PP (0.83m x 2.04m):457216:1 | N00 - COO
Int. Simple:PP simple (0.93m x 2.50m):457250:1 | N00 - COO
Int. Simple:PP simple (0.93m x 2.50m):457278:1 | N00 - COO
Int. Simple:PP simple (0.93m x 2.50m):456862:1 | N00 - COO
Int. Simple:PP simple (0.93m x 2.50m):456893:1 | N00 - COO
Int. Simple:PP simple (0.93m x 2.50m):456944:1 | N00 - COO
châssis intérieur vitré:châssis intérieur vitré self (h=2.22) 2:459594:1 | N00 - COO
Int. Simple:PP simple (0.93m x 2.50m):461283:1 | N00 - COO
Int. Simple:PP (0.93m x 2.50m):461330:1 | N00 - COO
Int. Simple:PP (0.93m x 2.50m):461295:1 | N00 - COO
Int. Simple:PP (0.93m x 2.50m):463043:1 | N00 - COO
Int. Simple:PP (0.93m x 2.50m):463010:1 | N00 - COO
Int. Simple:PP (0.93m x 2.50m):463188:1 | N00 - COO
châssis intérieur vitré:châssis intérieur vitré (h=170):1777326:1 | N00 - COO
Int. Simple:PP (0.93m x 3.06m):485845:1 | N00 - COO
Int. Simple:PP (0.93m x 3.06m):485846:1 | N00 - COO
Int. Simple:PP simple (0.93m x 2.50m):527183:1 | TR - N02 - ARCH
Int. Simple:PP simple (0.93m x 2.50m):527182:1 | TR - N02 - ARCH
Int. Simple:PP simple (0.93m x 2.50m):527187:1 | TR - N02 - ARCH
Int. Simple:PP simple (0.93m x 2.50m):527188:1 | TR - N02 - ARCH
Int. Simple:PV (0.93m x 2.50m):1800699:1 | TR - N02 - ARCH
Int. Simple:PV (0.93m x 2.50m):531527:1 | TR - N02 - ARCH
Int. Simple:PV (0.93m x 2.50m):531559:1 | TR - N02 - ARCH
Int. Simple:PP simple (0.93m x 2.50m):531584:1 | TR - N02 - ARCH
Int. Simple:PV (0.93m x 2.50m):531598:1 | TR - N02 - ARCH
Int. Simple:PV (0.93m x 2.50m):531632:1 | TR - N02 - ARCH
Int. Simple:PV (0.93m x 2.50m):531662:1 | TR - N02 - ARCH
Int. Simple:PV (0.93m x 2.50m):531694:1 | TR - N02 - ARCH
Int. Simple:PV (0.93m x 2.50m):531713:1 | TR - N02 - ARCH
Int. Simple:PV (0.93m x 2.50m):531748:1 | TR - N02 - ARCH
Int. Simple:PP simple (0.93m x 2.50m):531776:1 | TR - N02 - ARCH
châssis intérieur vitré:châssis intérieur vitré (h=270) R+1:532140:1 | TR - N02 - ARCH
châssis intérieur vitré:châssis intérieur vitré (h=270) R+1:532170:1 | TR - N02 - ARCH
châssis intérieur vitré:châssis intérieur vitré (h=270) R+1:532194:1 | TR - N02 - ARCH
châssis intérieur vitré:châssis intérieur vitré (h=270) R+1:532211:1 | TR - N02 - ARCH
châssis intérieur vitré:châssis intérieur vitré (h=270) R+1:532228:1 | TR - N02 - ARCH
châssis intérieur vitré:châssis intérieur vitré (h=270) R+1:532253:1 | TR - N02 - ARCH
châssis intérieur vitré:châssis intérieur vitré (h=270) R+1:532281:1 | TR - N02 - ARCH
Int. Simple:PP Placard (0.55m x 2.50m):533480:1 | TR - N02 - ARCH
Int. Double:PP Placard (1.05m x 2.09m):533521:1 | TR - N02 - ARCH
Int. Simple:PV (0.93m x 2.50m):532743:1 | TR - N02 - ARCH
Int. Simple:PV (0.93m x 2.50m):532781:1 | TR - N02 - ARCH
Int. Simple:PP simple (0.93m x 2.50m):532800:1 | TR - N02 - ARCH
Int. Simple:PP simple (0.93m x 2.50m):532825:1 | TR - N02 - ARCH
Int. Simple:PP simple (0.93m x 2.50m):532891:1 | TR - N02 - ARCH
Int. Simple:PV (0.93m x 2.50m):532906:1 | TR - N02 - ARCH
Int. Simple:PV (0.93m x 2.50m):532944:1 | TR - N02 - ARCH
châssis intérieur vitré:châssis intérieur vitré (h=270) R+1:533204:1 | TR - N02 - ARCH
châssis intérieur vitré:châssis intérieur vitré (h=270) R+1:533245:1 | TR - N02 - ARCH
châssis intérieur vitré:châssis intérieur vitré (h=270) R+1:533276:1 | TR - N02 - ARCH
châssis intérieur vitré:châssis intérieur vitré (h=270) R+1:533296:1 | TR - N02 - ARCH
Int. Double:PP (1.83m x 2.04m):551275:1 | TR - N02 - ARCH
Int. Simple:PP simple (0.93m x 2.50m):531803:1 | TR - N02 - ARCH
Int. Simple:PP simple (0.93m x 2.50m):531789:1 | TR - N02 - ARCH
Int. Simple:PP simple (0.93m x 2.50m):531815:1 | TR - N02 - ARCH
Int. Simple:PP simple (0.93m x 2.50m):1351422:1 | TR - N02 - ARCH
Int. Simple:PP simple (0.93m x 2.50m):1351445:1 | TR - N02 - ARCH
Int. Simple:PP simple (0.93m x 2.50m):531836:1 | TR - N02 - ARCH
Int. Double:PV (2.50m x 3.06m):551646:1 | N00 - COO
Int. Double:PV (2.50m x 3.06m):551622:1 | N00 - COO
Int. Double:PV (2.50m x 2.04m):552938:1 | Toiture - Cuisine
Int. Double:PV (2.50m x 2.04m):552911:1 | Toiture - Cuisine
Int. Double:PV (2.50m x 2.04m):552862:1 | TR - N02 - ARCH
Int. Double:PV (2.50m x 2.04m):552841:1 | TR - N02 - ARCH
châssis intérieur vitré:RDC - Pignon - châssis intérieur vitré (3.11m):555884:1 | N00 - COO
châssis intérieur vitré:R+1 - Pignon - châssis intérieur vitré (2,70m):555970:1 | N00 - COO
châssis intérieur vitré:R+1 - Pignon - châssis intérieur vitré (2,70m):556073:1 | N00 - COO
Ouvrant vitré:Ouvrant POMPIERS Facade nord (140cm):1132216:1 | TR - N02 - ARCH
Ouvrant vitré:Ouvrant vitré (70cm):1132439:1 | TR - N02 - ARCH
Ouvrant vitré:Ouvrant vitré (70cm):1132524:1 | TR - N02 - ARCH
Ouvrant vitré:Ouvrant vitré (70cm):1132672:1 | TR - N02 - ARCH
Ouvrant vitré:Ouvrant vitré (70cm):1132801:1 | TR - N02 - ARCH
Ouvrant vitré:Ouvrant vitré (70cm):1133017:1 | TR - N02 - ARCH
Ouvrant vitré:Ouvrant vitré (70cm):1133115:1 | TR - N02 - ARCH
Ouvrant vitré:Ouvrant vitré (70cm):1133174:1 | TR - N02 - ARCH
Ouvrant vitré:Ouvrant vitré (70cm):1133254:1 | TR - N02 - ARCH
Ouvrant vitré:Ouvrant vitré (70cm):1133483:1 | TR - N02 - ARCH
Ouvrant vitré:Ouvrant vitré (70cm):1133553:1 | TR - N02 - ARCH
Ouvrant vitré:Ouvrant vitré (70cm):1133619:1 | TR - N02 - ARCH
Ouvrant vitré:Ouvrant vitré (70cm):1133745:1 | TR - N02 - ARCH
Ouvrant vitré:Ouvrant vitré (70cm):1133828:1 | TR - N02 - ARCH
Mur de base:04 - Parement - ITE 18cm + vide 2cm:577104 | N00 - COO
Ouvrant vitré:Ouvrant vitré (90cm) RDC:1185106:1 | N00 - COO
Ouvrant vitré:Ouvrant vitré (90cm) RDC:1171731:1 | N00 - COO
Ouvrant vitré:Ouvrant vitré (90cm) RDC:1185099:1 | N00 - COO
Ouvrant vitré:Ouvrant vitré (90cm) RDC:1185088:1 | N00 - COO
Ouvrant vitré:Ouvrant vitré (90cm) RDC:1185261:1 | N00 - COO
Mur de base:04 - Parement - ITE 18cm + vide 2cm:578381 | N00 - COO
Ouvrant vitré:Ouvrant POMPIERS Facade nord (140cm):1130395:1 | TR - N02 - ARCH
Ouvrant vitré:Ouvrant POMPIERS Facade nord (140cm):1130308:1 | TR - N02 - ARCH
Ouvrant vitré:Ouvrant vitré (70cm):1130309:1 | TR - N02 - ARCH
Ouvrant vitré:Ouvrant vitré (70cm):1130310:1 | TR - N02 - ARCH
Ouvrant vitré:Ouvrant vitré (70cm):1130029:1 | TR - N02 - ARCH
Ouvrant vitré:Ouvrant vitré (70cm):1129976:1 | TR - N02 - ARCH
Ouvrant vitré:Ouvrant vitré (70cm):1129847:1 | TR - N02 - ARCH
Ouvrant vitré:Ouvrant vitré (90cm) RDC:1185146:1 | N00 - COO
Ouvrant vitré:Ouvrant vitré (90cm) RDC:1185153:1 | N00 - COO
Ouvrant vitré:Ouvrant vitré (90cm) RDC:1185163:1 | N00 - COO
Ouvrant vitré:Ouvrant vitré (90cm) RDC:1185139:1 | N00 - COO
Mur de base:04 - Parement - ITE 18cm + vide 2cm:584873 | N00 - COO
Ouvrant vitré:Ouvrant vitré (90cm) RDC:1185248:1 | N00 - COO
Ouvrant vitré:Ouvrant vitré (90cm) RDC:1185131:1 | N00 - COO
Ouvrant vitré:Ouvrant vitré (90cm) RDC:1185112:1 | N00 - COO
5 x Mur de base:04 - Parement - ITE 18cm + vide 2cm:666686 | N00 - COO
Ouvrant vitré:Ouvrant vitré (90cm) RDC:1195992:1 | N00 - COO
Ouvrant vitré:Ouvrant vitré (90cm) RDC:1185236:1 | N00 - COO
Ouvrant vitré:Ouvrant vitré (90cm) RDC:1185230:1 | N00 - COO
Ouvrant vitré:Ouvrant vitré (90cm) RDC:1195983:1 | N00 - COO
Ouvrant vitré:Ouvrant vitré (90cm) RDC:1185218:1 | N00 - COO
Ouvrant vitré:Ouvrant vitré (90cm) RDC:1195999:1 | N00 - COO
Ouvrant vitré:Ouvrant vitré (90cm) RDC:1185212:1 | N00 - COO
Ouvrant vitré:Ouvrant vitré (90cm) RDC:1185224:1 | N00 - COO
châssis intérieur vitré:R+1 - Pignon - châssis intérieur vitré (2,70m):685541:1 | Toiture - Cuisine
châssis intérieur vitré:R+1 - Pignon - châssis intérieur vitré (2,70m):710415:1 | Toiture - Cuisine
châssis intérieur vitré:R+1 - Pignon - châssis intérieur vitré (2,70m):686131:1 | Toiture - Cuisine
châssis intérieur vitré:R+1 - Pignon - châssis intérieur vitré (2,70m):688942:1 | TR - N02 - ARCH
châssis intérieur vitré:RDC - Pignon - châssis intérieur vitré (3.11m):711633:1 | N00 - COO
2 x Mur de base:06 - cloisons - Ba13 10cm:704262 | N00 - COO
2 x Mur de base:06 - cloisons - Ba13 10cm:704619 | N00 - COO
Int. Double:PP (1.83m x 2.04m):1874807:1 | TR - N02 - ARCH
châssis intérieur vitré:R+1 - Pignon - châssis intérieur vitré (2,70m):734198:1 | Toiture - Cuisine
châssis intérieur vitré:R+1 - Pignon - châssis intérieur vitré (2,70m):734204:1 | Toiture - Cuisine
châssis intérieur vitré:RDC - Pignon - châssis intérieur vitré (3.11m):734211:1 | N00 - COO
Int. Double:PP (1.40m x 2.04m):795850:1 | N00 - COO
Mur de base:06 - cloisons - Ba13 10cm:777906 | N00 - COO
Ouvrant vitré:Ouvrant vitré (93cm) RDC:1330227:1 | N00 - COO
Ouvrant vitré:Ouvrant vitré (93cm) RDC:1159869:1 | N00 - COO
Ouvrant vitré:Ouvrant vitré (93cm) RDC:1159853:1 | N00 - COO
Ouvrant vitré:Ouvrant vitré (93cm) RDC:1159811:1 | N00 - COO
Ouvrant vitré:Ouvrant vitré (93cm) RDC:1330168:1 | N00 - COO
Ouvrant vitré:Ouvrant vitré (93cm) RDC:1159285:1 | N00 - COO
Ouvrant vitré:Ouvrant vitré (93cm) RDC:1157167:1 | N00 - COO
Int. Simple:PP EXT - Local poubelle (0.93m x 2.50m):1012698:1 | N00 - COO
Int. Simple:PP simple (0.93m x 2.50m):793670:1 | N00 - COO
Int. Simple:PP EXT - Local poubelle (0.93m x 2.50m):1012701:1 | N00 - COO
Int. Double:PP (1.40m x 2.04m):795685:1 | N00 - COO
Int. Tierce:PP (1.80m x 3.11m):1039841:1 | N00 - COO
2 x Mur de base:04 - Parement - ITE 18cm + vide 2cm:798291 | N00 - COO
Int. Tierce:PP (1.80m x 3.11m):1860215:1 | N00 - COO
Mur de base:04 - Parement - ITE 18cm + vide 2cm:798382 | N00 - COO
Int. Tierce:PP chaufferie (1.80m x 2.50m):1786058:1 | N00 - COO
Int. Simple:PP simple (0.93m x 2.50m):1015872:1 | N00 - COO
Int. Tierce:PP (1.90m x 2.60m):2061533:1 | N00 - COO
2 x Mur de base:06 - cloisons - Ba13 10cm:839212 | N00 - COO
Int. Simple:PP EXT - Vide sanitaire (0.93m x 1.80m):852628:1 | Vide Sanitaire
châssis intérieur vitré:châssis intérieur vitré bureau asen:894344:1 | N00 - COO
Int. Simple:PP simple (0.93m x 2.50m):919761:1 | N00 - COO
Int. Simple:PV (0.93m x 3.00m):920153:1 | N00 - COO
Int. Simple:PP simple accès technique coursive ext (0.93m x 2.50m) 2:923996:1 | N00 - COO
Int. Simple:PP simple (0.93m x 2.50m):936931:1 | N00 - COO
châssis intérieur vitré:châssis intérieur vitré (h=306):937897:1 | N00 - COO
Ouvrant vitré:Ouvrant vitré (87cm):1160667:1 | N00 - COO
Ouvrant vitré:Ouvrant vitré (87cm):1162016:1 | N00 - COO
Ouvrant vitré:Ouvrant vitré (87cm):1162076:1 | N00 - COO
Mur de base:06 - cloisons - Ba13 10cm:1995049 | N00 - COO
Mur de base:06 - cloisons - Ba13 10cm:1218587 | N00 - COO
Ouvrant vitré:Ouvrant vitré 175mm:1719054:1 | N00 - COO
Mur de base:04 - Parement - isolant 14 cm + BA13:1339487 | N00 - COO
Int. Double:PP airel poubelle(1.66m x 2.04m):1428170:1 | N00 - COO
Int. Simple:PP simple accès technique coursive ext (0.93m x 2.50m) 2:1726946:1 | N00 - COO
Int. Simple:PP ISOTHERME (0.93m x 2.04m):1772648:1 | N00 - COO
Mur de base:06 - cloisons - Ba13 10cm:1791997 | N00 - COO
châssis intérieur vitré:RDC - Pignon - châssis intérieur vitré (3.11m):1969216:1 | N00 - COO
Int. Double:PP (1.40m x 2.04m):1887895:1 | Toiture - Cuisine
Int. Simple:PV (0.93m x 3.00m):1903567:1 | N00 - COO
Int. Double:PP Placard (1.35m x 2.04m):1905426:1 | N00 - COO
Int. Simple:PP simple (0.93m x 2.50m):1976105:1 | N00 - COO
Int. Double:PV (1.90m x 3.00m):1996927:1 | N00 - COO

# IfcPlate: Plein (panneau Sandwich) (5)
In: N00 - COO
Type - PredefinedType: CURTAIN_PANEL; Material: Verre 4 cm
Type - Pset_PlateCommon - IsExternal: no; Reference: Plein (panneau Sandwich)
Type - Pset_QuantityTakeOff - Reference: Plein (panneau Sandwich)
Name (Panneau système:Plein (panneau Sandwich):...)
1204473
1204013
578660
578672
578674

# IfcPlate: Vitré (473)
Type - PredefinedType: CURTAIN_PANEL; Material: Verre 4 cm
Type - Pset_PlateCommon - IsExternal: no; Reference: Vitré; ThermalTransmittance: 6.7069 kg/K/s3
Type - Pset_QuantityTakeOff - Reference: Vitré
Name (Panneau système:Vitré:...) | In
165616 | N00 - COO | Material: Verre
1048011 | N00 - COO
166271 | N00 - COO | Material: Verre
1048985 | N00 - COO
221236 | TR - N03 - ARCH | Pset_PlateCommon - IsExternal: yes
221282 | TR - N03 - ARCH | Pset_PlateCommon - IsExternal: yes
221284 | TR - N03 - ARCH | Pset_PlateCommon - IsExternal: yes
221286 | TR - N03 - ARCH | Pset_PlateCommon - IsExternal: yes
221288 | TR - N03 - ARCH | Pset_PlateCommon - IsExternal: yes
221290 | TR - N03 - ARCH | Pset_PlateCommon - IsExternal: yes
221292 | TR - N03 - ARCH | Pset_PlateCommon - IsExternal: yes
221294 | TR - N03 - ARCH | Pset_PlateCommon - IsExternal: yes
894220 | TR - N03 - ARCH | Pset_PlateCommon - IsExternal: yes
894221 | TR - N03 - ARCH | Pset_PlateCommon - IsExternal: yes
894222 | TR - N03 - ARCH | Pset_PlateCommon - IsExternal: yes
894223 | TR - N03 - ARCH | Pset_PlateCommon - IsExternal: yes
894224 | TR - N03 - ARCH | Pset_PlateCommon - IsExternal: yes
894225 | TR - N03 - ARCH | Pset_PlateCommon - IsExternal: yes
894226 | TR - N03 - ARCH | Pset_PlateCommon - IsExternal: yes
894227 | TR - N03 - ARCH | Pset_PlateCommon - IsExternal: yes
894161 | TR - N03 - ARCH | Pset_PlateCommon - IsExternal: yes
894162 | TR - N03 - ARCH | Pset_PlateCommon - IsExternal: yes
894163 | TR - N03 - ARCH | Pset_PlateCommon - IsExternal: yes
894164 | TR - N03 - ARCH | Pset_PlateCommon - IsExternal: yes
894165 | TR - N03 - ARCH | Pset_PlateCommon - IsExternal: yes
894166 | TR - N03 - ARCH | Pset_PlateCommon - IsExternal: yes
894167 | TR - N03 - ARCH | Pset_PlateCommon - IsExternal: yes
894168 | TR - N03 - ARCH | Pset_PlateCommon - IsExternal: yes
1147415 | N00 - COO
254091 | Toiture - Cuisine | Pset_PlateCommon - IsExternal: yes
255172 | Toiture - Cuisine | Pset_PlateCommon - IsExternal: yes
255174 | Toiture - Cuisine | Pset_PlateCommon - IsExternal: yes
255176 | Toiture - Cuisine | Pset_PlateCommon - IsExternal: yes
255178 | Toiture - Cuisine | Pset_PlateCommon - IsExternal: yes
255180 | Toiture - Cuisine | Pset_PlateCommon - IsExternal: yes
255182 | Toiture - Cuisine | Pset_PlateCommon - IsExternal: yes
255184 | Toiture - Cuisine | Pset_PlateCommon - IsExternal: yes
255188 | Toiture - Cuisine | Pset_PlateCommon - IsExternal: yes
255192 | Toiture - Cuisine | Pset_PlateCommon - IsExternal: yes
255190 | Toiture - Cuisine | Pset_PlateCommon - IsExternal: yes
255194 | Toiture - Cuisine | Pset_PlateCommon - IsExternal: yes
255196 | Toiture - Cuisine | Pset_PlateCommon - IsExternal: yes
255198 | Toiture - Cuisine | Pset_PlateCommon - IsExternal: yes
255202 | Toiture - Cuisine | Pset_PlateCommon - IsExternal: yes
255204 | Toiture - Cuisine | Pset_PlateCommon - IsExternal: yes
255206 | Toiture - Cuisine | Pset_PlateCommon - IsExternal: yes
255208 | Toiture - Cuisine | Pset_PlateCommon - IsExternal: yes
255210 | Toiture - Cuisine | Pset_PlateCommon - IsExternal: yes
255212 | Toiture - Cuisine | Pset_PlateCommon - IsExternal: yes
255216 | Toiture - Cuisine | Pset_PlateCommon - IsExternal: yes
255220 | Toiture - Cuisine | Pset_PlateCommon - IsExternal: yes
255218 | Toiture - Cuisine | Pset_PlateCommon - IsExternal: yes
255222 | Toiture - Cuisine | Pset_PlateCommon - IsExternal: yes
255224 | Toiture - Cuisine | Pset_PlateCommon - IsExternal: yes
255226 | Toiture - Cuisine | Pset_PlateCommon - IsExternal: yes
255230 | Toiture - Cuisine | Pset_PlateCommon - IsExternal: yes
255232 | Toiture - Cuisine | Pset_PlateCommon - IsExternal: yes
255234 | Toiture - Cuisine | Pset_PlateCommon - IsExternal: yes
255236 | Toiture - Cuisine | Pset_PlateCommon - IsExternal: yes
255238 | Toiture - Cuisine | Pset_PlateCommon - IsExternal: yes
524297 | TR - N02 - ARCH
524300 | TR - N02 - ARCH
524302 | TR - N02 - ARCH
524304 | TR - N02 - ARCH
524306 | TR - N02 - ARCH
524308 | TR - N02 - ARCH
524310 | TR - N02 - ARCH
524312 | TR - N02 - ARCH
524314 | TR - N02 - ARCH
524316 | TR - N02 - ARCH
524318 | TR - N02 - ARCH
524320 | TR - N02 - ARCH
524322 | TR - N02 - ARCH
524324 | TR - N02 - ARCH
524326 | TR - N02 - ARCH
524328 | TR - N02 - ARCH
524330 | TR - N02 - ARCH
524332 | TR - N02 - ARCH
524334 | TR - N02 - ARCH
524336 | TR - N02 - ARCH
524338 | TR - N02 - ARCH
524340 | TR - N02 - ARCH
524342 | TR - N02 - ARCH
524344 | TR - N02 - ARCH | Material: Verre
524346 | TR - N02 - ARCH | Material: Verre
524348 | TR - N02 - ARCH
524350 | TR - N02 - ARCH
524352 | TR - N02 - ARCH
524354 | TR - N02 - ARCH
524356 | TR - N02 - ARCH
524358 | TR - N02 - ARCH
524360 | TR - N02 - ARCH
524362 | TR - N02 - ARCH
524364 | TR - N02 - ARCH
524366 | TR - N02 - ARCH
524368 | TR - N02 - ARCH
524370 | TR - N02 - ARCH
524372 | TR - N02 - ARCH
524374 | TR - N02 - ARCH
524376 | TR - N02 - ARCH
524378 | TR - N02 - ARCH
524380 | TR - N02 - ARCH
524382 | TR - N02 - ARCH
524384 | TR - N02 - ARCH
524386 | TR - N02 - ARCH
524388 | TR - N02 - ARCH
524390 | TR - N02 - ARCH
524392 | TR - N02 - ARCH
524394 | TR - N02 - ARCH
524396 | TR - N02 - ARCH
524398 | TR - N02 - ARCH | Material: Verre
524400 | TR - N02 - ARCH | Material: Verre
524402 | TR - N02 - ARCH
524404 | TR - N02 - ARCH
524406 | TR - N02 - ARCH
524408 | TR - N02 - ARCH
524410 | TR - N02 - ARCH
524412 | TR - N02 - ARCH
524414 | TR - N02 - ARCH
524416 | TR - N02 - ARCH
524418 | TR - N02 - ARCH
524420 | TR - N02 - ARCH
524422 | TR - N02 - ARCH
524424 | TR - N02 - ARCH
524426 | TR - N02 - ARCH
524428 | TR - N02 - ARCH
524430 | TR - N02 - ARCH
524432 | TR - N02 - ARCH
526612 | Toiture - Cuisine
526619 | Toiture - Cuisine
526621 | Toiture - Cuisine
526625 | Toiture - Cuisine
526629 | Toiture - Cuisine
526631 | Toiture - Cuisine
526635 | Toiture - Cuisine
526637 | Toiture - Cuisine
526641 | Toiture - Cuisine
526643 | Toiture - Cuisine
526647 | Toiture - Cuisine
526651 | Toiture - Cuisine
526653 | Toiture - Cuisine
526657 | Toiture - Cuisine
526659 | Toiture - Cuisine
526661 | Toiture - Cuisine
526665 | Toiture - Cuisine
526667 | Toiture - Cuisine
526671 | Toiture - Cuisine
526675 | Toiture - Cuisine
526677 | Toiture - Cuisine
922853 | Toiture - Cuisine
528088 | Toiture - Cuisine
528091 | Toiture - Cuisine
528093 | Toiture - Cuisine
528095 | Toiture - Cuisine
528099 | Toiture - Cuisine
528101 | Toiture - Cuisine
528105 | Toiture - Cuisine
528109 | Toiture - Cuisine
528111 | Toiture - Cuisine
528113 | Toiture - Cuisine
528117 | Toiture - Cuisine
528119 | Toiture - Cuisine
528123 | Toiture - Cuisine
528125 | Toiture - Cuisine
528129 | Toiture - Cuisine
528133 | Toiture - Cuisine
528135 | Toiture - Cuisine
528139 | Toiture - Cuisine
528763 | TR - N02 - ARCH
528766 | TR - N02 - ARCH
528768 | TR - N02 - ARCH
528770 | TR - N02 - ARCH
528772 | TR - N02 - ARCH
528774 | TR - N02 - ARCH
528776 | TR - N02 - ARCH
528778 | TR - N02 - ARCH
528780 | TR - N02 - ARCH
528782 | TR - N02 - ARCH
528784 | TR - N02 - ARCH
528786 | TR - N02 - ARCH
528788 | TR - N02 - ARCH
528790 | TR - N02 - ARCH
528792 | TR - N02 - ARCH
528794 | TR - N02 - ARCH
528796 | TR - N02 - ARCH
528798 | TR - N02 - ARCH
528800 | TR - N02 - ARCH
528802 | TR - N02 - ARCH
528804 | TR - N02 - ARCH
528806 | TR - N02 - ARCH
528808 | TR - N02 - ARCH
528810 | TR - N02 - ARCH
528812 | TR - N02 - ARCH
528814 | TR - N02 - ARCH
528816 | TR - N02 - ARCH
528818 | TR - N02 - ARCH
528820 | TR - N02 - ARCH
528822 | TR - N02 - ARCH
528824 | TR - N02 - ARCH
528826 | TR - N02 - ARCH
528828 | TR - N02 - ARCH
528830 | TR - N02 - ARCH
528832 | TR - N02 - ARCH
528834 | TR - N02 - ARCH
528836 | TR - N02 - ARCH
528838 | TR - N02 - ARCH
528840 | TR - N02 - ARCH
528842 | TR - N02 - ARCH
528844 | TR - N02 - ARCH
528846 | TR - N02 - ARCH
528848 | TR - N02 - ARCH
528850 | TR - N02 - ARCH
528852 | TR - N02 - ARCH
528854 | TR - N02 - ARCH
528856 | TR - N02 - ARCH
528858 | TR - N02 - ARCH
528860 | TR - N02 - ARCH
528862 | TR - N02 - ARCH
528864 | TR - N02 - ARCH
528866 | TR - N02 - ARCH
576239 | TR - N02 - ARCH
576243 | TR - N02 - ARCH | Material: Verre
576245 | TR - N02 - ARCH | Material: Verre
576247 | TR - N02 - ARCH
576249 | TR - N02 - ARCH
576251 | TR - N02 - ARCH
576253 | TR - N02 - ARCH
576255 | TR - N02 - ARCH
576257 | TR - N02 - ARCH
576259 | TR - N02 - ARCH
576261 | TR - N02 - ARCH
576263 | TR - N02 - ARCH
576265 | TR - N02 - ARCH
576267 | TR - N02 - ARCH
576269 | TR - N02 - ARCH
576271 | TR - N02 - ARCH
576273 | TR - N02 - ARCH
576275 | TR - N02 - ARCH
576277 | TR - N02 - ARCH
576279 | TR - N02 - ARCH
576281 | TR - N02 - ARCH
576283 | TR - N02 - ARCH
576285 | TR - N02 - ARCH
576287 | TR - N02 - ARCH
576289 | TR - N02 - ARCH
576291 | TR - N02 - ARCH
576293 | TR - N02 - ARCH
576295 | TR - N02 - ARCH
576297 | TR - N02 - ARCH
576299 | TR - N02 - ARCH
576301 | TR - N02 - ARCH
576303 | TR - N02 - ARCH
576305 | TR - N02 - ARCH
576307 | TR - N02 - ARCH
576309 | TR - N02 - ARCH
576311 | TR - N02 - ARCH
576313 | TR - N02 - ARCH
576315 | TR - N02 - ARCH
576317 | TR - N02 - ARCH
576319 | TR - N02 - ARCH
576321 | TR - N02 - ARCH
576323 | TR - N02 - ARCH
576325 | TR - N02 - ARCH
576327 | TR - N02 - ARCH
576329 | TR - N02 - ARCH
576331 | TR - N02 - ARCH
576333 | TR - N02 - ARCH
576335 | TR - N02 - ARCH
576337 | TR - N02 - ARCH
576339 | TR - N02 - ARCH | Material: Verre
576341 | TR - N02 - ARCH
576343 | TR - N02 - ARCH
576345 | TR - N02 - ARCH
868492 | TR - N02 - ARCH
868494 | TR - N02 - ARCH
868496 | TR - N02 - ARCH
868498 | TR - N02 - ARCH
868500 | TR - N02 - ARCH
868502 | TR - N02 - ARCH
868504 | TR - N02 - ARCH
868506 | TR - N02 - ARCH
871483 | TR - N02 - ARCH
577785 | Toiture - Cuisine
577790 | Toiture - Cuisine
577794 | Toiture - Cuisine
577796 | Toiture - Cuisine
577800 | Toiture - Cuisine
577804 | Toiture - Cuisine
577808 | Toiture - Cuisine
577810 | Toiture - Cuisine
577812 | Toiture - Cuisine
577816 | Toiture - Cuisine
577818 | Toiture - Cuisine
577822 | Toiture - Cuisine
577824 | Toiture - Cuisine
577826 | Toiture - Cuisine
577830 | Toiture - Cuisine
577834 | Toiture - Cuisine
577836 | Toiture - Cuisine
577840 | Toiture - Cuisine
577842 | Toiture - Cuisine
577846 | Toiture - Cuisine
578651 | N00 - COO
1204635 | N00 - COO
580071 | TR - N02 - ARCH
580074 | TR - N02 - ARCH | Material: Verre
580076 | TR - N02 - ARCH | Material: Verre
580078 | TR - N02 - ARCH
580080 | TR - N02 - ARCH
580082 | TR - N02 - ARCH
580084 | TR - N02 - ARCH
580086 | TR - N02 - ARCH
580088 | TR - N02 - ARCH
580090 | TR - N02 - ARCH
580092 | TR - N02 - ARCH
580094 | TR - N02 - ARCH
580096 | TR - N02 - ARCH
580098 | TR - N02 - ARCH
580100 | TR - N02 - ARCH
580102 | TR - N02 - ARCH
580104 | TR - N02 - ARCH
580106 | TR - N02 - ARCH
580108 | TR - N02 - ARCH
580110 | TR - N02 - ARCH
580112 | TR - N02 - ARCH
580114 | TR - N02 - ARCH
580116 | TR - N02 - ARCH
580118 | TR - N02 - ARCH
580120 | TR - N02 - ARCH | Material: Verre
580122 | TR - N02 - ARCH | Material: Verre
580124 | TR - N02 - ARCH
580126 | TR - N02 - ARCH
580128 | TR - N02 - ARCH
580130 | TR - N02 - ARCH
580132 | TR - N02 - ARCH
580134 | TR - N02 - ARCH
580136 | TR - N02 - ARCH
580138 | TR - N02 - ARCH
580559 | Toiture - Cuisine
580561 | Toiture - Cuisine
580565 | Toiture - Cuisine
580567 | Toiture - Cuisine
580569 | Toiture - Cuisine
580573 | Toiture - Cuisine
580575 | Toiture - Cuisine
580579 | Toiture - Cuisine
580583 | Toiture - Cuisine
580585 | Toiture - Cuisine
580587 | Toiture - Cuisine
580589 | Toiture - Cuisine
675647 | Toiture - Cuisine
581891 | N00 - COO
582468 | N00 - COO
661191 | N00 - COO | Material: Verre
1049387 | N00 - COO
582619 | N00 - COO
582816 | N00 - COO | Material: Verre
1049144 | N00 - COO
583636 | N00 - COO
583795 | N00 - COO | Material: Verre
1049899 | N00 - COO
583943 | N00 - COO | Material: Verre
1050099 | N00 - COO
584090 | N00 - COO | Material: Verre
1050246 | N00 - COO
584194 | N00 - COO
584479 | N00 - COO
584618 | N00 - COO
1051329 | N00 - COO
585312 | N00 - COO | Material: Verre
1330110 | N00 - COO
585506 | N00 - COO | Material: Verre
1052126 | N00 - COO
667115 | N00 - COO | Material: Verre
667118 | N00 - COO | Material: Verre
667120 | N00 - COO | Material: Verre
667122 | N00 - COO | Material: Verre
667124 | N00 - COO | Material: Verre
667126 | N00 - COO | Material: Verre
704948 | N00 - COO
705173 | N00 - COO
705375 | N00 - COO
705645 | N00 - COO
786514 | N00 - COO | Material: Verre
1160457 | N00 - COO | Material: Verre
787161 | N00 - COO
787265 | N00 - COO
787515 | N00 - COO
1160210 | N00 - COO | Material: Verre
791436 | N00 - COO | Pset_PlateCommon - IsExternal: yes
794865 | N00 - COO
1770982 | N00 - COO
839275 | N00 - COO
894792 | N00 - COO
919957 | N00 - COO
1665855 | Toiture - Cuisine | Pset_PlateCommon - IsExternal: yes
1665861 | Toiture - Cuisine | Pset_PlateCommon - IsExternal: yes
1665863 | Toiture - Cuisine | Pset_PlateCommon - IsExternal: yes
1665865 | Toiture - Cuisine | Pset_PlateCommon - IsExternal: yes
1665653 | Toiture - Cuisine | Pset_PlateCommon - IsExternal: yes
1665659 | Toiture - Cuisine | Pset_PlateCommon - IsExternal: yes
1665661 | Toiture - Cuisine | Pset_PlateCommon - IsExternal: yes
1665663 | Toiture - Cuisine | Pset_PlateCommon - IsExternal: yes
942824 | N00 - COO
1006479 | N00 - COO
1008929 | N00 - COO
1010333 | N00 - COO
1010535 | N00 - COO
1037221 | N00 - COO
1039315 | N00 - COO | Material: Verre
1161866 | N00 - COO
1045408 | N00 - COO
1185118 | N00 - COO
1136584 | N00 - COO
1045653 | N00 - COO
1058130 | N00 - COO
1124247 | N00 - COO
1124365 | N00 - COO
1138409 | N00 - COO | Material: Verre
1138414 | N00 - COO | Material: Verre
1138416 | N00 - COO | Material: Verre
1138418 | N00 - COO | Material: Verre
1138420 | N00 - COO | Material: Verre
1138422 | N00 - COO | Material: Verre
1138424 | N00 - COO | Material: Verre
1138426 | N00 - COO
1145637 | N00 - COO
1145643 | N00 - COO
1145645 | N00 - COO
1145647 | N00 - COO
1145649 | N00 - COO
1145651 | N00 - COO
1148465 | N00 - COO
1147422 | N00 - COO
1147424 | N00 - COO
1200139 | N00 - COO
1148958 | N00 - COO
1199368 | N00 - COO
1492844 | N00 - COO
1150219 | N00 - COO
1150225 | N00 - COO
1150227 | N00 - COO
1150229 | N00 - COO
1150231 | N00 - COO
1159116 | N00 - COO
1159541 | N00 - COO
1159610 | N00 - COO
1159762 | N00 - COO
1160916 | N00 - COO | Material: Verre
1161947 | N00 - COO | Material: Verre
1161953 | N00 - COO | Material: Verre
1196005 | N00 - COO | Material: Verre
667130 | N00 - COO | Material: Verre
667132 | N00 - COO
1199348 | N00 - COO
1199437 | N00 - COO
1203319 | N00 - COO
1209579 | N00 - COO
1204469 | N00 - COO
1204176 | N00 - COO
1204459 | N00 - COO
1204457 | N00 - COO
1203365 | N00 - COO
578658 | N00 - COO
578664 | N00 - COO
578666 | N00 - COO
578668 | N00 - COO
578670 | N00 - COO
1220076 | N00 - COO | Material: Verre
1671652 | Toiture - Cuisine | Pset_PlateCommon - IsExternal: yes; Group: Groupe de modèles:Retours BA 13 SELF / VERRIERE 2:1671562
1671658 | Toiture - Cuisine | Pset_PlateCommon - IsExternal: yes; Group: Groupe de modèles:Retours BA 13 SELF / VERRIERE 2:1671562
1671660 | Toiture - Cuisine | Pset_PlateCommon - IsExternal: yes; Group: Groupe de modèles:Retours BA 13 SELF / VERRIERE 2:1671562
1671662 | Toiture - Cuisine | Pset_PlateCommon - IsExternal: yes; Group: Groupe de modèles:Retours BA 13 SELF / VERRIERE 2:1671562

# IfcRailing: Garde-corps:Garde corps 1A0cmHT (10)
Material: Métal - Acier inoxydable, poli
Pset_QuantityTakeOff - Reference: Garde corps 1A0cmHT
Pset_RailingCommon - IsExternal: no; Reference: Garde corps 1A0cmHT; Height: 100 cm
Name (Garde-corps:Garde corps 1A0cmHT:...) | In
1821742 | Toiture - Cuisine
1822073 | TR - N02 - ARCH
1822122 | TR - N02 - ARCH
1822741 | TR - N02 - ARCH
1823136 | Toiture - Cuisine
1823526 | Toiture - Cuisine
1825912 | N00 - COO
1825916 | N00 - COO
1826393 | Toiture - Cuisine
1826397 | Toiture - Cuisine

# IfcRailing: Garde-corps:Garde corps accès cuisine (3)
In: N00 - COO
Material: Métal - Acier inoxydable, poli
Pset_QuantityTakeOff - Reference: Garde corps accès cuisine
Pset_RailingCommon - IsExternal: no; Reference: Garde corps accès cuisine; Height: 100 cm
Name (Garde-corps:Garde corps accès cuisine:...)
1123292
1196869
1971567

# IfcRailing: Garde-corps:Garde corps technique (2)
In: TR - TECHNIQUE RDC
Material: Métal - Acier inoxydable, poli
Pset_QuantityTakeOff - Reference: Garde corps technique
Pset_RailingCommon - IsExternal: no; Reference: Garde corps technique; Height: 100 cm
Name (Garde-corps:Garde corps technique:...)
1953625
1953629

# IfcRailing: Garde-corps:Garde-corps 1 (15)
Pset_QuantityTakeOff - Reference: Garde-corps 1
Pset_RailingCommon - IsExternal: no; Reference: Garde-corps 1; Height: 90 cm
Name (Garde-corps:Garde-corps 1:...) | In
544214 | N00 - COO
544218 | N00 - COO
547917 | Toiture - Cuisine
547921 | Toiture - Cuisine
549519 | Toiture - Cuisine
549523 | Toiture - Cuisine
549651 | N00 - COO
549655 | N00 - COO
848824 | N00 - COO
1365745 | Vide Sanitaire
1920925 | Toiture - Cuisine
1960165 | TR - N02 - ARCH
2083201 | Toiture - Cuisine
2083205 | Toiture - Cuisine
2083515 | N00 - COO

# IfcRoof: Couvertine ( infirmerie):Couvertine ( infirmerie), Couvertine ( infirmerie):Couvertine ( infirmerie):758388
In: Toiture - Infirmerie
Material: Aluminium
Pset_QuantityTakeOff - Reference: Couvertine ( infirmerie)
Pset_RoofCommon - IsExternal: yes; Reference: Couvertine ( infirmerie); TotalArea: 13.192 m2

# IfcRoof: Couvertine ( maintenance):Couvertine ( maintenance), Couvertine ( maintenance):Couvertine ( maintenance):756407
In: Toiture - Maintenance
Material: Aluminium
Pset_QuantityTakeOff - Reference: Couvertine ( maintenance)
Pset_RoofCommon - IsExternal: yes; Reference: Couvertine ( maintenance); TotalArea: 29.3605 m2

# IfcRoof: Couvertine 02 maintenance:Couvertine 02 maintenance, Couvertine 02 maintenance:Couvertine 02 maintenance:1399674
In: Toiture - Maintenance
Material: Aluminium
Pset_QuantityTakeOff - Reference: Couvertine 02 maintenance
Pset_RoofCommon - IsExternal: yes; Reference: Couvertine 02 maintenance; TotalArea: 2.93028 m2

# IfcRoof: Couvertine Self:Couvertine Self, Couvertine Self:Couvertine Self:752206
In: Toiture - Cuisine
Material: Aluminium
Pset_QuantityTakeOff - Reference: Couvertine Self
Pset_RoofCommon - IsExternal: yes; Reference: Couvertine Self; TotalArea: 121.049 m2

# IfcRoof: Couvertine edicule accès toiture du self1:Couvertine edicule accès toiture du self, Couvertine edicule accès toiture du self1:Couvertine edicule accès toiture du self:1879661
In: SAM - Toiture
Material: Aluminium
Pset_QuantityTakeOff - Reference: Couvertine edicule accès toiture du self
Pset_RoofCommon - IsExternal: yes; Reference: Couvertine edicule accès toiture du self; TotalArea: 2.72077 m2

# IfcRoof: Couvertine edicule accès toiture du self2:Couvertine edicule accès toiture du self, Couvertine edicule accès toiture du self2:Couvertine edicule accès toiture du self:1889812
In: SAM - Toiture
Material: Aluminium
Pset_QuantityTakeOff - Reference: Couvertine edicule accès toiture du self
Pset_RoofCommon - IsExternal: yes; Reference: Couvertine edicule accès toiture du self; TotalArea: 1.95912 m2

# IfcRoof: Couvertine edicule accès toiture du self3:Couvertine edicule accès toiture du self, Couvertine edicule accès toiture du self3:Couvertine edicule accès toiture du self:1889952
In: SAM - Toiture
Material: Aluminium
Pset_QuantityTakeOff - Reference: Couvertine edicule accès toiture du self
Pset_RoofCommon - IsExternal: yes; Reference: Couvertine edicule accès toiture du self; TotalArea: 7.29363 m2

# IfcRoof: Couvertine edicule accès toiture du self:Couvertine edicule accès toiture du self, Couvertine edicule accès toiture du self:Couvertine edicule accès toiture du self:854767
In: SAM - Toiture
Material: Aluminium
Pset_QuantityTakeOff - Reference: Couvertine edicule accès toiture du self
Pset_RoofCommon - IsExternal: yes; Reference: Couvertine edicule accès toiture du self; TotalArea: 3.10077 m2

# IfcRoof: Couvertine pignon1:Couvertine pignon, Couvertine pignon1:Couvertine pignon:712139
In: TR - N03
Material: Aluminium
Pset_QuantityTakeOff - Reference: Couvertine pignon
Pset_RoofCommon - IsExternal: yes; Reference: Couvertine pignon; TotalArea: 8.0981 m2

# IfcRoof: Couvertine pignon2:Couvertine pignon, Couvertine pignon2:Couvertine pignon:712161
In: TR - N03
Material: Aluminium
Pset_QuantityTakeOff - Reference: Couvertine pignon
Pset_RoofCommon - IsExternal: yes; Reference: Couvertine pignon; TotalArea: 3.89015 m2

# IfcRoof: Couvertine pignon3:Couvertine pignon, Couvertine pignon3:Couvertine pignon:712183
In: TR - N03
Material: Aluminium
Pset_QuantityTakeOff - Reference: Couvertine pignon
Pset_RoofCommon - IsExternal: yes; Reference: Couvertine pignon; TotalArea: 4.693 m2

# IfcRoof: Couvertine pignon:Couvertine pignon, Couvertine pignon:Couvertine pignon:712083
In: TR - N03
Material: Aluminium
Pset_QuantityTakeOff - Reference: Couvertine pignon
Pset_RoofCommon - IsExternal: yes; Reference: Couvertine pignon; TotalArea: 8.10279 m2

# IfcRoof: Couvertine self/preau:Couvertine self/preau, Couvertine self/preau:Couvertine self/preau:1069767
In: TR - Cuisine/préau
Material: Aluminium
Pset_QuantityTakeOff - Reference: Couvertine self/preau
Pset_RoofCommon - IsExternal: yes; Reference: Couvertine self/preau; TotalArea: 11.0831 m2

# IfcRoof: Couvertine:Couvertine, Couvertine:Couvertine:712061
In: TR - N03
Material: Aluminium
Pset_QuantityTakeOff - Reference: Couvertine
Pset_RoofCommon - IsExternal: yes; Reference: Couvertine; TotalArea: 212.002 m2

# IfcRoof: Toit de base:03 - Dalle 20 cm + isolant (5)
Pset_QuantityTakeOff - Reference: 03 - Dalle 20 cm + isolant
Pset_RoofCommon - IsExternal: yes; Reference: 03 - Dalle 20 cm + isolant
Name (Toit de base:03 - Dalle 20 cm + isolant:...) | In | ProjectedArea (m2) = TotalArea (m2)
236972 | Toiture - Cuisine | 478.861
622521 | Toiture - Cuisine | 77.6047
850408 | Toiture - Cuisine | 63.5174
1092681 | N00 - COO | 52.8873
1879534 | Toiture - Cuisine | 155.359

# IfcRoof: Toit de base:03 - Dalle 20 cm + isolant 5 cm (2)
In: Toiture - Cuisine
Pset_QuantityTakeOff - Reference: 03 - Dalle 20 cm + isolant 5 cm
Pset_RoofCommon - IsExternal: yes; Reference: 03 - Dalle 20 cm + isolant 5 cm
Name (Toit de base:03 - Dalle 20 cm + isolant 5 cm:...) | ProjectedArea (m2) = TotalArea (m2)
247957 | 167.947
251055 | 492.028

# IfcRoof: Toit de base:03 - Dalle 30 cm + isolant (2)
Pset_QuantityTakeOff - Reference: 03 - Dalle 30 cm + isolant
Pset_RoofCommon - IsExternal: yes; Reference: 03 - Dalle 30 cm + isolant
Name (Toit de base:03 - Dalle 30 cm + isolant:...) | In | ProjectedArea (m2) | TotalArea (m2)
206667 | TR - N03 - ARCH | 1579.16 | 1575.91
234853 | Toiture - Cuisine | 141.702 | 141.702

# IfcRoof: Toit de base:03 - Dalle bac acier, Toit de base:03 - Dalle bac acier:1606061
In: N00 - COO
Pset_QuantityTakeOff - Reference: 03 - Dalle bac acier
Pset_RoofCommon - IsExternal: yes; Reference: 03 - Dalle bac acier; ProjectedArea: 428.727 m2; TotalArea: 412.531 m2

# IfcRoof: Toit de base:03 - Dalle isolant, Toit de base:03 - Dalle isolant:242657
In: N00 - COO
Pset_QuantityTakeOff - Reference: 03 - Dalle isolant
Pset_RoofCommon - IsExternal: yes; Reference: 03 - Dalle isolant; ProjectedArea: 423.784 m2; TotalArea: 405.337 m2

# IfcRoof: Toit de base:03 - Végétalisation (2)
In: Toiture - Cuisine
Pset_QuantityTakeOff - Reference: 03 - Végétalisation
Pset_RoofCommon - IsExternal: yes; Reference: 03 - Végétalisation
Name (Toit de base:03 - Végétalisation:...) | ProjectedArea (m2) = TotalArea (m2)
248021 | 127.704
251554 | 363.595

# IfcRoof: Toit de base:03 - gravillons (5)
Pset_QuantityTakeOff - Reference: 03 - gravillons
Pset_RoofCommon - IsExternal: yes; Reference: 03 - gravillons
Name (Toit de base:03 - gravillons:...) | In | ProjectedArea (m2) | TotalArea (m2)
249391 | Toiture - Cuisine | 167.947 | 40.2427
689882 | Toiture - Cuisine | 445.186 | 81.5904
1978137 | Toiture - Maintenance | 475.273 | 475.273
1978196 | Toiture - Maintenance | 141.702 | 141.702
2003707 | Toiture - Maintenance | 64.3414 | 64.3414

# IfcRoof: Vitres inclinées:Toit en verre 1 m x 2 m (5)
Type - Pset_CurtainWallCommon - IsExternal: yes; Reference: Toit en verre 1 m x 2 m
Type - Pset_QuantityTakeOff - Reference: Toit en verre 1 m x 2 m
Pset_RoofCommon - IsExternal: yes; Reference: Toit en verre 1 m x 2 m
Name (Vitres inclinées:Toit en verre 1 m x 2 m:...) | In | ProjectedArea (m2)
220573 | TR - N03 - ARCH | 63.5241
253997 | Toiture - Cuisine | 31.5
932745 | Toiture - Cuisine | 5.05526
932878 | Toiture - Cuisine | 5.05526
1671568 | Toiture - Cuisine | 5.05526 | Group: Groupe de modèles:Retours BA 13 SELF / VERRIERE 2:1671562

# IfcSlab: Couvertine ( infirmerie):Couvertine ( infirmerie), Couvertine ( infirmerie):Couvertine ( infirmerie):758388:1
In: Toiture - Infirmerie
PredefinedType: ROOF; Material: Aluminium
Pset_QuantityTakeOff - Reference: Couvertine ( infirmerie); sets with these values: 2
Pset_SlabCommon - PitchAngle: 0 deg; IsExternal: yes; Reference: Couvertine ( infirmerie)

# IfcSlab: Couvertine edicule accès toiture du self1:Couvertine edicule accès toiture du self, Couvertine edicule accès toiture du self1:Couvertine edicule accès toiture du self:1879661:1
In: SAM - Toiture
PredefinedType: ROOF; Material: Aluminium
Pset_QuantityTakeOff - Reference: Couvertine edicule accès toiture du self; sets with these values: 2
Pset_SlabCommon - PitchAngle: 0 deg; IsExternal: yes; Reference: Couvertine edicule accès toiture du self

# IfcSlab: Couvertine edicule accès toiture du self2:Couvertine edicule accès toiture du self, Couvertine edicule accès toiture du self2:Couvertine edicule accès toiture du self:1889812:1
In: SAM - Toiture
PredefinedType: ROOF; Material: Aluminium
Pset_QuantityTakeOff - Reference: Couvertine edicule accès toiture du self; sets with these values: 2
Pset_SlabCommon - PitchAngle: 0 deg; IsExternal: yes; Reference: Couvertine edicule accès toiture du self

# IfcSlab: Couvertine edicule accès toiture du self3:Couvertine edicule accès toiture du self, Couvertine edicule accès toiture du self3:Couvertine edicule accès toiture du self:1889952:1
In: SAM - Toiture
PredefinedType: ROOF; Material: Aluminium
Pset_QuantityTakeOff - Reference: Couvertine edicule accès toiture du self; sets with these values: 2
Pset_SlabCommon - PitchAngle: 0 deg; IsExternal: yes; Reference: Couvertine edicule accès toiture du self

# IfcSlab: Couvertine edicule accès toiture du self:Couvertine edicule accès toiture du self, Couvertine edicule accès toiture du self:Couvertine edicule accès toiture du self:854767:1
In: SAM - Toiture
PredefinedType: ROOF; Material: Aluminium
Pset_QuantityTakeOff - Reference: Couvertine edicule accès toiture du self; sets with these values: 2
Pset_SlabCommon - PitchAngle: 0 deg; IsExternal: yes; Reference: Couvertine edicule accès toiture du self

# IfcSlab: Couvertine pignon1:Couvertine pignon, Couvertine pignon1:Couvertine pignon:712139:1
In: TR - N03
PredefinedType: ROOF; Material: Aluminium
Pset_QuantityTakeOff - Reference: Couvertine pignon; sets with these values: 2
Pset_SlabCommon - PitchAngle: 0 deg; IsExternal: yes; Reference: Couvertine pignon

# IfcSlab: Couvertine pignon2:Couvertine pignon, Couvertine pignon2:Couvertine pignon:712161:1
In: TR - N03
PredefinedType: ROOF; Material: Aluminium
Pset_QuantityTakeOff - Reference: Couvertine pignon; sets with these values: 2
Pset_SlabCommon - PitchAngle: 0 deg; IsExternal: yes; Reference: Couvertine pignon

# IfcSlab: Couvertine pignon3:Couvertine pignon, Couvertine pignon3:Couvertine pignon:712183:1
In: TR - N03
PredefinedType: ROOF; Material: Aluminium
Pset_QuantityTakeOff - Reference: Couvertine pignon; sets with these values: 2
Pset_SlabCommon - PitchAngle: 0 deg; IsExternal: yes; Reference: Couvertine pignon

# IfcSlab: Couvertine pignon:Couvertine pignon, Couvertine pignon:Couvertine pignon:712083:1
In: TR - N03
PredefinedType: ROOF; Material: Aluminium
Pset_QuantityTakeOff - Reference: Couvertine pignon; sets with these values: 2
Pset_SlabCommon - PitchAngle: 0 deg; IsExternal: yes; Reference: Couvertine pignon

# IfcSlab: Palier monobloc:Epaisseur 150 mm (11)
PredefinedType: LANDING; Material: Maçonnerie - Béton
Pset_QuantityTakeOff - Reference: Epaisseur 150 mm; sets with these values: 2
Pset_SlabCommon - IsExternal: no; PitchAngle: 0 deg; Reference: Epaisseur 150 mm
Name (Escalier coulé sur place:Escalier:...) | In
223221 Landing 1 | Toiture - Cuisine
542505 Landing 1 | N00 - COO
547910 Landing 1 | Toiture - Cuisine
549512 Landing 1 | Toiture - Cuisine
549644 Landing 1 | N00 - COO
1812443 Landing 1 | N00 - COO
1870163 Landing 1 | N00 - COO
1870163 Landing 2 | N00 - COO
1870163 Landing 3 | N00 - COO
1920743 Landing 1 | Toiture - Cuisine
1920743 Landing 2 | Toiture - Cuisine

# IfcSlab: Palier non-monobloc:Palier non-monobloc (3)
PredefinedType: LANDING
Pset_QuantityTakeOff - Reference: Palier non-monobloc; sets with these values: 2
Pset_SlabCommon - IsExternal: no; PitchAngle: 0 deg; Reference: Palier non-monobloc
Name (Escalier assemblé:Escalier:...) | In
1886925 Landing 1 | TR - TECHNIQUE RDC
1886925 Landing 2 | TR - TECHNIQUE RDC
1955995 Landing 1 | TR - TECHNIQUE R+1

# IfcSlab: Sol:02 - Dalle épine (4)
Type - PredefinedType: FLOOR; Material: Metal - Steel - ASTM A36 15 cm
Type - Pset_QuantityTakeOff - Reference: 02 - Dalle épine
Type - Pset_ReinforcementBarPitchOfSlab - Reference: 02 - Dalle épine
Type - Pset_SlabCommon - IsExternal: no; Reference: 02 - Dalle épine
Pset_QuantityTakeOff - sets with these values: 2
Pset_SlabCommon - LoadBearing: no; PitchAngle: 0 deg
Name (Sol:02 - Dalle épine:...) | In
865600 | TR - N02 - ARCH
866298 | TR - N03 - ARCH
866328 | TR - N02 - ARCH
866626 | TR - N03 - ARCH

# IfcSlab: Sol:02 - Isolation en sous-face 16cm (4)
In: Toiture - Cuisine
Type - PredefinedType: FLOOR; Material: 00 - Isolant 16 cm
Type - Pset_QuantityTakeOff - Reference: 02 - Isolation en sous-face 16cm
Type - Pset_ReinforcementBarPitchOfSlab - Reference: 02 - Isolation en sous-face 16cm
Type - Pset_SlabCommon - IsExternal: no; Reference: 02 - Isolation en sous-face 16cm; ThermalTransmittance: 0.2375 kg/K/s3
Pset_QuantityTakeOff - sets with these values: 2
Pset_SlabCommon - LoadBearing: no; PitchAngle: 0 deg
Name (Sol:02 - Isolation en sous-face 16cm:...)
1432587
1521203
1522626
1524022

# IfcSlab: Sol:02 - SOL VS, Sol:02 - SOL VS:1729659
In: Vide Sanitaire
Type - PredefinedType: FLOOR; Material: Umgebung - Gras 15 cm
Type - Pset_QuantityTakeOff - Reference: 02 - SOL VS
Type - Pset_ReinforcementBarPitchOfSlab - Reference: 02 - SOL VS
Type - Pset_SlabCommon - IsExternal: no; Reference: 02 - SOL VS
Pset_QuantityTakeOff - sets with these values: 2
Pset_SlabCommon - LoadBearing: no; PitchAngle: 0 deg; IsExternal: yes

# IfcSlab: Sol:02 - Tablette bois 2cm (4)
Type - PredefinedType: FLOOR; Material: Bois tablettes 2 cm
Type - Pset_QuantityTakeOff - Reference: 02 - Tablette bois 2cm
Type - Pset_ReinforcementBarPitchOfSlab - Reference: 02 - Tablette bois 2cm
Type - Pset_SlabCommon - IsExternal: no; Reference: 02 - Tablette bois 2cm; ThermalTransmittance: 6 kg/K/s3
Pset_QuantityTakeOff - sets with these values: 2
Pset_SlabCommon - LoadBearing: no; PitchAngle: 0 deg
Name (Sol:02 - Tablette bois 2cm:...) | In
1245261:7 | TR - N02 - ARCH
1245848:9 | Toiture - Cuisine
1246004:9 | Toiture - Cuisine
1246065:10 | TR - N02 - ARCH

# IfcSlab: Sol:02 - Tablette bois 2cm (31)
Type - PredefinedType: FLOOR
Type - Pset_QuantityTakeOff - Reference: 02 - Tablette bois 2cm
Type - Pset_ReinforcementBarPitchOfSlab - Reference: 02 - Tablette bois 2cm
Type - Pset_SlabCommon - IsExternal: no; Reference: 02 - Tablette bois 2cm; ThermalTransmittance: 6 kg/K/s3
Material: Bois tablettes 2 cm
Pset_QuantityTakeOff - sets with these values: 2
Pset_SlabCommon - LoadBearing: no; PitchAngle: 0 deg
Name (Sol:02 - Tablette bois 2cm:...) | In
1245261 | TR - N02 - ARCH
1245261:2 | TR - N02 - ARCH
1245261:3 | TR - N02 - ARCH
1245261:4 | TR - N02 - ARCH
1245261:5 | TR - N02 - ARCH
1245261:6 | TR - N02 - ARCH
1245848 | Toiture - Cuisine
1245848:2 | Toiture - Cuisine
1245848:3 | Toiture - Cuisine
1245848:4 | Toiture - Cuisine
1245848:5 | Toiture - Cuisine
1245848:6 | Toiture - Cuisine
1245848:7 | Toiture - Cuisine
1245848:8 | Toiture - Cuisine
1246004 | Toiture - Cuisine
1246004:2 | Toiture - Cuisine
1246004:3 | Toiture - Cuisine
1246004:4 | Toiture - Cuisine
1246004:5 | Toiture - Cuisine
1246004:6 | Toiture - Cuisine
1246004:7 | Toiture - Cuisine
1246004:8 | Toiture - Cuisine
1246065 | TR - N02 - ARCH
1246065:2 | TR - N02 - ARCH
1246065:3 | TR - N02 - ARCH
1246065:4 | TR - N02 - ARCH
1246065:5 | TR - N02 - ARCH
1246065:6 | TR - N02 - ARCH
1246065:7 | TR - N02 - ARCH
1246065:8 | TR - N02 - ARCH
1246065:9 | TR - N02 - ARCH

# IfcSlab: Sol:02 - dalle béton 20cm (2)
In: N00 - COO
Type - PredefinedType: FLOOR; Material: 01 - Maçonnerie 20 cm
Type - Pset_QuantityTakeOff - Reference: 02 - dalle béton 20cm
Type - Pset_ReinforcementBarPitchOfSlab - Reference: 02 - dalle béton 20cm
Type - Pset_SlabCommon - IsExternal: no; Reference: 02 - dalle béton 20cm; ThermalTransmittance: 5.23 kg/K/s3
Pset_QuantityTakeOff - sets with these values: 2
Pset_SlabCommon - LoadBearing: no; PitchAngle: 0 deg
Name (Sol:02 - dalle béton 20cm:...)
198674
199469

# IfcSlab: Sol:02 - dalle béton 20cm + chape 6cm, Sol:02 - dalle béton 20cm + chape 6cm:35864
In: N00 - COO
Type - PredefinedType: FLOOR
Type - Pset_QuantityTakeOff - Reference: 02 - dalle béton 20cm + chape 6cm
Type - Pset_ReinforcementBarPitchOfSlab - Reference: 02 - dalle béton 20cm + chape 6cm
Type - Pset_SlabCommon - Reference: 02 - dalle béton 20cm + chape 6cm; IsExternal: no; ThermalTransmittance: 4.02308 kg/K/s3
Material: Béton, coulé sur place, 01 - Maçonnerie
Pset_QuantityTakeOff - sets with these values: 2
Pset_SlabCommon - LoadBearing: no

# IfcSlab: Sol:02 - dalle béton 20cm + finition 1cm (3)
Type - PredefinedType: FLOOR; Material: Béton, coulé sur place 1 cm, 01 - Maçonnerie 20 cm
Type - Pset_QuantityTakeOff - Reference: 02 - dalle béton 20cm + finition 1cm
Type - Pset_ReinforcementBarPitchOfSlab - Reference: 02 - dalle béton 20cm + finition 1cm
Type - Pset_SlabCommon - IsExternal: no; Reference: 02 - dalle béton 20cm + finition 1cm; ThermalTransmittance: 4.98095 kg/K/s3
Pset_QuantityTakeOff - sets with these values: 2
Pset_SlabCommon - LoadBearing: no
Name (Sol:02 - dalle béton 20cm + finition 1cm:...) | In | PitchAngle (deg)
883528:3 | TR - N02 - ARCH | 0
1888885:2 | Toiture - Cuisine | 0
2141163 | Toiture - Cuisine

# IfcSlab: Sol:02 - dalle béton 20cm + finition 1cm (3)
Type - PredefinedType: FLOOR
Type - Pset_QuantityTakeOff - Reference: 02 - dalle béton 20cm + finition 1cm
Type - Pset_ReinforcementBarPitchOfSlab - Reference: 02 - dalle béton 20cm + finition 1cm
Type - Pset_SlabCommon - IsExternal: no; Reference: 02 - dalle béton 20cm + finition 1cm; ThermalTransmittance: 4.98095 kg/K/s3
Material: Béton, coulé sur place 1 cm, 01 - Maçonnerie 20 cm
Pset_QuantityTakeOff - sets with these values: 2
Pset_SlabCommon - LoadBearing: no; PitchAngle: 0 deg
Name (Sol:02 - dalle béton 20cm + finition 1cm:...) | In
883528 | TR - N02 - ARCH
883528:2 | TR - N02 - ARCH
1888885 | Toiture - Cuisine

# IfcSlab: Sol:02 - dalle béton 30cm + finition 1cm (2)
Type - PredefinedType: FLOOR; Material: Béton, coulé sur place 1 cm, 01 - Maçonnerie 30 cm
Type - Pset_QuantityTakeOff - Reference: 02 - dalle béton 30cm + finition 1cm
Type - Pset_ReinforcementBarPitchOfSlab - Reference: 02 - dalle béton 30cm + finition 1cm
Type - Pset_SlabCommon - IsExternal: no; Reference: 02 - dalle béton 30cm + finition 1cm; ThermalTransmittance: 3.37419 kg/K/s3
Pset_QuantityTakeOff - sets with these values: 2
Pset_SlabCommon - LoadBearing: no
Name (Sol:02 - dalle béton 30cm + finition 1cm:...) | In
42359:4 | Toiture - Cuisine | Pset_SlabCommon - PitchAngle: 0 deg
44971 | TR - N02 - ARCH

# IfcSlab: Sol:02 - dalle béton 30cm + finition 1cm (3)
In: Toiture - Cuisine
Type - PredefinedType: FLOOR
Type - Pset_QuantityTakeOff - Reference: 02 - dalle béton 30cm + finition 1cm
Type - Pset_ReinforcementBarPitchOfSlab - Reference: 02 - dalle béton 30cm + finition 1cm
Type - Pset_SlabCommon - IsExternal: no; Reference: 02 - dalle béton 30cm + finition 1cm; ThermalTransmittance: 3.37419 kg/K/s3
Material: Béton, coulé sur place 1 cm, 01 - Maçonnerie 30 cm
Pset_QuantityTakeOff - sets with these values: 2
Pset_SlabCommon - LoadBearing: no; PitchAngle: 0 deg
Name (Sol:02 - dalle béton 30cm + finition 1cm:...)
42359
42359:2
42359:3

# IfcSlab: Sol:12 - zone plantée, Sol:12 - zone plantée:1062500
In: N00 - COO
Type - PredefinedType: FLOOR; Material: Herbe 15 cm
Type - Pset_QuantityTakeOff - Reference: 12 - zone plantée
Type - Pset_ReinforcementBarPitchOfSlab - Reference: 12 - zone plantée
Type - Pset_SlabCommon - IsExternal: no; Reference: 12 - zone plantée
Pset_QuantityTakeOff - sets with these values: 2
Pset_SlabCommon - LoadBearing: no; PitchAngle: 0 deg

# IfcSlab: Sol:SR- 02 - Isolation sur terre plein sous chape - 9cm, Sol:SR- 02 - Isolation sur terre plein sous chape - 9cm:200539
In: N00 - COO
Type - PredefinedType: FLOOR; Material: 00 - Isolant 9 cm
Type - Pset_QuantityTakeOff - Reference: SR- 02 - Isolation sur terre plein sous chape - 9cm
Type - Pset_ReinforcementBarPitchOfSlab - Reference: SR- 02 - Isolation sur terre plein sous chape - 9cm
Type - Pset_SlabCommon - IsExternal: no; Reference: SR- 02 - Isolation sur terre plein sous chape - 9cm; ThermalTransmittance: 0.422222 kg/K/s3
Pset_QuantityTakeOff - sets with these values: 2
Pset_SlabCommon - LoadBearing: no

# IfcSlab: Toit de base:03 - Dalle 20 cm + isolant (5)
PredefinedType: ROOF; Material: 00 - Isolant 16 cm, 01 - Maçonnerie 20 cm
Pset_QuantityTakeOff - Reference: 03 - Dalle 20 cm + isolant; sets with these values: 2
Pset_SlabCommon - PitchAngle: 0 deg; IsExternal: yes; Reference: 03 - Dalle 20 cm + isolant; ThermalTransmittance: 0.227183 kg/K/s3
Name (Toit de base:03 - Dalle 20 cm + isolant:...) | In
236972 | Toiture - Cuisine
622521 | Toiture - Cuisine
850408 | Toiture - Cuisine
1092681 | N00 - COO
1879534 | Toiture - Cuisine

# IfcSlab: Toit de base:03 - Dalle 20 cm + isolant 5 cm (2)
In: Toiture - Cuisine
PredefinedType: ROOF; Material: 00 - Isolant 5 cm, 01 - Maçonnerie 20 cm
Pset_QuantityTakeOff - Reference: 03 - Dalle 20 cm + isolant 5 cm; sets with these values: 2
Pset_SlabCommon - PitchAngle: 0 deg; IsExternal: yes; Reference: 03 - Dalle 20 cm + isolant 5 cm; ThermalTransmittance: 0.663573 kg/K/s3
Name (Toit de base:03 - Dalle 20 cm + isolant 5 cm:...)
247957
251055

# IfcSlab: Toit de base:03 - Dalle 30 cm + isolant (2)
PredefinedType: ROOF
Pset_QuantityTakeOff - Reference: 03 - Dalle 30 cm + isolant; sets with these values: 2
Pset_SlabCommon - PitchAngle: 0 deg; IsExternal: yes; Reference: 03 - Dalle 30 cm + isolant; ThermalTransmittance: 0.222354 kg/K/s3
Name (Toit de base:03 - Dalle 30 cm + isolant:...) | In | Material
206667:1 | TR - N03 - ARCH | 01 - Maçonnerie; 00 - Isolant 16 cm, 01 - Maçonnerie 30 cm
234853 | Toiture - Cuisine | 00 - Isolant 16 cm, 01 - Maçonnerie 30 cm

# IfcSlab: Toit de base:03 - Dalle bac acier, Toit de base:03 - Dalle bac acier:1606061:1
In: N00 - COO
PredefinedType: ROOF; Material: Acier au carbone; Acier au carbone 4.5 cm
Pset_QuantityTakeOff - Reference: 03 - Dalle bac acier; sets with these values: 2
Pset_SlabCommon - PitchAngle: 0 deg; IsExternal: yes; Reference: 03 - Dalle bac acier

# IfcSlab: Toit de base:03 - Dalle isolant, Toit de base:03 - Dalle isolant:242657:1
In: N00 - COO
PredefinedType: ROOF; Material: 00 - Isolant; 00 - Isolant 16 cm
Pset_QuantityTakeOff - Reference: 03 - Dalle isolant; sets with these values: 2
Pset_SlabCommon - PitchAngle: 0 deg; IsExternal: yes; Reference: 03 - Dalle isolant; ThermalTransmittance: 0.2375 kg/K/s3

# IfcSlab: Toit de base:03 - Végétalisation (2)
In: Toiture - Cuisine
PredefinedType: ROOF; Material: Herbe 12 cm
Pset_QuantityTakeOff - Reference: 03 - Végétalisation; sets with these values: 2
Pset_SlabCommon - PitchAngle: 0 deg; IsExternal: yes; Reference: 03 - Végétalisation
Name (Toit de base:03 - Végétalisation:...)
248021
251554

# IfcSlab: Toit de base:03 - gravillons (5)
PredefinedType: ROOF
Pset_QuantityTakeOff - Reference: 03 - gravillons; sets with these values: 2
Pset_SlabCommon - PitchAngle: 0 deg; IsExternal: yes; Reference: 03 - gravillons
Name (Toit de base:03 - gravillons:...) | In | Material
249391:1 | Toiture - Cuisine | Gravillons; Gravillons 10 cm
689882:1 | Toiture - Cuisine | Gravillons; Gravillons 10 cm
1978137 | Toiture - Maintenance | Gravillons 10 cm
1978196 | Toiture - Maintenance | Gravillons 10 cm
2003707 | Toiture - Maintenance | Gravillons 10 cm

# IfcStair: Escalier assemblé:Escalier assemblé (2)
Pset_QuantityTakeOff - Reference: Escalier assemblé
Pset_StairCommon - IsExternal: no; Reference: Escalier assemblé; TreadLength: 28 cm
Name (Escalier assemblé:Escalier:...) | In | NumberOfRiser | NumberOfTreads | RiserHeight (cm)
1886925 | TR - TECHNIQUE RDC | 18 | 16 | 17.875
1955995 | TR - TECHNIQUE R+1 | 3 | 2 | 15.8365

# IfcStair: Escalier coulé sur place:Monobloc (10)
Pset_QuantityTakeOff - Reference: Monobloc
Pset_StairCommon - IsExternal: no; Reference: Monobloc
Name (Escalier coulé sur place:Escalier:...) | In | NumberOfRiser | NumberOfTreads | RiserHeight (cm) | TreadLength (cm)
223221 | Toiture - Cuisine | 22 | 20 | 16 | 28
542505 | N00 - COO | 26 | 24 | 16.88 | 28
547910 | Toiture - Cuisine | 22 | 20 | 16.7619 | 28
549512 | Toiture - Cuisine | 22 | 20 | 16.7619 | 28
549644 | N00 - COO | 26 | 24 | 16.88 | 28
848786 | N00 - COO | 21 | 20 | 16.88 | 30.24
1365711 | Vide Sanitaire | 15 | 14 | 15.8333 | 32.3333
1812443 | N00 - COO | 25 | 23 | 16.88 | 28
1870163 | N00 - COO | 27 | 24 | 15.6296 | 28
1920743 | Toiture - Cuisine | 23 | 20 | 16.12 | 28

# IfcStairFlight: Volée monobloc:Profondeur de structure 80 mm (20)
Material: Maçonnerie - Béton
Pset_QuantityTakeOff - Reference: Profondeur de structure 80 mm
Pset_StairFlightCommon - Reference: Profondeur de structure 80 mm; NosingLength: 0 cm
Name (Escalier coulé sur place:Escalier:...) | In | NumberOfRiser | NumberOfTreads | RiserHeight (cm) | TreadLength (cm) | Pset_StairFlightCommon, NumberOfRiser | Pset_StairFlightCommon, NumberOfTreads | Pset_StairFlightCommon, RiserHeight (cm) | Pset_StairFlightCommon, TreadLength (cm) = TreadLengthAtOffset (cm) | WalkingLineOffset (cm) | WaistThickness (cm)
223221 Run 1 | Toiture - Cuisine | 9 | 8 | 0.524934 | 0.918635 | 22 | 20 | 16 | 28 | 152.5 | 305
223221 Run 2 | Toiture - Cuisine | 13 | 12 | 0.524934 | 0.918635 | 22 | 20 | 16 | 28 | 152.5 | 305
542505 Run 1 | N00 - COO | 13 | 12 | 0.553806 | 0.918635 | 26 | 24 | 16.88 | 28 | 90 | 180
542505 Run 2 | N00 - COO | 13 | 12 | 0.553806 | 0.918635 | 26 | 24 | 16.88 | 28 | 90 | 180
547910 Run 1 | Toiture - Cuisine | 11 | 10 | 0.549931 | 0.918635 | 22 | 20 | 16.7619 | 28 | 90 | 180
547910 Run 2 | Toiture - Cuisine | 11 | 10 | 0.549931 | 0.918635 | 22 | 20 | 16.7619 | 28 | 90 | 180
549512 Run 1 | Toiture - Cuisine | 11 | 10 | 0.549931 | 0.918635 | 22 | 20 | 16.7619 | 28 | 95 | 190
549512 Run 2 | Toiture - Cuisine | 11 | 10 | 0.549931 | 0.918635 | 22 | 20 | 16.7619 | 28 | 95 | 190
549644 Run 1 | N00 - COO | 16 | 15 | 0.553806 | 0.918635 | 26 | 24 | 16.88 | 28 | 95 | 190
549644 Run 2 | N00 - COO | 10 | 9 | 0.553806 | 0.918635 | 26 | 24 | 16.88 | 28 | 95 | 190
848786 Run 1 | N00 - COO | 21 | 20 | 0.553806 | 0.992126 | 21 | 20 | 16.88 | 30.24
1365711 Run 1 | Vide Sanitaire | 15 | 14 | 0.519466 | 1.0608 | 15 | 14 | 15.8333 | 32.3333
1812443 Run 1 | N00 - COO | 14 | 13 | 0.553806 | 0.918635 | 25 | 23 | 16.88 | 28 | 152.5 | 305
1812443 Run 2 | N00 - COO | 11 | 10 | 0.553806 | 0.918635 | 25 | 23 | 16.88 | 28 | 152.5 | 305
1870163 Run 1 | N00 - COO | 9 | 8 | 0.512783 | 0.918635 | 27 | 24 | 15.6296 | 28 | 90 | 180
1870163 Run 2 | N00 - COO | 9 | 8 | 0.512783 | 0.918635 | 27 | 24 | 15.6296 | 28 | 90 | 180
1870163 Run 3 | N00 - COO | 9 | 8 | 0.512783 | 0.918635 | 27 | 24 | 15.6296 | 28 | 90 | 180
1920743 Run 1 | Toiture - Cuisine | 10 | 9 | 0.528871 | 0.918635 | 23 | 20 | 16.12 | 28 | 90 | 180
1920743 Run 2 | Toiture - Cuisine | 10 | 9 | 0.528871 | 0.918635 | 23 | 20 | 16.12 | 28 | 90 | 180
1920743 Run 3 | Toiture - Cuisine | 3 | 2 | 0.528871 | 0.918635 | 23 | 20 | 16.12 | 28 | 90 | 180

# IfcStairFlight: Volée non-monobloc:Marche 50 mm Contremarche 13 mm (3)
TreadLength: 0.918635 cm
Pset_QuantityTakeOff - Reference: Marche 50 mm Contremarche 13 mm
Pset_StairFlightCommon - NosingLength: 0 cm; Reference: Marche 50 mm Contremarche 13 mm; TreadLength: 28 cm; WalkingLineOffset: 50 cm; TreadLengthAtOffset: 28 cm; WaistThickness: 100 cm
Name (Escalier assemblé:Escalier:...) | In | NumberOfRiser | NumberOfTreads | RiserHeight (cm) | Pset_StairFlightCommon, NumberOfRiser | Pset_StairFlightCommon, NumberOfTreads | Pset_StairFlightCommon, RiserHeight (cm)
1886925 Run 1 | TR - TECHNIQUE RDC | 15 | 14 | 0.58645 | 18 | 16 | 17.875
1886925 Run 2 | TR - TECHNIQUE RDC | 3 | 2 | 0.58645 | 18 | 16 | 17.875
1955995 Run 1 | TR - TECHNIQUE R+1 | 3 | 2 | 0.519569 | 3 | 2 | 15.8365

# IfcTransportElement: KONE_Buffer_Design_OIL (2)
In: N00 - COO
Type - Pset_QuantityTakeOff - Reference: KONE_Buffer_Design_OIL
Type - Pset_TransportElementCommon - Reference: KONE_Buffer_Design_OIL
OperationType: ELEVATOR; CapacityByWeight: 0 kg; CapacityByNumber: 0
Pset_QuantityTakeOff - sets with these values: 2
Name
KONE_Buffer_Design_OIL_CAR:KONE_Buffer_Design_OIL:1874043
KONE_Buffer_Design_OIL_CWT:KONE_Buffer_Design_OIL:1874044

# IfcTransportElement: KONE_CWT, KONE_CWT:KONE_CWT:1874041
In: N00 - COO
Type - Pset_QuantityTakeOff - Reference: KONE_CWT
Type - Pset_TransportElementCommon - Reference: KONE_CWT
OperationType: ELEVATOR; CapacityByWeight: 0 kg; CapacityByNumber: 0
Pset_QuantityTakeOff - sets with these values: 2

# IfcTransportElement: KONE_CWT_guiderail (2)
In: N00 - COO
Type - Pset_QuantityTakeOff - Reference: KONE_CWT_guiderail
Type - Pset_TransportElementCommon - Reference: KONE_CWT_guiderail
OperationType: ELEVATOR; CapacityByWeight: 0 kg; CapacityByNumber: 0
Pset_QuantityTakeOff - sets with these values: 2
Name (KONE_CWT_guiderail:KONE_CWT_guiderail:...)
1874034
1874035

# IfcTransportElement: KONE_Car, KONE_Car:KONE_Car:1874038
In: B-22
Type - Pset_QuantityTakeOff - Reference: KONE_Car
Type - Pset_TransportElementCommon - Reference: KONE_Car
OperationType: ELEVATOR; CapacityByWeight: 0 kg; CapacityByNumber: 0
Pset_QuantityTakeOff - sets with these values: 2

# IfcTransportElement: KONE_Car_Door_2L, KONE_Car_Door_2L:KONE_Car_Door_2L:1874040
In: B-22
Type - Pset_QuantityTakeOff - Reference: KONE_Car_Door_2L
Type - Pset_TransportElementCommon - Reference: KONE_Car_Door_2L
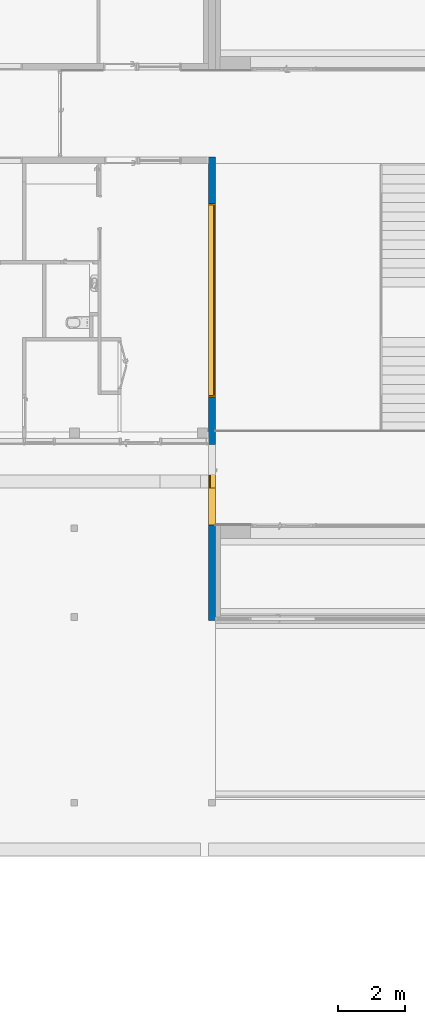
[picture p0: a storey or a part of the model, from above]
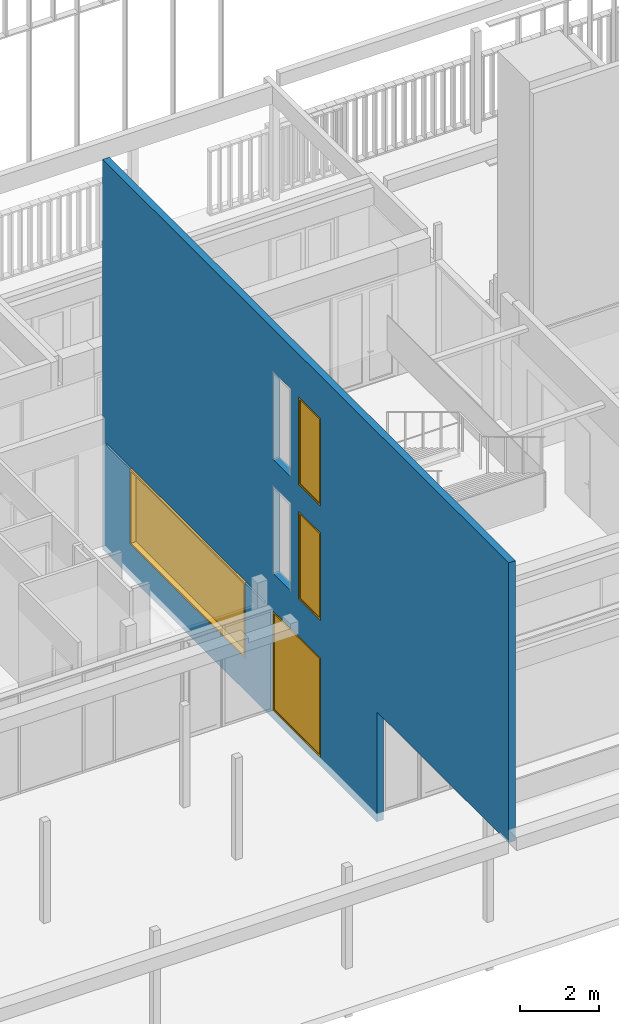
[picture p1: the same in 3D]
Properties of the parts of a building model (IFC2X3), part 6 of 7

# IfcTransportElement: KONE_Car_Door_2L, KONE_Car_Door_2L:KONE_Car_Door_2L:1874040
OperationType: ELEVATOR; CapacityByWeight: 0 kg; CapacityByNumber: 0
Pset_QuantityTakeOff - sets with these values: 2

# IfcTransportElement: KONE_Car_guiderail (2)
In: N00 - COO
Type - Pset_QuantityTakeOff - Reference: KONE_Car_guiderail
Type - Pset_TransportElementCommon - Reference: KONE_Car_guiderail
OperationType: ELEVATOR; CapacityByWeight: 0 kg; CapacityByNumber: 0
Pset_QuantityTakeOff - sets with these values: 2
Name (KONE_Car_guiderail:KONE_Car_guiderail:...)
1874036
1874037

# IfcTransportElement: KONE_LDO_Design_2L_P10 (3)
Type - Material: Default
Type - Pset_QuantityTakeOff - Reference: KONE_LDO_Design_2L_P10
Type - Pset_TransportElementCommon - Reference: KONE_LDO_Design_2L_P10
OperationType: ELEVATOR; CapacityByWeight: 0 kg; CapacityByNumber: 0
Pset_QuantityTakeOff - sets with these values: 2
Name (KONE_LDO_Design_2L_P10:KONE_LDO_Design_2L_P10:...) | In
1874045 | B-22
1874046 | N00 - COO
1874047 | N00 - COO

# IfcTransportElement: KONE_MACHINE_NMX07_MONO, KONE_MACHINE_NMX07_MONO:KONE_MACHINE_NMX07_MONO:1874039
In: N00 - COO
Type - Material: Machine_Green
Type - Pset_QuantityTakeOff - Reference: KONE_MACHINE_NMX07_MONO
Type - Pset_TransportElementCommon - Reference: KONE_MACHINE_NMX07_MONO
OperationType: ELEVATOR; CapacityByWeight: 0 kg; CapacityByNumber: 0
Pset_QuantityTakeOff - sets with these values: 2

# IfcTransportElement: KONE_MonoSpace_500_2018-02-05, KONE_MonoSpace_500_2018-02-05:KONE_MonoSpace_500_2018-02-05:1874033
In: N00 - COO
Type - Classification: D1010 Elevators and Lifts (Uniformat); Material: Void
Type - Pset_ManufacturerTypeInformation - Manufacturer: KONE
Type - Pset_QuantityTakeOff - Reference: KONE_MonoSpace_500_2018-02-05
Type - Pset_TransportElementCommon - Reference: KONE_MonoSpace_500_2018-02-05
OperationType: ELEVATOR; CapacityByWeight: 0 kg; CapacityByNumber: 0
Pset_QuantityTakeOff - sets with these values: 2

# IfcWall: Mur de base:04 - Parement - ITE 18 - isolation enterrée (7)
In: Vide Sanitaire
Type - PredefinedType: STANDARD; Material: 00 - Isolant 18 cm
Type - Pset_QuantityTakeOff - Reference: 04 - Parement - ITE 18 - isolation enterrée
Type - Pset_ReinforcementBarPitchOfWall - Reference: 04 - Parement - ITE 18 - isolation enterrée
Type - Pset_WallCommon - IsExternal: no; Reference: 04 - Parement - ITE 18 - isolation enterrée; ThermalTransmittance: 0.211111 kg/K/s3
Pset_QuantityTakeOff - sets with these values: 2
Pset_WallCommon - LoadBearing: no; IsExternal: yes
Name (Mur de base:04 - Parement - ITE 18 - isolation enterrée:...) | ExtendToStructure
194614 | yes
196718 | no
197138 | yes
197383 | no
1526031 | yes
1527005 | yes
1549777 | no

# IfcWall: Mur de base:04 - Parement - ITE 18cm + vide 2cm (2)
Type - PredefinedType: STANDARD; Material: Aluminium bardage 0.5 cm, 01 - Lame d'air 1.5 cm, 00 - Isolant 18 cm
Type - Pset_QuantityTakeOff - Reference: 04 - Parement - ITE 18cm + vide 2cm
Type - Pset_ReinforcementBarPitchOfWall - Reference: 04 - Parement - ITE 18cm + vide 2cm
Type - Pset_WallCommon - IsExternal: no; Reference: 04 - Parement - ITE 18cm + vide 2cm; ThermalTransmittance: 0.21111 kg/K/s3
Pset_QuantityTakeOff - sets with these values: 2
Pset_WallCommon - LoadBearing: no; IsExternal: yes; ExtendToStructure: no
Name (Mur de base:04 - Parement - ITE 18cm + vide 2cm:...) | In
774724 | N00 - COO
2151387 | Toiture - Cuisine

# IfcWall: Mur de base:04 - Structure - béton - 20cm (16)
Type - PredefinedType: STANDARD; Material: 01 - Maçonnerie 20 cm
Type - Pset_QuantityTakeOff - Reference: 04 - Structure - béton - 20cm
Type - Pset_ReinforcementBarPitchOfWall - Reference: 04 - Structure - béton - 20cm
Type - Pset_WallCommon - IsExternal: no; Reference: 04 - Structure - béton - 20cm; ThermalTransmittance: 5.23 kg/K/s3
Pset_QuantityTakeOff - sets with these values: 2
Pset_WallCommon - LoadBearing: no; IsExternal: yes
Name (Mur de base:04 - Structure - béton - 20cm:...) | In | ExtendToStructure
157047 | N00 - COO | no
157212 | N00 - COO | yes
192803 | Vide Sanitaire | no
193017 | Vide Sanitaire | no
193869 | Vide Sanitaire | no
195387 | Vide Sanitaire | no
198392 | Vide Sanitaire | no
513301 | N00 - COO | no
683512 | Toiture - Cuisine | no
683744 | Toiture - Cuisine | no
910170 | Vide Sanitaire | no
1276742 | Vide Sanitaire | yes
1430453 | Vide Sanitaire | yes
1519388 | Vide Sanitaire | no
1522631 | N00 - COO | no
1880127 | Toiture - Cuisine | no

# IfcWall: Mur de base:04 - Structure - béton - 25cm (3)
Type - PredefinedType: STANDARD; Material: 01 - Maçonnerie 25 cm
Type - Pset_QuantityTakeOff - Reference: 04 - Structure - béton - 25cm
Type - Pset_ReinforcementBarPitchOfWall - Reference: 04 - Structure - béton - 25cm
Type - Pset_WallCommon - IsExternal: no; Reference: 04 - Structure - béton - 25cm; ThermalTransmittance: 4.184 kg/K/s3
Pset_QuantityTakeOff - sets with these values: 2
Pset_WallCommon - LoadBearing: no; IsExternal: yes; ExtendToStructure: no
Name (Mur de base:04 - Structure - béton - 25cm:...) | In
119840 | Toiture - Cuisine
566152 | Toiture - Cuisine
687673 | N00 - COO

# IfcWall: Mur de base:04 - retour isolation acrotère - ITE 16cm (2)
Type - PredefinedType: STANDARD; Material: 00 - Isolant 16 cm
Type - Pset_QuantityTakeOff - Reference: 04 - retour isolation acrotère - ITE 16cm
Type - Pset_ReinforcementBarPitchOfWall - Reference: 04 - retour isolation acrotère - ITE 16cm
Type - Pset_WallCommon - IsExternal: no; Reference: 04 - retour isolation acrotère - ITE 16cm; ThermalTransmittance: 0.2375 kg/K/s3
Pset_QuantityTakeOff - sets with these values: 2
Pset_WallCommon - LoadBearing: no; IsExternal: yes; ExtendToStructure: no
Name (Mur de base:04 - retour isolation acrotère - ITE 16cm:...) | In
239068 | N00 - COO
1671623 | Toiture - Cuisine | Group: Groupe de modèles:Retours BA 13 SELF / VERRIERE 2:1671562

# IfcWall: Mur de base:04 - retour isolation acrotère - ITE 20 cm, Mur de base:04 - retour isolation acrotère - ITE 20 cm:1524780
In: N00 - COO
Type - PredefinedType: STANDARD; Material: 00 - Isolant 20 cm
Type - Pset_QuantityTakeOff - Reference: 04 - retour isolation acrotère - ITE 20 cm
Type - Pset_ReinforcementBarPitchOfWall - Reference: 04 - retour isolation acrotère - ITE 20 cm
Type - Pset_WallCommon - IsExternal: no; Reference: 04 - retour isolation acrotère - ITE 20 cm; ThermalTransmittance: 0.19 kg/K/s3
Pset_QuantityTakeOff - sets with these values: 2
Pset_WallCommon - LoadBearing: no; IsExternal: yes; ExtendToStructure: no

# IfcWall: Mur de base:06 - cloisons - Ba13 10cm (3)
Type - PredefinedType: STANDARD; Material: 01 - Enduit/Plâtre 1.3 cm, 00 - Isolant 7.4 cm, 01 - Enduit/Plâtre 1.3 cm
Type - Pset_QuantityTakeOff - Reference: 06 - cloisons - Ba13 10cm
Type - Pset_ReinforcementBarPitchOfWall - Reference: 06 - cloisons - Ba13 10cm
Type - Pset_WallCommon - IsExternal: no; Reference: 06 - cloisons - Ba13 10cm; ThermalTransmittance: 0.503178 kg/K/s3
Pset_QuantityTakeOff - sets with these values: 2
Pset_WallCommon - LoadBearing: no
Name (Mur de base:06 - cloisons - Ba13 10cm:...) | In | ExtendToStructure
181088 | N00 - COO | no | Material: 01 - Enduit/Plâtre (2), 00 - Isolant
405616 | N00 - COO | yes
518966 | Toiture - Cuisine | yes

# IfcWall: Mur de base:06 - habillage bois collée 2cm perforé, Mur de base:06 - habillage bois collée 2cm perforé:928097
In: N00 - COO
Type - PredefinedType: STANDARD; Material: CP bouleau perforé 2 cm
Type - Pset_QuantityTakeOff - Reference: 06 - habillage bois collée 2cm perforé
Type - Pset_ReinforcementBarPitchOfWall - Reference: 06 - habillage bois collée 2cm perforé
Type - Pset_WallCommon - IsExternal: no; Reference: 06 - habillage bois collée 2cm perforé; ThermalTransmittance: 6 kg/K/s3
Material: CP bouleau perforé
Pset_QuantityTakeOff - sets with these values: 2
Pset_WallCommon - LoadBearing: no; ExtendToStructure: no

# IfcWallStandardCase: Mur de base:04 - Parement - CP acoustique 6cm, Mur de base:04 - Parement - CP acoustique 6cm:1351180
In: TR - N02 - ARCH
Type - PredefinedType: STANDARD; Material: 00 - Isolant 4 cm, Bois - Bois de construction de dimensions courantes 2 cm
Type - Pset_QuantityTakeOff - Reference: 04 - Parement - CP acoustique 6cm
Type - Pset_ReinforcementBarPitchOfWall - Reference: 04 - Parement - CP acoustique 6cm
Type - Pset_WallCommon - IsExternal: no; Reference: 04 - Parement - CP acoustique 6cm; ThermalTransmittance: 0.95 kg/K/s3
Pset_QuantityTakeOff - sets with these values: 2
Pset_WallCommon - LoadBearing: no; IsExternal: yes; ExtendToStructure: no

# IfcWallStandardCase: Mur de base:04 - Parement - CP collé 1cm, Mur de base:04 - Parement - CP collé 1cm:946915
In: N00 - COO
Type - PredefinedType: STANDARD; Material: Bois CP hachures 1 cm
Type - Pset_QuantityTakeOff - Reference: 04 - Parement - CP collé 1cm
Type - Pset_ReinforcementBarPitchOfWall - Reference: 04 - Parement - CP collé 1cm
Type - Pset_WallCommon - IsExternal: no; Reference: 04 - Parement - CP collé 1cm; ThermalTransmittance: 12 kg/K/s3
Pset_QuantityTakeOff - sets with these values: 2
Pset_WallCommon - LoadBearing: no; IsExternal: yes; ExtendToStructure: no

# IfcWallStandardCase: Mur de base:04 - Parement - ITE 18 - isolation enterrée (22)
In: Vide Sanitaire
Type - PredefinedType: STANDARD; Material: 00 - Isolant 18 cm
Type - Pset_QuantityTakeOff - Reference: 04 - Parement - ITE 18 - isolation enterrée
Type - Pset_ReinforcementBarPitchOfWall - Reference: 04 - Parement - ITE 18 - isolation enterrée
Type - Pset_WallCommon - IsExternal: no; Reference: 04 - Parement - ITE 18 - isolation enterrée; ThermalTransmittance: 0.211111 kg/K/s3
Pset_QuantityTakeOff - sets with these values: 2
Pset_WallCommon - LoadBearing: no; IsExternal: yes
Name (Mur de base:04 - Parement - ITE 18 - isolation enterrée:...) | ExtendToStructure
194520 | no
195049 | no
195170 | yes
195480 | no
195719 | no
195860 | no
195970 | no
196088 | no
196203 | no
196323 | yes
196442 | yes
196580 | no
196857 | no
197213 | no
197478 | no
197711 | yes
1622682 | yes
1622971 | no
1623094 | no
1777491 | yes
1834570 | no
2112878 | yes

# IfcWallStandardCase: Mur de base:04 - Parement - ITE 18cm + vide 2cm (21)
Type - PredefinedType: STANDARD; Material: Aluminium bardage 0.5 cm, 01 - Lame d'air 1.5 cm, 00 - Isolant 18 cm
Type - Pset_QuantityTakeOff - Reference: 04 - Parement - ITE 18cm + vide 2cm
Type - Pset_ReinforcementBarPitchOfWall - Reference: 04 - Parement - ITE 18cm + vide 2cm
Type - Pset_WallCommon - IsExternal: no; Reference: 04 - Parement - ITE 18cm + vide 2cm; ThermalTransmittance: 0.21111 kg/K/s3
Pset_QuantityTakeOff - sets with these values: 2
Pset_WallCommon - LoadBearing: no; IsExternal: yes
Name (Mur de base:04 - Parement - ITE 18cm + vide 2cm:...) | In | ExtendToStructure
47509 | Toiture - Cuisine | no
121995 | Toiture - Cuisine | no
237608 | N00 - COO | no
576914 | TR - N02 - ARCH | no
577104 | N00 - COO | no
577486 | Toiture - Cuisine | no
578381 | N00 - COO | no
579143 | TR - N02 - ARCH | no
579291 | Toiture - Cuisine | yes
581239 | N00 - COO | no
584873 | N00 - COO | no
666686 | N00 - COO | no
753886 | N00 - COO | no
767628 | Toiture - Cuisine | no
786185 | N00 - COO | no
798291 | N00 - COO | no
798382 | N00 - COO | no
803412 | Toiture - Cuisine | no
806668 | Toiture - Cuisine | no
1012875 | N00 - COO | no
1069666 | N00 - COO | no

# IfcWallStandardCase: Mur de base:04 - Parement - ITI 14cm (11)
Type - PredefinedType: STANDARD; Material: 01 - Enduit/Plâtre 1.3 cm, 00 - Isolant 14 cm
Type - Pset_QuantityTakeOff - Reference: 04 - Parement - ITI 14cm
Type - Pset_ReinforcementBarPitchOfWall - Reference: 04 - Parement - ITI 14cm
Type - Pset_WallCommon - IsExternal: no; Reference: 04 - Parement - ITI 14cm; ThermalTransmittance: 0.269963 kg/K/s3
Pset_QuantityTakeOff - sets with these values: 2
Pset_WallCommon - LoadBearing: no; IsExternal: yes
Name (Mur de base:04 - Parement - ITI 14cm:...) | In | ExtendToStructure
693556 | N00 - COO | no
850658 | N00 - COO | no
850763 | N00 - COO | no
850878 | N00 - COO | no
851784 | Vide Sanitaire | yes
851863 | Vide Sanitaire | yes
851954 | Vide Sanitaire | yes
1354664 | N00 - COO | no
1354869 | N00 - COO | no
1355341 | N00 - COO | no
1355479 | N00 - COO | no

# IfcWallStandardCase: Mur de base:04 - Parement - Isolant acoustique 10cm (10)
In: TR - N03 - ARCH
Type - PredefinedType: STANDARD; Material: 00 - Isolant 10 cm
Type - Pset_QuantityTakeOff - Reference: 04 - Parement - Isolant acoustique 10cm
Type - Pset_ReinforcementBarPitchOfWall - Reference: 04 - Parement - Isolant acoustique 10cm
Type - Pset_WallCommon - IsExternal: no; Reference: 04 - Parement - Isolant acoustique 10cm; ThermalTransmittance: 0.38 kg/K/s3
Pset_QuantityTakeOff - sets with these values: 2
Pset_WallCommon - LoadBearing: no; IsExternal: yes; ExtendToStructure: no
Name (Mur de base:04 - Parement - Isolant acoustique 10cm:...) | Group
1651091 | Groupe de modèles:Retours BA 13 SELF / VERRIERE (membre exclu):930111
1651092 | Groupe de modèles:Retours BA 13 SELF / VERRIERE (membre exclu):930111
1651094 | Groupe de modèles:Retours BA 13 SELF / VERRIERE (membre exclu):930111
1651858 | Groupe de modèles:Retours BA 13 SELF / VERRIERE 3 (membre exclu):893410
1651859 | Groupe de modèles:Retours BA 13 SELF / VERRIERE 3 (membre exclu):893410
1651861 | Groupe de modèles:Retours BA 13 SELF / VERRIERE 3 (membre exclu):893410
1652485 | Groupe de modèles:Retours BA 13 SELF / VERRIERE (membre exclu):930111
1652744 | Groupe de modèles:Retours BA 13 SELF / VERRIERE 3 (membre exclu):893410
1671644 | Groupe de modèles:Retours BA 13 SELF / VERRIERE 2:1671562
1671645 | Groupe de modèles:Retours BA 13 SELF / VERRIERE 2:1671562

# IfcWallStandardCase: Mur de base:04 - Parement - Isolant acoustique 8 cm (2)
In: TR - N03 - ARCH
Type - PredefinedType: STANDARD; Material: 00 - Isolant 8 cm
Type - Pset_QuantityTakeOff - Reference: 04 - Parement - Isolant acoustique 8 cm
Type - Pset_ReinforcementBarPitchOfWall - Reference: 04 - Parement - Isolant acoustique 8 cm
Type - Pset_WallCommon - IsExternal: no; Reference: 04 - Parement - Isolant acoustique 8 cm; ThermalTransmittance: 0.475 kg/K/s3
Pset_QuantityTakeOff - sets with these values: 2
Pset_WallCommon - LoadBearing: no; IsExternal: yes; ExtendToStructure: no
Group: Groupe de modèles:Retours BA 13 SELF / VERRIERE 2:1671562
Name (Mur de base:04 - Parement - Isolant acoustique 8 cm:...)
1671643
1671646

# IfcWallStandardCase: Mur de base:04 - Parement - Isolant acoustique 8cm (3)
In: N00 - COO
Type - PredefinedType: STANDARD; Material: 00 - Isolant 8 cm
Type - Pset_QuantityTakeOff - Reference: 04 - Parement - Isolant acoustique 8cm
Type - Pset_ReinforcementBarPitchOfWall - Reference: 04 - Parement - Isolant acoustique 8cm
Type - Pset_WallCommon - IsExternal: no; Reference: 04 - Parement - Isolant acoustique 8cm; ThermalTransmittance: 0.475 kg/K/s3
Pset_QuantityTakeOff - sets with these values: 2
Pset_WallCommon - LoadBearing: no; IsExternal: yes; ExtendToStructure: no
Name (Mur de base:04 - Parement - Isolant acoustique 8cm:...)
1197245
1197377
1197473

# IfcWallStandardCase: Mur de base:04 - Parement - faïence 1cm (6)
In: N00 - COO
Type - PredefinedType: STANDARD; Material: 01 - Faïence sanitaires 1 cm
Type - Pset_QuantityTakeOff - Reference: 04 - Parement - faïence 1cm
Type - Pset_ReinforcementBarPitchOfWall - Reference: 04 - Parement - faïence 1cm
Type - Pset_WallCommon - IsExternal: no; Reference: 04 - Parement - faïence 1cm
Pset_QuantityTakeOff - sets with these values: 2
Pset_WallCommon - LoadBearing: no; IsExternal: yes; ExtendToStructure: no
Name (Mur de base:04 - Parement - faïence 1cm:...)
1757002
1757131
1757331
1757392
1757508
1757708

# IfcWallStandardCase: Mur de base:04 - Parement - isolant 14 cm + BA13 (26)
Type - PredefinedType: STANDARD; Material: 00 - Isolant 14 cm, 01 - Enduit/Plâtre 1.3 cm
Type - Pset_QuantityTakeOff - Reference: 04 - Parement - isolant 14 cm + BA13
Type - Pset_ReinforcementBarPitchOfWall - Reference: 04 - Parement - isolant 14 cm + BA13
Type - Pset_WallCommon - IsExternal: no; Reference: 04 - Parement - isolant 14 cm + BA13; ThermalTransmittance: 0.269963 kg/K/s3
Pset_QuantityTakeOff - sets with these values: 2
Pset_WallCommon - LoadBearing: no; IsExternal: yes
Name (Mur de base:04 - Parement - isolant 14 cm + BA13:...) | In | ExtendToStructure
121115 | Toiture - Cuisine | yes
187303 | N00 - COO | yes
215179 | TR - N02 - ARCH | no
215682 | TR - N02 - ARCH | no
215845 | TR - N02 - ARCH | no
215994 | TR - N02 - ARCH | no
216487 | Toiture - Cuisine | no
216883 | Toiture - Cuisine | yes
512227 | Toiture - Cuisine | yes
555175 | TR - N02 - ARCH | no
555544 | Toiture - Cuisine | yes
734233 | TR - N02 - ARCH | no
785985 | N00 - COO | no
792276 | N00 - COO | no
792645 | N00 - COO | no
793074 | N00 - COO | no
811488 | Toiture - Cuisine | no
912241 | N00 - COO | no
913795 | N00 - COO | no
1012688 | N00 - COO | no
1012694 | N00 - COO | no
1012699 | N00 - COO | no
1012726 | N00 - COO | no
1219690 | N00 - COO | no
1339487 | N00 - COO | no
1766171 | N00 - COO | no

# IfcWallStandardCase: Mur de base:04 - Parement - isolant 20 cm + BA13 2 (4)
Type - PredefinedType: STANDARD; Material: 00 - Isolant 17.7 cm, 01 - Enduit/Plâtre 1.3 cm
Type - Pset_QuantityTakeOff - Reference: 04 - Parement - isolant 20 cm + BA13 2
Type - Pset_ReinforcementBarPitchOfWall - Reference: 04 - Parement - isolant 20 cm + BA13 2
Type - Pset_WallCommon - IsExternal: no; Reference: 04 - Parement - isolant 20 cm + BA13 2; ThermalTransmittance: 0.213771 kg/K/s3
Pset_QuantityTakeOff - sets with these values: 2
Pset_WallCommon - LoadBearing: no; IsExternal: yes; ExtendToStructure: no
Name (Mur de base:04 - Parement - isolant 20 cm + BA13 2:...) | In
770760 | Toiture - Cuisine
1856764 | N00 - COO
1856825 | N00 - COO
1976037 | N00 - COO

# IfcWallStandardCase: Mur de base:04 - Structure - Béton - 40 (11)
Type - PredefinedType: STANDARD; Material: 01 - Maçonnerie 40 cm
Type - Pset_QuantityTakeOff - Reference: 04 - Structure - Béton - 40
Type - Pset_ReinforcementBarPitchOfWall - Reference: 04 - Structure - Béton - 40
Type - Pset_WallCommon - IsExternal: no; Reference: 04 - Structure - Béton - 40; ThermalTransmittance: 2.615 kg/K/s3
Pset_QuantityTakeOff - sets with these values: 2
Pset_WallCommon - LoadBearing: no; IsExternal: yes
Name (Mur de base:04 - Structure - Béton - 40:...) | In | ExtendToStructure
180710 | N00 - COO | yes
181295 | N00 - COO | yes
194014 | Vide Sanitaire | no
784650 | Toiture - Cuisine | no
878460 | N00 - COO | yes
944175 | N00 - COO | yes
1308751 | N00 - COO | no
1308759 | N00 - COO | no
1519889 | Vide Sanitaire | yes
1520822 | N00 - COO | no
1522689 | N00 - COO | no

# IfcWallStandardCase: Mur de base:04 - Structure - Poutre bois - (6)
In: Toiture - Cuisine
Type - PredefinedType: STANDARD; Material: Bois - Bois de construction de dimensions courantes 10 cm
Type - Pset_QuantityTakeOff - Reference: 04 - Structure - Poutre bois -
Type - Pset_ReinforcementBarPitchOfWall - Reference: 04 - Structure - Poutre bois -
Type - Pset_WallCommon - IsExternal: no; Reference: 04 - Structure - Poutre bois -
Pset_QuantityTakeOff - sets with these values: 2
Pset_WallCommon - LoadBearing: no; IsExternal: yes; ExtendToStructure: no
Name (Mur de base:04 - Structure - Poutre bois -:...) | Group
1282155 | Groupe de modèles:Retours BA 13 SELF / VERRIERE 3 (membre exclu):893410
1282157 | Groupe de modèles:Retours BA 13 SELF / VERRIERE 3 (membre exclu):893410
1282167 | Groupe de modèles:Retours BA 13 SELF / VERRIERE (membre exclu):930111
1282169 | Groupe de modèles:Retours BA 13 SELF / VERRIERE (membre exclu):930111
1671639 | Groupe de modèles:Retours BA 13 SELF / VERRIERE 2:1671562
1671641 | Groupe de modèles:Retours BA 13 SELF / VERRIERE 2:1671562

# IfcWallStandardCase: Mur de base:04 - Structure - Poutre bois - (12x25 ht) 3 (6)
In: Toiture - Cuisine
Type - PredefinedType: STANDARD; Material: Bois - Bois de construction de dimensions courantes 12 cm
Type - Pset_QuantityTakeOff - Reference: 04 - Structure - Poutre bois - (12x25 ht) 3
Type - Pset_ReinforcementBarPitchOfWall - Reference: 04 - Structure - Poutre bois - (12x25 ht) 3
Type - Pset_WallCommon - IsExternal: no; Reference: 04 - Structure - Poutre bois - (12x25 ht) 3
Pset_QuantityTakeOff - sets with these values: 2
Pset_WallCommon - LoadBearing: no; IsExternal: yes; ExtendToStructure: no
Name (Mur de base:04 - Structure - Poutre bois - (12x25 ht) 3:...) | Group
932129 | Groupe de modèles:Retours BA 13 SELF / VERRIERE (membre exclu):930111
932257 | Groupe de modèles:Retours BA 13 SELF / VERRIERE 3 (membre exclu):893410
1282154 | Groupe de modèles:Retours BA 13 SELF / VERRIERE 3 (membre exclu):893410
1282166 | Groupe de modèles:Retours BA 13 SELF / VERRIERE (membre exclu):930111
1671564 | Groupe de modèles:Retours BA 13 SELF / VERRIERE 2:1671562
1671638 | Groupe de modèles:Retours BA 13 SELF / VERRIERE 2:1671562

# IfcWallStandardCase: Mur de base:04 - Structure - Poutre béton - (20x25 ht) (4)
Type - PredefinedType: STANDARD; Material: 01 - Maçonnerie 20 cm
Type - Pset_QuantityTakeOff - Reference: 04 - Structure - Poutre béton - (20x25 ht)
Type - Pset_ReinforcementBarPitchOfWall - Reference: 04 - Structure - Poutre béton - (20x25 ht)
Type - Pset_WallCommon - IsExternal: no; Reference: 04 - Structure - Poutre béton - (20x25 ht); ThermalTransmittance: 5.23 kg/K/s3
Pset_QuantityTakeOff - sets with these values: 2
Pset_WallCommon - LoadBearing: no; IsExternal: yes; ExtendToStructure: no
Name (Mur de base:04 - Structure - Poutre béton - (20x25 ht):...) | In
884382 | Toiture - Cuisine
884731 | Toiture - Cuisine
884796 | N00 - COO
884985 | N00 - COO

# IfcWallStandardCase: Mur de base:04 - Structure - béton - 20cm (176)
Type - PredefinedType: STANDARD; Material: 01 - Maçonnerie 20 cm
Type - Pset_QuantityTakeOff - Reference: 04 - Structure - béton - 20cm
Type - Pset_ReinforcementBarPitchOfWall - Reference: 04 - Structure - béton - 20cm
Type - Pset_WallCommon - IsExternal: no; Reference: 04 - Structure - béton - 20cm; ThermalTransmittance: 5.23 kg/K/s3
Pset_QuantityTakeOff - sets with these values: 2
Pset_WallCommon - IsExternal: yes
Name (Mur de base:04 - Structure - béton - 20cm:...) | In | LoadBearing | ExtendToStructure
137000 | N00 - COO | no | no
137223 | N00 - COO | no | yes
137409 | N00 - COO | no | yes
137511 | N00 - COO | no | yes
149570 | N00 - COO | no | no
149776 | N00 - COO | no | no
149871 | N00 - COO | no | yes
160202 | N00 - COO | no | no
160354 | N00 - COO | no | no
165231 | N00 - COO | no | no
182010 | N00 - COO | no | no
182313 | N00 - COO | no | no
182462 | N00 - COO | no | no
182742 | Toiture - Cuisine | no | no
183025 | N00 - COO | no | no
183202 | N00 - COO | no | no
183460 | N00 - COO | no | no
183570 | N00 - COO | no | no
183694 | N00 - COO | no | no
183744 | N00 - COO | no | no
183811 | N00 - COO | no | no
192420 | Vide Sanitaire | no | no
192517 | Vide Sanitaire | no | yes
192681 | Vide Sanitaire | no | yes
192949 | Vide Sanitaire | no | yes
193135 | Vide Sanitaire | no | no
193208 | Vide Sanitaire | no | no
193338 | Vide Sanitaire | no | yes
193424 | Vide Sanitaire | no | no
193585 | Vide Sanitaire | no | yes
193720 | Vide Sanitaire | no | no
194098 | Vide Sanitaire | no | yes
194233 | N00 - COO | no | no
203142 | Vide Sanitaire | no | yes
203318 | Vide Sanitaire | no | yes
204575 | TR - N02 - ARCH | no | no
204812 | TR - N02 - ARCH | no | no
204960 | TR - N02 - ARCH | no | yes
205154 | TR - N02 - ARCH | no | yes
206144 | Toiture - Cuisine | no | yes
206222 | Toiture - Cuisine | no | yes
206313 | Toiture - Cuisine | no | yes
206493 | Toiture - Cuisine | no | yes
208851 | TR - N02 - ARCH | no | no
210028 | TR - N02 - ARCH | no | no
217941 | TR - N03 - ARCH | no | yes
218010 | TR - N03 - ARCH | no | no
218093 | TR - N03 - ARCH | no | yes
218686 | TR - N03 - ARCH | no | no
246344 | N00 - COO | no | no
246436 | N00 - COO | no | no
246577 | Toiture - Cuisine | no | no
246630 | Toiture - Cuisine | no | no
246695 | Toiture - Cuisine | no | no
248354 | N00 - COO | no | no
431683 | N00 - COO | no | no
436573 | N00 - COO | no | no
436637 | N00 - COO | no | no
446163 | N00 - COO | no | no
446419 | N00 - COO | no | no
460592 | N00 - COO | no | no
461594 | N00 - COO | no | no
462432 | N00 - COO | no | no
462613 | N00 - COO | no | no
462614 | N00 - COO | no | no
462615 | N00 - COO | no | no
462616 | N00 - COO | no | no
468998 | N00 - COO | no | no
475413 | N00 - COO | no | no
522754 | TR - N02 - ARCH | no | no
527742 | TR - N02 - ARCH | no | no
529922 | TR - N02 - ARCH | no | no
529994 | TR - N02 - ARCH | no | no
566154 | TR - N02 - ARCH | no | no
568433 | TR - N02 - ARCH | no | no
579565 | TR - N02 - ARCH | no | no
658902 | Vide Sanitaire | yes | no
659427 | N00 - COO | no | no
659620 | N00 - COO | no | no
659688 | N00 - COO | no | no
677143 | Toiture - Cuisine | no | no
677363 | Toiture - Cuisine | no | no
684049 | Toiture - Cuisine | no | no
685971 | Toiture - Cuisine | no | no
688863 | TR - N02 - ARCH | no | no
694218 | N00 - COO | no | yes
709893 | TR - N02 - ARCH | no | no
734150 | Toiture - Cuisine | no | no
734209 | N00 - COO | no | no
758030 | N00 - COO | no | yes
765983 | N00 - COO | no | no
766102 | Toiture - Cuisine | no | no
772861 | Toiture - Cuisine | no | no
774521 | N00 - COO | no | no
775228 | N00 - COO | no | no
775769 | N00 - COO | no | no
776035 | Toiture - Cuisine | no | no
781099 | Toiture - Cuisine | no | no
782258 | Toiture - Cuisine | no | no
787676 | Toiture - Cuisine | no | no
787836 | N00 - COO | no | no
787872 | N00 - COO | no | no
787986 | N00 - COO | no | no
788073 | N00 - COO | no | no
788118 | N00 - COO | no | no
788199 | N00 - COO | no | no
788238 | N00 - COO | no | no
788286 | N00 - COO | no | no
791228 | Toiture - Cuisine | no | no
791982 | N00 - COO | no | no
794560 | N00 - COO | no | no
796110 | N00 - COO | no | no
797762 | N00 - COO | no | no
797932 | Toiture - Cuisine | no | no
799882 | N00 - COO | no | no
800058 | N00 - COO | no | no
800234 | N00 - COO | no | no
801365 | N00 - COO | no | no
801803 | N00 - COO | no | no
803320 | Toiture - Cuisine | no | no
803820 | Toiture - Cuisine | no | no
806428 | N00 - COO | no | no
816733 | N00 - COO | no | no
838476 | N00 - COO | no | no
852182 | Vide Sanitaire | no | yes
852274 | Vide Sanitaire | no | yes
852375 | Vide Sanitaire | no | yes
909976 | N00 - COO | no | no
911505 | N00 - COO | no | no
921893 | N00 - COO | no | no
926337 | N00 - COO | no | yes
935457 | N00 - COO | no | no
937353 | N00 - COO | no | no
1005214 | N00 - COO | no | no
1005465 | Toiture - Cuisine | no | yes
1005712 | TR - N02 - ARCH | no | no
1053321 | N00 - COO | no | no
1058290 | N00 - COO | no | no
1063217 | N00 - COO | no | no
1068658 | Toiture - Cuisine | no | yes
1069671 | Toiture - Cuisine | no | no
1069800 | N00 - COO | no | no
1069802 | N00 - COO | no | no
1099441 | N00 - COO | no | no
1198442 | N00 - COO | no | no
1236597 | Toiture - Cuisine | no | no
1237182 | N00 - COO | no | no
1240808 | Vide Sanitaire | no | no
1240811 | N00 - COO | no | no
1242852 | Toiture - Cuisine | no | no
1273497 | Vide Sanitaire | no | yes
1273738 | Vide Sanitaire | no | yes
1275690 | Vide Sanitaire | no | no
1277123 | Vide Sanitaire | no | yes
1330106 | N00 - COO | no | no
1337564 | N00 - COO | no | no
1398610 | Vide Sanitaire | no | yes
1427989 | N00 - COO | no | no
1428038 | N00 - COO | no | no
1428091 | N00 - COO | no | no
1512696 | Vide Sanitaire | no | no
1521564 | N00 - COO | no | no
1607561 | Vide Sanitaire | no | no
1622058 | Vide Sanitaire | no | yes
1792271 | N00 - COO | no | no
1840322 | Vide Sanitaire | no | no
1856901 | N00 - COO | no | no
1860350 | N00 - COO | no | no
1860374 | N00 - COO | no | no
1891812 | N00 - COO | no | no
1892011 | Vide Sanitaire | no | no
1895576 | N00 - COO | no | no
1973434 | N00 - COO | no | no
1973954 | N00 - COO | no | no
1997004 | N00 - COO | no | yes
2075960 | N00 - COO | no | no

# IfcWallStandardCase: Mur de base:04 - Structure - béton - 25cm (11)
Type - PredefinedType: STANDARD; Material: 01 - Maçonnerie 25 cm
Type - Pset_QuantityTakeOff - Reference: 04 - Structure - béton - 25cm
Type - Pset_ReinforcementBarPitchOfWall - Reference: 04 - Structure - béton - 25cm
Type - Pset_WallCommon - IsExternal: no; Reference: 04 - Structure - béton - 25cm; ThermalTransmittance: 4.184 kg/K/s3
Pset_QuantityTakeOff - sets with these values: 2
Pset_WallCommon - LoadBearing: no; IsExternal: yes
Name (Mur de base:04 - Structure - béton - 25cm:...) | In | ExtendToStructure
45502 | Toiture - Cuisine | no
580863 | Toiture - Cuisine | yes
687012 | N00 - COO | no
687127 | N00 - COO | no
687342 | N00 - COO | no
687442 | N00 - COO | no
687554 | N00 - COO | no
687762 | N00 - COO | no
687967 | N00 - COO | no
692840 | N00 - COO | no
826648 | Toiture - Cuisine | no

# IfcWallStandardCase: Mur de base:04 - retour isolation acrotère - ITE 16cm (37)
Type - PredefinedType: STANDARD; Material: 00 - Isolant 16 cm
Type - Pset_QuantityTakeOff - Reference: 04 - retour isolation acrotère - ITE 16cm
Type - Pset_ReinforcementBarPitchOfWall - Reference: 04 - retour isolation acrotère - ITE 16cm
Type - Pset_WallCommon - IsExternal: no; Reference: 04 - retour isolation acrotère - ITE 16cm; ThermalTransmittance: 0.2375 kg/K/s3
Pset_QuantityTakeOff - sets with these values: 2
Pset_WallCommon - LoadBearing: no; IsExternal: yes; ExtendToStructure: no
Name (Mur de base:04 - retour isolation acrotère - ITE 16cm:...) | In
209270 | TR - N02 - ARCH
210602 | TR - N03 - ARCH
211528 | TR - N03 - ARCH
211740 | TR - N03 - ARCH
213566 | TR - N03 - ARCH
213822 | TR - N03 - ARCH
214037 | TR - N03 - ARCH
214180 | TR - N03 - ARCH
218279 | TR - N03 - ARCH
218461 | TR - N03 - ARCH
218552 | TR - N03 - ARCH
236464 | N00 - COO
236588 | N00 - COO
236764 | N00 - COO
237873 | N00 - COO
237979 | N00 - COO
622530 | N00 - COO
622531 | N00 - COO
622532 | N00 - COO
756427 | N00 - COO
932054 | Toiture - Cuisine | Group: Groupe de modèles:Retours BA 13 SELF / VERRIERE (membre exclu):930111
932159 | Toiture - Cuisine | Group: Groupe de modèles:Retours BA 13 SELF / VERRIERE (membre exclu):930111
932255 | Toiture - Cuisine | Group: Groupe de modèles:Retours BA 13 SELF / VERRIERE 3 (membre exclu):893410
932258 | Toiture - Cuisine | Group: Groupe de modèles:Retours BA 13 SELF / VERRIERE 3 (membre exclu):893410
1069698 | N00 - COO
1069700 | N00 - COO
1099095 | Toiture - Cuisine | Group: Groupe de modèles:Retours BA 13 SELF / VERRIERE 3 (membre exclu):893410
1099274 | Toiture - Cuisine | Group: Groupe de modèles:Retours BA 13 SELF / VERRIERE (membre exclu):930111
1282156 | Toiture - Cuisine | Group: Groupe de modèles:Retours BA 13 SELF / VERRIERE 3 (membre exclu):893410
1282168 | Toiture - Cuisine | Group: Groupe de modèles:Retours BA 13 SELF / VERRIERE (membre exclu):930111
1527456 | TR - N03 - ARCH
1671563 | Toiture - Cuisine | Group: Groupe de modèles:Retours BA 13 SELF / VERRIERE 2:1671562
1671565 | Toiture - Cuisine | Group: Groupe de modèles:Retours BA 13 SELF / VERRIERE 2:1671562
1671640 | Toiture - Cuisine | Group: Groupe de modèles:Retours BA 13 SELF / VERRIERE 2:1671562
1736724 | N00 - COO
1737525 | N00 - COO
2145599 | N00 - COO

# IfcWallStandardCase: Mur de base:04 - retour isolation acrotère - ITE 20 cm (11)
Type - PredefinedType: STANDARD; Material: 00 - Isolant 20 cm
Type - Pset_QuantityTakeOff - Reference: 04 - retour isolation acrotère - ITE 20 cm
Type - Pset_ReinforcementBarPitchOfWall - Reference: 04 - retour isolation acrotère - ITE 20 cm
Type - Pset_WallCommon - IsExternal: no; Reference: 04 - retour isolation acrotère - ITE 20 cm; ThermalTransmittance: 0.19 kg/K/s3
Pset_QuantityTakeOff - sets with these values: 2
Pset_WallCommon - LoadBearing: no; IsExternal: yes; ExtendToStructure: no
Name (Mur de base:04 - retour isolation acrotère - ITE 20 cm:...) | In
1414866 | TR - N03 - ARCH
1415021 | TR - N02 - ARCH
1522106 | N00 - COO
1522279 | N00 - COO
1522304 | N00 - COO
1522327 | N00 - COO
1522632 | N00 - COO
1524178 | N00 - COO
1524197 | N00 - COO
1527886 | TR - N03 - ARCH
1547085 | TR - N02 - ARCH

# IfcWallStandardCase: Mur de base:06 - cimaise R+2 (12)
Type - PredefinedType: STANDARD; Material: Pin 2 cm, Mur par défaut 8 cm
Type - Pset_QuantityTakeOff - Reference: 06 - cimaise R+2
Type - Pset_ReinforcementBarPitchOfWall - Reference: 06 - cimaise R+2
Type - Pset_WallCommon - IsExternal: no; Reference: 06 - cimaise R+2; ThermalTransmittance: 6 kg/K/s3
Pset_QuantityTakeOff - sets with these values: 2
Pset_WallCommon - LoadBearing: no; ExtendToStructure: no
Name (Mur de base:06 - cimaise R+2:...) | In
1358434 | TR - N02 - ARCH
1358929 | TR - N02 - ARCH
1359025 | TR - N02 - ARCH
1359178 | TR - N02 - ARCH
1363197 | TR - N02 - ARCH
1363363 | TR - N02 - ARCH
1494006 | TR - N02 - ARCH
1494439 | Toiture - Cuisine
1494534 | TR - N02 - ARCH
1494949 | Toiture - Cuisine
1495448 | Toiture - Cuisine
1495681 | Toiture - Cuisine

# IfcWallStandardCase: Mur de base:06 - cloisons - Ba13 10cm (215)
Type - PredefinedType: STANDARD; Material: 01 - Enduit/Plâtre 1.3 cm, 00 - Isolant 7.4 cm, 01 - Enduit/Plâtre 1.3 cm
Type - Pset_QuantityTakeOff - Reference: 06 - cloisons - Ba13 10cm
Type - Pset_ReinforcementBarPitchOfWall - Reference: 06 - cloisons - Ba13 10cm
Type - Pset_WallCommon - IsExternal: no; Reference: 06 - cloisons - Ba13 10cm; ThermalTransmittance: 0.503178 kg/K/s3
Pset_QuantityTakeOff - sets with these values: 2
Pset_WallCommon - LoadBearing: no
Name (Mur de base:06 - cloisons - Ba13 10cm:...) | In | ExtendToStructure
319390 | N00 - COO | yes
319526 | N00 - COO | yes
319636 | N00 - COO | yes
319713 | N00 - COO | yes
319887 | N00 - COO | yes
319990 | N00 - COO | yes
320033 | N00 - COO | yes
320112 | N00 - COO | yes
320165 | N00 - COO | yes
322265 | N00 - COO | yes
323769 | N00 - COO | yes
324092 | N00 - COO | yes
324304 | N00 - COO | yes
324657 | N00 - COO | yes
338911 | N00 - COO | yes
339080 | N00 - COO | yes
344077 | N00 - COO | yes
344110 | N00 - COO | yes
344412 | N00 - COO | yes
353125 | N00 - COO | no
365311 | N00 - COO | yes
365349 | N00 - COO | yes
365388 | N00 - COO | yes
394632 | N00 - COO | yes
394794 | N00 - COO | yes
394896 | N00 - COO | yes
394969 | N00 - COO | yes
395025 | N00 - COO | yes
395105 | N00 - COO | yes
395184 | N00 - COO | yes
395265 | N00 - COO | yes
395361 | N00 - COO | yes
395400 | N00 - COO | yes
395471 | N00 - COO | yes
395533 | N00 - COO | yes
395603 | N00 - COO | yes
395717 | N00 - COO | yes
395761 | N00 - COO | no
395814 | N00 - COO | yes
395850 | N00 - COO | yes
395907 | N00 - COO | yes
396433 | N00 - COO | yes
396777 | N00 - COO | yes
396862 | N00 - COO | yes
397651 | N00 - COO | yes
403636 | N00 - COO | no
403819 | N00 - COO | no
405166 | N00 - COO | yes
405251 | N00 - COO | yes
405351 | N00 - COO | yes
405438 | N00 - COO | yes
405493 | N00 - COO | yes
405557 | N00 - COO | yes
405662 | N00 - COO | yes
406469 | N00 - COO | yes
406692 | N00 - COO | no
429599 | N00 - COO | yes
429717 | N00 - COO | yes
429779 | N00 - COO | yes
430021 | N00 - COO | yes
431366 | N00 - COO | no
431459 | N00 - COO | yes
431883 | N00 - COO | no
431968 | N00 - COO | no
439002 | N00 - COO | no
439204 | N00 - COO | no
439243 | N00 - COO | no
439499 | N00 - COO | no
439668 | N00 - COO | no
439723 | N00 - COO | no
439803 | N00 - COO | no
439893 | N00 - COO | no
439975 | N00 - COO | no
440065 | N00 - COO | no
440144 | N00 - COO | no
440210 | N00 - COO | no
440378 | N00 - COO | no
440417 | N00 - COO | no
440443 | N00 - COO | no
440474 | N00 - COO | no
440598 | N00 - COO | yes
440655 | N00 - COO | no
441510 | N00 - COO | no
441696 | N00 - COO | no
446330 | N00 - COO | no
459338 | N00 - COO | no
462694 | N00 - COO | no
462723 | N00 - COO | no
462768 | N00 - COO | no
485838 | N00 - COO | yes
485844 | N00 - COO | yes
486379 | N00 - COO | yes
509040 | Toiture - Cuisine | yes
509105 | Toiture - Cuisine | yes
509142 | Toiture - Cuisine | yes
509215 | Toiture - Cuisine | yes
511202 | Toiture - Cuisine | yes
511283 | Toiture - Cuisine | yes
511345 | Toiture - Cuisine | yes
511466 | Toiture - Cuisine | yes
511492 | Toiture - Cuisine | yes
511536 | Toiture - Cuisine | yes
511600 | Toiture - Cuisine | yes
515697 | Toiture - Cuisine | no
515740 | Toiture - Cuisine | no
516084 | Toiture - Cuisine | yes
516129 | Toiture - Cuisine | yes
516173 | Toiture - Cuisine | yes
516237 | Toiture - Cuisine | yes
516316 | Toiture - Cuisine | yes
516457 | Toiture - Cuisine | yes
516485 | Toiture - Cuisine | yes
516530 | Toiture - Cuisine | yes
517068 | Toiture - Cuisine | yes
517127 | Toiture - Cuisine | yes
517155 | Toiture - Cuisine | yes
518814 | Toiture - Cuisine | yes
518851 | Toiture - Cuisine | yes
518897 | Toiture - Cuisine | yes
518943 | Toiture - Cuisine | yes
518995 | Toiture - Cuisine | yes
527126 | TR - N02 - ARCH | no
527127 | TR - N02 - ARCH | no
527128 | TR - N02 - ARCH | no
527129 | TR - N02 - ARCH | no
527130 | TR - N02 - ARCH | no
527131 | TR - N02 - ARCH | no
527134 | TR - N02 - ARCH | no
527135 | TR - N02 - ARCH | no
527167 | TR - N02 - ARCH | no
527168 | TR - N02 - ARCH | no
527169 | TR - N02 - ARCH | no
527170 | TR - N02 - ARCH | yes
527171 | TR - N02 - ARCH | no
527172 | TR - N02 - ARCH | no
529385 | TR - N02 - ARCH | no
529390 | TR - N02 - ARCH | no
529391 | TR - N02 - ARCH | no
529393 | TR - N02 - ARCH | no
530224 | TR - N02 - ARCH | no
530287 | TR - N02 - ARCH | no
530369 | TR - N02 - ARCH | no
530426 | TR - N02 - ARCH | no
530501 | TR - N02 - ARCH | no
530574 | TR - N02 - ARCH | no
530623 | TR - N02 - ARCH | no
530666 | TR - N02 - ARCH | no
530705 | TR - N02 - ARCH | no
530734 | TR - N02 - ARCH | no
530763 | TR - N02 - ARCH | no
531015 | TR - N02 - ARCH | no
531188 | TR - N02 - ARCH | no
531212 | TR - N02 - ARCH | no
531273 | TR - N02 - ARCH | no
551457 | N00 - COO | no
551571 | N00 - COO | yes
552474 | Toiture - Cuisine | yes
552569 | Toiture - Cuisine | no
552651 | TR - N02 - ARCH | no
552751 | TR - N02 - ARCH | yes
660368 | N00 - COO | no
661597 | N00 - COO | no
663282 | N00 - COO | no
665410 | N00 - COO | no
704262 | N00 - COO | no
704619 | N00 - COO | no
777906 | N00 - COO | no
795593 | N00 - COO | no
834813 | N00 - COO | no
834977 | N00 - COO | no
835358 | N00 - COO | yes
835474 | N00 - COO | no
835655 | N00 - COO | yes
835828 | N00 - COO | no
835911 | N00 - COO | no
836037 | N00 - COO | no
836082 | N00 - COO | no
839212 | N00 - COO | no
870156 | Toiture - Cuisine | yes
918936 | N00 - COO | no
919105 | N00 - COO | no
919734 | N00 - COO | no
920135 | N00 - COO | no
936848 | N00 - COO | no
936892 | N00 - COO | no
938087 | N00 - COO | no
938211 | N00 - COO | no
938243 | N00 - COO | no
938524 | Toiture - Cuisine | yes
938545 | Toiture - Cuisine | yes
938720 | Toiture - Cuisine | yes
938750 | Toiture - Cuisine | yes
938858 | Toiture - Cuisine | yes
938907 | Toiture - Cuisine | yes
939095 | Toiture - Cuisine | yes
939217 | TR - N02 - ARCH | no
939218 | TR - N02 - ARCH | no
939219 | TR - N02 - ARCH | no
939220 | TR - N02 - ARCH | no
940343 | TR - N02 - ARCH | no
940620 | Toiture - Cuisine | yes
1058131 | N00 - COO | no
1127270 | Toiture - Cuisine | yes
1995049 | N00 - COO | no | Pset_QuantityTakeOff - Reference: 07 - mur rideau trame 280 cm; Pset_WallCommon - Reference: 07 - mur rideau trame 280 cm
1218587 | N00 - COO | no
1362941 | Toiture - Cuisine | yes
1362967 | Toiture - Cuisine | yes
1366665 | Toiture - Cuisine | yes
1366666 | Toiture - Cuisine | yes
1770321 | N00 - COO | no
1791997 | N00 - COO | no
1801021 | TR - N02 - ARCH | no
1904117 | N00 - COO | no
1905017 | N00 - COO | no
1996913 | N00 - COO | no

# IfcWallStandardCase: Mur de base:06 - cloisons - Ba13 16cm (4)
Type - PredefinedType: STANDARD; Material: 01 - Enduit/Plâtre 1.3 cm, 00 - Isolant 13.4 cm, 01 - Enduit/Plâtre 1.3 cm
Type - Pset_QuantityTakeOff - Reference: 06 - cloisons - Ba13 16cm
Type - Pset_ReinforcementBarPitchOfWall - Reference: 06 - cloisons - Ba13 16cm
Type - Pset_WallCommon - IsExternal: no; Reference: 06 - cloisons - Ba13 16cm; ThermalTransmittance: 0.280401 kg/K/s3
Pset_QuantityTakeOff - sets with these values: 2
Pset_WallCommon - LoadBearing: no
Name (Mur de base:06 - cloisons - Ba13 16cm:...) | In | ExtendToStructure
508973 | Toiture - Cuisine | yes
509310 | Toiture - Cuisine | yes
527132 | TR - N02 - ARCH | no
527133 | TR - N02 - ARCH | no

# IfcWallStandardCase: Mur de base:06 - cloisons - Carreau de terre cuite (10cm) (24)
In: N00 - COO
Type - PredefinedType: STANDARD; Material: 01 - Enduit/Plâtre 1.3 cm, Terre cuite 7.4 cm, 01 - Enduit/Plâtre 1.3 cm
Type - Pset_QuantityTakeOff - Reference: 06 - cloisons - Carreau de terre cuite (10cm)
Type - Pset_ReinforcementBarPitchOfWall - Reference: 06 - cloisons - Carreau de terre cuite (10cm)
Type - Pset_WallCommon - IsExternal: no; Reference: 06 - cloisons - Carreau de terre cuite (10cm); ThermalTransmittance: 9.0297 kg/K/s3
Pset_QuantityTakeOff - sets with these values: 2
Pset_WallCommon - LoadBearing: no
Name (Mur de base:06 - cloisons - Carreau de terre cuite (10cm):...) | ExtendToStructure
452702 | no
453075 | no
453429 | no
453521 | no
453575 | no
453652 | no
453731 | no
453840 | no
453931 | no
454023 | no
454068 | no
454120 | no
454167 | no
454203 | no
454297 | yes
454366 | no
454406 | yes
454474 | yes
454529 | no
454703 | no
455161 | no
455517 | no
456022 | yes
836290 | no

# IfcWallStandardCase: Mur de base:06 - cloisons - agglos10 + enduit (3)
In: N00 - COO
Type - PredefinedType: STANDARD; Material: 01 - Enduit/Plâtre 1 cm, Maçonnerie - Béton 10 cm, 01 - Enduit/Plâtre 1 cm
Type - Pset_QuantityTakeOff - Reference: 06 - cloisons - agglos10 + enduit
Type - Pset_ReinforcementBarPitchOfWall - Reference: 06 - cloisons - agglos10 + enduit
Type - Pset_WallCommon - IsExternal: no; Reference: 06 - cloisons - agglos10 + enduit; ThermalTransmittance: 32.5 kg/K/s3
Pset_QuantityTakeOff - sets with these values: 2
Pset_WallCommon - LoadBearing: no; ExtendToStructure: no
Name (Mur de base:06 - cloisons - agglos10 + enduit:...)
436264
436349
436488

# IfcWallStandardCase: Mur de base:06 - cloisons - agglos10 + faïence 12cm (20)
In: N00 - COO
Type - PredefinedType: STANDARD; Material: 01 - Enduit/Plâtre 1 cm, Maçonnerie - Béton 10 cm, 01 - Enduit/Plâtre 1 cm
Type - Pset_QuantityTakeOff - Reference: 06 - cloisons - agglos10 + faïence 12cm
Type - Pset_ReinforcementBarPitchOfWall - Reference: 06 - cloisons - agglos10 + faïence 12cm
Type - Pset_WallCommon - IsExternal: no; Reference: 06 - cloisons - agglos10 + faïence 12cm; ThermalTransmittance: 32.5 kg/K/s3
Pset_QuantityTakeOff - sets with these values: 2
Pset_WallCommon - LoadBearing: no; ExtendToStructure: no
Name (Mur de base:06 - cloisons - agglos10 + faïence 12cm:...)
445124
445222
445275
445398
445478
445570
445618
445682
445716
446842
452654
460117
460193
460224
460411
460491
460690
793611
1439602
1771469

# IfcWallStandardCase: Mur de base:06 - cloisons - cuisine 10cm (4)
In: N00 - COO
Type - PredefinedType: STANDARD; Material: Plastique, blanc opaque 0.2 cm, 00 - Isolant cloison Frigo 9.6 cm, Plastique, blanc opaque 0.2 cm
Type - Pset_QuantityTakeOff - Reference: 06 - cloisons - cuisine 10cm
Type - Pset_ReinforcementBarPitchOfWall - Reference: 06 - cloisons - cuisine 10cm
Type - Pset_WallCommon - IsExternal: no; Reference: 06 - cloisons - cuisine 10cm; ThermalTransmittance: 82.75 kg/K/s3
Pset_QuantityTakeOff - sets with these values: 2
Pset_WallCommon - LoadBearing: no; ExtendToStructure: no
Name (Mur de base:06 - cloisons - cuisine 10cm:...)
836707
1772394
1773628
1773864

# IfcWallStandardCase: Mur de base:06 - cloisons - cuisine 6cm (13)
In: N00 - COO
Type - PredefinedType: STANDARD; Material: Plastique, blanc opaque 0.2 cm, 00 - Isolant cloison Frigo 5.6 cm, Plastique, blanc opaque 0.2 cm
Type - Pset_QuantityTakeOff - Reference: 06 - cloisons - cuisine 6cm
Type - Pset_ReinforcementBarPitchOfWall - Reference: 06 - cloisons - cuisine 6cm
Type - Pset_WallCommon - IsExternal: no; Reference: 06 - cloisons - cuisine 6cm; ThermalTransmittance: 82.75 kg/K/s3
Pset_QuantityTakeOff - sets with these values: 2
Pset_WallCommon - LoadBearing: no; ExtendToStructure: no
Name (Mur de base:06 - cloisons - cuisine 6cm:...)
452564
836870
837016
837051
1773024
1773173
1773340
1773415
1774600
1774718
1774844
1775015
1775090

# IfcWallStandardCase: Mur de base:06 - habillage Ba13, Mur de base:06 - habillage Ba13:1135254
In: N00 - COO
Type - PredefinedType: STANDARD; Material: 01 - Enduit/Plâtre 1.3 cm
Type - Pset_QuantityTakeOff - Reference: 06 - habillage Ba13
Type - Pset_ReinforcementBarPitchOfWall - Reference: 06 - habillage Ba13
Type - Pset_WallCommon - IsExternal: no; Reference: 06 - habillage Ba13; ThermalTransmittance: 50 kg/K/s3
Pset_QuantityTakeOff - sets with these values: 2
Pset_WallCommon - LoadBearing: no; ExtendToStructure: no

# IfcWallStandardCase: Mur de base:06 - habillage Ba13 collée 2cm (132)
Type - PredefinedType: STANDARD; Material: 01 - Enduit/Plâtre 1.3 cm, 00 - VIDE D'AIR 0.7 cm
Type - Pset_QuantityTakeOff - Reference: 06 - habillage Ba13 collée 2cm
Type - Pset_ReinforcementBarPitchOfWall - Reference: 06 - habillage Ba13 collée 2cm
Type - Pset_WallCommon - IsExternal: no; Reference: 06 - habillage Ba13 collée 2cm; ThermalTransmittance: 50 kg/K/s3
Pset_QuantityTakeOff - sets with these values: 2
Pset_WallCommon - LoadBearing: no
Name (Mur de base:06 - habillage Ba13 collée 2cm:...) | In | ExtendToStructure
317603 | N00 - COO | no
317700 | N00 - COO | no
556313 | Toiture - Cuisine | yes
563528 | Toiture - Cuisine | yes
567526 | Toiture - Cuisine | no
567760 | Toiture - Cuisine | no
568964 | Toiture - Cuisine | no
568981 | Toiture - Cuisine | yes
569204 | Toiture - Cuisine | yes
569667 | Toiture - Cuisine | yes
569708 | Toiture - Cuisine | yes
569748 | Toiture - Cuisine | yes
569782 | Toiture - Cuisine | yes
570393 | Toiture - Cuisine | yes
570545 | Toiture - Cuisine | yes
570738 | Toiture - Cuisine | yes
570739 | Toiture - Cuisine | yes
570846 | Toiture - Cuisine | yes
570847 | Toiture - Cuisine | yes
570904 | Toiture - Cuisine | yes
570905 | Toiture - Cuisine | yes
570923 | Toiture - Cuisine | yes
570924 | Toiture - Cuisine | yes
570947 | Toiture - Cuisine | yes
570948 | Toiture - Cuisine | yes
572044 | Toiture - Cuisine | yes
572136 | Toiture - Cuisine | yes
572239 | Toiture - Cuisine | yes
572492 | Toiture - Cuisine | yes
572577 | Toiture - Cuisine | yes
572672 | Toiture - Cuisine | yes
572752 | Toiture - Cuisine | yes
572818 | Toiture - Cuisine | yes
572878 | Toiture - Cuisine | yes
572946 | Toiture - Cuisine | yes
572989 | Toiture - Cuisine | yes
573083 | Toiture - Cuisine | yes
679628 | Toiture - Cuisine | yes
679717 | Toiture - Cuisine | yes
679918 | Toiture - Cuisine | yes
680420 | Toiture - Cuisine | yes
680421 | Toiture - Cuisine | yes
680422 | Toiture - Cuisine | yes
680517 | Toiture - Cuisine | yes
680518 | Toiture - Cuisine | yes
680519 | Toiture - Cuisine | yes
680727 | Toiture - Cuisine | yes
680728 | Toiture - Cuisine | yes
680729 | Toiture - Cuisine | yes
680832 | Toiture - Cuisine | yes
680833 | Toiture - Cuisine | yes
680834 | Toiture - Cuisine | yes
681040 | Toiture - Cuisine | yes
681041 | Toiture - Cuisine | yes
681042 | Toiture - Cuisine | yes
681214 | Toiture - Cuisine | yes
681215 | Toiture - Cuisine | yes
681216 | Toiture - Cuisine | yes
686444 | TR - N02 - ARCH | no
686445 | TR - N02 - ARCH | no
686446 | TR - N02 - ARCH | no
686449 | TR - N02 - ARCH | no
686450 | TR - N02 - ARCH | no
686451 | TR - N02 - ARCH | no
686452 | TR - N02 - ARCH | no
686453 | TR - N02 - ARCH | no
686454 | TR - N02 - ARCH | no
686455 | TR - N02 - ARCH | no
686456 | TR - N02 - ARCH | no
686457 | TR - N02 - ARCH | no
686458 | TR - N02 - ARCH | no
686459 | TR - N02 - ARCH | no
686460 | TR - N02 - ARCH | no
686461 | TR - N02 - ARCH | no
686462 | TR - N02 - ARCH | no
686463 | TR - N02 - ARCH | no
686467 | TR - N02 - ARCH | no
686468 | TR - N02 - ARCH | no
686469 | TR - N02 - ARCH | no
686470 | TR - N02 - ARCH | no
686471 | TR - N02 - ARCH | no
686472 | TR - N02 - ARCH | no
686477 | TR - N02 - ARCH | no
686478 | TR - N02 - ARCH | no
686479 | TR - N02 - ARCH | no
686480 | TR - N02 - ARCH | no
686481 | TR - N02 - ARCH | no
686482 | TR - N02 - ARCH | no
686483 | TR - N02 - ARCH | no
686484 | TR - N02 - ARCH | no
686485 | TR - N02 - ARCH | no
686487 | TR - N02 - ARCH | no
686488 | TR - N02 - ARCH | no
686489 | TR - N02 - ARCH | no
686491 | TR - N02 - ARCH | no
686492 | TR - N02 - ARCH | no
686493 | TR - N02 - ARCH | no
688595 | Toiture - Cuisine | yes
689869 | TR - N02 - ARCH | no
818538 | TR - N02 - ARCH | no
818626 | TR - N02 - ARCH | no | Group: Groupe de modèles:Fenêtre de toit:822798
818645 | TR - N02 - ARCH | no | Group: Groupe de modèles:Fenêtre de toit:822798
819277 | TR - N02 - ARCH | no | Group: Groupe de modèles:Fenêtre de toit:822798
819312 | TR - N02 - ARCH | no | Group: Groupe de modèles:Fenêtre de toit:822798
823167 | TR - N02 - ARCH | no
823168 | TR - N02 - ARCH | no
823169 | TR - N02 - ARCH | no
823170 | TR - N02 - ARCH | no
823716 | TR - N02 - ARCH | no | Group: Groupe de modèles:Fenêtre de toit:823720
823717 | TR - N02 - ARCH | no | Group: Groupe de modèles:Fenêtre de toit:823720
823718 | TR - N02 - ARCH | no | Group: Groupe de modèles:Fenêtre de toit:823720
823719 | TR - N02 - ARCH | no | Group: Groupe de modèles:Fenêtre de toit:823720
892626 | Toiture - Cuisine | no | Group: Groupe de modèles:Retours BA 13 SELF / VERRIERE 3 (membre exclu):893410
892693 | Toiture - Cuisine | no | Group: Groupe de modèles:Retours BA 13 SELF / VERRIERE 3 (membre exclu):893410
892772 | Toiture - Cuisine | no | Group: Groupe de modèles:Retours BA 13 SELF / VERRIERE 3 (membre exclu):893410
892829 | Toiture - Cuisine | no | Group: Groupe de modèles:Retours BA 13 SELF / VERRIERE 3 (membre exclu):893410
930107 | Toiture - Cuisine | no | Group: Groupe de modèles:Retours BA 13 SELF / VERRIERE (membre exclu):930111
930108 | Toiture - Cuisine | no | Group: Groupe de modèles:Retours BA 13 SELF / VERRIERE (membre exclu):930111
930109 | Toiture - Cuisine | no | Group: Groupe de modèles:Retours BA 13 SELF / VERRIERE (membre exclu):930111
930110 | Toiture - Cuisine | no | Group: Groupe de modèles:Retours BA 13 SELF / VERRIERE (membre exclu):930111
1035618 | N00 - COO | no
1069859 | N00 - COO | no
1244925 | TR - N02 - ARCH | no
1244996 | TR - N02 - ARCH | no
1271186 | TR - N02 - ARCH | no
1370502 | N00 - COO | yes
1529366 | TR - N02 - ARCH | no
1529635 | TR - N02 - ARCH | no
1671558 | Toiture - Cuisine | no | Group: Groupe de modèles:Retours BA 13 SELF / VERRIERE 2:1671562
1671559 | Toiture - Cuisine | no | Group: Groupe de modèles:Retours BA 13 SELF / VERRIERE 2:1671562
1671560 | Toiture - Cuisine | no | Group: Groupe de modèles:Retours BA 13 SELF / VERRIERE 2:1671562
1671561 | Toiture - Cuisine | no | Group: Groupe de modèles:Retours BA 13 SELF / VERRIERE 2:1671562

# IfcWallStandardCase: Mur de base:06 - habillage bois collée 2cm (23)
Type - PredefinedType: STANDARD; Material: Pin 2 cm
Type - Pset_QuantityTakeOff - Reference: 06 - habillage bois collée 2cm
Type - Pset_ReinforcementBarPitchOfWall - Reference: 06 - habillage bois collée 2cm
Type - Pset_WallCommon - IsExternal: no; Reference: 06 - habillage bois collée 2cm; ThermalTransmittance: 6 kg/K/s3
Pset_QuantityTakeOff - sets with these values: 2
Pset_WallCommon - LoadBearing: no; ExtendToStructure: no
Name (Mur de base:06 - habillage bois collée 2cm:...) | In
458189 | N00 - COO
458251 | N00 - COO
946532 | N00 - COO
946991 | N00 - COO
1010825 | N00 - COO
1011126 | N00 - COO
1011229 | N00 - COO
1119527 | N00 - COO
1343694 | N00 - COO
1344236 | N00 - COO
1439644 | N00 - COO
1439649 | N00 - COO
1491383 | Toiture - Cuisine
1491493 | Toiture - Cuisine
1491663 | TR - N02 - ARCH
1491664 | TR - N02 - ARCH
1491673 | N00 - COO
1491674 | N00 - COO
1491692 | TR - N02 - ARCH
1491885 | TR - N02 - ARCH
1781248 | N00 - COO
1781426 | N00 - COO
1786937 | N00 - COO

# IfcWallStandardCase: Mur de base:06 - habillage bois collée 2cm perforé (16)
Type - PredefinedType: STANDARD; Material: CP bouleau perforé 2 cm
Type - Pset_QuantityTakeOff - Reference: 06 - habillage bois collée 2cm perforé
Type - Pset_ReinforcementBarPitchOfWall - Reference: 06 - habillage bois collée 2cm perforé
Type - Pset_WallCommon - IsExternal: no; Reference: 06 - habillage bois collée 2cm perforé; ThermalTransmittance: 6 kg/K/s3
Pset_QuantityTakeOff - sets with these values: 2
Pset_WallCommon - LoadBearing: no; ExtendToStructure: no
Name (Mur de base:06 - habillage bois collée 2cm perforé:...) | In
1096764 | N00 - COO
1120562 | N00 - COO
1120744 | N00 - COO
1120855 | N00 - COO
1121039 | N00 - COO
1121130 | N00 - COO
1121184 | N00 - COO
1121285 | N00 - COO
1197842 | N00 - COO
1197995 | N00 - COO
1198056 | N00 - COO
1198664 | N00 - COO
1198858 | N00 - COO
1281526 | Toiture - Cuisine
1654956 | N00 - COO
1655571 | N00 - COO

# IfcWallStandardCase: Mur de base:07 - mur rideau remplissage grillage (4)
Type - PredefinedType: STANDARD; Material: Métal déployé grillage 1 cm
Type - Pset_QuantityTakeOff - Reference: 07 - mur rideau remplissage grillage
Type - Pset_ReinforcementBarPitchOfWall - Reference: 07 - mur rideau remplissage grillage
Type - Pset_WallCommon - IsExternal: no; Reference: 07 - mur rideau remplissage grillage
Pset_QuantityTakeOff - sets with these values: 2
Pset_WallCommon - LoadBearing: no; IsExternal: yes; ExtendToStructure: no
Name (Mur de base:07 - mur rideau remplissage grillage:...) | In
562149 | TR - N02 - ARCH
1822357 | TR - N02 - ARCH
1822563 | Toiture - Cuisine
1823523 | Toiture - Cuisine

# IfcWallStandardCase: Mur de base:07 -Tôle alu Shadowbox (9)
Type - PredefinedType: STANDARD; Material: Métal déployé 0.3 cm, 00 - Isolant polystyrène 4 cm
Type - Pset_QuantityTakeOff - Reference: 07 -Tôle alu Shadowbox
Type - Pset_ReinforcementBarPitchOfWall - Reference: 07 -Tôle alu Shadowbox
Type - Pset_WallCommon - IsExternal: no; Reference: 07 -Tôle alu Shadowbox
Pset_QuantityTakeOff - sets with these values: 2
Pset_WallCommon - LoadBearing: no; IsExternal: yes
Name (Mur de base:07 -Tôle alu Shadowbox:...) | In | ExtendToStructure
1214243 | N00 - COO | yes
1300723 | Toiture - Cuisine | no
1319664 | Toiture - Cuisine | no
1319666 | Toiture - Cuisine | no
1319668 | Toiture - Cuisine | no
1319670 | Toiture - Cuisine | no
1322098 | Toiture - Cuisine | no
1322100 | Toiture - Cuisine | no
1322120 | TR - N02 - ARCH | no

# IfcWallStandardCase: Mur de base:07 -Tôle alu sur CP (9)
Type - PredefinedType: STANDARD; Material: Métal déployé 0.3 cm, Métal - Alu brossé 1.7 cm
Type - Pset_QuantityTakeOff - Reference: 07 -Tôle alu sur CP
Type - Pset_ReinforcementBarPitchOfWall - Reference: 07 -Tôle alu sur CP
Type - Pset_WallCommon - IsExternal: no; Reference: 07 -Tôle alu sur CP
Pset_QuantityTakeOff - sets with these values: 2
Pset_WallCommon - LoadBearing: no; IsExternal: yes
Name (Mur de base:07 -Tôle alu sur CP:...) | In | ExtendToStructure
1203514 | N00 - COO | yes
1300386 | Toiture - Cuisine | no
1319663 | Toiture - Cuisine | no
1319665 | Toiture - Cuisine | no
1319667 | Toiture - Cuisine | no
1319669 | Toiture - Cuisine | no
1322097 | Toiture - Cuisine | no
1322099 | Toiture - Cuisine | no
1322122 | TR - N02 - ARCH | no

# IfcWallStandardCase: Mur de base:clôture (13)
In: N00 - COO
Type - PredefinedType: STANDARD; Material: Métal déployé grillage 1 cm
Type - Pset_QuantityTakeOff - Reference: clôture
Type - Pset_ReinforcementBarPitchOfWall - Reference: clôture
Type - Pset_WallCommon - IsExternal: no; Reference: clôture
Pset_QuantityTakeOff - sets with these values: 2
Pset_WallCommon - LoadBearing: no; IsExternal: yes; ExtendToStructure: no
Name (Mur de base:clôture:...)
1705622
1705752
1705797
1705825
1705923
1705956
1705983
1706022
1706041
1706101
1706125
1706185
1764027

# IfcWindow: Ouvrant POMPIERS Facade nord (140cm) (5)
In: TR - N02 - ARCH
Type - ParameterTakesPrecedence: no; Sizeable: no; Material: Verre, Aluminium
OverallHeight: 236 cm; OverallWidth: 133.5 cm
Pset_QuantityTakeOff - Reference: Ouvrant POMPIERS Facade nord (140cm)
Pset_WindowCommon - IsExternal: yes; Reference: Ouvrant POMPIERS Facade nord (140cm)
Name (Ouvrant vitré:Ouvrant POMPIERS Facade nord (140cm):...)
1130308
1130395
1130587
1130879
1132216

# IfcWindow: Ouvrant R+1 - 140 (36)
In: Toiture - Cuisine
Type - ParameterTakesPrecedence: no; Sizeable: no; Material: Verre, Aluminium
OverallHeight: 229.262 cm
Pset_QuantityTakeOff - Reference: Ouvrant R+1 - 140
Pset_WindowCommon - IsExternal: no; Reference: Ouvrant R+1 - 140
Name (Ouvrant vitré RDC toute hauteur.0023:Ouvrant R+1 - 140:...) | OverallWidth (cm)
526617 | 138.262
526623 | 138.262
526627 | 138.262
526633 | 138.262
526639 | 138.262
526645 | 138.262
526649 | 138.262
526655 | 138.262
526663 | 138.262
526669 | 138.262
526673 | 138.262
526679 | 138.262
528097 | 138.262
528103 | 138.262
528107 | 138.262
528115 | 138.262
528121 | 138.262
528127 | 138.262
528131 | 138.262
528137 | 138.262
577788 | 138.262
577792 | 138.262
577798 | 138.262
577802 | 138.262
577806 | 138.262
577814 | 138.262
577820 | 138.262
577828 | 138.262
577832 | 138.262
577838 | 138.262
577844 | 138.263
580556 | 138
580563 | 138.262
580571 | 138.262
580577 | 138.262
580581 | 138.262

# IfcWindow: Ouvrant Rdc - 70 (2)
In: N00 - COO
Type - ParameterTakesPrecedence: no; Sizeable: no; Material: Verre, Aluminium
OverallHeight: 304.762 cm; OverallWidth: 85.0125 cm
Pset_QuantityTakeOff - Reference: Ouvrant Rdc - 70
Pset_WindowCommon - IsExternal: no; Reference: Ouvrant Rdc - 70
Name (Ouvrant vitré RDC toute hauteur.0023:Ouvrant Rdc - 70:...)
584300
1337335

# IfcWindow: Ouvrant vitré (70cm) (42)
In: TR - N02 - ARCH
Type - ParameterTakesPrecedence: no; Sizeable: no; Material: Verre, Aluminium
OverallHeight: 236 cm; OverallWidth: 68 cm
Pset_QuantityTakeOff - Reference: Ouvrant vitré (70cm)
Pset_WindowCommon - IsExternal: yes; Reference: Ouvrant vitré (70cm)
Name (Ouvrant vitré:Ouvrant vitré (70cm):...)
1129847
1129976
1130029
1130309
1130310
1130586
1130588
1130694
1130695
1130696
1130811
1130935
1131007
1131068
1131340
1131341
1131430
1131495
1132439
1132524
1132672
1132801
1133017
1133115
1133174
1133254
1133483
1133553
1133619
1133745
1133828
1133891
1134050
1134112
1134168
1134221
1134287
1134288
1134289
1134290
1134291
1134436

# IfcWindow: Ouvrant vitré (87cm) (3)
In: N00 - COO
Type - ParameterTakesPrecedence: no; Sizeable: no; Material: Verre, Aluminium
OverallHeight: 224 cm; OverallWidth: 92 cm
Pset_QuantityTakeOff - Reference: Ouvrant vitré (87cm)
Pset_WindowCommon - IsExternal: yes; Reference: Ouvrant vitré (87cm)
Name (Ouvrant vitré:Ouvrant vitré (87cm):...)
1160667
1162016
1162076

# IfcWindow: Ouvrant vitré (90cm) RDC (26)
In: N00 - COO
Type - ParameterTakesPrecedence: no; Sizeable: no; Material: Verre, Aluminium
OverallHeight: 299.5 cm; OverallWidth: 83.5 cm
Pset_QuantityTakeOff - Reference: Ouvrant vitré (90cm) RDC
Pset_WindowCommon - IsExternal: yes; Reference: Ouvrant vitré (90cm) RDC
Name (Ouvrant vitré:Ouvrant vitré (90cm) RDC:...)
1141371
1141402
1141476
1169693
1169887
1169970
1171731
1185088
1185099
1185106
1185112
1185131
1185139
1185146
1185153
1185163
1185212
1185218
1185224
1185230
1185236
1185248
1185261
1195983
1195992
1195999

# IfcWindow: Ouvrant vitré (93cm) RDC (7)
In: N00 - COO
Type - ParameterTakesPrecedence: no; Sizeable: no; Material: Verre, Aluminium
OverallHeight: 299.5 cm; OverallWidth: 87 cm
Pset_QuantityTakeOff - Reference: Ouvrant vitré (93cm) RDC
Pset_WindowCommon - IsExternal: yes; Reference: Ouvrant vitré (93cm) RDC
Name (Ouvrant vitré:Ouvrant vitré (93cm) RDC:...)
1157167
1159285
1159811
1159853
1159869
1330168
1330227

# IfcWindow: Ouvrant vitré 175mm, Ouvrant vitré:Ouvrant vitré 175mm:1719054
In: N00 - COO
Type - ParameterTakesPrecedence: no; Sizeable: no; Material: Verre, Aluminium
OverallHeight: 175 cm; OverallWidth: 68 cm
Pset_QuantityTakeOff - Reference: Ouvrant vitré 175mm
Pset_WindowCommon - IsExternal: yes; Reference: Ouvrant vitré 175mm

# IfcWindow: Ouvrant vitré RDC façade sud.0005 (5)
In: N00 - COO
Type - ParameterTakesPrecedence: no; Sizeable: no; Material: Verre, Aluminium
OverallHeight: 301.882 cm; OverallWidth: 138.262 cm
Pset_QuantityTakeOff - Reference: Ouvrant vitré RDC façade sud.0005
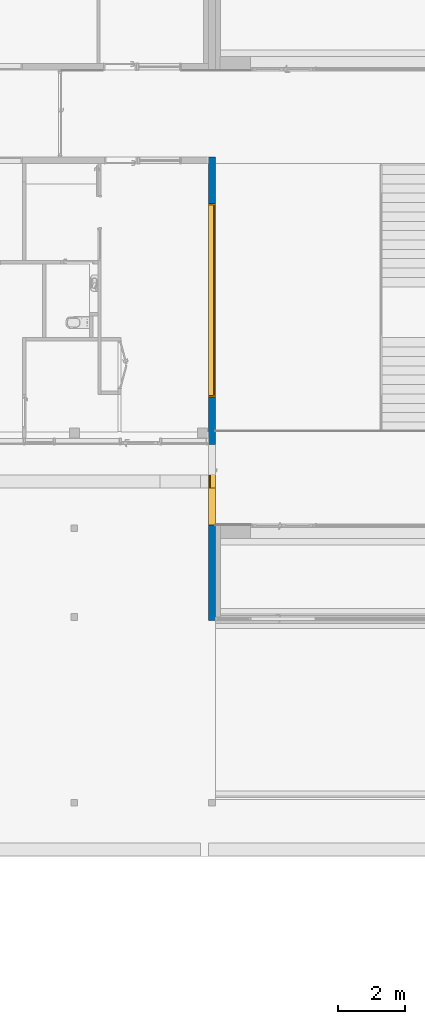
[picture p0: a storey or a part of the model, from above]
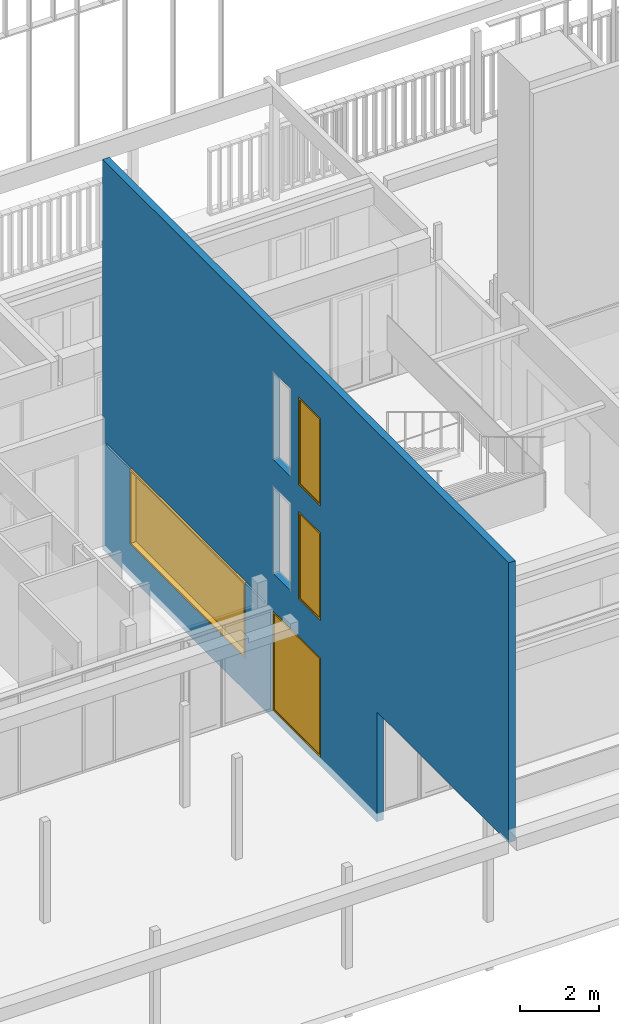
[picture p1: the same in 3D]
Properties of the parts of a building model (IFC2X3), part 7 of 7

# IfcWindow: Ouvrant vitré RDC façade sud.0005 (5)
Pset_WindowCommon - IsExternal: no; Reference: Ouvrant vitré RDC façade sud.0005
Name (Ouvrant vitré RDC façade sud.0005:Ouvrant vitré RDC façade sud.0005:...)
1204471
1204467
1204463
1204455
578662

# IfcWindow: R+1 - Pignon - châssis intérieur vitré (2,70m) (8)
Type - ParameterTakesPrecedence: no; Sizeable: no; Material: Verre, huisserie bois
OverallHeight: 270 cm
Pset_QuantityTakeOff - Reference: R+1 - Pignon - châssis intérieur vitré (2,70m)
Pset_WindowCommon - IsExternal: yes; Reference: R+1 - Pignon - châssis intérieur vitré (2,70m)
Name (châssis intérieur vitré:R+1 - Pignon - châssis intérieur vitré (2,70m):...) | In | OverallWidth (cm)
555970 | Toiture - Cuisine | 110.034
556073 | TR - N02 - ARCH | 110.034
685541 | Toiture - Cuisine | 239.951
686131 | Toiture - Cuisine | 260.078
688942 | TR - N02 - ARCH | 260
710415 | TR - N02 - ARCH | 239.951
734198 | Toiture - Cuisine | 259.951
734204 | TR - N02 - ARCH | 259.951

# IfcWindow: RDC - Pignon - châssis intérieur vitré (3.11m) (5)
In: N00 - COO
Type - ParameterTakesPrecedence: no; Sizeable: no; Material: Verre, huisserie bois
OverallHeight: 306 cm
Pset_QuantityTakeOff - Reference: RDC - Pignon - châssis intérieur vitré (3.11m)
Pset_WindowCommon - Reference: RDC - Pignon - châssis intérieur vitré (3.11m)
Name (châssis intérieur vitré:RDC - Pignon - châssis intérieur vitré (3.11m):...) | OverallWidth (cm) | IsExternal
555884 | 240.078 | yes
711633 | 239.951 | yes
734211 | 225.951 | yes
938319 | 364.2 | no
1969216 | 67.0078 | no

# IfcWindow: SR_Fenêtre de toit sur escaliers (3)
In: TR - N03 - ARCH
Type - ParameterTakesPrecedence: no; Sizeable: no; Classification: B3020110 Skylights (Uniformat); Material: VELUX Aluminium, Skylight White, Skylight Composite, Skylight Hard Insulation, Skylight Aluminium, Glass, Skylight Flashing, Roof Material, Plaster
OverallHeight: 179.964 cm; OverallWidth: 492 cm
Pset_ManufacturerTypeInformation - Manufacturer: VELUX A/S
Pset_QuantityTakeOff - Reference: SR_Fenêtre de toit sur escaliers
Pset_WindowCommon - IsExternal: no; Reference: SR_Fenêtre de toit sur escaliers; ThermalTransmittance: 1.4 kg/K/s3
Name (Longlight_Integrated:SR_Fenêtre de toit sur escaliers:...) | Group
535467 | Groupe de modèles:Fenêtre de toit:822798
823166
823715 | Groupe de modèles:Fenêtre de toit:823720

# IfcWindow: châssis intérieur vitré (h=170) (4)
In: N00 - COO
Type - ParameterTakesPrecedence: no; Sizeable: no; Material: Verre, huisserie bois
OverallHeight: 170 cm
Pset_QuantityTakeOff - Reference: châssis intérieur vitré (h=170)
Pset_WindowCommon - IsExternal: no; Reference: châssis intérieur vitré (h=170)
Name (châssis intérieur vitré:châssis intérieur vitré (h=170):...) | OverallWidth (cm)
1777326 | 160.918
1904895 | 95
1997358 | 212
1997416 | 212

# IfcWindow: châssis intérieur vitré (h=270) R+1 (37)
Type - ParameterTakesPrecedence: no; Sizeable: no; Material: Verre, huisserie bois
OverallHeight: 250 cm
Pset_QuantityTakeOff - Reference: châssis intérieur vitré (h=270) R+1
Pset_WindowCommon - IsExternal: yes; Reference: châssis intérieur vitré (h=270) R+1
Name (châssis intérieur vitré:châssis intérieur vitré (h=270) R+1:...) | In | OverallWidth (cm)
510228 | Toiture - Cuisine | 100
510271 | Toiture - Cuisine | 100
514636 | Toiture - Cuisine | 100
514675 | Toiture - Cuisine | 100
514703 | Toiture - Cuisine | 100
514742 | Toiture - Cuisine | 100
514770 | Toiture - Cuisine | 100
518503 | Toiture - Cuisine | 90
518532 | Toiture - Cuisine | 90
518551 | Toiture - Cuisine | 90
518585 | Toiture - Cuisine | 90
518625 | Toiture - Cuisine | 90
519963 | Toiture - Cuisine | 100
519994 | Toiture - Cuisine | 100
520030 | Toiture - Cuisine | 100
520066 | Toiture - Cuisine | 100
527151 | TR - N02 - ARCH | 100
527152 | TR - N02 - ARCH | 100
527195 | TR - N02 - ARCH | 100
527196 | TR - N02 - ARCH | 100
527197 | TR - N02 - ARCH | 100
527198 | TR - N02 - ARCH | 100
527199 | TR - N02 - ARCH | 100
527200 | TR - N02 - ARCH | 100
527201 | TR - N02 - ARCH | 100
532140 | TR - N02 - ARCH | 100
532170 | TR - N02 - ARCH | 100
532194 | TR - N02 - ARCH | 100
532211 | TR - N02 - ARCH | 100
532228 | TR - N02 - ARCH | 100
532253 | TR - N02 - ARCH | 100
532281 | TR - N02 - ARCH | 100
533204 | TR - N02 - ARCH | 100
533245 | TR - N02 - ARCH | 100
533276 | TR - N02 - ARCH | 100
533296 | TR - N02 - ARCH | 100
938681 | Toiture - Cuisine | 91.5

# IfcWindow: châssis intérieur vitré (h=306) (9)
In: N00 - COO
Type - ParameterTakesPrecedence: no; Sizeable: no; Material: Verre, huisserie bois
OverallHeight: 306 cm
Pset_QuantityTakeOff - Reference: châssis intérieur vitré (h=306)
Pset_WindowCommon - Reference: châssis intérieur vitré (h=306)
Name (châssis intérieur vitré:châssis intérieur vitré (h=306):...) | OverallWidth (cm) | IsExternal
366086 | 186.512 | yes
375079 | 530 | yes
393830 | 145.8 | yes
398419 | 305 | yes
430494 | 130 | yes
430523 | 205 | yes
937897 | 156.648 | yes
1997249 | 212 | yes
1998674 | 302.863 | no

# IfcWindow: châssis intérieur vitré bureau asen, châssis intérieur vitré:châssis intérieur vitré bureau asen:894344
In: N00 - COO
Type - ParameterTakesPrecedence: no; Sizeable: no; Material: Verre, huisserie bois
OverallHeight: 231 cm; OverallWidth: 579.226 cm
Pset_QuantityTakeOff - Reference: châssis intérieur vitré bureau asen
Pset_WindowCommon - IsExternal: yes; Reference: châssis intérieur vitré bureau asen

# IfcWindow: châssis intérieur vitré self (h=2.22) 2 (2)
In: N00 - COO
Type - ParameterTakesPrecedence: no; Sizeable: no; Material: Verre, huisserie bois
OverallHeight: 170 cm
Pset_QuantityTakeOff - Reference: châssis intérieur vitré self (h=2.22) 2
Pset_WindowCommon - Reference: châssis intérieur vitré self (h=2.22) 2
Name (châssis intérieur vitré:châssis intérieur vitré self (h=2.22) 2:...) | OverallWidth (cm) | IsExternal
459594 | 315.693 | no
2074709 | 279.965 | yes
